VERSION 5.8 ;
BUSBITCHARS "[]" ;
DIVIDERCHAR "/" ;
UNITS
    DATABASE MICRONS 1000 ;
END UNITS

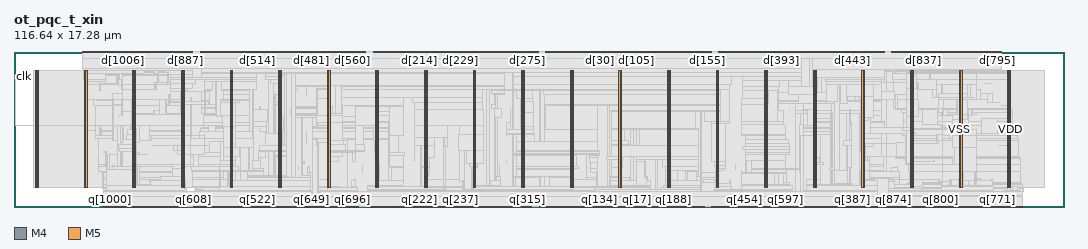
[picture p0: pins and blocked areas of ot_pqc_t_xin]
MACRO ot_pqc_t_xin
  FOREIGN ot_pqc_t_xin 0 0 ;
  CLASS BLOCK ;
  SIZE 116.64 BY 17.28 ;
  PIN clk
    DIRECTION INPUT ;
    USE SIGNAL ;
    PORT
      LAYER M4 ;
        RECT  0 14.448 0.084 14.472 ;
    END
    PORT
      LAYER M4 ;
        RECT  0.06 14.448 0.227 14.472 ;
    END
  END clk
  PIN d[0]
    DIRECTION INPUT ;
    USE SIGNAL ;
    PORT
      LAYER M5 ;
        RECT  62.16 17.196 62.184 17.28 ;
    END
  END d[0]
  PIN d[1000]
    DIRECTION INPUT ;
    USE SIGNAL ;
    PORT
      LAYER M5 ;
        RECT  11.472 17.196 11.496 17.28 ;
    END
  END d[1000]
  PIN d[1001]
    DIRECTION INPUT ;
    USE SIGNAL ;
    PORT
      LAYER M5 ;
        RECT  11.568 17.196 11.592 17.28 ;
    END
  END d[1001]
  PIN d[1002]
    DIRECTION INPUT ;
    USE SIGNAL ;
    PORT
      LAYER M5 ;
        RECT  11.664 17.196 11.688 17.28 ;
    END
  END d[1002]
  PIN d[1003]
    DIRECTION INPUT ;
    USE SIGNAL ;
    PORT
      LAYER M5 ;
        RECT  11.76 17.196 11.784 17.28 ;
    END
  END d[1003]
  PIN d[1004]
    DIRECTION INPUT ;
    USE SIGNAL ;
    PORT
      LAYER M5 ;
        RECT  11.856 17.196 11.88 17.28 ;
    END
  END d[1004]
  PIN d[1005]
    DIRECTION INPUT ;
    USE SIGNAL ;
    PORT
      LAYER M5 ;
        RECT  11.952 17.196 11.976 17.28 ;
    END
  END d[1005]
  PIN d[1006]
    DIRECTION INPUT ;
    USE SIGNAL ;
    PORT
      LAYER M5 ;
        RECT  12.048 17.196 12.072 17.28 ;
    END
  END d[1006]
  PIN d[1007]
    DIRECTION INPUT ;
    USE SIGNAL ;
    PORT
      LAYER M5 ;
        RECT  12.144 17.196 12.168 17.28 ;
    END
  END d[1007]
  PIN d[1008]
    DIRECTION INPUT ;
    USE SIGNAL ;
    PORT
      LAYER M5 ;
        RECT  12.24 17.196 12.264 17.28 ;
    END
  END d[1008]
  PIN d[1009]
    DIRECTION INPUT ;
    USE SIGNAL ;
    PORT
      LAYER M5 ;
        RECT  12.336 17.196 12.36 17.28 ;
    END
  END d[1009]
  PIN d[100]
    DIRECTION INPUT ;
    USE SIGNAL ;
    PORT
      LAYER M5 ;
        RECT  68.688 17.196 68.712 17.28 ;
    END
  END d[100]
  PIN d[1010]
    DIRECTION INPUT ;
    USE SIGNAL ;
    PORT
      LAYER M5 ;
        RECT  12.432 17.196 12.456 17.28 ;
    END
  END d[1010]
  PIN d[1011]
    DIRECTION INPUT ;
    USE SIGNAL ;
    PORT
      LAYER M5 ;
        RECT  12.528 17.196 12.552 17.28 ;
    END
  END d[1011]
  PIN d[1012]
    DIRECTION INPUT ;
    USE SIGNAL ;
    PORT
      LAYER M5 ;
        RECT  12.624 17.196 12.648 17.28 ;
    END
  END d[1012]
  PIN d[1013]
    DIRECTION INPUT ;
    USE SIGNAL ;
    PORT
      LAYER M5 ;
        RECT  12.72 17.196 12.744 17.28 ;
    END
  END d[1013]
  PIN d[1014]
    DIRECTION INPUT ;
    USE SIGNAL ;
    PORT
      LAYER M5 ;
        RECT  12.816 17.196 12.84 17.28 ;
    END
  END d[1014]
  PIN d[1015]
    DIRECTION INPUT ;
    USE SIGNAL ;
    PORT
      LAYER M5 ;
        RECT  12.912 17.196 12.936 17.28 ;
    END
  END d[1015]
  PIN d[1016]
    DIRECTION INPUT ;
    USE SIGNAL ;
    PORT
      LAYER M5 ;
        RECT  13.008 17.196 13.032 17.28 ;
    END
  END d[1016]
  PIN d[1017]
    DIRECTION INPUT ;
    USE SIGNAL ;
    PORT
      LAYER M5 ;
        RECT  13.104 17.196 13.128 17.28 ;
    END
  END d[1017]
  PIN d[1018]
    DIRECTION INPUT ;
    USE SIGNAL ;
    PORT
      LAYER M5 ;
        RECT  13.2 17.196 13.224 17.28 ;
    END
  END d[1018]
  PIN d[1019]
    DIRECTION INPUT ;
    USE SIGNAL ;
    PORT
      LAYER M5 ;
        RECT  13.296 17.196 13.32 17.28 ;
    END
  END d[1019]
  PIN d[101]
    DIRECTION INPUT ;
    USE SIGNAL ;
    PORT
      LAYER M5 ;
        RECT  68.784 17.196 68.808 17.28 ;
    END
  END d[101]
  PIN d[1020]
    DIRECTION INPUT ;
    USE SIGNAL ;
    PORT
      LAYER M5 ;
        RECT  13.392 17.196 13.416 17.28 ;
    END
  END d[1020]
  PIN d[1021]
    DIRECTION INPUT ;
    USE SIGNAL ;
    PORT
      LAYER M5 ;
        RECT  13.488 17.196 13.512 17.28 ;
    END
  END d[1021]
  PIN d[1022]
    DIRECTION INPUT ;
    USE SIGNAL ;
    PORT
      LAYER M5 ;
        RECT  13.584 17.196 13.608 17.28 ;
    END
  END d[1022]
  PIN d[1023]
    DIRECTION INPUT ;
    USE SIGNAL ;
    PORT
      LAYER M5 ;
        RECT  13.68 17.196 13.704 17.28 ;
    END
  END d[1023]
  PIN d[102]
    DIRECTION INPUT ;
    USE SIGNAL ;
    PORT
      LAYER M5 ;
        RECT  68.88 17.196 68.904 17.28 ;
    END
  END d[102]
  PIN d[103]
    DIRECTION INPUT ;
    USE SIGNAL ;
    PORT
      LAYER M5 ;
        RECT  68.976 17.196 69 17.28 ;
    END
  END d[103]
  PIN d[104]
    DIRECTION INPUT ;
    USE SIGNAL ;
    PORT
      LAYER M5 ;
        RECT  69.072 17.196 69.096 17.28 ;
    END
  END d[104]
  PIN d[105]
    DIRECTION INPUT ;
    USE SIGNAL ;
    PORT
      LAYER M5 ;
        RECT  69.168 17.196 69.192 17.28 ;
    END
  END d[105]
  PIN d[106]
    DIRECTION INPUT ;
    USE SIGNAL ;
    PORT
      LAYER M5 ;
        RECT  69.264 17.196 69.288 17.28 ;
    END
  END d[106]
  PIN d[107]
    DIRECTION INPUT ;
    USE SIGNAL ;
    PORT
      LAYER M5 ;
        RECT  69.36 17.196 69.384 17.28 ;
    END
  END d[107]
  PIN d[108]
    DIRECTION INPUT ;
    USE SIGNAL ;
    PORT
      LAYER M5 ;
        RECT  69.456 17.196 69.48 17.28 ;
    END
  END d[108]
  PIN d[109]
    DIRECTION INPUT ;
    USE SIGNAL ;
    PORT
      LAYER M5 ;
        RECT  69.552 17.196 69.576 17.28 ;
    END
  END d[109]
  PIN d[10]
    DIRECTION INPUT ;
    USE SIGNAL ;
    PORT
      LAYER M5 ;
        RECT  63.12 17.196 63.144 17.28 ;
    END
  END d[10]
  PIN d[110]
    DIRECTION INPUT ;
    USE SIGNAL ;
    PORT
      LAYER M5 ;
        RECT  69.648 17.196 69.672 17.28 ;
    END
  END d[110]
  PIN d[111]
    DIRECTION INPUT ;
    USE SIGNAL ;
    PORT
      LAYER M5 ;
        RECT  69.744 17.196 69.768 17.28 ;
    END
  END d[111]
  PIN d[112]
    DIRECTION INPUT ;
    USE SIGNAL ;
    PORT
      LAYER M5 ;
        RECT  69.84 17.196 69.864 17.28 ;
    END
  END d[112]
  PIN d[113]
    DIRECTION INPUT ;
    USE SIGNAL ;
    PORT
      LAYER M5 ;
        RECT  69.936 17.196 69.96 17.28 ;
    END
  END d[113]
  PIN d[114]
    DIRECTION INPUT ;
    USE SIGNAL ;
    PORT
      LAYER M5 ;
        RECT  70.032 17.196 70.056 17.28 ;
    END
  END d[114]
  PIN d[115]
    DIRECTION INPUT ;
    USE SIGNAL ;
    PORT
      LAYER M5 ;
        RECT  70.128 17.196 70.152 17.28 ;
    END
  END d[115]
  PIN d[116]
    DIRECTION INPUT ;
    USE SIGNAL ;
    PORT
      LAYER M5 ;
        RECT  70.224 17.196 70.248 17.28 ;
    END
  END d[116]
  PIN d[117]
    DIRECTION INPUT ;
    USE SIGNAL ;
    PORT
      LAYER M5 ;
        RECT  70.32 17.196 70.344 17.28 ;
    END
  END d[117]
  PIN d[118]
    DIRECTION INPUT ;
    USE SIGNAL ;
    PORT
      LAYER M5 ;
        RECT  70.416 17.196 70.44 17.28 ;
    END
  END d[118]
  PIN d[119]
    DIRECTION INPUT ;
    USE SIGNAL ;
    PORT
      LAYER M5 ;
        RECT  70.512 17.196 70.536 17.28 ;
    END
  END d[119]
  PIN d[11]
    DIRECTION INPUT ;
    USE SIGNAL ;
    PORT
      LAYER M5 ;
        RECT  63.216 17.196 63.24 17.28 ;
    END
  END d[11]
  PIN d[120]
    DIRECTION INPUT ;
    USE SIGNAL ;
    PORT
      LAYER M5 ;
        RECT  70.608 17.196 70.632 17.28 ;
    END
  END d[120]
  PIN d[121]
    DIRECTION INPUT ;
    USE SIGNAL ;
    PORT
      LAYER M5 ;
        RECT  70.704 17.196 70.728 17.28 ;
    END
  END d[121]
  PIN d[122]
    DIRECTION INPUT ;
    USE SIGNAL ;
    PORT
      LAYER M5 ;
        RECT  70.8 17.196 70.824 17.28 ;
    END
  END d[122]
  PIN d[123]
    DIRECTION INPUT ;
    USE SIGNAL ;
    PORT
      LAYER M5 ;
        RECT  70.896 17.196 70.92 17.28 ;
    END
  END d[123]
  PIN d[124]
    DIRECTION INPUT ;
    USE SIGNAL ;
    PORT
      LAYER M5 ;
        RECT  70.992 17.196 71.016 17.28 ;
    END
  END d[124]
  PIN d[125]
    DIRECTION INPUT ;
    USE SIGNAL ;
    PORT
      LAYER M5 ;
        RECT  71.088 17.196 71.112 17.28 ;
    END
  END d[125]
  PIN d[126]
    DIRECTION INPUT ;
    USE SIGNAL ;
    PORT
      LAYER M5 ;
        RECT  71.184 17.196 71.208 17.28 ;
    END
  END d[126]
  PIN d[127]
    DIRECTION INPUT ;
    USE SIGNAL ;
    PORT
      LAYER M5 ;
        RECT  71.28 17.196 71.304 17.28 ;
    END
  END d[127]
  PIN d[128]
    DIRECTION INPUT ;
    USE SIGNAL ;
    PORT
      LAYER M5 ;
        RECT  74.448 17.196 74.472 17.28 ;
    END
  END d[128]
  PIN d[129]
    DIRECTION INPUT ;
    USE SIGNAL ;
    PORT
      LAYER M5 ;
        RECT  74.544 17.196 74.568 17.28 ;
    END
  END d[129]
  PIN d[12]
    DIRECTION INPUT ;
    USE SIGNAL ;
    PORT
      LAYER M5 ;
        RECT  63.312 17.196 63.336 17.28 ;
    END
  END d[12]
  PIN d[130]
    DIRECTION INPUT ;
    USE SIGNAL ;
    PORT
      LAYER M5 ;
        RECT  74.64 17.196 74.664 17.28 ;
    END
  END d[130]
  PIN d[131]
    DIRECTION INPUT ;
    USE SIGNAL ;
    PORT
      LAYER M5 ;
        RECT  74.736 17.196 74.76 17.28 ;
    END
  END d[131]
  PIN d[132]
    DIRECTION INPUT ;
    USE SIGNAL ;
    PORT
      LAYER M5 ;
        RECT  74.832 17.196 74.856 17.28 ;
    END
  END d[132]
  PIN d[133]
    DIRECTION INPUT ;
    USE SIGNAL ;
    PORT
      LAYER M5 ;
        RECT  74.928 17.196 74.952 17.28 ;
    END
  END d[133]
  PIN d[134]
    DIRECTION INPUT ;
    USE SIGNAL ;
    PORT
      LAYER M5 ;
        RECT  75.024 17.196 75.048 17.28 ;
    END
  END d[134]
  PIN d[135]
    DIRECTION INPUT ;
    USE SIGNAL ;
    PORT
      LAYER M5 ;
        RECT  75.12 17.196 75.144 17.28 ;
    END
  END d[135]
  PIN d[136]
    DIRECTION INPUT ;
    USE SIGNAL ;
    PORT
      LAYER M5 ;
        RECT  75.216 17.196 75.24 17.28 ;
    END
  END d[136]
  PIN d[137]
    DIRECTION INPUT ;
    USE SIGNAL ;
    PORT
      LAYER M5 ;
        RECT  75.312 17.196 75.336 17.28 ;
    END
  END d[137]
  PIN d[138]
    DIRECTION INPUT ;
    USE SIGNAL ;
    PORT
      LAYER M5 ;
        RECT  75.408 17.196 75.432 17.28 ;
    END
  END d[138]
  PIN d[139]
    DIRECTION INPUT ;
    USE SIGNAL ;
    PORT
      LAYER M5 ;
        RECT  75.504 17.196 75.528 17.28 ;
    END
  END d[139]
  PIN d[13]
    DIRECTION INPUT ;
    USE SIGNAL ;
    PORT
      LAYER M5 ;
        RECT  63.408 17.196 63.432 17.28 ;
    END
  END d[13]
  PIN d[140]
    DIRECTION INPUT ;
    USE SIGNAL ;
    PORT
      LAYER M5 ;
        RECT  75.6 17.196 75.624 17.28 ;
    END
  END d[140]
  PIN d[141]
    DIRECTION INPUT ;
    USE SIGNAL ;
    PORT
      LAYER M5 ;
        RECT  75.696 17.196 75.72 17.28 ;
    END
  END d[141]
  PIN d[142]
    DIRECTION INPUT ;
    USE SIGNAL ;
    PORT
      LAYER M5 ;
        RECT  75.792 17.196 75.816 17.28 ;
    END
  END d[142]
  PIN d[143]
    DIRECTION INPUT ;
    USE SIGNAL ;
    PORT
      LAYER M5 ;
        RECT  75.888 17.196 75.912 17.28 ;
    END
  END d[143]
  PIN d[144]
    DIRECTION INPUT ;
    USE SIGNAL ;
    PORT
      LAYER M5 ;
        RECT  75.984 17.196 76.008 17.28 ;
    END
  END d[144]
  PIN d[145]
    DIRECTION INPUT ;
    USE SIGNAL ;
    PORT
      LAYER M5 ;
        RECT  76.08 17.196 76.104 17.28 ;
    END
  END d[145]
  PIN d[146]
    DIRECTION INPUT ;
    USE SIGNAL ;
    PORT
      LAYER M5 ;
        RECT  76.176 17.196 76.2 17.28 ;
    END
  END d[146]
  PIN d[147]
    DIRECTION INPUT ;
    USE SIGNAL ;
    PORT
      LAYER M5 ;
        RECT  76.272 17.196 76.296 17.28 ;
    END
  END d[147]
  PIN d[148]
    DIRECTION INPUT ;
    USE SIGNAL ;
    PORT
      LAYER M5 ;
        RECT  76.368 17.196 76.392 17.28 ;
    END
  END d[148]
  PIN d[149]
    DIRECTION INPUT ;
    USE SIGNAL ;
    PORT
      LAYER M5 ;
        RECT  76.464 17.196 76.488 17.28 ;
    END
  END d[149]
  PIN d[14]
    DIRECTION INPUT ;
    USE SIGNAL ;
    PORT
      LAYER M5 ;
        RECT  63.504 17.196 63.528 17.28 ;
    END
  END d[14]
  PIN d[150]
    DIRECTION INPUT ;
    USE SIGNAL ;
    PORT
      LAYER M5 ;
        RECT  76.56 17.196 76.584 17.28 ;
    END
  END d[150]
  PIN d[151]
    DIRECTION INPUT ;
    USE SIGNAL ;
    PORT
      LAYER M5 ;
        RECT  76.656 17.196 76.68 17.28 ;
    END
  END d[151]
  PIN d[152]
    DIRECTION INPUT ;
    USE SIGNAL ;
    PORT
      LAYER M5 ;
        RECT  76.752 17.196 76.776 17.28 ;
    END
  END d[152]
  PIN d[153]
    DIRECTION INPUT ;
    USE SIGNAL ;
    PORT
      LAYER M5 ;
        RECT  76.848 17.196 76.872 17.28 ;
    END
  END d[153]
  PIN d[154]
    DIRECTION INPUT ;
    USE SIGNAL ;
    PORT
      LAYER M5 ;
        RECT  76.944 17.196 76.968 17.28 ;
    END
  END d[154]
  PIN d[155]
    DIRECTION INPUT ;
    USE SIGNAL ;
    PORT
      LAYER M5 ;
        RECT  77.04 17.196 77.064 17.28 ;
    END
  END d[155]
  PIN d[156]
    DIRECTION INPUT ;
    USE SIGNAL ;
    PORT
      LAYER M5 ;
        RECT  77.136 17.196 77.16 17.28 ;
    END
  END d[156]
  PIN d[157]
    DIRECTION INPUT ;
    USE SIGNAL ;
    PORT
      LAYER M5 ;
        RECT  77.232 17.196 77.256 17.28 ;
    END
  END d[157]
  PIN d[158]
    DIRECTION INPUT ;
    USE SIGNAL ;
    PORT
      LAYER M5 ;
        RECT  77.328 17.196 77.352 17.28 ;
    END
  END d[158]
  PIN d[159]
    DIRECTION INPUT ;
    USE SIGNAL ;
    PORT
      LAYER M5 ;
        RECT  77.424 17.196 77.448 17.28 ;
    END
  END d[159]
  PIN d[15]
    DIRECTION INPUT ;
    USE SIGNAL ;
    PORT
      LAYER M5 ;
        RECT  63.6 17.196 63.624 17.28 ;
    END
  END d[15]
  PIN d[160]
    DIRECTION INPUT ;
    USE SIGNAL ;
    PORT
      LAYER M5 ;
        RECT  71.376 17.196 71.4 17.28 ;
    END
  END d[160]
  PIN d[161]
    DIRECTION INPUT ;
    USE SIGNAL ;
    PORT
      LAYER M5 ;
        RECT  71.472 17.196 71.496 17.28 ;
    END
  END d[161]
  PIN d[162]
    DIRECTION INPUT ;
    USE SIGNAL ;
    PORT
      LAYER M5 ;
        RECT  71.568 17.196 71.592 17.28 ;
    END
  END d[162]
  PIN d[163]
    DIRECTION INPUT ;
    USE SIGNAL ;
    PORT
      LAYER M5 ;
        RECT  71.664 17.196 71.688 17.28 ;
    END
  END d[163]
  PIN d[164]
    DIRECTION INPUT ;
    USE SIGNAL ;
    PORT
      LAYER M5 ;
        RECT  71.76 17.196 71.784 17.28 ;
    END
  END d[164]
  PIN d[165]
    DIRECTION INPUT ;
    USE SIGNAL ;
    PORT
      LAYER M5 ;
        RECT  71.856 17.196 71.88 17.28 ;
    END
  END d[165]
  PIN d[166]
    DIRECTION INPUT ;
    USE SIGNAL ;
    PORT
      LAYER M5 ;
        RECT  71.952 17.196 71.976 17.28 ;
    END
  END d[166]
  PIN d[167]
    DIRECTION INPUT ;
    USE SIGNAL ;
    PORT
      LAYER M5 ;
        RECT  72.048 17.196 72.072 17.28 ;
    END
  END d[167]
  PIN d[168]
    DIRECTION INPUT ;
    USE SIGNAL ;
    PORT
      LAYER M5 ;
        RECT  72.144 17.196 72.168 17.28 ;
    END
  END d[168]
  PIN d[169]
    DIRECTION INPUT ;
    USE SIGNAL ;
    PORT
      LAYER M5 ;
        RECT  72.24 17.196 72.264 17.28 ;
    END
  END d[169]
  PIN d[16]
    DIRECTION INPUT ;
    USE SIGNAL ;
    PORT
      LAYER M5 ;
        RECT  63.696 17.196 63.72 17.28 ;
    END
  END d[16]
  PIN d[170]
    DIRECTION INPUT ;
    USE SIGNAL ;
    PORT
      LAYER M5 ;
        RECT  72.336 17.196 72.36 17.28 ;
    END
  END d[170]
  PIN d[171]
    DIRECTION INPUT ;
    USE SIGNAL ;
    PORT
      LAYER M5 ;
        RECT  72.432 17.196 72.456 17.28 ;
    END
  END d[171]
  PIN d[172]
    DIRECTION INPUT ;
    USE SIGNAL ;
    PORT
      LAYER M5 ;
        RECT  72.528 17.196 72.552 17.28 ;
    END
  END d[172]
  PIN d[173]
    DIRECTION INPUT ;
    USE SIGNAL ;
    PORT
      LAYER M5 ;
        RECT  72.624 17.196 72.648 17.28 ;
    END
  END d[173]
  PIN d[174]
    DIRECTION INPUT ;
    USE SIGNAL ;
    PORT
      LAYER M5 ;
        RECT  72.72 17.196 72.744 17.28 ;
    END
  END d[174]
  PIN d[175]
    DIRECTION INPUT ;
    USE SIGNAL ;
    PORT
      LAYER M5 ;
        RECT  72.816 17.196 72.84 17.28 ;
    END
  END d[175]
  PIN d[176]
    DIRECTION INPUT ;
    USE SIGNAL ;
    PORT
      LAYER M5 ;
        RECT  72.912 17.196 72.936 17.28 ;
    END
  END d[176]
  PIN d[177]
    DIRECTION INPUT ;
    USE SIGNAL ;
    PORT
      LAYER M5 ;
        RECT  73.008 17.196 73.032 17.28 ;
    END
  END d[177]
  PIN d[178]
    DIRECTION INPUT ;
    USE SIGNAL ;
    PORT
      LAYER M5 ;
        RECT  73.104 17.196 73.128 17.28 ;
    END
  END d[178]
  PIN d[179]
    DIRECTION INPUT ;
    USE SIGNAL ;
    PORT
      LAYER M5 ;
        RECT  73.2 17.196 73.224 17.28 ;
    END
  END d[179]
  PIN d[17]
    DIRECTION INPUT ;
    USE SIGNAL ;
    PORT
      LAYER M5 ;
        RECT  63.792 17.196 63.816 17.28 ;
    END
  END d[17]
  PIN d[180]
    DIRECTION INPUT ;
    USE SIGNAL ;
    PORT
      LAYER M5 ;
        RECT  73.296 17.196 73.32 17.28 ;
    END
  END d[180]
  PIN d[181]
    DIRECTION INPUT ;
    USE SIGNAL ;
    PORT
      LAYER M5 ;
        RECT  73.392 17.196 73.416 17.28 ;
    END
  END d[181]
  PIN d[182]
    DIRECTION INPUT ;
    USE SIGNAL ;
    PORT
      LAYER M5 ;
        RECT  73.488 17.196 73.512 17.28 ;
    END
  END d[182]
  PIN d[183]
    DIRECTION INPUT ;
    USE SIGNAL ;
    PORT
      LAYER M5 ;
        RECT  73.584 17.196 73.608 17.28 ;
    END
  END d[183]
  PIN d[184]
    DIRECTION INPUT ;
    USE SIGNAL ;
    PORT
      LAYER M5 ;
        RECT  73.68 17.196 73.704 17.28 ;
    END
  END d[184]
  PIN d[185]
    DIRECTION INPUT ;
    USE SIGNAL ;
    PORT
      LAYER M5 ;
        RECT  73.776 17.196 73.8 17.28 ;
    END
  END d[185]
  PIN d[186]
    DIRECTION INPUT ;
    USE SIGNAL ;
    PORT
      LAYER M5 ;
        RECT  73.872 17.196 73.896 17.28 ;
    END
  END d[186]
  PIN d[187]
    DIRECTION INPUT ;
    USE SIGNAL ;
    PORT
      LAYER M5 ;
        RECT  73.968 17.196 73.992 17.28 ;
    END
  END d[187]
  PIN d[188]
    DIRECTION INPUT ;
    USE SIGNAL ;
    PORT
      LAYER M5 ;
        RECT  74.064 17.196 74.088 17.28 ;
    END
  END d[188]
  PIN d[189]
    DIRECTION INPUT ;
    USE SIGNAL ;
    PORT
      LAYER M5 ;
        RECT  74.16 17.196 74.184 17.28 ;
    END
  END d[189]
  PIN d[18]
    DIRECTION INPUT ;
    USE SIGNAL ;
    PORT
      LAYER M5 ;
        RECT  63.888 17.196 63.912 17.28 ;
    END
  END d[18]
  PIN d[190]
    DIRECTION INPUT ;
    USE SIGNAL ;
    PORT
      LAYER M5 ;
        RECT  74.256 17.196 74.28 17.28 ;
    END
  END d[190]
  PIN d[191]
    DIRECTION INPUT ;
    USE SIGNAL ;
    PORT
      LAYER M5 ;
        RECT  74.352 17.196 74.376 17.28 ;
    END
  END d[191]
  PIN d[192]
    DIRECTION INPUT ;
    USE SIGNAL ;
    PORT
      LAYER M5 ;
        RECT  42.96 17.196 42.984 17.28 ;
    END
  END d[192]
  PIN d[193]
    DIRECTION INPUT ;
    USE SIGNAL ;
    PORT
      LAYER M5 ;
        RECT  43.056 17.196 43.08 17.28 ;
    END
  END d[193]
  PIN d[194]
    DIRECTION INPUT ;
    USE SIGNAL ;
    PORT
      LAYER M5 ;
        RECT  43.152 17.196 43.176 17.28 ;
    END
  END d[194]
  PIN d[195]
    DIRECTION INPUT ;
    USE SIGNAL ;
    PORT
      LAYER M5 ;
        RECT  43.248 17.196 43.272 17.28 ;
    END
  END d[195]
  PIN d[196]
    DIRECTION INPUT ;
    USE SIGNAL ;
    PORT
      LAYER M5 ;
        RECT  43.344 17.196 43.368 17.28 ;
    END
  END d[196]
  PIN d[197]
    DIRECTION INPUT ;
    USE SIGNAL ;
    PORT
      LAYER M5 ;
        RECT  43.44 17.196 43.464 17.28 ;
    END
  END d[197]
  PIN d[198]
    DIRECTION INPUT ;
    USE SIGNAL ;
    PORT
      LAYER M5 ;
        RECT  43.536 17.196 43.56 17.28 ;
    END
  END d[198]
  PIN d[199]
    DIRECTION INPUT ;
    USE SIGNAL ;
    PORT
      LAYER M5 ;
        RECT  43.632 17.196 43.656 17.28 ;
    END
  END d[199]
  PIN d[19]
    DIRECTION INPUT ;
    USE SIGNAL ;
    PORT
      LAYER M5 ;
        RECT  63.984 17.196 64.008 17.28 ;
    END
  END d[19]
  PIN d[1]
    DIRECTION INPUT ;
    USE SIGNAL ;
    PORT
      LAYER M5 ;
        RECT  62.256 17.196 62.28 17.28 ;
    END
  END d[1]
  PIN d[200]
    DIRECTION INPUT ;
    USE SIGNAL ;
    PORT
      LAYER M5 ;
        RECT  43.728 17.196 43.752 17.28 ;
    END
  END d[200]
  PIN d[201]
    DIRECTION INPUT ;
    USE SIGNAL ;
    PORT
      LAYER M5 ;
        RECT  43.824 17.196 43.848 17.28 ;
    END
  END d[201]
  PIN d[202]
    DIRECTION INPUT ;
    USE SIGNAL ;
    PORT
      LAYER M5 ;
        RECT  43.92 17.196 43.944 17.28 ;
    END
  END d[202]
  PIN d[203]
    DIRECTION INPUT ;
    USE SIGNAL ;
    PORT
      LAYER M5 ;
        RECT  44.016 17.196 44.04 17.28 ;
    END
  END d[203]
  PIN d[204]
    DIRECTION INPUT ;
    USE SIGNAL ;
    PORT
      LAYER M5 ;
        RECT  44.112 17.196 44.136 17.28 ;
    END
  END d[204]
  PIN d[205]
    DIRECTION INPUT ;
    USE SIGNAL ;
    PORT
      LAYER M5 ;
        RECT  44.208 17.196 44.232 17.28 ;
    END
  END d[205]
  PIN d[206]
    DIRECTION INPUT ;
    USE SIGNAL ;
    PORT
      LAYER M5 ;
        RECT  44.304 17.196 44.328 17.28 ;
    END
  END d[206]
  PIN d[207]
    DIRECTION INPUT ;
    USE SIGNAL ;
    PORT
      LAYER M5 ;
        RECT  44.4 17.196 44.424 17.28 ;
    END
  END d[207]
  PIN d[208]
    DIRECTION INPUT ;
    USE SIGNAL ;
    PORT
      LAYER M5 ;
        RECT  44.496 17.196 44.52 17.28 ;
    END
  END d[208]
  PIN d[209]
    DIRECTION INPUT ;
    USE SIGNAL ;
    PORT
      LAYER M5 ;
        RECT  44.592 17.196 44.616 17.28 ;
    END
  END d[209]
  PIN d[20]
    DIRECTION INPUT ;
    USE SIGNAL ;
    PORT
      LAYER M5 ;
        RECT  64.08 17.196 64.104 17.28 ;
    END
  END d[20]
  PIN d[210]
    DIRECTION INPUT ;
    USE SIGNAL ;
    PORT
      LAYER M5 ;
        RECT  44.688 17.196 44.712 17.28 ;
    END
  END d[210]
  PIN d[211]
    DIRECTION INPUT ;
    USE SIGNAL ;
    PORT
      LAYER M5 ;
        RECT  44.784 17.196 44.808 17.28 ;
    END
  END d[211]
  PIN d[212]
    DIRECTION INPUT ;
    USE SIGNAL ;
    PORT
      LAYER M5 ;
        RECT  44.88 17.196 44.904 17.28 ;
    END
  END d[212]
  PIN d[213]
    DIRECTION INPUT ;
    USE SIGNAL ;
    PORT
      LAYER M5 ;
        RECT  44.976 17.196 45 17.28 ;
    END
  END d[213]
  PIN d[214]
    DIRECTION INPUT ;
    USE SIGNAL ;
    PORT
      LAYER M5 ;
        RECT  45.072 17.196 45.096 17.28 ;
    END
  END d[214]
  PIN d[215]
    DIRECTION INPUT ;
    USE SIGNAL ;
    PORT
      LAYER M5 ;
        RECT  45.168 17.196 45.192 17.28 ;
    END
  END d[215]
  PIN d[216]
    DIRECTION INPUT ;
    USE SIGNAL ;
    PORT
      LAYER M5 ;
        RECT  45.264 17.196 45.288 17.28 ;
    END
  END d[216]
  PIN d[217]
    DIRECTION INPUT ;
    USE SIGNAL ;
    PORT
      LAYER M5 ;
        RECT  45.36 17.196 45.384 17.28 ;
    END
  END d[217]
  PIN d[218]
    DIRECTION INPUT ;
    USE SIGNAL ;
    PORT
      LAYER M5 ;
        RECT  45.456 17.196 45.48 17.28 ;
    END
  END d[218]
  PIN d[219]
    DIRECTION INPUT ;
    USE SIGNAL ;
    PORT
      LAYER M5 ;
        RECT  45.552 17.196 45.576 17.28 ;
    END
  END d[219]
  PIN d[21]
    DIRECTION INPUT ;
    USE SIGNAL ;
    PORT
      LAYER M5 ;
        RECT  64.176 17.196 64.2 17.28 ;
    END
  END d[21]
  PIN d[220]
    DIRECTION INPUT ;
    USE SIGNAL ;
    PORT
      LAYER M5 ;
        RECT  45.648 17.196 45.672 17.28 ;
    END
  END d[220]
  PIN d[221]
    DIRECTION INPUT ;
    USE SIGNAL ;
    PORT
      LAYER M5 ;
        RECT  45.744 17.196 45.768 17.28 ;
    END
  END d[221]
  PIN d[222]
    DIRECTION INPUT ;
    USE SIGNAL ;
    PORT
      LAYER M5 ;
        RECT  45.84 17.196 45.864 17.28 ;
    END
  END d[222]
  PIN d[223]
    DIRECTION INPUT ;
    USE SIGNAL ;
    PORT
      LAYER M5 ;
        RECT  45.936 17.196 45.96 17.28 ;
    END
  END d[223]
  PIN d[224]
    DIRECTION INPUT ;
    USE SIGNAL ;
    PORT
      LAYER M5 ;
        RECT  49.104 17.196 49.128 17.28 ;
    END
  END d[224]
  PIN d[225]
    DIRECTION INPUT ;
    USE SIGNAL ;
    PORT
      LAYER M5 ;
        RECT  49.2 17.196 49.224 17.28 ;
    END
  END d[225]
  PIN d[226]
    DIRECTION INPUT ;
    USE SIGNAL ;
    PORT
      LAYER M5 ;
        RECT  49.296 17.196 49.32 17.28 ;
    END
  END d[226]
  PIN d[227]
    DIRECTION INPUT ;
    USE SIGNAL ;
    PORT
      LAYER M5 ;
        RECT  49.392 17.196 49.416 17.28 ;
    END
  END d[227]
  PIN d[228]
    DIRECTION INPUT ;
    USE SIGNAL ;
    PORT
      LAYER M5 ;
        RECT  49.488 17.196 49.512 17.28 ;
    END
  END d[228]
  PIN d[229]
    DIRECTION INPUT ;
    USE SIGNAL ;
    PORT
      LAYER M5 ;
        RECT  49.584 17.196 49.608 17.28 ;
    END
  END d[229]
  PIN d[22]
    DIRECTION INPUT ;
    USE SIGNAL ;
    PORT
      LAYER M5 ;
        RECT  64.272 17.196 64.296 17.28 ;
    END
  END d[22]
  PIN d[230]
    DIRECTION INPUT ;
    USE SIGNAL ;
    PORT
      LAYER M5 ;
        RECT  49.68 17.196 49.704 17.28 ;
    END
  END d[230]
  PIN d[231]
    DIRECTION INPUT ;
    USE SIGNAL ;
    PORT
      LAYER M5 ;
        RECT  49.776 17.196 49.8 17.28 ;
    END
  END d[231]
  PIN d[232]
    DIRECTION INPUT ;
    USE SIGNAL ;
    PORT
      LAYER M5 ;
        RECT  49.872 17.196 49.896 17.28 ;
    END
  END d[232]
  PIN d[233]
    DIRECTION INPUT ;
    USE SIGNAL ;
    PORT
      LAYER M5 ;
        RECT  49.968 17.196 49.992 17.28 ;
    END
  END d[233]
  PIN d[234]
    DIRECTION INPUT ;
    USE SIGNAL ;
    PORT
      LAYER M5 ;
        RECT  50.064 17.196 50.088 17.28 ;
    END
  END d[234]
  PIN d[235]
    DIRECTION INPUT ;
    USE SIGNAL ;
    PORT
      LAYER M5 ;
        RECT  50.16 17.196 50.184 17.28 ;
    END
  END d[235]
  PIN d[236]
    DIRECTION INPUT ;
    USE SIGNAL ;
    PORT
      LAYER M5 ;
        RECT  50.256 17.196 50.28 17.28 ;
    END
  END d[236]
  PIN d[237]
    DIRECTION INPUT ;
    USE SIGNAL ;
    PORT
      LAYER M5 ;
        RECT  50.352 17.196 50.376 17.28 ;
    END
  END d[237]
  PIN d[238]
    DIRECTION INPUT ;
    USE SIGNAL ;
    PORT
      LAYER M5 ;
        RECT  50.448 17.196 50.472 17.28 ;
    END
  END d[238]
  PIN d[239]
    DIRECTION INPUT ;
    USE SIGNAL ;
    PORT
      LAYER M5 ;
        RECT  50.544 17.196 50.568 17.28 ;
    END
  END d[239]
  PIN d[23]
    DIRECTION INPUT ;
    USE SIGNAL ;
    PORT
      LAYER M5 ;
        RECT  64.368 17.196 64.392 17.28 ;
    END
  END d[23]
  PIN d[240]
    DIRECTION INPUT ;
    USE SIGNAL ;
    PORT
      LAYER M5 ;
        RECT  50.64 17.196 50.664 17.28 ;
    END
  END d[240]
  PIN d[241]
    DIRECTION INPUT ;
    USE SIGNAL ;
    PORT
      LAYER M5 ;
        RECT  50.736 17.196 50.76 17.28 ;
    END
  END d[241]
  PIN d[242]
    DIRECTION INPUT ;
    USE SIGNAL ;
    PORT
      LAYER M5 ;
        RECT  50.832 17.196 50.856 17.28 ;
    END
  END d[242]
  PIN d[243]
    DIRECTION INPUT ;
    USE SIGNAL ;
    PORT
      LAYER M5 ;
        RECT  50.928 17.196 50.952 17.28 ;
    END
  END d[243]
  PIN d[244]
    DIRECTION INPUT ;
    USE SIGNAL ;
    PORT
      LAYER M5 ;
        RECT  51.024 17.196 51.048 17.28 ;
    END
  END d[244]
  PIN d[245]
    DIRECTION INPUT ;
    USE SIGNAL ;
    PORT
      LAYER M5 ;
        RECT  51.12 17.196 51.144 17.28 ;
    END
  END d[245]
  PIN d[246]
    DIRECTION INPUT ;
    USE SIGNAL ;
    PORT
      LAYER M5 ;
        RECT  51.216 17.196 51.24 17.28 ;
    END
  END d[246]
  PIN d[247]
    DIRECTION INPUT ;
    USE SIGNAL ;
    PORT
      LAYER M5 ;
        RECT  51.312 17.196 51.336 17.28 ;
    END
  END d[247]
  PIN d[248]
    DIRECTION INPUT ;
    USE SIGNAL ;
    PORT
      LAYER M5 ;
        RECT  51.408 17.196 51.432 17.28 ;
    END
  END d[248]
  PIN d[249]
    DIRECTION INPUT ;
    USE SIGNAL ;
    PORT
      LAYER M5 ;
        RECT  51.504 17.196 51.528 17.28 ;
    END
  END d[249]
  PIN d[24]
    DIRECTION INPUT ;
    USE SIGNAL ;
    PORT
      LAYER M5 ;
        RECT  64.464 17.196 64.488 17.28 ;
    END
  END d[24]
  PIN d[250]
    DIRECTION INPUT ;
    USE SIGNAL ;
    PORT
      LAYER M5 ;
        RECT  51.6 17.196 51.624 17.28 ;
    END
  END d[250]
  PIN d[251]
    DIRECTION INPUT ;
    USE SIGNAL ;
    PORT
      LAYER M5 ;
        RECT  51.696 17.196 51.72 17.28 ;
    END
  END d[251]
  PIN d[252]
    DIRECTION INPUT ;
    USE SIGNAL ;
    PORT
      LAYER M5 ;
        RECT  51.792 17.196 51.816 17.28 ;
    END
  END d[252]
  PIN d[253]
    DIRECTION INPUT ;
    USE SIGNAL ;
    PORT
      LAYER M5 ;
        RECT  51.888 17.196 51.912 17.28 ;
    END
  END d[253]
  PIN d[254]
    DIRECTION INPUT ;
    USE SIGNAL ;
    PORT
      LAYER M5 ;
        RECT  51.984 17.196 52.008 17.28 ;
    END
  END d[254]
  PIN d[255]
    DIRECTION INPUT ;
    USE SIGNAL ;
    PORT
      LAYER M5 ;
        RECT  52.08 17.196 52.104 17.28 ;
    END
  END d[255]
  PIN d[256]
    DIRECTION INPUT ;
    USE SIGNAL ;
    PORT
      LAYER M5 ;
        RECT  55.248 17.196 55.272 17.28 ;
    END
  END d[256]
  PIN d[257]
    DIRECTION INPUT ;
    USE SIGNAL ;
    PORT
      LAYER M5 ;
        RECT  55.344 17.196 55.368 17.28 ;
    END
  END d[257]
  PIN d[258]
    DIRECTION INPUT ;
    USE SIGNAL ;
    PORT
      LAYER M5 ;
        RECT  55.44 17.196 55.464 17.28 ;
    END
  END d[258]
  PIN d[259]
    DIRECTION INPUT ;
    USE SIGNAL ;
    PORT
      LAYER M5 ;
        RECT  55.536 17.196 55.56 17.28 ;
    END
  END d[259]
  PIN d[25]
    DIRECTION INPUT ;
    USE SIGNAL ;
    PORT
      LAYER M5 ;
        RECT  64.56 17.196 64.584 17.28 ;
    END
  END d[25]
  PIN d[260]
    DIRECTION INPUT ;
    USE SIGNAL ;
    PORT
      LAYER M5 ;
        RECT  55.632 17.196 55.656 17.28 ;
    END
  END d[260]
  PIN d[261]
    DIRECTION INPUT ;
    USE SIGNAL ;
    PORT
      LAYER M5 ;
        RECT  55.728 17.196 55.752 17.28 ;
    END
  END d[261]
  PIN d[262]
    DIRECTION INPUT ;
    USE SIGNAL ;
    PORT
      LAYER M5 ;
        RECT  55.824 17.196 55.848 17.28 ;
    END
  END d[262]
  PIN d[263]
    DIRECTION INPUT ;
    USE SIGNAL ;
    PORT
      LAYER M5 ;
        RECT  55.92 17.196 55.944 17.28 ;
    END
  END d[263]
  PIN d[264]
    DIRECTION INPUT ;
    USE SIGNAL ;
    PORT
      LAYER M5 ;
        RECT  56.016 17.196 56.04 17.28 ;
    END
  END d[264]
  PIN d[265]
    DIRECTION INPUT ;
    USE SIGNAL ;
    PORT
      LAYER M5 ;
        RECT  56.112 17.196 56.136 17.28 ;
    END
  END d[265]
  PIN d[266]
    DIRECTION INPUT ;
    USE SIGNAL ;
    PORT
      LAYER M5 ;
        RECT  56.208 17.196 56.232 17.28 ;
    END
  END d[266]
  PIN d[267]
    DIRECTION INPUT ;
    USE SIGNAL ;
    PORT
      LAYER M5 ;
        RECT  56.304 17.196 56.328 17.28 ;
    END
  END d[267]
  PIN d[268]
    DIRECTION INPUT ;
    USE SIGNAL ;
    PORT
      LAYER M5 ;
        RECT  56.4 17.196 56.424 17.28 ;
    END
  END d[268]
  PIN d[269]
    DIRECTION INPUT ;
    USE SIGNAL ;
    PORT
      LAYER M5 ;
        RECT  56.496 17.196 56.52 17.28 ;
    END
  END d[269]
  PIN d[26]
    DIRECTION INPUT ;
    USE SIGNAL ;
    PORT
      LAYER M5 ;
        RECT  64.656 17.196 64.68 17.28 ;
    END
  END d[26]
  PIN d[270]
    DIRECTION INPUT ;
    USE SIGNAL ;
    PORT
      LAYER M5 ;
        RECT  56.592 17.196 56.616 17.28 ;
    END
  END d[270]
  PIN d[271]
    DIRECTION INPUT ;
    USE SIGNAL ;
    PORT
      LAYER M5 ;
        RECT  56.688 17.196 56.712 17.28 ;
    END
  END d[271]
  PIN d[272]
    DIRECTION INPUT ;
    USE SIGNAL ;
    PORT
      LAYER M5 ;
        RECT  56.784 17.196 56.808 17.28 ;
    END
  END d[272]
  PIN d[273]
    DIRECTION INPUT ;
    USE SIGNAL ;
    PORT
      LAYER M5 ;
        RECT  56.88 17.196 56.904 17.28 ;
    END
  END d[273]
  PIN d[274]
    DIRECTION INPUT ;
    USE SIGNAL ;
    PORT
      LAYER M5 ;
        RECT  56.976 17.196 57 17.28 ;
    END
  END d[274]
  PIN d[275]
    DIRECTION INPUT ;
    USE SIGNAL ;
    PORT
      LAYER M5 ;
        RECT  57.072 17.196 57.096 17.28 ;
    END
  END d[275]
  PIN d[276]
    DIRECTION INPUT ;
    USE SIGNAL ;
    PORT
      LAYER M5 ;
        RECT  57.168 17.196 57.192 17.28 ;
    END
  END d[276]
  PIN d[277]
    DIRECTION INPUT ;
    USE SIGNAL ;
    PORT
      LAYER M5 ;
        RECT  57.264 17.196 57.288 17.28 ;
    END
  END d[277]
  PIN d[278]
    DIRECTION INPUT ;
    USE SIGNAL ;
    PORT
      LAYER M5 ;
        RECT  57.36 17.196 57.384 17.28 ;
    END
  END d[278]
  PIN d[279]
    DIRECTION INPUT ;
    USE SIGNAL ;
    PORT
      LAYER M5 ;
        RECT  57.456 17.196 57.48 17.28 ;
    END
  END d[279]
  PIN d[27]
    DIRECTION INPUT ;
    USE SIGNAL ;
    PORT
      LAYER M5 ;
        RECT  64.752 17.196 64.776 17.28 ;
    END
  END d[27]
  PIN d[280]
    DIRECTION INPUT ;
    USE SIGNAL ;
    PORT
      LAYER M5 ;
        RECT  57.552 17.196 57.576 17.28 ;
    END
  END d[280]
  PIN d[281]
    DIRECTION INPUT ;
    USE SIGNAL ;
    PORT
      LAYER M5 ;
        RECT  57.648 17.196 57.672 17.28 ;
    END
  END d[281]
  PIN d[282]
    DIRECTION INPUT ;
    USE SIGNAL ;
    PORT
      LAYER M5 ;
        RECT  57.744 17.196 57.768 17.28 ;
    END
  END d[282]
  PIN d[283]
    DIRECTION INPUT ;
    USE SIGNAL ;
    PORT
      LAYER M5 ;
        RECT  57.84 17.196 57.864 17.28 ;
    END
  END d[283]
  PIN d[284]
    DIRECTION INPUT ;
    USE SIGNAL ;
    PORT
      LAYER M5 ;
        RECT  57.936 17.196 57.96 17.28 ;
    END
  END d[284]
  PIN d[285]
    DIRECTION INPUT ;
    USE SIGNAL ;
    PORT
      LAYER M5 ;
        RECT  58.032 17.196 58.056 17.28 ;
    END
  END d[285]
  PIN d[286]
    DIRECTION INPUT ;
    USE SIGNAL ;
    PORT
      LAYER M5 ;
        RECT  58.128 17.196 58.152 17.28 ;
    END
  END d[286]
  PIN d[287]
    DIRECTION INPUT ;
    USE SIGNAL ;
    PORT
      LAYER M5 ;
        RECT  58.224 17.196 58.248 17.28 ;
    END
  END d[287]
  PIN d[288]
    DIRECTION INPUT ;
    USE SIGNAL ;
    PORT
      LAYER M5 ;
        RECT  59.088 17.196 59.112 17.28 ;
    END
  END d[288]
  PIN d[289]
    DIRECTION INPUT ;
    USE SIGNAL ;
    PORT
      LAYER M5 ;
        RECT  59.184 17.196 59.208 17.28 ;
    END
  END d[289]
  PIN d[28]
    DIRECTION INPUT ;
    USE SIGNAL ;
    PORT
      LAYER M5 ;
        RECT  64.848 17.196 64.872 17.28 ;
    END
  END d[28]
  PIN d[290]
    DIRECTION INPUT ;
    USE SIGNAL ;
    PORT
      LAYER M5 ;
        RECT  59.28 17.196 59.304 17.28 ;
    END
  END d[290]
  PIN d[291]
    DIRECTION INPUT ;
    USE SIGNAL ;
    PORT
      LAYER M5 ;
        RECT  59.376 17.196 59.4 17.28 ;
    END
  END d[291]
  PIN d[292]
    DIRECTION INPUT ;
    USE SIGNAL ;
    PORT
      LAYER M5 ;
        RECT  59.472 17.196 59.496 17.28 ;
    END
  END d[292]
  PIN d[293]
    DIRECTION INPUT ;
    USE SIGNAL ;
    PORT
      LAYER M5 ;
        RECT  59.568 17.196 59.592 17.28 ;
    END
  END d[293]
  PIN d[294]
    DIRECTION INPUT ;
    USE SIGNAL ;
    PORT
      LAYER M5 ;
        RECT  59.664 17.196 59.688 17.28 ;
    END
  END d[294]
  PIN d[295]
    DIRECTION INPUT ;
    USE SIGNAL ;
    PORT
      LAYER M5 ;
        RECT  59.76 17.196 59.784 17.28 ;
    END
  END d[295]
  PIN d[296]
    DIRECTION INPUT ;
    USE SIGNAL ;
    PORT
      LAYER M5 ;
        RECT  59.856 17.196 59.88 17.28 ;
    END
  END d[296]
  PIN d[297]
    DIRECTION INPUT ;
    USE SIGNAL ;
    PORT
      LAYER M5 ;
        RECT  59.952 17.196 59.976 17.28 ;
    END
  END d[297]
  PIN d[298]
    DIRECTION INPUT ;
    USE SIGNAL ;
    PORT
      LAYER M5 ;
        RECT  60.048 17.196 60.072 17.28 ;
    END
  END d[298]
  PIN d[299]
    DIRECTION INPUT ;
    USE SIGNAL ;
    PORT
      LAYER M5 ;
        RECT  60.144 17.196 60.168 17.28 ;
    END
  END d[299]
  PIN d[29]
    DIRECTION INPUT ;
    USE SIGNAL ;
    PORT
      LAYER M5 ;
        RECT  64.944 17.196 64.968 17.28 ;
    END
  END d[29]
  PIN d[2]
    DIRECTION INPUT ;
    USE SIGNAL ;
    PORT
      LAYER M5 ;
        RECT  62.352 17.196 62.376 17.28 ;
    END
  END d[2]
  PIN d[300]
    DIRECTION INPUT ;
    USE SIGNAL ;
    PORT
      LAYER M5 ;
        RECT  60.24 17.196 60.264 17.28 ;
    END
  END d[300]
  PIN d[301]
    DIRECTION INPUT ;
    USE SIGNAL ;
    PORT
      LAYER M5 ;
        RECT  60.336 17.196 60.36 17.28 ;
    END
  END d[301]
  PIN d[302]
    DIRECTION INPUT ;
    USE SIGNAL ;
    PORT
      LAYER M5 ;
        RECT  60.432 17.196 60.456 17.28 ;
    END
  END d[302]
  PIN d[303]
    DIRECTION INPUT ;
    USE SIGNAL ;
    PORT
      LAYER M5 ;
        RECT  60.528 17.196 60.552 17.28 ;
    END
  END d[303]
  PIN d[304]
    DIRECTION INPUT ;
    USE SIGNAL ;
    PORT
      LAYER M5 ;
        RECT  60.624 17.196 60.648 17.28 ;
    END
  END d[304]
  PIN d[305]
    DIRECTION INPUT ;
    USE SIGNAL ;
    PORT
      LAYER M5 ;
        RECT  60.72 17.196 60.744 17.28 ;
    END
  END d[305]
  PIN d[306]
    DIRECTION INPUT ;
    USE SIGNAL ;
    PORT
      LAYER M5 ;
        RECT  60.816 17.196 60.84 17.28 ;
    END
  END d[306]
  PIN d[307]
    DIRECTION INPUT ;
    USE SIGNAL ;
    PORT
      LAYER M5 ;
        RECT  60.912 17.196 60.936 17.28 ;
    END
  END d[307]
  PIN d[308]
    DIRECTION INPUT ;
    USE SIGNAL ;
    PORT
      LAYER M5 ;
        RECT  61.008 17.196 61.032 17.28 ;
    END
  END d[308]
  PIN d[309]
    DIRECTION INPUT ;
    USE SIGNAL ;
    PORT
      LAYER M5 ;
        RECT  61.104 17.196 61.128 17.28 ;
    END
  END d[309]
  PIN d[30]
    DIRECTION INPUT ;
    USE SIGNAL ;
    PORT
      LAYER M5 ;
        RECT  65.04 17.196 65.064 17.28 ;
    END
  END d[30]
  PIN d[310]
    DIRECTION INPUT ;
    USE SIGNAL ;
    PORT
      LAYER M5 ;
        RECT  61.2 17.196 61.224 17.28 ;
    END
  END d[310]
  PIN d[311]
    DIRECTION INPUT ;
    USE SIGNAL ;
    PORT
      LAYER M5 ;
        RECT  61.296 17.196 61.32 17.28 ;
    END
  END d[311]
  PIN d[312]
    DIRECTION INPUT ;
    USE SIGNAL ;
    PORT
      LAYER M5 ;
        RECT  61.392 17.196 61.416 17.28 ;
    END
  END d[312]
  PIN d[313]
    DIRECTION INPUT ;
    USE SIGNAL ;
    PORT
      LAYER M5 ;
        RECT  61.488 17.196 61.512 17.28 ;
    END
  END d[313]
  PIN d[314]
    DIRECTION INPUT ;
    USE SIGNAL ;
    PORT
      LAYER M5 ;
        RECT  61.584 17.196 61.608 17.28 ;
    END
  END d[314]
  PIN d[315]
    DIRECTION INPUT ;
    USE SIGNAL ;
    PORT
      LAYER M5 ;
        RECT  61.68 17.196 61.704 17.28 ;
    END
  END d[315]
  PIN d[316]
    DIRECTION INPUT ;
    USE SIGNAL ;
    PORT
      LAYER M5 ;
        RECT  61.776 17.196 61.8 17.28 ;
    END
  END d[316]
  PIN d[317]
    DIRECTION INPUT ;
    USE SIGNAL ;
    PORT
      LAYER M5 ;
        RECT  61.872 17.196 61.896 17.28 ;
    END
  END d[317]
  PIN d[318]
    DIRECTION INPUT ;
    USE SIGNAL ;
    PORT
      LAYER M5 ;
        RECT  61.968 17.196 61.992 17.28 ;
    END
  END d[318]
  PIN d[319]
    DIRECTION INPUT ;
    USE SIGNAL ;
    PORT
      LAYER M5 ;
        RECT  62.064 17.196 62.088 17.28 ;
    END
  END d[319]
  PIN d[31]
    DIRECTION INPUT ;
    USE SIGNAL ;
    PORT
      LAYER M5 ;
        RECT  65.136 17.196 65.16 17.28 ;
    END
  END d[31]
  PIN d[320]
    DIRECTION INPUT ;
    USE SIGNAL ;
    PORT
      LAYER M5 ;
        RECT  65.232 17.196 65.256 17.28 ;
    END
  END d[320]
  PIN d[321]
    DIRECTION INPUT ;
    USE SIGNAL ;
    PORT
      LAYER M5 ;
        RECT  65.328 17.196 65.352 17.28 ;
    END
  END d[321]
  PIN d[322]
    DIRECTION INPUT ;
    USE SIGNAL ;
    PORT
      LAYER M5 ;
        RECT  65.424 17.196 65.448 17.28 ;
    END
  END d[322]
  PIN d[323]
    DIRECTION INPUT ;
    USE SIGNAL ;
    PORT
      LAYER M5 ;
        RECT  65.52 17.196 65.544 17.28 ;
    END
  END d[323]
  PIN d[324]
    DIRECTION INPUT ;
    USE SIGNAL ;
    PORT
      LAYER M5 ;
        RECT  65.616 17.196 65.64 17.28 ;
    END
  END d[324]
  PIN d[325]
    DIRECTION INPUT ;
    USE SIGNAL ;
    PORT
      LAYER M5 ;
        RECT  65.712 17.196 65.736 17.28 ;
    END
  END d[325]
  PIN d[326]
    DIRECTION INPUT ;
    USE SIGNAL ;
    PORT
      LAYER M5 ;
        RECT  65.808 17.196 65.832 17.28 ;
    END
  END d[326]
  PIN d[327]
    DIRECTION INPUT ;
    USE SIGNAL ;
    PORT
      LAYER M5 ;
        RECT  65.904 17.196 65.928 17.28 ;
    END
  END d[327]
  PIN d[328]
    DIRECTION INPUT ;
    USE SIGNAL ;
    PORT
      LAYER M5 ;
        RECT  66 17.196 66.024 17.28 ;
    END
  END d[328]
  PIN d[329]
    DIRECTION INPUT ;
    USE SIGNAL ;
    PORT
      LAYER M5 ;
        RECT  66.096 17.196 66.12 17.28 ;
    END
  END d[329]
  PIN d[32]
    DIRECTION INPUT ;
    USE SIGNAL ;
    PORT
      LAYER M5 ;
        RECT  52.176 17.196 52.2 17.28 ;
    END
  END d[32]
  PIN d[330]
    DIRECTION INPUT ;
    USE SIGNAL ;
    PORT
      LAYER M5 ;
        RECT  66.192 17.196 66.216 17.28 ;
    END
  END d[330]
  PIN d[331]
    DIRECTION INPUT ;
    USE SIGNAL ;
    PORT
      LAYER M5 ;
        RECT  66.288 17.196 66.312 17.28 ;
    END
  END d[331]
  PIN d[332]
    DIRECTION INPUT ;
    USE SIGNAL ;
    PORT
      LAYER M5 ;
        RECT  66.384 17.196 66.408 17.28 ;
    END
  END d[332]
  PIN d[333]
    DIRECTION INPUT ;
    USE SIGNAL ;
    PORT
      LAYER M5 ;
        RECT  66.48 17.196 66.504 17.28 ;
    END
  END d[333]
  PIN d[334]
    DIRECTION INPUT ;
    USE SIGNAL ;
    PORT
      LAYER M5 ;
        RECT  66.576 17.196 66.6 17.28 ;
    END
  END d[334]
  PIN d[335]
    DIRECTION INPUT ;
    USE SIGNAL ;
    PORT
      LAYER M5 ;
        RECT  66.672 17.196 66.696 17.28 ;
    END
  END d[335]
  PIN d[336]
    DIRECTION INPUT ;
    USE SIGNAL ;
    PORT
      LAYER M5 ;
        RECT  66.768 17.196 66.792 17.28 ;
    END
  END d[336]
  PIN d[337]
    DIRECTION INPUT ;
    USE SIGNAL ;
    PORT
      LAYER M5 ;
        RECT  66.864 17.196 66.888 17.28 ;
    END
  END d[337]
  PIN d[338]
    DIRECTION INPUT ;
    USE SIGNAL ;
    PORT
      LAYER M5 ;
        RECT  66.96 17.196 66.984 17.28 ;
    END
  END d[338]
  PIN d[339]
    DIRECTION INPUT ;
    USE SIGNAL ;
    PORT
      LAYER M5 ;
        RECT  67.056 17.196 67.08 17.28 ;
    END
  END d[339]
  PIN d[33]
    DIRECTION INPUT ;
    USE SIGNAL ;
    PORT
      LAYER M5 ;
        RECT  52.272 17.196 52.296 17.28 ;
    END
  END d[33]
  PIN d[340]
    DIRECTION INPUT ;
    USE SIGNAL ;
    PORT
      LAYER M5 ;
        RECT  67.152 17.196 67.176 17.28 ;
    END
  END d[340]
  PIN d[341]
    DIRECTION INPUT ;
    USE SIGNAL ;
    PORT
      LAYER M5 ;
        RECT  67.248 17.196 67.272 17.28 ;
    END
  END d[341]
  PIN d[342]
    DIRECTION INPUT ;
    USE SIGNAL ;
    PORT
      LAYER M5 ;
        RECT  67.344 17.196 67.368 17.28 ;
    END
  END d[342]
  PIN d[343]
    DIRECTION INPUT ;
    USE SIGNAL ;
    PORT
      LAYER M5 ;
        RECT  67.44 17.196 67.464 17.28 ;
    END
  END d[343]
  PIN d[344]
    DIRECTION INPUT ;
    USE SIGNAL ;
    PORT
      LAYER M5 ;
        RECT  67.536 17.196 67.56 17.28 ;
    END
  END d[344]
  PIN d[345]
    DIRECTION INPUT ;
    USE SIGNAL ;
    PORT
      LAYER M5 ;
        RECT  67.632 17.196 67.656 17.28 ;
    END
  END d[345]
  PIN d[346]
    DIRECTION INPUT ;
    USE SIGNAL ;
    PORT
      LAYER M5 ;
        RECT  67.728 17.196 67.752 17.28 ;
    END
  END d[346]
  PIN d[347]
    DIRECTION INPUT ;
    USE SIGNAL ;
    PORT
      LAYER M5 ;
        RECT  67.824 17.196 67.848 17.28 ;
    END
  END d[347]
  PIN d[348]
    DIRECTION INPUT ;
    USE SIGNAL ;
    PORT
      LAYER M5 ;
        RECT  67.92 17.196 67.944 17.28 ;
    END
  END d[348]
  PIN d[349]
    DIRECTION INPUT ;
    USE SIGNAL ;
    PORT
      LAYER M5 ;
        RECT  68.016 17.196 68.04 17.28 ;
    END
  END d[349]
  PIN d[34]
    DIRECTION INPUT ;
    USE SIGNAL ;
    PORT
      LAYER M5 ;
        RECT  52.368 17.196 52.392 17.28 ;
    END
  END d[34]
  PIN d[350]
    DIRECTION INPUT ;
    USE SIGNAL ;
    PORT
      LAYER M5 ;
        RECT  68.112 17.196 68.136 17.28 ;
    END
  END d[350]
  PIN d[351]
    DIRECTION INPUT ;
    USE SIGNAL ;
    PORT
      LAYER M5 ;
        RECT  68.208 17.196 68.232 17.28 ;
    END
  END d[351]
  PIN d[352]
    DIRECTION INPUT ;
    USE SIGNAL ;
    PORT
      LAYER M5 ;
        RECT  39.888 17.196 39.912 17.28 ;
    END
  END d[352]
  PIN d[353]
    DIRECTION INPUT ;
    USE SIGNAL ;
    PORT
      LAYER M5 ;
        RECT  39.984 17.196 40.008 17.28 ;
    END
  END d[353]
  PIN d[354]
    DIRECTION INPUT ;
    USE SIGNAL ;
    PORT
      LAYER M5 ;
        RECT  40.08 17.196 40.104 17.28 ;
    END
  END d[354]
  PIN d[355]
    DIRECTION INPUT ;
    USE SIGNAL ;
    PORT
      LAYER M5 ;
        RECT  40.176 17.196 40.2 17.28 ;
    END
  END d[355]
  PIN d[356]
    DIRECTION INPUT ;
    USE SIGNAL ;
    PORT
      LAYER M5 ;
        RECT  40.272 17.196 40.296 17.28 ;
    END
  END d[356]
  PIN d[357]
    DIRECTION INPUT ;
    USE SIGNAL ;
    PORT
      LAYER M5 ;
        RECT  40.368 17.196 40.392 17.28 ;
    END
  END d[357]
  PIN d[358]
    DIRECTION INPUT ;
    USE SIGNAL ;
    PORT
      LAYER M5 ;
        RECT  40.464 17.196 40.488 17.28 ;
    END
  END d[358]
  PIN d[359]
    DIRECTION INPUT ;
    USE SIGNAL ;
    PORT
      LAYER M5 ;
        RECT  40.56 17.196 40.584 17.28 ;
    END
  END d[359]
  PIN d[35]
    DIRECTION INPUT ;
    USE SIGNAL ;
    PORT
      LAYER M5 ;
        RECT  52.464 17.196 52.488 17.28 ;
    END
  END d[35]
  PIN d[360]
    DIRECTION INPUT ;
    USE SIGNAL ;
    PORT
      LAYER M5 ;
        RECT  40.656 17.196 40.68 17.28 ;
    END
  END d[360]
  PIN d[361]
    DIRECTION INPUT ;
    USE SIGNAL ;
    PORT
      LAYER M5 ;
        RECT  40.752 17.196 40.776 17.28 ;
    END
  END d[361]
  PIN d[362]
    DIRECTION INPUT ;
    USE SIGNAL ;
    PORT
      LAYER M5 ;
        RECT  40.848 17.196 40.872 17.28 ;
    END
  END d[362]
  PIN d[363]
    DIRECTION INPUT ;
    USE SIGNAL ;
    PORT
      LAYER M5 ;
        RECT  40.944 17.196 40.968 17.28 ;
    END
  END d[363]
  PIN d[364]
    DIRECTION INPUT ;
    USE SIGNAL ;
    PORT
      LAYER M5 ;
        RECT  41.04 17.196 41.064 17.28 ;
    END
  END d[364]
  PIN d[365]
    DIRECTION INPUT ;
    USE SIGNAL ;
    PORT
      LAYER M5 ;
        RECT  41.136 17.196 41.16 17.28 ;
    END
  END d[365]
  PIN d[366]
    DIRECTION INPUT ;
    USE SIGNAL ;
    PORT
      LAYER M5 ;
        RECT  41.232 17.196 41.256 17.28 ;
    END
  END d[366]
  PIN d[367]
    DIRECTION INPUT ;
    USE SIGNAL ;
    PORT
      LAYER M5 ;
        RECT  41.328 17.196 41.352 17.28 ;
    END
  END d[367]
  PIN d[368]
    DIRECTION INPUT ;
    USE SIGNAL ;
    PORT
      LAYER M5 ;
        RECT  41.424 17.196 41.448 17.28 ;
    END
  END d[368]
  PIN d[369]
    DIRECTION INPUT ;
    USE SIGNAL ;
    PORT
      LAYER M5 ;
        RECT  41.52 17.196 41.544 17.28 ;
    END
  END d[369]
  PIN d[36]
    DIRECTION INPUT ;
    USE SIGNAL ;
    PORT
      LAYER M5 ;
        RECT  52.56 17.196 52.584 17.28 ;
    END
  END d[36]
  PIN d[370]
    DIRECTION INPUT ;
    USE SIGNAL ;
    PORT
      LAYER M5 ;
        RECT  41.616 17.196 41.64 17.28 ;
    END
  END d[370]
  PIN d[371]
    DIRECTION INPUT ;
    USE SIGNAL ;
    PORT
      LAYER M5 ;
        RECT  41.712 17.196 41.736 17.28 ;
    END
  END d[371]
  PIN d[372]
    DIRECTION INPUT ;
    USE SIGNAL ;
    PORT
      LAYER M5 ;
        RECT  41.808 17.196 41.832 17.28 ;
    END
  END d[372]
  PIN d[373]
    DIRECTION INPUT ;
    USE SIGNAL ;
    PORT
      LAYER M5 ;
        RECT  41.904 17.196 41.928 17.28 ;
    END
  END d[373]
  PIN d[374]
    DIRECTION INPUT ;
    USE SIGNAL ;
    PORT
      LAYER M5 ;
        RECT  42 17.196 42.024 17.28 ;
    END
  END d[374]
  PIN d[375]
    DIRECTION INPUT ;
    USE SIGNAL ;
    PORT
      LAYER M5 ;
        RECT  42.096 17.196 42.12 17.28 ;
    END
  END d[375]
  PIN d[376]
    DIRECTION INPUT ;
    USE SIGNAL ;
    PORT
      LAYER M5 ;
        RECT  42.192 17.196 42.216 17.28 ;
    END
  END d[376]
  PIN d[377]
    DIRECTION INPUT ;
    USE SIGNAL ;
    PORT
      LAYER M5 ;
        RECT  42.288 17.196 42.312 17.28 ;
    END
  END d[377]
  PIN d[378]
    DIRECTION INPUT ;
    USE SIGNAL ;
    PORT
      LAYER M5 ;
        RECT  42.384 17.196 42.408 17.28 ;
    END
  END d[378]
  PIN d[379]
    DIRECTION INPUT ;
    USE SIGNAL ;
    PORT
      LAYER M5 ;
        RECT  42.48 17.196 42.504 17.28 ;
    END
  END d[379]
  PIN d[37]
    DIRECTION INPUT ;
    USE SIGNAL ;
    PORT
      LAYER M5 ;
        RECT  52.656 17.196 52.68 17.28 ;
    END
  END d[37]
  PIN d[380]
    DIRECTION INPUT ;
    USE SIGNAL ;
    PORT
      LAYER M5 ;
        RECT  42.576 17.196 42.6 17.28 ;
    END
  END d[380]
  PIN d[381]
    DIRECTION INPUT ;
    USE SIGNAL ;
    PORT
      LAYER M5 ;
        RECT  42.672 17.196 42.696 17.28 ;
    END
  END d[381]
  PIN d[382]
    DIRECTION INPUT ;
    USE SIGNAL ;
    PORT
      LAYER M5 ;
        RECT  42.768 17.196 42.792 17.28 ;
    END
  END d[382]
  PIN d[383]
    DIRECTION INPUT ;
    USE SIGNAL ;
    PORT
      LAYER M5 ;
        RECT  42.864 17.196 42.888 17.28 ;
    END
  END d[383]
  PIN d[384]
    DIRECTION INPUT ;
    USE SIGNAL ;
    PORT
      LAYER M5 ;
        RECT  84.432 17.196 84.456 17.28 ;
    END
  END d[384]
  PIN d[385]
    DIRECTION INPUT ;
    USE SIGNAL ;
    PORT
      LAYER M5 ;
        RECT  84.528 17.196 84.552 17.28 ;
    END
  END d[385]
  PIN d[386]
    DIRECTION INPUT ;
    USE SIGNAL ;
    PORT
      LAYER M5 ;
        RECT  84.624 17.196 84.648 17.28 ;
    END
  END d[386]
  PIN d[387]
    DIRECTION INPUT ;
    USE SIGNAL ;
    PORT
      LAYER M5 ;
        RECT  84.72 17.196 84.744 17.28 ;
    END
  END d[387]
  PIN d[388]
    DIRECTION INPUT ;
    USE SIGNAL ;
    PORT
      LAYER M5 ;
        RECT  84.816 17.196 84.84 17.28 ;
    END
  END d[388]
  PIN d[389]
    DIRECTION INPUT ;
    USE SIGNAL ;
    PORT
      LAYER M5 ;
        RECT  84.912 17.196 84.936 17.28 ;
    END
  END d[389]
  PIN d[38]
    DIRECTION INPUT ;
    USE SIGNAL ;
    PORT
      LAYER M5 ;
        RECT  52.752 17.196 52.776 17.28 ;
    END
  END d[38]
  PIN d[390]
    DIRECTION INPUT ;
    USE SIGNAL ;
    PORT
      LAYER M5 ;
        RECT  85.008 17.196 85.032 17.28 ;
    END
  END d[390]
  PIN d[391]
    DIRECTION INPUT ;
    USE SIGNAL ;
    PORT
      LAYER M5 ;
        RECT  85.104 17.196 85.128 17.28 ;
    END
  END d[391]
  PIN d[392]
    DIRECTION INPUT ;
    USE SIGNAL ;
    PORT
      LAYER M5 ;
        RECT  85.2 17.196 85.224 17.28 ;
    END
  END d[392]
  PIN d[393]
    DIRECTION INPUT ;
    USE SIGNAL ;
    PORT
      LAYER M5 ;
        RECT  85.296 17.196 85.32 17.28 ;
    END
  END d[393]
  PIN d[394]
    DIRECTION INPUT ;
    USE SIGNAL ;
    PORT
      LAYER M5 ;
        RECT  85.392 17.196 85.416 17.28 ;
    END
  END d[394]
  PIN d[395]
    DIRECTION INPUT ;
    USE SIGNAL ;
    PORT
      LAYER M5 ;
        RECT  85.488 17.196 85.512 17.28 ;
    END
  END d[395]
  PIN d[396]
    DIRECTION INPUT ;
    USE SIGNAL ;
    PORT
      LAYER M5 ;
        RECT  85.584 17.196 85.608 17.28 ;
    END
  END d[396]
  PIN d[397]
    DIRECTION INPUT ;
    USE SIGNAL ;
    PORT
      LAYER M5 ;
        RECT  85.68 17.196 85.704 17.28 ;
    END
  END d[397]
  PIN d[398]
    DIRECTION INPUT ;
    USE SIGNAL ;
    PORT
      LAYER M5 ;
        RECT  85.776 17.196 85.8 17.28 ;
    END
  END d[398]
  PIN d[399]
    DIRECTION INPUT ;
    USE SIGNAL ;
    PORT
      LAYER M5 ;
        RECT  85.872 17.196 85.896 17.28 ;
    END
  END d[399]
  PIN d[39]
    DIRECTION INPUT ;
    USE SIGNAL ;
    PORT
      LAYER M5 ;
        RECT  52.848 17.196 52.872 17.28 ;
    END
  END d[39]
  PIN d[3]
    DIRECTION INPUT ;
    USE SIGNAL ;
    PORT
      LAYER M5 ;
        RECT  62.448 17.196 62.472 17.28 ;
    END
  END d[3]
  PIN d[400]
    DIRECTION INPUT ;
    USE SIGNAL ;
    PORT
      LAYER M5 ;
        RECT  85.968 17.196 85.992 17.28 ;
    END
  END d[400]
  PIN d[401]
    DIRECTION INPUT ;
    USE SIGNAL ;
    PORT
      LAYER M5 ;
        RECT  86.064 17.196 86.088 17.28 ;
    END
  END d[401]
  PIN d[402]
    DIRECTION INPUT ;
    USE SIGNAL ;
    PORT
      LAYER M5 ;
        RECT  86.16 17.196 86.184 17.28 ;
    END
  END d[402]
  PIN d[403]
    DIRECTION INPUT ;
    USE SIGNAL ;
    PORT
      LAYER M5 ;
        RECT  86.256 17.196 86.28 17.28 ;
    END
  END d[403]
  PIN d[404]
    DIRECTION INPUT ;
    USE SIGNAL ;
    PORT
      LAYER M5 ;
        RECT  86.352 17.196 86.376 17.28 ;
    END
  END d[404]
  PIN d[405]
    DIRECTION INPUT ;
    USE SIGNAL ;
    PORT
      LAYER M5 ;
        RECT  86.448 17.196 86.472 17.28 ;
    END
  END d[405]
  PIN d[406]
    DIRECTION INPUT ;
    USE SIGNAL ;
    PORT
      LAYER M5 ;
        RECT  86.544 17.196 86.568 17.28 ;
    END
  END d[406]
  PIN d[407]
    DIRECTION INPUT ;
    USE SIGNAL ;
    PORT
      LAYER M5 ;
        RECT  86.64 17.196 86.664 17.28 ;
    END
  END d[407]
  PIN d[408]
    DIRECTION INPUT ;
    USE SIGNAL ;
    PORT
      LAYER M5 ;
        RECT  86.736 17.196 86.76 17.28 ;
    END
  END d[408]
  PIN d[409]
    DIRECTION INPUT ;
    USE SIGNAL ;
    PORT
      LAYER M5 ;
        RECT  86.832 17.196 86.856 17.28 ;
    END
  END d[409]
  PIN d[40]
    DIRECTION INPUT ;
    USE SIGNAL ;
    PORT
      LAYER M5 ;
        RECT  52.944 17.196 52.968 17.28 ;
    END
  END d[40]
  PIN d[410]
    DIRECTION INPUT ;
    USE SIGNAL ;
    PORT
      LAYER M5 ;
        RECT  86.928 17.196 86.952 17.28 ;
    END
  END d[410]
  PIN d[411]
    DIRECTION INPUT ;
    USE SIGNAL ;
    PORT
      LAYER M5 ;
        RECT  87.024 17.196 87.048 17.28 ;
    END
  END d[411]
  PIN d[412]
    DIRECTION INPUT ;
    USE SIGNAL ;
    PORT
      LAYER M5 ;
        RECT  87.12 17.196 87.144 17.28 ;
    END
  END d[412]
  PIN d[413]
    DIRECTION INPUT ;
    USE SIGNAL ;
    PORT
      LAYER M5 ;
        RECT  87.216 17.196 87.24 17.28 ;
    END
  END d[413]
  PIN d[414]
    DIRECTION INPUT ;
    USE SIGNAL ;
    PORT
      LAYER M5 ;
        RECT  87.312 17.196 87.336 17.28 ;
    END
  END d[414]
  PIN d[415]
    DIRECTION INPUT ;
    USE SIGNAL ;
    PORT
      LAYER M5 ;
        RECT  87.408 17.196 87.432 17.28 ;
    END
  END d[415]
  PIN d[416]
    DIRECTION INPUT ;
    USE SIGNAL ;
    PORT
      LAYER M5 ;
        RECT  90.576 17.196 90.6 17.28 ;
    END
  END d[416]
  PIN d[417]
    DIRECTION INPUT ;
    USE SIGNAL ;
    PORT
      LAYER M5 ;
        RECT  90.672 17.196 90.696 17.28 ;
    END
  END d[417]
  PIN d[418]
    DIRECTION INPUT ;
    USE SIGNAL ;
    PORT
      LAYER M5 ;
        RECT  90.768 17.196 90.792 17.28 ;
    END
  END d[418]
  PIN d[419]
    DIRECTION INPUT ;
    USE SIGNAL ;
    PORT
      LAYER M5 ;
        RECT  90.864 17.196 90.888 17.28 ;
    END
  END d[419]
  PIN d[41]
    DIRECTION INPUT ;
    USE SIGNAL ;
    PORT
      LAYER M5 ;
        RECT  53.04 17.196 53.064 17.28 ;
    END
  END d[41]
  PIN d[420]
    DIRECTION INPUT ;
    USE SIGNAL ;
    PORT
      LAYER M5 ;
        RECT  90.96 17.196 90.984 17.28 ;
    END
  END d[420]
  PIN d[421]
    DIRECTION INPUT ;
    USE SIGNAL ;
    PORT
      LAYER M5 ;
        RECT  91.056 17.196 91.08 17.28 ;
    END
  END d[421]
  PIN d[422]
    DIRECTION INPUT ;
    USE SIGNAL ;
    PORT
      LAYER M5 ;
        RECT  91.152 17.196 91.176 17.28 ;
    END
  END d[422]
  PIN d[423]
    DIRECTION INPUT ;
    USE SIGNAL ;
    PORT
      LAYER M5 ;
        RECT  91.248 17.196 91.272 17.28 ;
    END
  END d[423]
  PIN d[424]
    DIRECTION INPUT ;
    USE SIGNAL ;
    PORT
      LAYER M5 ;
        RECT  91.344 17.196 91.368 17.28 ;
    END
  END d[424]
  PIN d[425]
    DIRECTION INPUT ;
    USE SIGNAL ;
    PORT
      LAYER M5 ;
        RECT  91.44 17.196 91.464 17.28 ;
    END
  END d[425]
  PIN d[426]
    DIRECTION INPUT ;
    USE SIGNAL ;
    PORT
      LAYER M5 ;
        RECT  91.536 17.196 91.56 17.28 ;
    END
  END d[426]
  PIN d[427]
    DIRECTION INPUT ;
    USE SIGNAL ;
    PORT
      LAYER M5 ;
        RECT  91.632 17.196 91.656 17.28 ;
    END
  END d[427]
  PIN d[428]
    DIRECTION INPUT ;
    USE SIGNAL ;
    PORT
      LAYER M5 ;
        RECT  91.728 17.196 91.752 17.28 ;
    END
  END d[428]
  PIN d[429]
    DIRECTION INPUT ;
    USE SIGNAL ;
    PORT
      LAYER M5 ;
        RECT  91.824 17.196 91.848 17.28 ;
    END
  END d[429]
  PIN d[42]
    DIRECTION INPUT ;
    USE SIGNAL ;
    PORT
      LAYER M5 ;
        RECT  53.136 17.196 53.16 17.28 ;
    END
  END d[42]
  PIN d[430]
    DIRECTION INPUT ;
    USE SIGNAL ;
    PORT
      LAYER M5 ;
        RECT  91.92 17.196 91.944 17.28 ;
    END
  END d[430]
  PIN d[431]
    DIRECTION INPUT ;
    USE SIGNAL ;
    PORT
      LAYER M5 ;
        RECT  92.016 17.196 92.04 17.28 ;
    END
  END d[431]
  PIN d[432]
    DIRECTION INPUT ;
    USE SIGNAL ;
    PORT
      LAYER M5 ;
        RECT  92.112 17.196 92.136 17.28 ;
    END
  END d[432]
  PIN d[433]
    DIRECTION INPUT ;
    USE SIGNAL ;
    PORT
      LAYER M5 ;
        RECT  92.208 17.196 92.232 17.28 ;
    END
  END d[433]
  PIN d[434]
    DIRECTION INPUT ;
    USE SIGNAL ;
    PORT
      LAYER M5 ;
        RECT  92.304 17.196 92.328 17.28 ;
    END
  END d[434]
  PIN d[435]
    DIRECTION INPUT ;
    USE SIGNAL ;
    PORT
      LAYER M5 ;
        RECT  92.4 17.196 92.424 17.28 ;
    END
  END d[435]
  PIN d[436]
    DIRECTION INPUT ;
    USE SIGNAL ;
    PORT
      LAYER M5 ;
        RECT  92.496 17.196 92.52 17.28 ;
    END
  END d[436]
  PIN d[437]
    DIRECTION INPUT ;
    USE SIGNAL ;
    PORT
      LAYER M5 ;
        RECT  92.592 17.196 92.616 17.28 ;
    END
  END d[437]
  PIN d[438]
    DIRECTION INPUT ;
    USE SIGNAL ;
    PORT
      LAYER M5 ;
        RECT  92.688 17.196 92.712 17.28 ;
    END
  END d[438]
  PIN d[439]
    DIRECTION INPUT ;
    USE SIGNAL ;
    PORT
      LAYER M5 ;
        RECT  92.784 17.196 92.808 17.28 ;
    END
  END d[439]
  PIN d[43]
    DIRECTION INPUT ;
    USE SIGNAL ;
    PORT
      LAYER M5 ;
        RECT  53.232 17.196 53.256 17.28 ;
    END
  END d[43]
  PIN d[440]
    DIRECTION INPUT ;
    USE SIGNAL ;
    PORT
      LAYER M5 ;
        RECT  92.88 17.196 92.904 17.28 ;
    END
  END d[440]
  PIN d[441]
    DIRECTION INPUT ;
    USE SIGNAL ;
    PORT
      LAYER M5 ;
        RECT  92.976 17.196 93 17.28 ;
    END
  END d[441]
  PIN d[442]
    DIRECTION INPUT ;
    USE SIGNAL ;
    PORT
      LAYER M5 ;
        RECT  93.072 17.196 93.096 17.28 ;
    END
  END d[442]
  PIN d[443]
    DIRECTION INPUT ;
    USE SIGNAL ;
    PORT
      LAYER M5 ;
        RECT  93.168 17.196 93.192 17.28 ;
    END
  END d[443]
  PIN d[444]
    DIRECTION INPUT ;
    USE SIGNAL ;
    PORT
      LAYER M5 ;
        RECT  93.264 17.196 93.288 17.28 ;
    END
  END d[444]
  PIN d[445]
    DIRECTION INPUT ;
    USE SIGNAL ;
    PORT
      LAYER M5 ;
        RECT  93.36 17.196 93.384 17.28 ;
    END
  END d[445]
  PIN d[446]
    DIRECTION INPUT ;
    USE SIGNAL ;
    PORT
      LAYER M5 ;
        RECT  93.456 17.196 93.48 17.28 ;
    END
  END d[446]
  PIN d[447]
    DIRECTION INPUT ;
    USE SIGNAL ;
    PORT
      LAYER M5 ;
        RECT  93.552 17.196 93.576 17.28 ;
    END
  END d[447]
  PIN d[448]
    DIRECTION INPUT ;
    USE SIGNAL ;
    PORT
      LAYER M5 ;
        RECT  81.36 17.196 81.384 17.28 ;
    END
  END d[448]
  PIN d[449]
    DIRECTION INPUT ;
    USE SIGNAL ;
    PORT
      LAYER M5 ;
        RECT  81.456 17.196 81.48 17.28 ;
    END
  END d[449]
  PIN d[44]
    DIRECTION INPUT ;
    USE SIGNAL ;
    PORT
      LAYER M5 ;
        RECT  53.328 17.196 53.352 17.28 ;
    END
  END d[44]
  PIN d[450]
    DIRECTION INPUT ;
    USE SIGNAL ;
    PORT
      LAYER M5 ;
        RECT  81.552 17.196 81.576 17.28 ;
    END
  END d[450]
  PIN d[451]
    DIRECTION INPUT ;
    USE SIGNAL ;
    PORT
      LAYER M5 ;
        RECT  81.648 17.196 81.672 17.28 ;
    END
  END d[451]
  PIN d[452]
    DIRECTION INPUT ;
    USE SIGNAL ;
    PORT
      LAYER M5 ;
        RECT  81.744 17.196 81.768 17.28 ;
    END
  END d[452]
  PIN d[453]
    DIRECTION INPUT ;
    USE SIGNAL ;
    PORT
      LAYER M5 ;
        RECT  81.84 17.196 81.864 17.28 ;
    END
  END d[453]
  PIN d[454]
    DIRECTION INPUT ;
    USE SIGNAL ;
    PORT
      LAYER M5 ;
        RECT  81.936 17.196 81.96 17.28 ;
    END
  END d[454]
  PIN d[455]
    DIRECTION INPUT ;
    USE SIGNAL ;
    PORT
      LAYER M5 ;
        RECT  82.032 17.196 82.056 17.28 ;
    END
  END d[455]
  PIN d[456]
    DIRECTION INPUT ;
    USE SIGNAL ;
    PORT
      LAYER M5 ;
        RECT  82.128 17.196 82.152 17.28 ;
    END
  END d[456]
  PIN d[457]
    DIRECTION INPUT ;
    USE SIGNAL ;
    PORT
      LAYER M5 ;
        RECT  82.224 17.196 82.248 17.28 ;
    END
  END d[457]
  PIN d[458]
    DIRECTION INPUT ;
    USE SIGNAL ;
    PORT
      LAYER M5 ;
        RECT  82.32 17.196 82.344 17.28 ;
    END
  END d[458]
  PIN d[459]
    DIRECTION INPUT ;
    USE SIGNAL ;
    PORT
      LAYER M5 ;
        RECT  82.416 17.196 82.44 17.28 ;
    END
  END d[459]
  PIN d[45]
    DIRECTION INPUT ;
    USE SIGNAL ;
    PORT
      LAYER M5 ;
        RECT  53.424 17.196 53.448 17.28 ;
    END
  END d[45]
  PIN d[460]
    DIRECTION INPUT ;
    USE SIGNAL ;
    PORT
      LAYER M5 ;
        RECT  82.512 17.196 82.536 17.28 ;
    END
  END d[460]
  PIN d[461]
    DIRECTION INPUT ;
    USE SIGNAL ;
    PORT
      LAYER M5 ;
        RECT  82.608 17.196 82.632 17.28 ;
    END
  END d[461]
  PIN d[462]
    DIRECTION INPUT ;
    USE SIGNAL ;
    PORT
      LAYER M5 ;
        RECT  82.704 17.196 82.728 17.28 ;
    END
  END d[462]
  PIN d[463]
    DIRECTION INPUT ;
    USE SIGNAL ;
    PORT
      LAYER M5 ;
        RECT  82.8 17.196 82.824 17.28 ;
    END
  END d[463]
  PIN d[464]
    DIRECTION INPUT ;
    USE SIGNAL ;
    PORT
      LAYER M5 ;
        RECT  82.896 17.196 82.92 17.28 ;
    END
  END d[464]
  PIN d[465]
    DIRECTION INPUT ;
    USE SIGNAL ;
    PORT
      LAYER M5 ;
        RECT  82.992 17.196 83.016 17.28 ;
    END
  END d[465]
  PIN d[466]
    DIRECTION INPUT ;
    USE SIGNAL ;
    PORT
      LAYER M5 ;
        RECT  83.088 17.196 83.112 17.28 ;
    END
  END d[466]
  PIN d[467]
    DIRECTION INPUT ;
    USE SIGNAL ;
    PORT
      LAYER M5 ;
        RECT  83.184 17.196 83.208 17.28 ;
    END
  END d[467]
  PIN d[468]
    DIRECTION INPUT ;
    USE SIGNAL ;
    PORT
      LAYER M5 ;
        RECT  83.28 17.196 83.304 17.28 ;
    END
  END d[468]
  PIN d[469]
    DIRECTION INPUT ;
    USE SIGNAL ;
    PORT
      LAYER M5 ;
        RECT  83.376 17.196 83.4 17.28 ;
    END
  END d[469]
  PIN d[46]
    DIRECTION INPUT ;
    USE SIGNAL ;
    PORT
      LAYER M5 ;
        RECT  53.52 17.196 53.544 17.28 ;
    END
  END d[46]
  PIN d[470]
    DIRECTION INPUT ;
    USE SIGNAL ;
    PORT
      LAYER M5 ;
        RECT  83.472 17.196 83.496 17.28 ;
    END
  END d[470]
  PIN d[471]
    DIRECTION INPUT ;
    USE SIGNAL ;
    PORT
      LAYER M5 ;
        RECT  83.568 17.196 83.592 17.28 ;
    END
  END d[471]
  PIN d[472]
    DIRECTION INPUT ;
    USE SIGNAL ;
    PORT
      LAYER M5 ;
        RECT  83.664 17.196 83.688 17.28 ;
    END
  END d[472]
  PIN d[473]
    DIRECTION INPUT ;
    USE SIGNAL ;
    PORT
      LAYER M5 ;
        RECT  83.76 17.196 83.784 17.28 ;
    END
  END d[473]
  PIN d[474]
    DIRECTION INPUT ;
    USE SIGNAL ;
    PORT
      LAYER M5 ;
        RECT  83.856 17.196 83.88 17.28 ;
    END
  END d[474]
  PIN d[475]
    DIRECTION INPUT ;
    USE SIGNAL ;
    PORT
      LAYER M5 ;
        RECT  83.952 17.196 83.976 17.28 ;
    END
  END d[475]
  PIN d[476]
    DIRECTION INPUT ;
    USE SIGNAL ;
    PORT
      LAYER M5 ;
        RECT  84.048 17.196 84.072 17.28 ;
    END
  END d[476]
  PIN d[477]
    DIRECTION INPUT ;
    USE SIGNAL ;
    PORT
      LAYER M5 ;
        RECT  84.144 17.196 84.168 17.28 ;
    END
  END d[477]
  PIN d[478]
    DIRECTION INPUT ;
    USE SIGNAL ;
    PORT
      LAYER M5 ;
        RECT  84.24 17.196 84.264 17.28 ;
    END
  END d[478]
  PIN d[479]
    DIRECTION INPUT ;
    USE SIGNAL ;
    PORT
      LAYER M5 ;
        RECT  84.336 17.196 84.36 17.28 ;
    END
  END d[479]
  PIN d[47]
    DIRECTION INPUT ;
    USE SIGNAL ;
    PORT
      LAYER M5 ;
        RECT  53.616 17.196 53.64 17.28 ;
    END
  END d[47]
  PIN d[480]
    DIRECTION INPUT ;
    USE SIGNAL ;
    PORT
      LAYER M5 ;
        RECT  32.976 17.196 33 17.28 ;
    END
  END d[480]
  PIN d[481]
    DIRECTION INPUT ;
    USE SIGNAL ;
    PORT
      LAYER M5 ;
        RECT  33.072 17.196 33.096 17.28 ;
    END
  END d[481]
  PIN d[482]
    DIRECTION INPUT ;
    USE SIGNAL ;
    PORT
      LAYER M5 ;
        RECT  33.168 17.196 33.192 17.28 ;
    END
  END d[482]
  PIN d[483]
    DIRECTION INPUT ;
    USE SIGNAL ;
    PORT
      LAYER M5 ;
        RECT  33.264 17.196 33.288 17.28 ;
    END
  END d[483]
  PIN d[484]
    DIRECTION INPUT ;
    USE SIGNAL ;
    PORT
      LAYER M5 ;
        RECT  33.36 17.196 33.384 17.28 ;
    END
  END d[484]
  PIN d[485]
    DIRECTION INPUT ;
    USE SIGNAL ;
    PORT
      LAYER M5 ;
        RECT  33.456 17.196 33.48 17.28 ;
    END
  END d[485]
  PIN d[486]
    DIRECTION INPUT ;
    USE SIGNAL ;
    PORT
      LAYER M5 ;
        RECT  33.552 17.196 33.576 17.28 ;
    END
  END d[486]
  PIN d[487]
    DIRECTION INPUT ;
    USE SIGNAL ;
    PORT
      LAYER M5 ;
        RECT  33.648 17.196 33.672 17.28 ;
    END
  END d[487]
  PIN d[488]
    DIRECTION INPUT ;
    USE SIGNAL ;
    PORT
      LAYER M5 ;
        RECT  33.744 17.196 33.768 17.28 ;
    END
  END d[488]
  PIN d[489]
    DIRECTION INPUT ;
    USE SIGNAL ;
    PORT
      LAYER M5 ;
        RECT  33.84 17.196 33.864 17.28 ;
    END
  END d[489]
  PIN d[48]
    DIRECTION INPUT ;
    USE SIGNAL ;
    PORT
      LAYER M5 ;
        RECT  53.712 17.196 53.736 17.28 ;
    END
  END d[48]
  PIN d[490]
    DIRECTION INPUT ;
    USE SIGNAL ;
    PORT
      LAYER M5 ;
        RECT  33.936 17.196 33.96 17.28 ;
    END
  END d[490]
  PIN d[491]
    DIRECTION INPUT ;
    USE SIGNAL ;
    PORT
      LAYER M5 ;
        RECT  34.032 17.196 34.056 17.28 ;
    END
  END d[491]
  PIN d[492]
    DIRECTION INPUT ;
    USE SIGNAL ;
    PORT
      LAYER M5 ;
        RECT  34.128 17.196 34.152 17.28 ;
    END
  END d[492]
  PIN d[493]
    DIRECTION INPUT ;
    USE SIGNAL ;
    PORT
      LAYER M5 ;
        RECT  34.224 17.196 34.248 17.28 ;
    END
  END d[493]
  PIN d[494]
    DIRECTION INPUT ;
    USE SIGNAL ;
    PORT
      LAYER M5 ;
        RECT  34.32 17.196 34.344 17.28 ;
    END
  END d[494]
  PIN d[495]
    DIRECTION INPUT ;
    USE SIGNAL ;
    PORT
      LAYER M5 ;
        RECT  34.416 17.196 34.44 17.28 ;
    END
  END d[495]
  PIN d[496]
    DIRECTION INPUT ;
    USE SIGNAL ;
    PORT
      LAYER M5 ;
        RECT  34.512 17.196 34.536 17.28 ;
    END
  END d[496]
  PIN d[497]
    DIRECTION INPUT ;
    USE SIGNAL ;
    PORT
      LAYER M5 ;
        RECT  34.608 17.196 34.632 17.28 ;
    END
  END d[497]
  PIN d[498]
    DIRECTION INPUT ;
    USE SIGNAL ;
    PORT
      LAYER M5 ;
        RECT  34.704 17.196 34.728 17.28 ;
    END
  END d[498]
  PIN d[499]
    DIRECTION INPUT ;
    USE SIGNAL ;
    PORT
      LAYER M5 ;
        RECT  34.8 17.196 34.824 17.28 ;
    END
  END d[499]
  PIN d[49]
    DIRECTION INPUT ;
    USE SIGNAL ;
    PORT
      LAYER M5 ;
        RECT  53.808 17.196 53.832 17.28 ;
    END
  END d[49]
  PIN d[4]
    DIRECTION INPUT ;
    USE SIGNAL ;
    PORT
      LAYER M5 ;
        RECT  62.544 17.196 62.568 17.28 ;
    END
  END d[4]
  PIN d[500]
    DIRECTION INPUT ;
    USE SIGNAL ;
    PORT
      LAYER M5 ;
        RECT  34.896 17.196 34.92 17.28 ;
    END
  END d[500]
  PIN d[501]
    DIRECTION INPUT ;
    USE SIGNAL ;
    PORT
      LAYER M5 ;
        RECT  34.992 17.196 35.016 17.28 ;
    END
  END d[501]
  PIN d[502]
    DIRECTION INPUT ;
    USE SIGNAL ;
    PORT
      LAYER M5 ;
        RECT  35.088 17.196 35.112 17.28 ;
    END
  END d[502]
  PIN d[503]
    DIRECTION INPUT ;
    USE SIGNAL ;
    PORT
      LAYER M5 ;
        RECT  35.184 17.196 35.208 17.28 ;
    END
  END d[503]
  PIN d[504]
    DIRECTION INPUT ;
    USE SIGNAL ;
    PORT
      LAYER M5 ;
        RECT  35.28 17.196 35.304 17.28 ;
    END
  END d[504]
  PIN d[505]
    DIRECTION INPUT ;
    USE SIGNAL ;
    PORT
      LAYER M5 ;
        RECT  35.376 17.196 35.4 17.28 ;
    END
  END d[505]
  PIN d[506]
    DIRECTION INPUT ;
    USE SIGNAL ;
    PORT
      LAYER M5 ;
        RECT  35.472 17.196 35.496 17.28 ;
    END
  END d[506]
  PIN d[507]
    DIRECTION INPUT ;
    USE SIGNAL ;
    PORT
      LAYER M5 ;
        RECT  35.568 17.196 35.592 17.28 ;
    END
  END d[507]
  PIN d[508]
    DIRECTION INPUT ;
    USE SIGNAL ;
    PORT
      LAYER M5 ;
        RECT  35.664 17.196 35.688 17.28 ;
    END
  END d[508]
  PIN d[509]
    DIRECTION INPUT ;
    USE SIGNAL ;
    PORT
      LAYER M5 ;
        RECT  35.76 17.196 35.784 17.28 ;
    END
  END d[509]
  PIN d[50]
    DIRECTION INPUT ;
    USE SIGNAL ;
    PORT
      LAYER M5 ;
        RECT  53.904 17.196 53.928 17.28 ;
    END
  END d[50]
  PIN d[510]
    DIRECTION INPUT ;
    USE SIGNAL ;
    PORT
      LAYER M5 ;
        RECT  35.856 17.196 35.88 17.28 ;
    END
  END d[510]
  PIN d[511]
    DIRECTION INPUT ;
    USE SIGNAL ;
    PORT
      LAYER M5 ;
        RECT  35.952 17.196 35.976 17.28 ;
    END
  END d[511]
  PIN d[512]
    DIRECTION INPUT ;
    USE SIGNAL ;
    PORT
      LAYER M5 ;
        RECT  26.832 17.196 26.856 17.28 ;
    END
  END d[512]
  PIN d[513]
    DIRECTION INPUT ;
    USE SIGNAL ;
    PORT
      LAYER M5 ;
        RECT  26.928 17.196 26.952 17.28 ;
    END
  END d[513]
  PIN d[514]
    DIRECTION INPUT ;
    USE SIGNAL ;
    PORT
      LAYER M5 ;
        RECT  27.024 17.196 27.048 17.28 ;
    END
  END d[514]
  PIN d[515]
    DIRECTION INPUT ;
    USE SIGNAL ;
    PORT
      LAYER M5 ;
        RECT  27.12 17.196 27.144 17.28 ;
    END
  END d[515]
  PIN d[516]
    DIRECTION INPUT ;
    USE SIGNAL ;
    PORT
      LAYER M5 ;
        RECT  27.216 17.196 27.24 17.28 ;
    END
  END d[516]
  PIN d[517]
    DIRECTION INPUT ;
    USE SIGNAL ;
    PORT
      LAYER M5 ;
        RECT  27.312 17.196 27.336 17.28 ;
    END
  END d[517]
  PIN d[518]
    DIRECTION INPUT ;
    USE SIGNAL ;
    PORT
      LAYER M5 ;
        RECT  27.408 17.196 27.432 17.28 ;
    END
  END d[518]
  PIN d[519]
    DIRECTION INPUT ;
    USE SIGNAL ;
    PORT
      LAYER M5 ;
        RECT  27.504 17.196 27.528 17.28 ;
    END
  END d[519]
  PIN d[51]
    DIRECTION INPUT ;
    USE SIGNAL ;
    PORT
      LAYER M5 ;
        RECT  54 17.196 54.024 17.28 ;
    END
  END d[51]
  PIN d[520]
    DIRECTION INPUT ;
    USE SIGNAL ;
    PORT
      LAYER M5 ;
        RECT  27.6 17.196 27.624 17.28 ;
    END
  END d[520]
  PIN d[521]
    DIRECTION INPUT ;
    USE SIGNAL ;
    PORT
      LAYER M5 ;
        RECT  27.696 17.196 27.72 17.28 ;
    END
  END d[521]
  PIN d[522]
    DIRECTION INPUT ;
    USE SIGNAL ;
    PORT
      LAYER M5 ;
        RECT  27.792 17.196 27.816 17.28 ;
    END
  END d[522]
  PIN d[523]
    DIRECTION INPUT ;
    USE SIGNAL ;
    PORT
      LAYER M5 ;
        RECT  27.888 17.196 27.912 17.28 ;
    END
  END d[523]
  PIN d[524]
    DIRECTION INPUT ;
    USE SIGNAL ;
    PORT
      LAYER M5 ;
        RECT  27.984 17.196 28.008 17.28 ;
    END
  END d[524]
  PIN d[525]
    DIRECTION INPUT ;
    USE SIGNAL ;
    PORT
      LAYER M5 ;
        RECT  28.08 17.196 28.104 17.28 ;
    END
  END d[525]
  PIN d[526]
    DIRECTION INPUT ;
    USE SIGNAL ;
    PORT
      LAYER M5 ;
        RECT  28.176 17.196 28.2 17.28 ;
    END
  END d[526]
  PIN d[527]
    DIRECTION INPUT ;
    USE SIGNAL ;
    PORT
      LAYER M5 ;
        RECT  28.272 17.196 28.296 17.28 ;
    END
  END d[527]
  PIN d[528]
    DIRECTION INPUT ;
    USE SIGNAL ;
    PORT
      LAYER M5 ;
        RECT  28.368 17.196 28.392 17.28 ;
    END
  END d[528]
  PIN d[529]
    DIRECTION INPUT ;
    USE SIGNAL ;
    PORT
      LAYER M5 ;
        RECT  28.464 17.196 28.488 17.28 ;
    END
  END d[529]
  PIN d[52]
    DIRECTION INPUT ;
    USE SIGNAL ;
    PORT
      LAYER M5 ;
        RECT  54.096 17.196 54.12 17.28 ;
    END
  END d[52]
  PIN d[530]
    DIRECTION INPUT ;
    USE SIGNAL ;
    PORT
      LAYER M5 ;
        RECT  28.56 17.196 28.584 17.28 ;
    END
  END d[530]
  PIN d[531]
    DIRECTION INPUT ;
    USE SIGNAL ;
    PORT
      LAYER M5 ;
        RECT  28.656 17.196 28.68 17.28 ;
    END
  END d[531]
  PIN d[532]
    DIRECTION INPUT ;
    USE SIGNAL ;
    PORT
      LAYER M5 ;
        RECT  28.752 17.196 28.776 17.28 ;
    END
  END d[532]
  PIN d[533]
    DIRECTION INPUT ;
    USE SIGNAL ;
    PORT
      LAYER M5 ;
        RECT  28.848 17.196 28.872 17.28 ;
    END
  END d[533]
  PIN d[534]
    DIRECTION INPUT ;
    USE SIGNAL ;
    PORT
      LAYER M5 ;
        RECT  28.944 17.196 28.968 17.28 ;
    END
  END d[534]
  PIN d[535]
    DIRECTION INPUT ;
    USE SIGNAL ;
    PORT
      LAYER M5 ;
        RECT  29.04 17.196 29.064 17.28 ;
    END
  END d[535]
  PIN d[536]
    DIRECTION INPUT ;
    USE SIGNAL ;
    PORT
      LAYER M5 ;
        RECT  29.136 17.196 29.16 17.28 ;
    END
  END d[536]
  PIN d[537]
    DIRECTION INPUT ;
    USE SIGNAL ;
    PORT
      LAYER M5 ;
        RECT  29.232 17.196 29.256 17.28 ;
    END
  END d[537]
  PIN d[538]
    DIRECTION INPUT ;
    USE SIGNAL ;
    PORT
      LAYER M5 ;
        RECT  29.328 17.196 29.352 17.28 ;
    END
  END d[538]
  PIN d[539]
    DIRECTION INPUT ;
    USE SIGNAL ;
    PORT
      LAYER M5 ;
        RECT  29.424 17.196 29.448 17.28 ;
    END
  END d[539]
  PIN d[53]
    DIRECTION INPUT ;
    USE SIGNAL ;
    PORT
      LAYER M5 ;
        RECT  54.192 17.196 54.216 17.28 ;
    END
  END d[53]
  PIN d[540]
    DIRECTION INPUT ;
    USE SIGNAL ;
    PORT
      LAYER M5 ;
        RECT  29.52 17.196 29.544 17.28 ;
    END
  END d[540]
  PIN d[541]
    DIRECTION INPUT ;
    USE SIGNAL ;
    PORT
      LAYER M5 ;
        RECT  29.616 17.196 29.64 17.28 ;
    END
  END d[541]
  PIN d[542]
    DIRECTION INPUT ;
    USE SIGNAL ;
    PORT
      LAYER M5 ;
        RECT  29.712 17.196 29.736 17.28 ;
    END
  END d[542]
  PIN d[543]
    DIRECTION INPUT ;
    USE SIGNAL ;
    PORT
      LAYER M5 ;
        RECT  29.808 17.196 29.832 17.28 ;
    END
  END d[543]
  PIN d[544]
    DIRECTION INPUT ;
    USE SIGNAL ;
    PORT
      LAYER M5 ;
        RECT  36.048 17.196 36.072 17.28 ;
    END
  END d[544]
  PIN d[545]
    DIRECTION INPUT ;
    USE SIGNAL ;
    PORT
      LAYER M5 ;
        RECT  36.144 17.196 36.168 17.28 ;
    END
  END d[545]
  PIN d[546]
    DIRECTION INPUT ;
    USE SIGNAL ;
    PORT
      LAYER M5 ;
        RECT  36.24 17.196 36.264 17.28 ;
    END
  END d[546]
  PIN d[547]
    DIRECTION INPUT ;
    USE SIGNAL ;
    PORT
      LAYER M5 ;
        RECT  36.336 17.196 36.36 17.28 ;
    END
  END d[547]
  PIN d[548]
    DIRECTION INPUT ;
    USE SIGNAL ;
    PORT
      LAYER M5 ;
        RECT  36.432 17.196 36.456 17.28 ;
    END
  END d[548]
  PIN d[549]
    DIRECTION INPUT ;
    USE SIGNAL ;
    PORT
      LAYER M5 ;
        RECT  36.528 17.196 36.552 17.28 ;
    END
  END d[549]
  PIN d[54]
    DIRECTION INPUT ;
    USE SIGNAL ;
    PORT
      LAYER M5 ;
        RECT  54.288 17.196 54.312 17.28 ;
    END
  END d[54]
  PIN d[550]
    DIRECTION INPUT ;
    USE SIGNAL ;
    PORT
      LAYER M5 ;
        RECT  36.624 17.196 36.648 17.28 ;
    END
  END d[550]
  PIN d[551]
    DIRECTION INPUT ;
    USE SIGNAL ;
    PORT
      LAYER M5 ;
        RECT  36.72 17.196 36.744 17.28 ;
    END
  END d[551]
  PIN d[552]
    DIRECTION INPUT ;
    USE SIGNAL ;
    PORT
      LAYER M5 ;
        RECT  36.816 17.196 36.84 17.28 ;
    END
  END d[552]
  PIN d[553]
    DIRECTION INPUT ;
    USE SIGNAL ;
    PORT
      LAYER M5 ;
        RECT  36.912 17.196 36.936 17.28 ;
    END
  END d[553]
  PIN d[554]
    DIRECTION INPUT ;
    USE SIGNAL ;
    PORT
      LAYER M5 ;
        RECT  37.008 17.196 37.032 17.28 ;
    END
  END d[554]
  PIN d[555]
    DIRECTION INPUT ;
    USE SIGNAL ;
    PORT
      LAYER M5 ;
        RECT  37.104 17.196 37.128 17.28 ;
    END
  END d[555]
  PIN d[556]
    DIRECTION INPUT ;
    USE SIGNAL ;
    PORT
      LAYER M5 ;
        RECT  37.2 17.196 37.224 17.28 ;
    END
  END d[556]
  PIN d[557]
    DIRECTION INPUT ;
    USE SIGNAL ;
    PORT
      LAYER M5 ;
        RECT  37.296 17.196 37.32 17.28 ;
    END
  END d[557]
  PIN d[558]
    DIRECTION INPUT ;
    USE SIGNAL ;
    PORT
      LAYER M5 ;
        RECT  37.392 17.196 37.416 17.28 ;
    END
  END d[558]
  PIN d[559]
    DIRECTION INPUT ;
    USE SIGNAL ;
    PORT
      LAYER M5 ;
        RECT  37.488 17.196 37.512 17.28 ;
    END
  END d[559]
  PIN d[55]
    DIRECTION INPUT ;
    USE SIGNAL ;
    PORT
      LAYER M5 ;
        RECT  54.384 17.196 54.408 17.28 ;
    END
  END d[55]
  PIN d[560]
    DIRECTION INPUT ;
    USE SIGNAL ;
    PORT
      LAYER M5 ;
        RECT  37.584 17.196 37.608 17.28 ;
    END
  END d[560]
  PIN d[561]
    DIRECTION INPUT ;
    USE SIGNAL ;
    PORT
      LAYER M5 ;
        RECT  37.68 17.196 37.704 17.28 ;
    END
  END d[561]
  PIN d[562]
    DIRECTION INPUT ;
    USE SIGNAL ;
    PORT
      LAYER M5 ;
        RECT  37.776 17.196 37.8 17.28 ;
    END
  END d[562]
  PIN d[563]
    DIRECTION INPUT ;
    USE SIGNAL ;
    PORT
      LAYER M5 ;
        RECT  37.872 17.196 37.896 17.28 ;
    END
  END d[563]
  PIN d[564]
    DIRECTION INPUT ;
    USE SIGNAL ;
    PORT
      LAYER M5 ;
        RECT  37.968 17.196 37.992 17.28 ;
    END
  END d[564]
  PIN d[565]
    DIRECTION INPUT ;
    USE SIGNAL ;
    PORT
      LAYER M5 ;
        RECT  38.064 17.196 38.088 17.28 ;
    END
  END d[565]
  PIN d[566]
    DIRECTION INPUT ;
    USE SIGNAL ;
    PORT
      LAYER M5 ;
        RECT  38.16 17.196 38.184 17.28 ;
    END
  END d[566]
  PIN d[567]
    DIRECTION INPUT ;
    USE SIGNAL ;
    PORT
      LAYER M5 ;
        RECT  38.256 17.196 38.28 17.28 ;
    END
  END d[567]
  PIN d[568]
    DIRECTION INPUT ;
    USE SIGNAL ;
    PORT
      LAYER M5 ;
        RECT  38.352 17.196 38.376 17.28 ;
    END
  END d[568]
  PIN d[569]
    DIRECTION INPUT ;
    USE SIGNAL ;
    PORT
      LAYER M5 ;
        RECT  38.448 17.196 38.472 17.28 ;
    END
  END d[569]
  PIN d[56]
    DIRECTION INPUT ;
    USE SIGNAL ;
    PORT
      LAYER M5 ;
        RECT  54.48 17.196 54.504 17.28 ;
    END
  END d[56]
  PIN d[570]
    DIRECTION INPUT ;
    USE SIGNAL ;
    PORT
      LAYER M5 ;
        RECT  38.544 17.196 38.568 17.28 ;
    END
  END d[570]
  PIN d[571]
    DIRECTION INPUT ;
    USE SIGNAL ;
    PORT
      LAYER M5 ;
        RECT  38.64 17.196 38.664 17.28 ;
    END
  END d[571]
  PIN d[572]
    DIRECTION INPUT ;
    USE SIGNAL ;
    PORT
      LAYER M5 ;
        RECT  38.736 17.196 38.76 17.28 ;
    END
  END d[572]
  PIN d[573]
    DIRECTION INPUT ;
    USE SIGNAL ;
    PORT
      LAYER M5 ;
        RECT  38.832 17.196 38.856 17.28 ;
    END
  END d[573]
  PIN d[574]
    DIRECTION INPUT ;
    USE SIGNAL ;
    PORT
      LAYER M5 ;
        RECT  38.928 17.196 38.952 17.28 ;
    END
  END d[574]
  PIN d[575]
    DIRECTION INPUT ;
    USE SIGNAL ;
    PORT
      LAYER M5 ;
        RECT  39.024 17.196 39.048 17.28 ;
    END
  END d[575]
  PIN d[576]
    DIRECTION INPUT ;
    USE SIGNAL ;
    PORT
      LAYER M5 ;
        RECT  23.76 17.196 23.784 17.28 ;
    END
  END d[576]
  PIN d[577]
    DIRECTION INPUT ;
    USE SIGNAL ;
    PORT
      LAYER M5 ;
        RECT  23.856 17.196 23.88 17.28 ;
    END
  END d[577]
  PIN d[578]
    DIRECTION INPUT ;
    USE SIGNAL ;
    PORT
      LAYER M5 ;
        RECT  23.952 17.196 23.976 17.28 ;
    END
  END d[578]
  PIN d[579]
    DIRECTION INPUT ;
    USE SIGNAL ;
    PORT
      LAYER M5 ;
        RECT  24.048 17.196 24.072 17.28 ;
    END
  END d[579]
  PIN d[57]
    DIRECTION INPUT ;
    USE SIGNAL ;
    PORT
      LAYER M5 ;
        RECT  54.576 17.196 54.6 17.28 ;
    END
  END d[57]
  PIN d[580]
    DIRECTION INPUT ;
    USE SIGNAL ;
    PORT
      LAYER M5 ;
        RECT  24.144 17.196 24.168 17.28 ;
    END
  END d[580]
  PIN d[581]
    DIRECTION INPUT ;
    USE SIGNAL ;
    PORT
      LAYER M5 ;
        RECT  24.24 17.196 24.264 17.28 ;
    END
  END d[581]
  PIN d[582]
    DIRECTION INPUT ;
    USE SIGNAL ;
    PORT
      LAYER M5 ;
        RECT  24.336 17.196 24.36 17.28 ;
    END
  END d[582]
  PIN d[583]
    DIRECTION INPUT ;
    USE SIGNAL ;
    PORT
      LAYER M5 ;
        RECT  24.432 17.196 24.456 17.28 ;
    END
  END d[583]
  PIN d[584]
    DIRECTION INPUT ;
    USE SIGNAL ;
    PORT
      LAYER M5 ;
        RECT  24.528 17.196 24.552 17.28 ;
    END
  END d[584]
  PIN d[585]
    DIRECTION INPUT ;
    USE SIGNAL ;
    PORT
      LAYER M5 ;
        RECT  24.624 17.196 24.648 17.28 ;
    END
  END d[585]
  PIN d[586]
    DIRECTION INPUT ;
    USE SIGNAL ;
    PORT
      LAYER M5 ;
        RECT  24.72 17.196 24.744 17.28 ;
    END
  END d[586]
  PIN d[587]
    DIRECTION INPUT ;
    USE SIGNAL ;
    PORT
      LAYER M5 ;
        RECT  24.816 17.196 24.84 17.28 ;
    END
  END d[587]
  PIN d[588]
    DIRECTION INPUT ;
    USE SIGNAL ;
    PORT
      LAYER M5 ;
        RECT  24.912 17.196 24.936 17.28 ;
    END
  END d[588]
  PIN d[589]
    DIRECTION INPUT ;
    USE SIGNAL ;
    PORT
      LAYER M5 ;
        RECT  25.008 17.196 25.032 17.28 ;
    END
  END d[589]
  PIN d[58]
    DIRECTION INPUT ;
    USE SIGNAL ;
    PORT
      LAYER M5 ;
        RECT  54.672 17.196 54.696 17.28 ;
    END
  END d[58]
  PIN d[590]
    DIRECTION INPUT ;
    USE SIGNAL ;
    PORT
      LAYER M5 ;
        RECT  25.104 17.196 25.128 17.28 ;
    END
  END d[590]
  PIN d[591]
    DIRECTION INPUT ;
    USE SIGNAL ;
    PORT
      LAYER M5 ;
        RECT  25.2 17.196 25.224 17.28 ;
    END
  END d[591]
  PIN d[592]
    DIRECTION INPUT ;
    USE SIGNAL ;
    PORT
      LAYER M5 ;
        RECT  25.296 17.196 25.32 17.28 ;
    END
  END d[592]
  PIN d[593]
    DIRECTION INPUT ;
    USE SIGNAL ;
    PORT
      LAYER M5 ;
        RECT  25.392 17.196 25.416 17.28 ;
    END
  END d[593]
  PIN d[594]
    DIRECTION INPUT ;
    USE SIGNAL ;
    PORT
      LAYER M5 ;
        RECT  25.488 17.196 25.512 17.28 ;
    END
  END d[594]
  PIN d[595]
    DIRECTION INPUT ;
    USE SIGNAL ;
    PORT
      LAYER M5 ;
        RECT  25.584 17.196 25.608 17.28 ;
    END
  END d[595]
  PIN d[596]
    DIRECTION INPUT ;
    USE SIGNAL ;
    PORT
      LAYER M5 ;
        RECT  25.68 17.196 25.704 17.28 ;
    END
  END d[596]
  PIN d[597]
    DIRECTION INPUT ;
    USE SIGNAL ;
    PORT
      LAYER M5 ;
        RECT  25.776 17.196 25.8 17.28 ;
    END
  END d[597]
  PIN d[598]
    DIRECTION INPUT ;
    USE SIGNAL ;
    PORT
      LAYER M5 ;
        RECT  25.872 17.196 25.896 17.28 ;
    END
  END d[598]
  PIN d[599]
    DIRECTION INPUT ;
    USE SIGNAL ;
    PORT
      LAYER M5 ;
        RECT  25.968 17.196 25.992 17.28 ;
    END
  END d[599]
  PIN d[59]
    DIRECTION INPUT ;
    USE SIGNAL ;
    PORT
      LAYER M5 ;
        RECT  54.768 17.196 54.792 17.28 ;
    END
  END d[59]
  PIN d[5]
    DIRECTION INPUT ;
    USE SIGNAL ;
    PORT
      LAYER M5 ;
        RECT  62.64 17.196 62.664 17.28 ;
    END
  END d[5]
  PIN d[600]
    DIRECTION INPUT ;
    USE SIGNAL ;
    PORT
      LAYER M5 ;
        RECT  26.064 17.196 26.088 17.28 ;
    END
  END d[600]
  PIN d[601]
    DIRECTION INPUT ;
    USE SIGNAL ;
    PORT
      LAYER M5 ;
        RECT  26.16 17.196 26.184 17.28 ;
    END
  END d[601]
  PIN d[602]
    DIRECTION INPUT ;
    USE SIGNAL ;
    PORT
      LAYER M5 ;
        RECT  26.256 17.196 26.28 17.28 ;
    END
  END d[602]
  PIN d[603]
    DIRECTION INPUT ;
    USE SIGNAL ;
    PORT
      LAYER M5 ;
        RECT  26.352 17.196 26.376 17.28 ;
    END
  END d[603]
  PIN d[604]
    DIRECTION INPUT ;
    USE SIGNAL ;
    PORT
      LAYER M5 ;
        RECT  26.448 17.196 26.472 17.28 ;
    END
  END d[604]
  PIN d[605]
    DIRECTION INPUT ;
    USE SIGNAL ;
    PORT
      LAYER M5 ;
        RECT  26.544 17.196 26.568 17.28 ;
    END
  END d[605]
  PIN d[606]
    DIRECTION INPUT ;
    USE SIGNAL ;
    PORT
      LAYER M5 ;
        RECT  26.64 17.196 26.664 17.28 ;
    END
  END d[606]
  PIN d[607]
    DIRECTION INPUT ;
    USE SIGNAL ;
    PORT
      LAYER M5 ;
        RECT  26.736 17.196 26.76 17.28 ;
    END
  END d[607]
  PIN d[608]
    DIRECTION INPUT ;
    USE SIGNAL ;
    PORT
      LAYER M5 ;
        RECT  29.904 17.196 29.928 17.28 ;
    END
  END d[608]
  PIN d[609]
    DIRECTION INPUT ;
    USE SIGNAL ;
    PORT
      LAYER M5 ;
        RECT  30 17.196 30.024 17.28 ;
    END
  END d[609]
  PIN d[60]
    DIRECTION INPUT ;
    USE SIGNAL ;
    PORT
      LAYER M5 ;
        RECT  54.864 17.196 54.888 17.28 ;
    END
  END d[60]
  PIN d[610]
    DIRECTION INPUT ;
    USE SIGNAL ;
    PORT
      LAYER M5 ;
        RECT  30.096 17.196 30.12 17.28 ;
    END
  END d[610]
  PIN d[611]
    DIRECTION INPUT ;
    USE SIGNAL ;
    PORT
      LAYER M5 ;
        RECT  30.192 17.196 30.216 17.28 ;
    END
  END d[611]
  PIN d[612]
    DIRECTION INPUT ;
    USE SIGNAL ;
    PORT
      LAYER M5 ;
        RECT  30.288 17.196 30.312 17.28 ;
    END
  END d[612]
  PIN d[613]
    DIRECTION INPUT ;
    USE SIGNAL ;
    PORT
      LAYER M5 ;
        RECT  30.384 17.196 30.408 17.28 ;
    END
  END d[613]
  PIN d[614]
    DIRECTION INPUT ;
    USE SIGNAL ;
    PORT
      LAYER M5 ;
        RECT  30.48 17.196 30.504 17.28 ;
    END
  END d[614]
  PIN d[615]
    DIRECTION INPUT ;
    USE SIGNAL ;
    PORT
      LAYER M5 ;
        RECT  30.576 17.196 30.6 17.28 ;
    END
  END d[615]
  PIN d[616]
    DIRECTION INPUT ;
    USE SIGNAL ;
    PORT
      LAYER M5 ;
        RECT  30.672 17.196 30.696 17.28 ;
    END
  END d[616]
  PIN d[617]
    DIRECTION INPUT ;
    USE SIGNAL ;
    PORT
      LAYER M5 ;
        RECT  30.768 17.196 30.792 17.28 ;
    END
  END d[617]
  PIN d[618]
    DIRECTION INPUT ;
    USE SIGNAL ;
    PORT
      LAYER M5 ;
        RECT  30.864 17.196 30.888 17.28 ;
    END
  END d[618]
  PIN d[619]
    DIRECTION INPUT ;
    USE SIGNAL ;
    PORT
      LAYER M5 ;
        RECT  30.96 17.196 30.984 17.28 ;
    END
  END d[619]
  PIN d[61]
    DIRECTION INPUT ;
    USE SIGNAL ;
    PORT
      LAYER M5 ;
        RECT  54.96 17.196 54.984 17.28 ;
    END
  END d[61]
  PIN d[620]
    DIRECTION INPUT ;
    USE SIGNAL ;
    PORT
      LAYER M5 ;
        RECT  31.056 17.196 31.08 17.28 ;
    END
  END d[620]
  PIN d[621]
    DIRECTION INPUT ;
    USE SIGNAL ;
    PORT
      LAYER M5 ;
        RECT  31.152 17.196 31.176 17.28 ;
    END
  END d[621]
  PIN d[622]
    DIRECTION INPUT ;
    USE SIGNAL ;
    PORT
      LAYER M5 ;
        RECT  31.248 17.196 31.272 17.28 ;
    END
  END d[622]
  PIN d[623]
    DIRECTION INPUT ;
    USE SIGNAL ;
    PORT
      LAYER M5 ;
        RECT  31.344 17.196 31.368 17.28 ;
    END
  END d[623]
  PIN d[624]
    DIRECTION INPUT ;
    USE SIGNAL ;
    PORT
      LAYER M5 ;
        RECT  31.44 17.196 31.464 17.28 ;
    END
  END d[624]
  PIN d[625]
    DIRECTION INPUT ;
    USE SIGNAL ;
    PORT
      LAYER M5 ;
        RECT  31.536 17.196 31.56 17.28 ;
    END
  END d[625]
  PIN d[626]
    DIRECTION INPUT ;
    USE SIGNAL ;
    PORT
      LAYER M5 ;
        RECT  31.632 17.196 31.656 17.28 ;
    END
  END d[626]
  PIN d[627]
    DIRECTION INPUT ;
    USE SIGNAL ;
    PORT
      LAYER M5 ;
        RECT  31.728 17.196 31.752 17.28 ;
    END
  END d[627]
  PIN d[628]
    DIRECTION INPUT ;
    USE SIGNAL ;
    PORT
      LAYER M5 ;
        RECT  31.824 17.196 31.848 17.28 ;
    END
  END d[628]
  PIN d[629]
    DIRECTION INPUT ;
    USE SIGNAL ;
    PORT
      LAYER M5 ;
        RECT  31.92 17.196 31.944 17.28 ;
    END
  END d[629]
  PIN d[62]
    DIRECTION INPUT ;
    USE SIGNAL ;
    PORT
      LAYER M5 ;
        RECT  55.056 17.196 55.08 17.28 ;
    END
  END d[62]
  PIN d[630]
    DIRECTION INPUT ;
    USE SIGNAL ;
    PORT
      LAYER M5 ;
        RECT  32.016 17.196 32.04 17.28 ;
    END
  END d[630]
  PIN d[631]
    DIRECTION INPUT ;
    USE SIGNAL ;
    PORT
      LAYER M5 ;
        RECT  32.112 17.196 32.136 17.28 ;
    END
  END d[631]
  PIN d[632]
    DIRECTION INPUT ;
    USE SIGNAL ;
    PORT
      LAYER M5 ;
        RECT  32.208 17.196 32.232 17.28 ;
    END
  END d[632]
  PIN d[633]
    DIRECTION INPUT ;
    USE SIGNAL ;
    PORT
      LAYER M5 ;
        RECT  32.304 17.196 32.328 17.28 ;
    END
  END d[633]
  PIN d[634]
    DIRECTION INPUT ;
    USE SIGNAL ;
    PORT
      LAYER M5 ;
        RECT  32.4 17.196 32.424 17.28 ;
    END
  END d[634]
  PIN d[635]
    DIRECTION INPUT ;
    USE SIGNAL ;
    PORT
      LAYER M5 ;
        RECT  32.496 17.196 32.52 17.28 ;
    END
  END d[635]
  PIN d[636]
    DIRECTION INPUT ;
    USE SIGNAL ;
    PORT
      LAYER M5 ;
        RECT  32.592 17.196 32.616 17.28 ;
    END
  END d[636]
  PIN d[637]
    DIRECTION INPUT ;
    USE SIGNAL ;
    PORT
      LAYER M5 ;
        RECT  32.688 17.196 32.712 17.28 ;
    END
  END d[637]
  PIN d[638]
    DIRECTION INPUT ;
    USE SIGNAL ;
    PORT
      LAYER M5 ;
        RECT  32.784 17.196 32.808 17.28 ;
    END
  END d[638]
  PIN d[639]
    DIRECTION INPUT ;
    USE SIGNAL ;
    PORT
      LAYER M5 ;
        RECT  32.88 17.196 32.904 17.28 ;
    END
  END d[639]
  PIN d[63]
    DIRECTION INPUT ;
    USE SIGNAL ;
    PORT
      LAYER M5 ;
        RECT  55.152 17.196 55.176 17.28 ;
    END
  END d[63]
  PIN d[640]
    DIRECTION INPUT ;
    USE SIGNAL ;
    PORT
      LAYER M5 ;
        RECT  20.688 17.196 20.712 17.28 ;
    END
  END d[640]
  PIN d[641]
    DIRECTION INPUT ;
    USE SIGNAL ;
    PORT
      LAYER M5 ;
        RECT  20.784 17.196 20.808 17.28 ;
    END
  END d[641]
  PIN d[642]
    DIRECTION INPUT ;
    USE SIGNAL ;
    PORT
      LAYER M5 ;
        RECT  20.88 17.196 20.904 17.28 ;
    END
  END d[642]
  PIN d[643]
    DIRECTION INPUT ;
    USE SIGNAL ;
    PORT
      LAYER M5 ;
        RECT  20.976 17.196 21 17.28 ;
    END
  END d[643]
  PIN d[644]
    DIRECTION INPUT ;
    USE SIGNAL ;
    PORT
      LAYER M5 ;
        RECT  21.072 17.196 21.096 17.28 ;
    END
  END d[644]
  PIN d[645]
    DIRECTION INPUT ;
    USE SIGNAL ;
    PORT
      LAYER M5 ;
        RECT  21.168 17.196 21.192 17.28 ;
    END
  END d[645]
  PIN d[646]
    DIRECTION INPUT ;
    USE SIGNAL ;
    PORT
      LAYER M5 ;
        RECT  21.264 17.196 21.288 17.28 ;
    END
  END d[646]
  PIN d[647]
    DIRECTION INPUT ;
    USE SIGNAL ;
    PORT
      LAYER M5 ;
        RECT  21.36 17.196 21.384 17.28 ;
    END
  END d[647]
  PIN d[648]
    DIRECTION INPUT ;
    USE SIGNAL ;
    PORT
      LAYER M5 ;
        RECT  21.456 17.196 21.48 17.28 ;
    END
  END d[648]
  PIN d[649]
    DIRECTION INPUT ;
    USE SIGNAL ;
    PORT
      LAYER M5 ;
        RECT  21.552 17.196 21.576 17.28 ;
    END
  END d[649]
  PIN d[64]
    DIRECTION INPUT ;
    USE SIGNAL ;
    PORT
      LAYER M5 ;
        RECT  46.032 17.196 46.056 17.28 ;
    END
  END d[64]
  PIN d[650]
    DIRECTION INPUT ;
    USE SIGNAL ;
    PORT
      LAYER M5 ;
        RECT  21.648 17.196 21.672 17.28 ;
    END
  END d[650]
  PIN d[651]
    DIRECTION INPUT ;
    USE SIGNAL ;
    PORT
      LAYER M5 ;
        RECT  21.744 17.196 21.768 17.28 ;
    END
  END d[651]
  PIN d[652]
    DIRECTION INPUT ;
    USE SIGNAL ;
    PORT
      LAYER M5 ;
        RECT  21.84 17.196 21.864 17.28 ;
    END
  END d[652]
  PIN d[653]
    DIRECTION INPUT ;
    USE SIGNAL ;
    PORT
      LAYER M5 ;
        RECT  21.936 17.196 21.96 17.28 ;
    END
  END d[653]
  PIN d[654]
    DIRECTION INPUT ;
    USE SIGNAL ;
    PORT
      LAYER M5 ;
        RECT  22.032 17.196 22.056 17.28 ;
    END
  END d[654]
  PIN d[655]
    DIRECTION INPUT ;
    USE SIGNAL ;
    PORT
      LAYER M5 ;
        RECT  22.128 17.196 22.152 17.28 ;
    END
  END d[655]
  PIN d[656]
    DIRECTION INPUT ;
    USE SIGNAL ;
    PORT
      LAYER M5 ;
        RECT  22.224 17.196 22.248 17.28 ;
    END
  END d[656]
  PIN d[657]
    DIRECTION INPUT ;
    USE SIGNAL ;
    PORT
      LAYER M5 ;
        RECT  22.32 17.196 22.344 17.28 ;
    END
  END d[657]
  PIN d[658]
    DIRECTION INPUT ;
    USE SIGNAL ;
    PORT
      LAYER M5 ;
        RECT  22.416 17.196 22.44 17.28 ;
    END
  END d[658]
  PIN d[659]
    DIRECTION INPUT ;
    USE SIGNAL ;
    PORT
      LAYER M5 ;
        RECT  22.512 17.196 22.536 17.28 ;
    END
  END d[659]
  PIN d[65]
    DIRECTION INPUT ;
    USE SIGNAL ;
    PORT
      LAYER M5 ;
        RECT  46.128 17.196 46.152 17.28 ;
    END
  END d[65]
  PIN d[660]
    DIRECTION INPUT ;
    USE SIGNAL ;
    PORT
      LAYER M5 ;
        RECT  22.608 17.196 22.632 17.28 ;
    END
  END d[660]
  PIN d[661]
    DIRECTION INPUT ;
    USE SIGNAL ;
    PORT
      LAYER M5 ;
        RECT  22.704 17.196 22.728 17.28 ;
    END
  END d[661]
  PIN d[662]
    DIRECTION INPUT ;
    USE SIGNAL ;
    PORT
      LAYER M5 ;
        RECT  22.8 17.196 22.824 17.28 ;
    END
  END d[662]
  PIN d[663]
    DIRECTION INPUT ;
    USE SIGNAL ;
    PORT
      LAYER M5 ;
        RECT  22.896 17.196 22.92 17.28 ;
    END
  END d[663]
  PIN d[664]
    DIRECTION INPUT ;
    USE SIGNAL ;
    PORT
      LAYER M5 ;
        RECT  22.992 17.196 23.016 17.28 ;
    END
  END d[664]
  PIN d[665]
    DIRECTION INPUT ;
    USE SIGNAL ;
    PORT
      LAYER M5 ;
        RECT  23.088 17.196 23.112 17.28 ;
    END
  END d[665]
  PIN d[666]
    DIRECTION INPUT ;
    USE SIGNAL ;
    PORT
      LAYER M5 ;
        RECT  23.184 17.196 23.208 17.28 ;
    END
  END d[666]
  PIN d[667]
    DIRECTION INPUT ;
    USE SIGNAL ;
    PORT
      LAYER M5 ;
        RECT  23.28 17.196 23.304 17.28 ;
    END
  END d[667]
  PIN d[668]
    DIRECTION INPUT ;
    USE SIGNAL ;
    PORT
      LAYER M5 ;
        RECT  23.376 17.196 23.4 17.28 ;
    END
  END d[668]
  PIN d[669]
    DIRECTION INPUT ;
    USE SIGNAL ;
    PORT
      LAYER M5 ;
        RECT  23.472 17.196 23.496 17.28 ;
    END
  END d[669]
  PIN d[66]
    DIRECTION INPUT ;
    USE SIGNAL ;
    PORT
      LAYER M5 ;
        RECT  46.224 17.196 46.248 17.28 ;
    END
  END d[66]
  PIN d[670]
    DIRECTION INPUT ;
    USE SIGNAL ;
    PORT
      LAYER M5 ;
        RECT  23.568 17.196 23.592 17.28 ;
    END
  END d[670]
  PIN d[671]
    DIRECTION INPUT ;
    USE SIGNAL ;
    PORT
      LAYER M5 ;
        RECT  23.664 17.196 23.688 17.28 ;
    END
  END d[671]
  PIN d[672]
    DIRECTION INPUT ;
    USE SIGNAL ;
    PORT
      LAYER M5 ;
        RECT  78.288 17.196 78.312 17.28 ;
    END
  END d[672]
  PIN d[673]
    DIRECTION INPUT ;
    USE SIGNAL ;
    PORT
      LAYER M5 ;
        RECT  78.384 17.196 78.408 17.28 ;
    END
  END d[673]
  PIN d[674]
    DIRECTION INPUT ;
    USE SIGNAL ;
    PORT
      LAYER M5 ;
        RECT  78.48 17.196 78.504 17.28 ;
    END
  END d[674]
  PIN d[675]
    DIRECTION INPUT ;
    USE SIGNAL ;
    PORT
      LAYER M5 ;
        RECT  78.576 17.196 78.6 17.28 ;
    END
  END d[675]
  PIN d[676]
    DIRECTION INPUT ;
    USE SIGNAL ;
    PORT
      LAYER M5 ;
        RECT  78.672 17.196 78.696 17.28 ;
    END
  END d[676]
  PIN d[677]
    DIRECTION INPUT ;
    USE SIGNAL ;
    PORT
      LAYER M5 ;
        RECT  78.768 17.196 78.792 17.28 ;
    END
  END d[677]
  PIN d[678]
    DIRECTION INPUT ;
    USE SIGNAL ;
    PORT
      LAYER M5 ;
        RECT  78.864 17.196 78.888 17.28 ;
    END
  END d[678]
  PIN d[679]
    DIRECTION INPUT ;
    USE SIGNAL ;
    PORT
      LAYER M5 ;
        RECT  78.96 17.196 78.984 17.28 ;
    END
  END d[679]
  PIN d[67]
    DIRECTION INPUT ;
    USE SIGNAL ;
    PORT
      LAYER M5 ;
        RECT  46.32 17.196 46.344 17.28 ;
    END
  END d[67]
  PIN d[680]
    DIRECTION INPUT ;
    USE SIGNAL ;
    PORT
      LAYER M5 ;
        RECT  79.056 17.196 79.08 17.28 ;
    END
  END d[680]
  PIN d[681]
    DIRECTION INPUT ;
    USE SIGNAL ;
    PORT
      LAYER M5 ;
        RECT  79.152 17.196 79.176 17.28 ;
    END
  END d[681]
  PIN d[682]
    DIRECTION INPUT ;
    USE SIGNAL ;
    PORT
      LAYER M5 ;
        RECT  79.248 17.196 79.272 17.28 ;
    END
  END d[682]
  PIN d[683]
    DIRECTION INPUT ;
    USE SIGNAL ;
    PORT
      LAYER M5 ;
        RECT  79.344 17.196 79.368 17.28 ;
    END
  END d[683]
  PIN d[684]
    DIRECTION INPUT ;
    USE SIGNAL ;
    PORT
      LAYER M5 ;
        RECT  79.44 17.196 79.464 17.28 ;
    END
  END d[684]
  PIN d[685]
    DIRECTION INPUT ;
    USE SIGNAL ;
    PORT
      LAYER M5 ;
        RECT  79.536 17.196 79.56 17.28 ;
    END
  END d[685]
  PIN d[686]
    DIRECTION INPUT ;
    USE SIGNAL ;
    PORT
      LAYER M5 ;
        RECT  79.632 17.196 79.656 17.28 ;
    END
  END d[686]
  PIN d[687]
    DIRECTION INPUT ;
    USE SIGNAL ;
    PORT
      LAYER M5 ;
        RECT  79.728 17.196 79.752 17.28 ;
    END
  END d[687]
  PIN d[688]
    DIRECTION INPUT ;
    USE SIGNAL ;
    PORT
      LAYER M5 ;
        RECT  79.824 17.196 79.848 17.28 ;
    END
  END d[688]
  PIN d[689]
    DIRECTION INPUT ;
    USE SIGNAL ;
    PORT
      LAYER M5 ;
        RECT  79.92 17.196 79.944 17.28 ;
    END
  END d[689]
  PIN d[68]
    DIRECTION INPUT ;
    USE SIGNAL ;
    PORT
      LAYER M5 ;
        RECT  46.416 17.196 46.44 17.28 ;
    END
  END d[68]
  PIN d[690]
    DIRECTION INPUT ;
    USE SIGNAL ;
    PORT
      LAYER M5 ;
        RECT  80.016 17.196 80.04 17.28 ;
    END
  END d[690]
  PIN d[691]
    DIRECTION INPUT ;
    USE SIGNAL ;
    PORT
      LAYER M5 ;
        RECT  80.112 17.196 80.136 17.28 ;
    END
  END d[691]
  PIN d[692]
    DIRECTION INPUT ;
    USE SIGNAL ;
    PORT
      LAYER M5 ;
        RECT  80.208 17.196 80.232 17.28 ;
    END
  END d[692]
  PIN d[693]
    DIRECTION INPUT ;
    USE SIGNAL ;
    PORT
      LAYER M5 ;
        RECT  80.304 17.196 80.328 17.28 ;
    END
  END d[693]
  PIN d[694]
    DIRECTION INPUT ;
    USE SIGNAL ;
    PORT
      LAYER M5 ;
        RECT  80.4 17.196 80.424 17.28 ;
    END
  END d[694]
  PIN d[695]
    DIRECTION INPUT ;
    USE SIGNAL ;
    PORT
      LAYER M5 ;
        RECT  80.496 17.196 80.52 17.28 ;
    END
  END d[695]
  PIN d[696]
    DIRECTION INPUT ;
    USE SIGNAL ;
    PORT
      LAYER M5 ;
        RECT  80.592 17.196 80.616 17.28 ;
    END
  END d[696]
  PIN d[697]
    DIRECTION INPUT ;
    USE SIGNAL ;
    PORT
      LAYER M5 ;
        RECT  80.688 17.196 80.712 17.28 ;
    END
  END d[697]
  PIN d[698]
    DIRECTION INPUT ;
    USE SIGNAL ;
    PORT
      LAYER M5 ;
        RECT  80.784 17.196 80.808 17.28 ;
    END
  END d[698]
  PIN d[699]
    DIRECTION INPUT ;
    USE SIGNAL ;
    PORT
      LAYER M5 ;
        RECT  80.88 17.196 80.904 17.28 ;
    END
  END d[699]
  PIN d[69]
    DIRECTION INPUT ;
    USE SIGNAL ;
    PORT
      LAYER M5 ;
        RECT  46.512 17.196 46.536 17.28 ;
    END
  END d[69]
  PIN d[6]
    DIRECTION INPUT ;
    USE SIGNAL ;
    PORT
      LAYER M5 ;
        RECT  62.736 17.196 62.76 17.28 ;
    END
  END d[6]
  PIN d[700]
    DIRECTION INPUT ;
    USE SIGNAL ;
    PORT
      LAYER M5 ;
        RECT  80.976 17.196 81 17.28 ;
    END
  END d[700]
  PIN d[701]
    DIRECTION INPUT ;
    USE SIGNAL ;
    PORT
      LAYER M5 ;
        RECT  81.072 17.196 81.096 17.28 ;
    END
  END d[701]
  PIN d[702]
    DIRECTION INPUT ;
    USE SIGNAL ;
    PORT
      LAYER M5 ;
        RECT  81.168 17.196 81.192 17.28 ;
    END
  END d[702]
  PIN d[703]
    DIRECTION INPUT ;
    USE SIGNAL ;
    PORT
      LAYER M5 ;
        RECT  81.264 17.196 81.288 17.28 ;
    END
  END d[703]
  PIN d[704]
    DIRECTION INPUT ;
    USE SIGNAL ;
    PORT
      LAYER M5 ;
        RECT  93.648 17.196 93.672 17.28 ;
    END
  END d[704]
  PIN d[705]
    DIRECTION INPUT ;
    USE SIGNAL ;
    PORT
      LAYER M5 ;
        RECT  93.744 17.196 93.768 17.28 ;
    END
  END d[705]
  PIN d[706]
    DIRECTION INPUT ;
    USE SIGNAL ;
    PORT
      LAYER M5 ;
        RECT  93.84 17.196 93.864 17.28 ;
    END
  END d[706]
  PIN d[707]
    DIRECTION INPUT ;
    USE SIGNAL ;
    PORT
      LAYER M5 ;
        RECT  93.936 17.196 93.96 17.28 ;
    END
  END d[707]
  PIN d[708]
    DIRECTION INPUT ;
    USE SIGNAL ;
    PORT
      LAYER M5 ;
        RECT  94.032 17.196 94.056 17.28 ;
    END
  END d[708]
  PIN d[709]
    DIRECTION INPUT ;
    USE SIGNAL ;
    PORT
      LAYER M5 ;
        RECT  94.128 17.196 94.152 17.28 ;
    END
  END d[709]
  PIN d[70]
    DIRECTION INPUT ;
    USE SIGNAL ;
    PORT
      LAYER M5 ;
        RECT  46.608 17.196 46.632 17.28 ;
    END
  END d[70]
  PIN d[710]
    DIRECTION INPUT ;
    USE SIGNAL ;
    PORT
      LAYER M5 ;
        RECT  94.224 17.196 94.248 17.28 ;
    END
  END d[710]
  PIN d[711]
    DIRECTION INPUT ;
    USE SIGNAL ;
    PORT
      LAYER M5 ;
        RECT  94.32 17.196 94.344 17.28 ;
    END
  END d[711]
  PIN d[712]
    DIRECTION INPUT ;
    USE SIGNAL ;
    PORT
      LAYER M5 ;
        RECT  94.416 17.196 94.44 17.28 ;
    END
  END d[712]
  PIN d[713]
    DIRECTION INPUT ;
    USE SIGNAL ;
    PORT
      LAYER M5 ;
        RECT  94.512 17.196 94.536 17.28 ;
    END
  END d[713]
  PIN d[714]
    DIRECTION INPUT ;
    USE SIGNAL ;
    PORT
      LAYER M5 ;
        RECT  94.608 17.196 94.632 17.28 ;
    END
  END d[714]
  PIN d[715]
    DIRECTION INPUT ;
    USE SIGNAL ;
    PORT
      LAYER M5 ;
        RECT  94.704 17.196 94.728 17.28 ;
    END
  END d[715]
  PIN d[716]
    DIRECTION INPUT ;
    USE SIGNAL ;
    PORT
      LAYER M5 ;
        RECT  94.8 17.196 94.824 17.28 ;
    END
  END d[716]
  PIN d[717]
    DIRECTION INPUT ;
    USE SIGNAL ;
    PORT
      LAYER M5 ;
        RECT  94.896 17.196 94.92 17.28 ;
    END
  END d[717]
  PIN d[718]
    DIRECTION INPUT ;
    USE SIGNAL ;
    PORT
      LAYER M5 ;
        RECT  94.992 17.196 95.016 17.28 ;
    END
  END d[718]
  PIN d[719]
    DIRECTION INPUT ;
    USE SIGNAL ;
    PORT
      LAYER M5 ;
        RECT  95.088 17.196 95.112 17.28 ;
    END
  END d[719]
  PIN d[71]
    DIRECTION INPUT ;
    USE SIGNAL ;
    PORT
      LAYER M5 ;
        RECT  46.704 17.196 46.728 17.28 ;
    END
  END d[71]
  PIN d[720]
    DIRECTION INPUT ;
    USE SIGNAL ;
    PORT
      LAYER M5 ;
        RECT  95.184 17.196 95.208 17.28 ;
    END
  END d[720]
  PIN d[721]
    DIRECTION INPUT ;
    USE SIGNAL ;
    PORT
      LAYER M5 ;
        RECT  95.28 17.196 95.304 17.28 ;
    END
  END d[721]
  PIN d[722]
    DIRECTION INPUT ;
    USE SIGNAL ;
    PORT
      LAYER M5 ;
        RECT  95.376 17.196 95.4 17.28 ;
    END
  END d[722]
  PIN d[723]
    DIRECTION INPUT ;
    USE SIGNAL ;
    PORT
      LAYER M5 ;
        RECT  95.472 17.196 95.496 17.28 ;
    END
  END d[723]
  PIN d[724]
    DIRECTION INPUT ;
    USE SIGNAL ;
    PORT
      LAYER M5 ;
        RECT  95.568 17.196 95.592 17.28 ;
    END
  END d[724]
  PIN d[725]
    DIRECTION INPUT ;
    USE SIGNAL ;
    PORT
      LAYER M5 ;
        RECT  95.664 17.196 95.688 17.28 ;
    END
  END d[725]
  PIN d[726]
    DIRECTION INPUT ;
    USE SIGNAL ;
    PORT
      LAYER M5 ;
        RECT  95.76 17.196 95.784 17.28 ;
    END
  END d[726]
  PIN d[727]
    DIRECTION INPUT ;
    USE SIGNAL ;
    PORT
      LAYER M5 ;
        RECT  95.856 17.196 95.88 17.28 ;
    END
  END d[727]
  PIN d[728]
    DIRECTION INPUT ;
    USE SIGNAL ;
    PORT
      LAYER M5 ;
        RECT  95.952 17.196 95.976 17.28 ;
    END
  END d[728]
  PIN d[729]
    DIRECTION INPUT ;
    USE SIGNAL ;
    PORT
      LAYER M5 ;
        RECT  96.048 17.196 96.072 17.28 ;
    END
  END d[729]
  PIN d[72]
    DIRECTION INPUT ;
    USE SIGNAL ;
    PORT
      LAYER M5 ;
        RECT  46.8 17.196 46.824 17.28 ;
    END
  END d[72]
  PIN d[730]
    DIRECTION INPUT ;
    USE SIGNAL ;
    PORT
      LAYER M5 ;
        RECT  96.144 17.196 96.168 17.28 ;
    END
  END d[730]
  PIN d[731]
    DIRECTION INPUT ;
    USE SIGNAL ;
    PORT
      LAYER M5 ;
        RECT  96.24 17.196 96.264 17.28 ;
    END
  END d[731]
  PIN d[732]
    DIRECTION INPUT ;
    USE SIGNAL ;
    PORT
      LAYER M5 ;
        RECT  96.336 17.196 96.36 17.28 ;
    END
  END d[732]
  PIN d[733]
    DIRECTION INPUT ;
    USE SIGNAL ;
    PORT
      LAYER M5 ;
        RECT  96.432 17.196 96.456 17.28 ;
    END
  END d[733]
  PIN d[734]
    DIRECTION INPUT ;
    USE SIGNAL ;
    PORT
      LAYER M5 ;
        RECT  96.528 17.196 96.552 17.28 ;
    END
  END d[734]
  PIN d[735]
    DIRECTION INPUT ;
    USE SIGNAL ;
    PORT
      LAYER M5 ;
        RECT  96.624 17.196 96.648 17.28 ;
    END
  END d[735]
  PIN d[736]
    DIRECTION INPUT ;
    USE SIGNAL ;
    PORT
      LAYER M5 ;
        RECT  87.504 17.196 87.528 17.28 ;
    END
  END d[736]
  PIN d[737]
    DIRECTION INPUT ;
    USE SIGNAL ;
    PORT
      LAYER M5 ;
        RECT  87.6 17.196 87.624 17.28 ;
    END
  END d[737]
  PIN d[738]
    DIRECTION INPUT ;
    USE SIGNAL ;
    PORT
      LAYER M5 ;
        RECT  87.696 17.196 87.72 17.28 ;
    END
  END d[738]
  PIN d[739]
    DIRECTION INPUT ;
    USE SIGNAL ;
    PORT
      LAYER M5 ;
        RECT  87.792 17.196 87.816 17.28 ;
    END
  END d[739]
  PIN d[73]
    DIRECTION INPUT ;
    USE SIGNAL ;
    PORT
      LAYER M5 ;
        RECT  46.896 17.196 46.92 17.28 ;
    END
  END d[73]
  PIN d[740]
    DIRECTION INPUT ;
    USE SIGNAL ;
    PORT
      LAYER M5 ;
        RECT  87.888 17.196 87.912 17.28 ;
    END
  END d[740]
  PIN d[741]
    DIRECTION INPUT ;
    USE SIGNAL ;
    PORT
      LAYER M5 ;
        RECT  87.984 17.196 88.008 17.28 ;
    END
  END d[741]
  PIN d[742]
    DIRECTION INPUT ;
    USE SIGNAL ;
    PORT
      LAYER M5 ;
        RECT  88.08 17.196 88.104 17.28 ;
    END
  END d[742]
  PIN d[743]
    DIRECTION INPUT ;
    USE SIGNAL ;
    PORT
      LAYER M5 ;
        RECT  88.176 17.196 88.2 17.28 ;
    END
  END d[743]
  PIN d[744]
    DIRECTION INPUT ;
    USE SIGNAL ;
    PORT
      LAYER M5 ;
        RECT  88.272 17.196 88.296 17.28 ;
    END
  END d[744]
  PIN d[745]
    DIRECTION INPUT ;
    USE SIGNAL ;
    PORT
      LAYER M5 ;
        RECT  88.368 17.196 88.392 17.28 ;
    END
  END d[745]
  PIN d[746]
    DIRECTION INPUT ;
    USE SIGNAL ;
    PORT
      LAYER M5 ;
        RECT  88.464 17.196 88.488 17.28 ;
    END
  END d[746]
  PIN d[747]
    DIRECTION INPUT ;
    USE SIGNAL ;
    PORT
      LAYER M5 ;
        RECT  88.56 17.196 88.584 17.28 ;
    END
  END d[747]
  PIN d[748]
    DIRECTION INPUT ;
    USE SIGNAL ;
    PORT
      LAYER M5 ;
        RECT  88.656 17.196 88.68 17.28 ;
    END
  END d[748]
  PIN d[749]
    DIRECTION INPUT ;
    USE SIGNAL ;
    PORT
      LAYER M5 ;
        RECT  88.752 17.196 88.776 17.28 ;
    END
  END d[749]
  PIN d[74]
    DIRECTION INPUT ;
    USE SIGNAL ;
    PORT
      LAYER M5 ;
        RECT  46.992 17.196 47.016 17.28 ;
    END
  END d[74]
  PIN d[750]
    DIRECTION INPUT ;
    USE SIGNAL ;
    PORT
      LAYER M5 ;
        RECT  88.848 17.196 88.872 17.28 ;
    END
  END d[750]
  PIN d[751]
    DIRECTION INPUT ;
    USE SIGNAL ;
    PORT
      LAYER M5 ;
        RECT  88.944 17.196 88.968 17.28 ;
    END
  END d[751]
  PIN d[752]
    DIRECTION INPUT ;
    USE SIGNAL ;
    PORT
      LAYER M5 ;
        RECT  89.04 17.196 89.064 17.28 ;
    END
  END d[752]
  PIN d[753]
    DIRECTION INPUT ;
    USE SIGNAL ;
    PORT
      LAYER M5 ;
        RECT  89.136 17.196 89.16 17.28 ;
    END
  END d[753]
  PIN d[754]
    DIRECTION INPUT ;
    USE SIGNAL ;
    PORT
      LAYER M5 ;
        RECT  89.232 17.196 89.256 17.28 ;
    END
  END d[754]
  PIN d[755]
    DIRECTION INPUT ;
    USE SIGNAL ;
    PORT
      LAYER M5 ;
        RECT  89.328 17.196 89.352 17.28 ;
    END
  END d[755]
  PIN d[756]
    DIRECTION INPUT ;
    USE SIGNAL ;
    PORT
      LAYER M5 ;
        RECT  89.424 17.196 89.448 17.28 ;
    END
  END d[756]
  PIN d[757]
    DIRECTION INPUT ;
    USE SIGNAL ;
    PORT
      LAYER M5 ;
        RECT  89.52 17.196 89.544 17.28 ;
    END
  END d[757]
  PIN d[758]
    DIRECTION INPUT ;
    USE SIGNAL ;
    PORT
      LAYER M5 ;
        RECT  89.616 17.196 89.64 17.28 ;
    END
  END d[758]
  PIN d[759]
    DIRECTION INPUT ;
    USE SIGNAL ;
    PORT
      LAYER M5 ;
        RECT  89.712 17.196 89.736 17.28 ;
    END
  END d[759]
  PIN d[75]
    DIRECTION INPUT ;
    USE SIGNAL ;
    PORT
      LAYER M5 ;
        RECT  47.088 17.196 47.112 17.28 ;
    END
  END d[75]
  PIN d[760]
    DIRECTION INPUT ;
    USE SIGNAL ;
    PORT
      LAYER M5 ;
        RECT  89.808 17.196 89.832 17.28 ;
    END
  END d[760]
  PIN d[761]
    DIRECTION INPUT ;
    USE SIGNAL ;
    PORT
      LAYER M5 ;
        RECT  89.904 17.196 89.928 17.28 ;
    END
  END d[761]
  PIN d[762]
    DIRECTION INPUT ;
    USE SIGNAL ;
    PORT
      LAYER M5 ;
        RECT  90 17.196 90.024 17.28 ;
    END
  END d[762]
  PIN d[763]
    DIRECTION INPUT ;
    USE SIGNAL ;
    PORT
      LAYER M5 ;
        RECT  90.096 17.196 90.12 17.28 ;
    END
  END d[763]
  PIN d[764]
    DIRECTION INPUT ;
    USE SIGNAL ;
    PORT
      LAYER M5 ;
        RECT  90.192 17.196 90.216 17.28 ;
    END
  END d[764]
  PIN d[765]
    DIRECTION INPUT ;
    USE SIGNAL ;
    PORT
      LAYER M5 ;
        RECT  90.288 17.196 90.312 17.28 ;
    END
  END d[765]
  PIN d[766]
    DIRECTION INPUT ;
    USE SIGNAL ;
    PORT
      LAYER M5 ;
        RECT  90.384 17.196 90.408 17.28 ;
    END
  END d[766]
  PIN d[767]
    DIRECTION INPUT ;
    USE SIGNAL ;
    PORT
      LAYER M5 ;
        RECT  90.48 17.196 90.504 17.28 ;
    END
  END d[767]
  PIN d[768]
    DIRECTION INPUT ;
    USE SIGNAL ;
    PORT
      LAYER M5 ;
        RECT  106.704 17.196 106.728 17.28 ;
    END
  END d[768]
  PIN d[769]
    DIRECTION INPUT ;
    USE SIGNAL ;
    PORT
      LAYER M5 ;
        RECT  106.8 17.196 106.824 17.28 ;
    END
  END d[769]
  PIN d[76]
    DIRECTION INPUT ;
    USE SIGNAL ;
    PORT
      LAYER M5 ;
        RECT  47.184 17.196 47.208 17.28 ;
    END
  END d[76]
  PIN d[770]
    DIRECTION INPUT ;
    USE SIGNAL ;
    PORT
      LAYER M5 ;
        RECT  106.896 17.196 106.92 17.28 ;
    END
  END d[770]
  PIN d[771]
    DIRECTION INPUT ;
    USE SIGNAL ;
    PORT
      LAYER M5 ;
        RECT  106.992 17.196 107.016 17.28 ;
    END
  END d[771]
  PIN d[772]
    DIRECTION INPUT ;
    USE SIGNAL ;
    PORT
      LAYER M5 ;
        RECT  107.088 17.196 107.112 17.28 ;
    END
  END d[772]
  PIN d[773]
    DIRECTION INPUT ;
    USE SIGNAL ;
    PORT
      LAYER M5 ;
        RECT  107.184 17.196 107.208 17.28 ;
    END
  END d[773]
  PIN d[774]
    DIRECTION INPUT ;
    USE SIGNAL ;
    PORT
      LAYER M5 ;
        RECT  107.28 17.196 107.304 17.28 ;
    END
  END d[774]
  PIN d[775]
    DIRECTION INPUT ;
    USE SIGNAL ;
    PORT
      LAYER M5 ;
        RECT  107.376 17.196 107.4 17.28 ;
    END
  END d[775]
  PIN d[776]
    DIRECTION INPUT ;
    USE SIGNAL ;
    PORT
      LAYER M5 ;
        RECT  107.472 17.196 107.496 17.28 ;
    END
  END d[776]
  PIN d[777]
    DIRECTION INPUT ;
    USE SIGNAL ;
    PORT
      LAYER M5 ;
        RECT  107.568 17.196 107.592 17.28 ;
    END
  END d[777]
  PIN d[778]
    DIRECTION INPUT ;
    USE SIGNAL ;
    PORT
      LAYER M5 ;
        RECT  107.664 17.196 107.688 17.28 ;
    END
  END d[778]
  PIN d[779]
    DIRECTION INPUT ;
    USE SIGNAL ;
    PORT
      LAYER M5 ;
        RECT  107.76 17.196 107.784 17.28 ;
    END
  END d[779]
  PIN d[77]
    DIRECTION INPUT ;
    USE SIGNAL ;
    PORT
      LAYER M5 ;
        RECT  47.28 17.196 47.304 17.28 ;
    END
  END d[77]
  PIN d[780]
    DIRECTION INPUT ;
    USE SIGNAL ;
    PORT
      LAYER M5 ;
        RECT  107.856 17.196 107.88 17.28 ;
    END
  END d[780]
  PIN d[781]
    DIRECTION INPUT ;
    USE SIGNAL ;
    PORT
      LAYER M5 ;
        RECT  107.952 17.196 107.976 17.28 ;
    END
  END d[781]
  PIN d[782]
    DIRECTION INPUT ;
    USE SIGNAL ;
    PORT
      LAYER M5 ;
        RECT  108.048 17.196 108.072 17.28 ;
    END
  END d[782]
  PIN d[783]
    DIRECTION INPUT ;
    USE SIGNAL ;
    PORT
      LAYER M5 ;
        RECT  108.144 17.196 108.168 17.28 ;
    END
  END d[783]
  PIN d[784]
    DIRECTION INPUT ;
    USE SIGNAL ;
    PORT
      LAYER M5 ;
        RECT  108.24 17.196 108.264 17.28 ;
    END
  END d[784]
  PIN d[785]
    DIRECTION INPUT ;
    USE SIGNAL ;
    PORT
      LAYER M5 ;
        RECT  108.336 17.196 108.36 17.28 ;
    END
  END d[785]
  PIN d[786]
    DIRECTION INPUT ;
    USE SIGNAL ;
    PORT
      LAYER M5 ;
        RECT  108.432 17.196 108.456 17.28 ;
    END
  END d[786]
  PIN d[787]
    DIRECTION INPUT ;
    USE SIGNAL ;
    PORT
      LAYER M5 ;
        RECT  108.528 17.196 108.552 17.28 ;
    END
  END d[787]
  PIN d[788]
    DIRECTION INPUT ;
    USE SIGNAL ;
    PORT
      LAYER M5 ;
        RECT  108.624 17.196 108.648 17.28 ;
    END
  END d[788]
  PIN d[789]
    DIRECTION INPUT ;
    USE SIGNAL ;
    PORT
      LAYER M5 ;
        RECT  108.72 17.196 108.744 17.28 ;
    END
  END d[789]
  PIN d[78]
    DIRECTION INPUT ;
    USE SIGNAL ;
    PORT
      LAYER M5 ;
        RECT  47.376 17.196 47.4 17.28 ;
    END
  END d[78]
  PIN d[790]
    DIRECTION INPUT ;
    USE SIGNAL ;
    PORT
      LAYER M5 ;
        RECT  108.816 17.196 108.84 17.28 ;
    END
  END d[790]
  PIN d[791]
    DIRECTION INPUT ;
    USE SIGNAL ;
    PORT
      LAYER M5 ;
        RECT  108.912 17.196 108.936 17.28 ;
    END
  END d[791]
  PIN d[792]
    DIRECTION INPUT ;
    USE SIGNAL ;
    PORT
      LAYER M5 ;
        RECT  109.008 17.196 109.032 17.28 ;
    END
  END d[792]
  PIN d[793]
    DIRECTION INPUT ;
    USE SIGNAL ;
    PORT
      LAYER M5 ;
        RECT  109.104 17.196 109.128 17.28 ;
    END
  END d[793]
  PIN d[794]
    DIRECTION INPUT ;
    USE SIGNAL ;
    PORT
      LAYER M5 ;
        RECT  109.2 17.196 109.224 17.28 ;
    END
  END d[794]
  PIN d[795]
    DIRECTION INPUT ;
    USE SIGNAL ;
    PORT
      LAYER M5 ;
        RECT  109.296 17.196 109.32 17.28 ;
    END
  END d[795]
  PIN d[796]
    DIRECTION INPUT ;
    USE SIGNAL ;
    PORT
      LAYER M5 ;
        RECT  109.392 17.196 109.416 17.28 ;
    END
  END d[796]
  PIN d[797]
    DIRECTION INPUT ;
    USE SIGNAL ;
    PORT
      LAYER M5 ;
        RECT  109.488 17.196 109.512 17.28 ;
    END
  END d[797]
  PIN d[798]
    DIRECTION INPUT ;
    USE SIGNAL ;
    PORT
      LAYER M5 ;
        RECT  109.584 17.196 109.608 17.28 ;
    END
  END d[798]
  PIN d[799]
    DIRECTION INPUT ;
    USE SIGNAL ;
    PORT
      LAYER M5 ;
        RECT  109.68 17.196 109.704 17.28 ;
    END
  END d[799]
  PIN d[79]
    DIRECTION INPUT ;
    USE SIGNAL ;
    PORT
      LAYER M5 ;
        RECT  47.472 17.196 47.496 17.28 ;
    END
  END d[79]
  PIN d[7]
    DIRECTION INPUT ;
    USE SIGNAL ;
    PORT
      LAYER M5 ;
        RECT  62.832 17.196 62.856 17.28 ;
    END
  END d[7]
  PIN d[800]
    DIRECTION INPUT ;
    USE SIGNAL ;
    PORT
      LAYER M5 ;
        RECT  103.632 17.196 103.656 17.28 ;
    END
  END d[800]
  PIN d[801]
    DIRECTION INPUT ;
    USE SIGNAL ;
    PORT
      LAYER M5 ;
        RECT  103.728 17.196 103.752 17.28 ;
    END
  END d[801]
  PIN d[802]
    DIRECTION INPUT ;
    USE SIGNAL ;
    PORT
      LAYER M5 ;
        RECT  103.824 17.196 103.848 17.28 ;
    END
  END d[802]
  PIN d[803]
    DIRECTION INPUT ;
    USE SIGNAL ;
    PORT
      LAYER M5 ;
        RECT  103.92 17.196 103.944 17.28 ;
    END
  END d[803]
  PIN d[804]
    DIRECTION INPUT ;
    USE SIGNAL ;
    PORT
      LAYER M5 ;
        RECT  104.016 17.196 104.04 17.28 ;
    END
  END d[804]
  PIN d[805]
    DIRECTION INPUT ;
    USE SIGNAL ;
    PORT
      LAYER M5 ;
        RECT  104.112 17.196 104.136 17.28 ;
    END
  END d[805]
  PIN d[806]
    DIRECTION INPUT ;
    USE SIGNAL ;
    PORT
      LAYER M5 ;
        RECT  104.208 17.196 104.232 17.28 ;
    END
  END d[806]
  PIN d[807]
    DIRECTION INPUT ;
    USE SIGNAL ;
    PORT
      LAYER M5 ;
        RECT  104.304 17.196 104.328 17.28 ;
    END
  END d[807]
  PIN d[808]
    DIRECTION INPUT ;
    USE SIGNAL ;
    PORT
      LAYER M5 ;
        RECT  104.4 17.196 104.424 17.28 ;
    END
  END d[808]
  PIN d[809]
    DIRECTION INPUT ;
    USE SIGNAL ;
    PORT
      LAYER M5 ;
        RECT  104.496 17.196 104.52 17.28 ;
    END
  END d[809]
  PIN d[80]
    DIRECTION INPUT ;
    USE SIGNAL ;
    PORT
      LAYER M5 ;
        RECT  47.568 17.196 47.592 17.28 ;
    END
  END d[80]
  PIN d[810]
    DIRECTION INPUT ;
    USE SIGNAL ;
    PORT
      LAYER M5 ;
        RECT  104.592 17.196 104.616 17.28 ;
    END
  END d[810]
  PIN d[811]
    DIRECTION INPUT ;
    USE SIGNAL ;
    PORT
      LAYER M5 ;
        RECT  104.688 17.196 104.712 17.28 ;
    END
  END d[811]
  PIN d[812]
    DIRECTION INPUT ;
    USE SIGNAL ;
    PORT
      LAYER M5 ;
        RECT  104.784 17.196 104.808 17.28 ;
    END
  END d[812]
  PIN d[813]
    DIRECTION INPUT ;
    USE SIGNAL ;
    PORT
      LAYER M5 ;
        RECT  104.88 17.196 104.904 17.28 ;
    END
  END d[813]
  PIN d[814]
    DIRECTION INPUT ;
    USE SIGNAL ;
    PORT
      LAYER M5 ;
        RECT  104.976 17.196 105 17.28 ;
    END
  END d[814]
  PIN d[815]
    DIRECTION INPUT ;
    USE SIGNAL ;
    PORT
      LAYER M5 ;
        RECT  105.072 17.196 105.096 17.28 ;
    END
  END d[815]
  PIN d[816]
    DIRECTION INPUT ;
    USE SIGNAL ;
    PORT
      LAYER M5 ;
        RECT  105.168 17.196 105.192 17.28 ;
    END
  END d[816]
  PIN d[817]
    DIRECTION INPUT ;
    USE SIGNAL ;
    PORT
      LAYER M5 ;
        RECT  105.264 17.196 105.288 17.28 ;
    END
  END d[817]
  PIN d[818]
    DIRECTION INPUT ;
    USE SIGNAL ;
    PORT
      LAYER M5 ;
        RECT  105.36 17.196 105.384 17.28 ;
    END
  END d[818]
  PIN d[819]
    DIRECTION INPUT ;
    USE SIGNAL ;
    PORT
      LAYER M5 ;
        RECT  105.456 17.196 105.48 17.28 ;
    END
  END d[819]
  PIN d[81]
    DIRECTION INPUT ;
    USE SIGNAL ;
    PORT
      LAYER M5 ;
        RECT  47.664 17.196 47.688 17.28 ;
    END
  END d[81]
  PIN d[820]
    DIRECTION INPUT ;
    USE SIGNAL ;
    PORT
      LAYER M5 ;
        RECT  105.552 17.196 105.576 17.28 ;
    END
  END d[820]
  PIN d[821]
    DIRECTION INPUT ;
    USE SIGNAL ;
    PORT
      LAYER M5 ;
        RECT  105.648 17.196 105.672 17.28 ;
    END
  END d[821]
  PIN d[822]
    DIRECTION INPUT ;
    USE SIGNAL ;
    PORT
      LAYER M5 ;
        RECT  105.744 17.196 105.768 17.28 ;
    END
  END d[822]
  PIN d[823]
    DIRECTION INPUT ;
    USE SIGNAL ;
    PORT
      LAYER M5 ;
        RECT  105.84 17.196 105.864 17.28 ;
    END
  END d[823]
  PIN d[824]
    DIRECTION INPUT ;
    USE SIGNAL ;
    PORT
      LAYER M5 ;
        RECT  105.936 17.196 105.96 17.28 ;
    END
  END d[824]
  PIN d[825]
    DIRECTION INPUT ;
    USE SIGNAL ;
    PORT
      LAYER M5 ;
        RECT  106.032 17.196 106.056 17.28 ;
    END
  END d[825]
  PIN d[826]
    DIRECTION INPUT ;
    USE SIGNAL ;
    PORT
      LAYER M5 ;
        RECT  106.128 17.196 106.152 17.28 ;
    END
  END d[826]
  PIN d[827]
    DIRECTION INPUT ;
    USE SIGNAL ;
    PORT
      LAYER M5 ;
        RECT  106.224 17.196 106.248 17.28 ;
    END
  END d[827]
  PIN d[828]
    DIRECTION INPUT ;
    USE SIGNAL ;
    PORT
      LAYER M5 ;
        RECT  106.32 17.196 106.344 17.28 ;
    END
  END d[828]
  PIN d[829]
    DIRECTION INPUT ;
    USE SIGNAL ;
    PORT
      LAYER M5 ;
        RECT  106.416 17.196 106.44 17.28 ;
    END
  END d[829]
  PIN d[82]
    DIRECTION INPUT ;
    USE SIGNAL ;
    PORT
      LAYER M5 ;
        RECT  47.76 17.196 47.784 17.28 ;
    END
  END d[82]
  PIN d[830]
    DIRECTION INPUT ;
    USE SIGNAL ;
    PORT
      LAYER M5 ;
        RECT  106.512 17.196 106.536 17.28 ;
    END
  END d[830]
  PIN d[831]
    DIRECTION INPUT ;
    USE SIGNAL ;
    PORT
      LAYER M5 ;
        RECT  106.608 17.196 106.632 17.28 ;
    END
  END d[831]
  PIN d[832]
    DIRECTION INPUT ;
    USE SIGNAL ;
    PORT
      LAYER M5 ;
        RECT  100.56 17.196 100.584 17.28 ;
    END
  END d[832]
  PIN d[833]
    DIRECTION INPUT ;
    USE SIGNAL ;
    PORT
      LAYER M5 ;
        RECT  100.656 17.196 100.68 17.28 ;
    END
  END d[833]
  PIN d[834]
    DIRECTION INPUT ;
    USE SIGNAL ;
    PORT
      LAYER M5 ;
        RECT  100.752 17.196 100.776 17.28 ;
    END
  END d[834]
  PIN d[835]
    DIRECTION INPUT ;
    USE SIGNAL ;
    PORT
      LAYER M5 ;
        RECT  100.848 17.196 100.872 17.28 ;
    END
  END d[835]
  PIN d[836]
    DIRECTION INPUT ;
    USE SIGNAL ;
    PORT
      LAYER M5 ;
        RECT  100.944 17.196 100.968 17.28 ;
    END
  END d[836]
  PIN d[837]
    DIRECTION INPUT ;
    USE SIGNAL ;
    PORT
      LAYER M5 ;
        RECT  101.04 17.196 101.064 17.28 ;
    END
  END d[837]
  PIN d[838]
    DIRECTION INPUT ;
    USE SIGNAL ;
    PORT
      LAYER M5 ;
        RECT  101.136 17.196 101.16 17.28 ;
    END
  END d[838]
  PIN d[839]
    DIRECTION INPUT ;
    USE SIGNAL ;
    PORT
      LAYER M5 ;
        RECT  101.232 17.196 101.256 17.28 ;
    END
  END d[839]
  PIN d[83]
    DIRECTION INPUT ;
    USE SIGNAL ;
    PORT
      LAYER M5 ;
        RECT  47.856 17.196 47.88 17.28 ;
    END
  END d[83]
  PIN d[840]
    DIRECTION INPUT ;
    USE SIGNAL ;
    PORT
      LAYER M5 ;
        RECT  101.328 17.196 101.352 17.28 ;
    END
  END d[840]
  PIN d[841]
    DIRECTION INPUT ;
    USE SIGNAL ;
    PORT
      LAYER M5 ;
        RECT  101.424 17.196 101.448 17.28 ;
    END
  END d[841]
  PIN d[842]
    DIRECTION INPUT ;
    USE SIGNAL ;
    PORT
      LAYER M5 ;
        RECT  101.52 17.196 101.544 17.28 ;
    END
  END d[842]
  PIN d[843]
    DIRECTION INPUT ;
    USE SIGNAL ;
    PORT
      LAYER M5 ;
        RECT  101.616 17.196 101.64 17.28 ;
    END
  END d[843]
  PIN d[844]
    DIRECTION INPUT ;
    USE SIGNAL ;
    PORT
      LAYER M5 ;
        RECT  101.712 17.196 101.736 17.28 ;
    END
  END d[844]
  PIN d[845]
    DIRECTION INPUT ;
    USE SIGNAL ;
    PORT
      LAYER M5 ;
        RECT  101.808 17.196 101.832 17.28 ;
    END
  END d[845]
  PIN d[846]
    DIRECTION INPUT ;
    USE SIGNAL ;
    PORT
      LAYER M5 ;
        RECT  101.904 17.196 101.928 17.28 ;
    END
  END d[846]
  PIN d[847]
    DIRECTION INPUT ;
    USE SIGNAL ;
    PORT
      LAYER M5 ;
        RECT  102 17.196 102.024 17.28 ;
    END
  END d[847]
  PIN d[848]
    DIRECTION INPUT ;
    USE SIGNAL ;
    PORT
      LAYER M5 ;
        RECT  102.096 17.196 102.12 17.28 ;
    END
  END d[848]
  PIN d[849]
    DIRECTION INPUT ;
    USE SIGNAL ;
    PORT
      LAYER M5 ;
        RECT  102.192 17.196 102.216 17.28 ;
    END
  END d[849]
  PIN d[84]
    DIRECTION INPUT ;
    USE SIGNAL ;
    PORT
      LAYER M5 ;
        RECT  47.952 17.196 47.976 17.28 ;
    END
  END d[84]
  PIN d[850]
    DIRECTION INPUT ;
    USE SIGNAL ;
    PORT
      LAYER M5 ;
        RECT  102.288 17.196 102.312 17.28 ;
    END
  END d[850]
  PIN d[851]
    DIRECTION INPUT ;
    USE SIGNAL ;
    PORT
      LAYER M5 ;
        RECT  102.384 17.196 102.408 17.28 ;
    END
  END d[851]
  PIN d[852]
    DIRECTION INPUT ;
    USE SIGNAL ;
    PORT
      LAYER M5 ;
        RECT  102.48 17.196 102.504 17.28 ;
    END
  END d[852]
  PIN d[853]
    DIRECTION INPUT ;
    USE SIGNAL ;
    PORT
      LAYER M5 ;
        RECT  102.576 17.196 102.6 17.28 ;
    END
  END d[853]
  PIN d[854]
    DIRECTION INPUT ;
    USE SIGNAL ;
    PORT
      LAYER M5 ;
        RECT  102.672 17.196 102.696 17.28 ;
    END
  END d[854]
  PIN d[855]
    DIRECTION INPUT ;
    USE SIGNAL ;
    PORT
      LAYER M5 ;
        RECT  102.768 17.196 102.792 17.28 ;
    END
  END d[855]
  PIN d[856]
    DIRECTION INPUT ;
    USE SIGNAL ;
    PORT
      LAYER M5 ;
        RECT  102.864 17.196 102.888 17.28 ;
    END
  END d[856]
  PIN d[857]
    DIRECTION INPUT ;
    USE SIGNAL ;
    PORT
      LAYER M5 ;
        RECT  102.96 17.196 102.984 17.28 ;
    END
  END d[857]
  PIN d[858]
    DIRECTION INPUT ;
    USE SIGNAL ;
    PORT
      LAYER M5 ;
        RECT  103.056 17.196 103.08 17.28 ;
    END
  END d[858]
  PIN d[859]
    DIRECTION INPUT ;
    USE SIGNAL ;
    PORT
      LAYER M5 ;
        RECT  103.152 17.196 103.176 17.28 ;
    END
  END d[859]
  PIN d[85]
    DIRECTION INPUT ;
    USE SIGNAL ;
    PORT
      LAYER M5 ;
        RECT  48.048 17.196 48.072 17.28 ;
    END
  END d[85]
  PIN d[860]
    DIRECTION INPUT ;
    USE SIGNAL ;
    PORT
      LAYER M5 ;
        RECT  103.248 17.196 103.272 17.28 ;
    END
  END d[860]
  PIN d[861]
    DIRECTION INPUT ;
    USE SIGNAL ;
    PORT
      LAYER M5 ;
        RECT  103.344 17.196 103.368 17.28 ;
    END
  END d[861]
  PIN d[862]
    DIRECTION INPUT ;
    USE SIGNAL ;
    PORT
      LAYER M5 ;
        RECT  103.44 17.196 103.464 17.28 ;
    END
  END d[862]
  PIN d[863]
    DIRECTION INPUT ;
    USE SIGNAL ;
    PORT
      LAYER M5 ;
        RECT  103.536 17.196 103.56 17.28 ;
    END
  END d[863]
  PIN d[864]
    DIRECTION INPUT ;
    USE SIGNAL ;
    PORT
      LAYER M5 ;
        RECT  16.848 17.196 16.872 17.28 ;
    END
  END d[864]
  PIN d[865]
    DIRECTION INPUT ;
    USE SIGNAL ;
    PORT
      LAYER M5 ;
        RECT  16.944 17.196 16.968 17.28 ;
    END
  END d[865]
  PIN d[866]
    DIRECTION INPUT ;
    USE SIGNAL ;
    PORT
      LAYER M5 ;
        RECT  17.04 17.196 17.064 17.28 ;
    END
  END d[866]
  PIN d[867]
    DIRECTION INPUT ;
    USE SIGNAL ;
    PORT
      LAYER M5 ;
        RECT  17.136 17.196 17.16 17.28 ;
    END
  END d[867]
  PIN d[868]
    DIRECTION INPUT ;
    USE SIGNAL ;
    PORT
      LAYER M5 ;
        RECT  17.232 17.196 17.256 17.28 ;
    END
  END d[868]
  PIN d[869]
    DIRECTION INPUT ;
    USE SIGNAL ;
    PORT
      LAYER M5 ;
        RECT  17.328 17.196 17.352 17.28 ;
    END
  END d[869]
  PIN d[86]
    DIRECTION INPUT ;
    USE SIGNAL ;
    PORT
      LAYER M5 ;
        RECT  48.144 17.196 48.168 17.28 ;
    END
  END d[86]
  PIN d[870]
    DIRECTION INPUT ;
    USE SIGNAL ;
    PORT
      LAYER M5 ;
        RECT  17.424 17.196 17.448 17.28 ;
    END
  END d[870]
  PIN d[871]
    DIRECTION INPUT ;
    USE SIGNAL ;
    PORT
      LAYER M5 ;
        RECT  17.52 17.196 17.544 17.28 ;
    END
  END d[871]
  PIN d[872]
    DIRECTION INPUT ;
    USE SIGNAL ;
    PORT
      LAYER M5 ;
        RECT  17.616 17.196 17.64 17.28 ;
    END
  END d[872]
  PIN d[873]
    DIRECTION INPUT ;
    USE SIGNAL ;
    PORT
      LAYER M5 ;
        RECT  17.712 17.196 17.736 17.28 ;
    END
  END d[873]
  PIN d[874]
    DIRECTION INPUT ;
    USE SIGNAL ;
    PORT
      LAYER M5 ;
        RECT  17.808 17.196 17.832 17.28 ;
    END
  END d[874]
  PIN d[875]
    DIRECTION INPUT ;
    USE SIGNAL ;
    PORT
      LAYER M5 ;
        RECT  17.904 17.196 17.928 17.28 ;
    END
  END d[875]
  PIN d[876]
    DIRECTION INPUT ;
    USE SIGNAL ;
    PORT
      LAYER M5 ;
        RECT  18 17.196 18.024 17.28 ;
    END
  END d[876]
  PIN d[877]
    DIRECTION INPUT ;
    USE SIGNAL ;
    PORT
      LAYER M5 ;
        RECT  18.096 17.196 18.12 17.28 ;
    END
  END d[877]
  PIN d[878]
    DIRECTION INPUT ;
    USE SIGNAL ;
    PORT
      LAYER M5 ;
        RECT  18.192 17.196 18.216 17.28 ;
    END
  END d[878]
  PIN d[879]
    DIRECTION INPUT ;
    USE SIGNAL ;
    PORT
      LAYER M5 ;
        RECT  18.288 17.196 18.312 17.28 ;
    END
  END d[879]
  PIN d[87]
    DIRECTION INPUT ;
    USE SIGNAL ;
    PORT
      LAYER M5 ;
        RECT  48.24 17.196 48.264 17.28 ;
    END
  END d[87]
  PIN d[880]
    DIRECTION INPUT ;
    USE SIGNAL ;
    PORT
      LAYER M5 ;
        RECT  18.384 17.196 18.408 17.28 ;
    END
  END d[880]
  PIN d[881]
    DIRECTION INPUT ;
    USE SIGNAL ;
    PORT
      LAYER M5 ;
        RECT  18.48 17.196 18.504 17.28 ;
    END
  END d[881]
  PIN d[882]
    DIRECTION INPUT ;
    USE SIGNAL ;
    PORT
      LAYER M5 ;
        RECT  18.576 17.196 18.6 17.28 ;
    END
  END d[882]
  PIN d[883]
    DIRECTION INPUT ;
    USE SIGNAL ;
    PORT
      LAYER M5 ;
        RECT  18.672 17.196 18.696 17.28 ;
    END
  END d[883]
  PIN d[884]
    DIRECTION INPUT ;
    USE SIGNAL ;
    PORT
      LAYER M5 ;
        RECT  18.768 17.196 18.792 17.28 ;
    END
  END d[884]
  PIN d[885]
    DIRECTION INPUT ;
    USE SIGNAL ;
    PORT
      LAYER M5 ;
        RECT  18.864 17.196 18.888 17.28 ;
    END
  END d[885]
  PIN d[886]
    DIRECTION INPUT ;
    USE SIGNAL ;
    PORT
      LAYER M5 ;
        RECT  18.96 17.196 18.984 17.28 ;
    END
  END d[886]
  PIN d[887]
    DIRECTION INPUT ;
    USE SIGNAL ;
    PORT
      LAYER M5 ;
        RECT  19.056 17.196 19.08 17.28 ;
    END
  END d[887]
  PIN d[888]
    DIRECTION INPUT ;
    USE SIGNAL ;
    PORT
      LAYER M5 ;
        RECT  19.152 17.196 19.176 17.28 ;
    END
  END d[888]
  PIN d[889]
    DIRECTION INPUT ;
    USE SIGNAL ;
    PORT
      LAYER M5 ;
        RECT  19.248 17.196 19.272 17.28 ;
    END
  END d[889]
  PIN d[88]
    DIRECTION INPUT ;
    USE SIGNAL ;
    PORT
      LAYER M5 ;
        RECT  48.336 17.196 48.36 17.28 ;
    END
  END d[88]
  PIN d[890]
    DIRECTION INPUT ;
    USE SIGNAL ;
    PORT
      LAYER M5 ;
        RECT  19.344 17.196 19.368 17.28 ;
    END
  END d[890]
  PIN d[891]
    DIRECTION INPUT ;
    USE SIGNAL ;
    PORT
      LAYER M5 ;
        RECT  19.44 17.196 19.464 17.28 ;
    END
  END d[891]
  PIN d[892]
    DIRECTION INPUT ;
    USE SIGNAL ;
    PORT
      LAYER M5 ;
        RECT  19.536 17.196 19.56 17.28 ;
    END
  END d[892]
  PIN d[893]
    DIRECTION INPUT ;
    USE SIGNAL ;
    PORT
      LAYER M5 ;
        RECT  19.632 17.196 19.656 17.28 ;
    END
  END d[893]
  PIN d[894]
    DIRECTION INPUT ;
    USE SIGNAL ;
    PORT
      LAYER M5 ;
        RECT  19.728 17.196 19.752 17.28 ;
    END
  END d[894]
  PIN d[895]
    DIRECTION INPUT ;
    USE SIGNAL ;
    PORT
      LAYER M5 ;
        RECT  19.824 17.196 19.848 17.28 ;
    END
  END d[895]
  PIN d[896]
    DIRECTION INPUT ;
    USE SIGNAL ;
    PORT
      LAYER M5 ;
        RECT  97.488 17.196 97.512 17.28 ;
    END
  END d[896]
  PIN d[897]
    DIRECTION INPUT ;
    USE SIGNAL ;
    PORT
      LAYER M5 ;
        RECT  97.584 17.196 97.608 17.28 ;
    END
  END d[897]
  PIN d[898]
    DIRECTION INPUT ;
    USE SIGNAL ;
    PORT
      LAYER M5 ;
        RECT  97.68 17.196 97.704 17.28 ;
    END
  END d[898]
  PIN d[899]
    DIRECTION INPUT ;
    USE SIGNAL ;
    PORT
      LAYER M5 ;
        RECT  97.776 17.196 97.8 17.28 ;
    END
  END d[899]
  PIN d[89]
    DIRECTION INPUT ;
    USE SIGNAL ;
    PORT
      LAYER M5 ;
        RECT  48.432 17.196 48.456 17.28 ;
    END
  END d[89]
  PIN d[8]
    DIRECTION INPUT ;
    USE SIGNAL ;
    PORT
      LAYER M5 ;
        RECT  62.928 17.196 62.952 17.28 ;
    END
  END d[8]
  PIN d[900]
    DIRECTION INPUT ;
    USE SIGNAL ;
    PORT
      LAYER M5 ;
        RECT  97.872 17.196 97.896 17.28 ;
    END
  END d[900]
  PIN d[901]
    DIRECTION INPUT ;
    USE SIGNAL ;
    PORT
      LAYER M5 ;
        RECT  97.968 17.196 97.992 17.28 ;
    END
  END d[901]
  PIN d[902]
    DIRECTION INPUT ;
    USE SIGNAL ;
    PORT
      LAYER M5 ;
        RECT  98.064 17.196 98.088 17.28 ;
    END
  END d[902]
  PIN d[903]
    DIRECTION INPUT ;
    USE SIGNAL ;
    PORT
      LAYER M5 ;
        RECT  98.16 17.196 98.184 17.28 ;
    END
  END d[903]
  PIN d[904]
    DIRECTION INPUT ;
    USE SIGNAL ;
    PORT
      LAYER M5 ;
        RECT  98.256 17.196 98.28 17.28 ;
    END
  END d[904]
  PIN d[905]
    DIRECTION INPUT ;
    USE SIGNAL ;
    PORT
      LAYER M5 ;
        RECT  98.352 17.196 98.376 17.28 ;
    END
  END d[905]
  PIN d[906]
    DIRECTION INPUT ;
    USE SIGNAL ;
    PORT
      LAYER M5 ;
        RECT  98.448 17.196 98.472 17.28 ;
    END
  END d[906]
  PIN d[907]
    DIRECTION INPUT ;
    USE SIGNAL ;
    PORT
      LAYER M5 ;
        RECT  98.544 17.196 98.568 17.28 ;
    END
  END d[907]
  PIN d[908]
    DIRECTION INPUT ;
    USE SIGNAL ;
    PORT
      LAYER M5 ;
        RECT  98.64 17.196 98.664 17.28 ;
    END
  END d[908]
  PIN d[909]
    DIRECTION INPUT ;
    USE SIGNAL ;
    PORT
      LAYER M5 ;
        RECT  98.736 17.196 98.76 17.28 ;
    END
  END d[909]
  PIN d[90]
    DIRECTION INPUT ;
    USE SIGNAL ;
    PORT
      LAYER M5 ;
        RECT  48.528 17.196 48.552 17.28 ;
    END
  END d[90]
  PIN d[910]
    DIRECTION INPUT ;
    USE SIGNAL ;
    PORT
      LAYER M5 ;
        RECT  98.832 17.196 98.856 17.28 ;
    END
  END d[910]
  PIN d[911]
    DIRECTION INPUT ;
    USE SIGNAL ;
    PORT
      LAYER M5 ;
        RECT  98.928 17.196 98.952 17.28 ;
    END
  END d[911]
  PIN d[912]
    DIRECTION INPUT ;
    USE SIGNAL ;
    PORT
      LAYER M5 ;
        RECT  99.024 17.196 99.048 17.28 ;
    END
  END d[912]
  PIN d[913]
    DIRECTION INPUT ;
    USE SIGNAL ;
    PORT
      LAYER M5 ;
        RECT  99.12 17.196 99.144 17.28 ;
    END
  END d[913]
  PIN d[914]
    DIRECTION INPUT ;
    USE SIGNAL ;
    PORT
      LAYER M5 ;
        RECT  99.216 17.196 99.24 17.28 ;
    END
  END d[914]
  PIN d[915]
    DIRECTION INPUT ;
    USE SIGNAL ;
    PORT
      LAYER M5 ;
        RECT  99.312 17.196 99.336 17.28 ;
    END
  END d[915]
  PIN d[916]
    DIRECTION INPUT ;
    USE SIGNAL ;
    PORT
      LAYER M5 ;
        RECT  99.408 17.196 99.432 17.28 ;
    END
  END d[916]
  PIN d[917]
    DIRECTION INPUT ;
    USE SIGNAL ;
    PORT
      LAYER M5 ;
        RECT  99.504 17.196 99.528 17.28 ;
    END
  END d[917]
  PIN d[918]
    DIRECTION INPUT ;
    USE SIGNAL ;
    PORT
      LAYER M5 ;
        RECT  99.6 17.196 99.624 17.28 ;
    END
  END d[918]
  PIN d[919]
    DIRECTION INPUT ;
    USE SIGNAL ;
    PORT
      LAYER M5 ;
        RECT  99.696 17.196 99.72 17.28 ;
    END
  END d[919]
  PIN d[91]
    DIRECTION INPUT ;
    USE SIGNAL ;
    PORT
      LAYER M5 ;
        RECT  48.624 17.196 48.648 17.28 ;
    END
  END d[91]
  PIN d[920]
    DIRECTION INPUT ;
    USE SIGNAL ;
    PORT
      LAYER M5 ;
        RECT  99.792 17.196 99.816 17.28 ;
    END
  END d[920]
  PIN d[921]
    DIRECTION INPUT ;
    USE SIGNAL ;
    PORT
      LAYER M5 ;
        RECT  99.888 17.196 99.912 17.28 ;
    END
  END d[921]
  PIN d[922]
    DIRECTION INPUT ;
    USE SIGNAL ;
    PORT
      LAYER M5 ;
        RECT  99.984 17.196 100.008 17.28 ;
    END
  END d[922]
  PIN d[923]
    DIRECTION INPUT ;
    USE SIGNAL ;
    PORT
      LAYER M5 ;
        RECT  100.08 17.196 100.104 17.28 ;
    END
  END d[923]
  PIN d[924]
    DIRECTION INPUT ;
    USE SIGNAL ;
    PORT
      LAYER M5 ;
        RECT  100.176 17.196 100.2 17.28 ;
    END
  END d[924]
  PIN d[925]
    DIRECTION INPUT ;
    USE SIGNAL ;
    PORT
      LAYER M5 ;
        RECT  100.272 17.196 100.296 17.28 ;
    END
  END d[925]
  PIN d[926]
    DIRECTION INPUT ;
    USE SIGNAL ;
    PORT
      LAYER M5 ;
        RECT  100.368 17.196 100.392 17.28 ;
    END
  END d[926]
  PIN d[927]
    DIRECTION INPUT ;
    USE SIGNAL ;
    PORT
      LAYER M5 ;
        RECT  100.464 17.196 100.488 17.28 ;
    END
  END d[927]
  PIN d[928]
    DIRECTION INPUT ;
    USE SIGNAL ;
    PORT
      LAYER M5 ;
        RECT  7.632 17.196 7.656 17.28 ;
    END
  END d[928]
  PIN d[929]
    DIRECTION INPUT ;
    USE SIGNAL ;
    PORT
      LAYER M5 ;
        RECT  7.728 17.196 7.752 17.28 ;
    END
  END d[929]
  PIN d[92]
    DIRECTION INPUT ;
    USE SIGNAL ;
    PORT
      LAYER M5 ;
        RECT  48.72 17.196 48.744 17.28 ;
    END
  END d[92]
  PIN d[930]
    DIRECTION INPUT ;
    USE SIGNAL ;
    PORT
      LAYER M5 ;
        RECT  7.824 17.196 7.848 17.28 ;
    END
  END d[930]
  PIN d[931]
    DIRECTION INPUT ;
    USE SIGNAL ;
    PORT
      LAYER M5 ;
        RECT  7.92 17.196 7.944 17.28 ;
    END
  END d[931]
  PIN d[932]
    DIRECTION INPUT ;
    USE SIGNAL ;
    PORT
      LAYER M5 ;
        RECT  8.016 17.196 8.04 17.28 ;
    END
  END d[932]
  PIN d[933]
    DIRECTION INPUT ;
    USE SIGNAL ;
    PORT
      LAYER M5 ;
        RECT  8.112 17.196 8.136 17.28 ;
    END
  END d[933]
  PIN d[934]
    DIRECTION INPUT ;
    USE SIGNAL ;
    PORT
      LAYER M5 ;
        RECT  8.208 17.196 8.232 17.28 ;
    END
  END d[934]
  PIN d[935]
    DIRECTION INPUT ;
    USE SIGNAL ;
    PORT
      LAYER M5 ;
        RECT  8.304 17.196 8.328 17.28 ;
    END
  END d[935]
  PIN d[936]
    DIRECTION INPUT ;
    USE SIGNAL ;
    PORT
      LAYER M5 ;
        RECT  8.4 17.196 8.424 17.28 ;
    END
  END d[936]
  PIN d[937]
    DIRECTION INPUT ;
    USE SIGNAL ;
    PORT
      LAYER M5 ;
        RECT  8.496 17.196 8.52 17.28 ;
    END
  END d[937]
  PIN d[938]
    DIRECTION INPUT ;
    USE SIGNAL ;
    PORT
      LAYER M5 ;
        RECT  8.592 17.196 8.616 17.28 ;
    END
  END d[938]
  PIN d[939]
    DIRECTION INPUT ;
    USE SIGNAL ;
    PORT
      LAYER M5 ;
        RECT  8.688 17.196 8.712 17.28 ;
    END
  END d[939]
  PIN d[93]
    DIRECTION INPUT ;
    USE SIGNAL ;
    PORT
      LAYER M5 ;
        RECT  48.816 17.196 48.84 17.28 ;
    END
  END d[93]
  PIN d[940]
    DIRECTION INPUT ;
    USE SIGNAL ;
    PORT
      LAYER M5 ;
        RECT  8.784 17.196 8.808 17.28 ;
    END
  END d[940]
  PIN d[941]
    DIRECTION INPUT ;
    USE SIGNAL ;
    PORT
      LAYER M5 ;
        RECT  8.88 17.196 8.904 17.28 ;
    END
  END d[941]
  PIN d[942]
    DIRECTION INPUT ;
    USE SIGNAL ;
    PORT
      LAYER M5 ;
        RECT  8.976 17.196 9 17.28 ;
    END
  END d[942]
  PIN d[943]
    DIRECTION INPUT ;
    USE SIGNAL ;
    PORT
      LAYER M5 ;
        RECT  9.072 17.196 9.096 17.28 ;
    END
  END d[943]
  PIN d[944]
    DIRECTION INPUT ;
    USE SIGNAL ;
    PORT
      LAYER M5 ;
        RECT  9.168 17.196 9.192 17.28 ;
    END
  END d[944]
  PIN d[945]
    DIRECTION INPUT ;
    USE SIGNAL ;
    PORT
      LAYER M5 ;
        RECT  9.264 17.196 9.288 17.28 ;
    END
  END d[945]
  PIN d[946]
    DIRECTION INPUT ;
    USE SIGNAL ;
    PORT
      LAYER M5 ;
        RECT  9.36 17.196 9.384 17.28 ;
    END
  END d[946]
  PIN d[947]
    DIRECTION INPUT ;
    USE SIGNAL ;
    PORT
      LAYER M5 ;
        RECT  9.456 17.196 9.48 17.28 ;
    END
  END d[947]
  PIN d[948]
    DIRECTION INPUT ;
    USE SIGNAL ;
    PORT
      LAYER M5 ;
        RECT  9.552 17.196 9.576 17.28 ;
    END
  END d[948]
  PIN d[949]
    DIRECTION INPUT ;
    USE SIGNAL ;
    PORT
      LAYER M5 ;
        RECT  9.648 17.196 9.672 17.28 ;
    END
  END d[949]
  PIN d[94]
    DIRECTION INPUT ;
    USE SIGNAL ;
    PORT
      LAYER M5 ;
        RECT  48.912 17.196 48.936 17.28 ;
    END
  END d[94]
  PIN d[950]
    DIRECTION INPUT ;
    USE SIGNAL ;
    PORT
      LAYER M5 ;
        RECT  9.744 17.196 9.768 17.28 ;
    END
  END d[950]
  PIN d[951]
    DIRECTION INPUT ;
    USE SIGNAL ;
    PORT
      LAYER M5 ;
        RECT  9.84 17.196 9.864 17.28 ;
    END
  END d[951]
  PIN d[952]
    DIRECTION INPUT ;
    USE SIGNAL ;
    PORT
      LAYER M5 ;
        RECT  9.936 17.196 9.96 17.28 ;
    END
  END d[952]
  PIN d[953]
    DIRECTION INPUT ;
    USE SIGNAL ;
    PORT
      LAYER M5 ;
        RECT  10.032 17.196 10.056 17.28 ;
    END
  END d[953]
  PIN d[954]
    DIRECTION INPUT ;
    USE SIGNAL ;
    PORT
      LAYER M5 ;
        RECT  10.128 17.196 10.152 17.28 ;
    END
  END d[954]
  PIN d[955]
    DIRECTION INPUT ;
    USE SIGNAL ;
    PORT
      LAYER M5 ;
        RECT  10.224 17.196 10.248 17.28 ;
    END
  END d[955]
  PIN d[956]
    DIRECTION INPUT ;
    USE SIGNAL ;
    PORT
      LAYER M5 ;
        RECT  10.32 17.196 10.344 17.28 ;
    END
  END d[956]
  PIN d[957]
    DIRECTION INPUT ;
    USE SIGNAL ;
    PORT
      LAYER M5 ;
        RECT  10.416 17.196 10.44 17.28 ;
    END
  END d[957]
  PIN d[958]
    DIRECTION INPUT ;
    USE SIGNAL ;
    PORT
      LAYER M5 ;
        RECT  10.512 17.196 10.536 17.28 ;
    END
  END d[958]
  PIN d[959]
    DIRECTION INPUT ;
    USE SIGNAL ;
    PORT
      LAYER M5 ;
        RECT  10.608 17.196 10.632 17.28 ;
    END
  END d[959]
  PIN d[95]
    DIRECTION INPUT ;
    USE SIGNAL ;
    PORT
      LAYER M5 ;
        RECT  49.008 17.196 49.032 17.28 ;
    END
  END d[95]
  PIN d[960]
    DIRECTION INPUT ;
    USE SIGNAL ;
    PORT
      LAYER M5 ;
        RECT  13.776 17.196 13.8 17.28 ;
    END
  END d[960]
  PIN d[961]
    DIRECTION INPUT ;
    USE SIGNAL ;
    PORT
      LAYER M5 ;
        RECT  13.872 17.196 13.896 17.28 ;
    END
  END d[961]
  PIN d[962]
    DIRECTION INPUT ;
    USE SIGNAL ;
    PORT
      LAYER M5 ;
        RECT  13.968 17.196 13.992 17.28 ;
    END
  END d[962]
  PIN d[963]
    DIRECTION INPUT ;
    USE SIGNAL ;
    PORT
      LAYER M5 ;
        RECT  14.064 17.196 14.088 17.28 ;
    END
  END d[963]
  PIN d[964]
    DIRECTION INPUT ;
    USE SIGNAL ;
    PORT
      LAYER M5 ;
        RECT  14.16 17.196 14.184 17.28 ;
    END
  END d[964]
  PIN d[965]
    DIRECTION INPUT ;
    USE SIGNAL ;
    PORT
      LAYER M5 ;
        RECT  14.256 17.196 14.28 17.28 ;
    END
  END d[965]
  PIN d[966]
    DIRECTION INPUT ;
    USE SIGNAL ;
    PORT
      LAYER M5 ;
        RECT  14.352 17.196 14.376 17.28 ;
    END
  END d[966]
  PIN d[967]
    DIRECTION INPUT ;
    USE SIGNAL ;
    PORT
      LAYER M5 ;
        RECT  14.448 17.196 14.472 17.28 ;
    END
  END d[967]
  PIN d[968]
    DIRECTION INPUT ;
    USE SIGNAL ;
    PORT
      LAYER M5 ;
        RECT  14.544 17.196 14.568 17.28 ;
    END
  END d[968]
  PIN d[969]
    DIRECTION INPUT ;
    USE SIGNAL ;
    PORT
      LAYER M5 ;
        RECT  14.64 17.196 14.664 17.28 ;
    END
  END d[969]
  PIN d[96]
    DIRECTION INPUT ;
    USE SIGNAL ;
    PORT
      LAYER M5 ;
        RECT  68.304 17.196 68.328 17.28 ;
    END
  END d[96]
  PIN d[970]
    DIRECTION INPUT ;
    USE SIGNAL ;
    PORT
      LAYER M5 ;
        RECT  14.736 17.196 14.76 17.28 ;
    END
  END d[970]
  PIN d[971]
    DIRECTION INPUT ;
    USE SIGNAL ;
    PORT
      LAYER M5 ;
        RECT  14.832 17.196 14.856 17.28 ;
    END
  END d[971]
  PIN d[972]
    DIRECTION INPUT ;
    USE SIGNAL ;
    PORT
      LAYER M5 ;
        RECT  14.928 17.196 14.952 17.28 ;
    END
  END d[972]
  PIN d[973]
    DIRECTION INPUT ;
    USE SIGNAL ;
    PORT
      LAYER M5 ;
        RECT  15.024 17.196 15.048 17.28 ;
    END
  END d[973]
  PIN d[974]
    DIRECTION INPUT ;
    USE SIGNAL ;
    PORT
      LAYER M5 ;
        RECT  15.12 17.196 15.144 17.28 ;
    END
  END d[974]
  PIN d[975]
    DIRECTION INPUT ;
    USE SIGNAL ;
    PORT
      LAYER M5 ;
        RECT  15.216 17.196 15.24 17.28 ;
    END
  END d[975]
  PIN d[976]
    DIRECTION INPUT ;
    USE SIGNAL ;
    PORT
      LAYER M5 ;
        RECT  15.312 17.196 15.336 17.28 ;
    END
  END d[976]
  PIN d[977]
    DIRECTION INPUT ;
    USE SIGNAL ;
    PORT
      LAYER M5 ;
        RECT  15.408 17.196 15.432 17.28 ;
    END
  END d[977]
  PIN d[978]
    DIRECTION INPUT ;
    USE SIGNAL ;
    PORT
      LAYER M5 ;
        RECT  15.504 17.196 15.528 17.28 ;
    END
  END d[978]
  PIN d[979]
    DIRECTION INPUT ;
    USE SIGNAL ;
    PORT
      LAYER M5 ;
        RECT  15.6 17.196 15.624 17.28 ;
    END
  END d[979]
  PIN d[97]
    DIRECTION INPUT ;
    USE SIGNAL ;
    PORT
      LAYER M5 ;
        RECT  68.4 17.196 68.424 17.28 ;
    END
  END d[97]
  PIN d[980]
    DIRECTION INPUT ;
    USE SIGNAL ;
    PORT
      LAYER M5 ;
        RECT  15.696 17.196 15.72 17.28 ;
    END
  END d[980]
  PIN d[981]
    DIRECTION INPUT ;
    USE SIGNAL ;
    PORT
      LAYER M5 ;
        RECT  15.792 17.196 15.816 17.28 ;
    END
  END d[981]
  PIN d[982]
    DIRECTION INPUT ;
    USE SIGNAL ;
    PORT
      LAYER M5 ;
        RECT  15.888 17.196 15.912 17.28 ;
    END
  END d[982]
  PIN d[983]
    DIRECTION INPUT ;
    USE SIGNAL ;
    PORT
      LAYER M5 ;
        RECT  15.984 17.196 16.008 17.28 ;
    END
  END d[983]
  PIN d[984]
    DIRECTION INPUT ;
    USE SIGNAL ;
    PORT
      LAYER M5 ;
        RECT  16.08 17.196 16.104 17.28 ;
    END
  END d[984]
  PIN d[985]
    DIRECTION INPUT ;
    USE SIGNAL ;
    PORT
      LAYER M5 ;
        RECT  16.176 17.196 16.2 17.28 ;
    END
  END d[985]
  PIN d[986]
    DIRECTION INPUT ;
    USE SIGNAL ;
    PORT
      LAYER M5 ;
        RECT  16.272 17.196 16.296 17.28 ;
    END
  END d[986]
  PIN d[987]
    DIRECTION INPUT ;
    USE SIGNAL ;
    PORT
      LAYER M5 ;
        RECT  16.368 17.196 16.392 17.28 ;
    END
  END d[987]
  PIN d[988]
    DIRECTION INPUT ;
    USE SIGNAL ;
    PORT
      LAYER M5 ;
        RECT  16.464 17.196 16.488 17.28 ;
    END
  END d[988]
  PIN d[989]
    DIRECTION INPUT ;
    USE SIGNAL ;
    PORT
      LAYER M5 ;
        RECT  16.56 17.196 16.584 17.28 ;
    END
  END d[989]
  PIN d[98]
    DIRECTION INPUT ;
    USE SIGNAL ;
    PORT
      LAYER M5 ;
        RECT  68.496 17.196 68.52 17.28 ;
    END
  END d[98]
  PIN d[990]
    DIRECTION INPUT ;
    USE SIGNAL ;
    PORT
      LAYER M5 ;
        RECT  16.656 17.196 16.68 17.28 ;
    END
  END d[990]
  PIN d[991]
    DIRECTION INPUT ;
    USE SIGNAL ;
    PORT
      LAYER M5 ;
        RECT  16.752 17.196 16.776 17.28 ;
    END
  END d[991]
  PIN d[992]
    DIRECTION INPUT ;
    USE SIGNAL ;
    PORT
      LAYER M5 ;
        RECT  10.704 17.196 10.728 17.28 ;
    END
  END d[992]
  PIN d[993]
    DIRECTION INPUT ;
    USE SIGNAL ;
    PORT
      LAYER M5 ;
        RECT  10.8 17.196 10.824 17.28 ;
    END
  END d[993]
  PIN d[994]
    DIRECTION INPUT ;
    USE SIGNAL ;
    PORT
      LAYER M5 ;
        RECT  10.896 17.196 10.92 17.28 ;
    END
  END d[994]
  PIN d[995]
    DIRECTION INPUT ;
    USE SIGNAL ;
    PORT
      LAYER M5 ;
        RECT  10.992 17.196 11.016 17.28 ;
    END
  END d[995]
  PIN d[996]
    DIRECTION INPUT ;
    USE SIGNAL ;
    PORT
      LAYER M5 ;
        RECT  11.088 17.196 11.112 17.28 ;
    END
  END d[996]
  PIN d[997]
    DIRECTION INPUT ;
    USE SIGNAL ;
    PORT
      LAYER M5 ;
        RECT  11.184 17.196 11.208 17.28 ;
    END
  END d[997]
  PIN d[998]
    DIRECTION INPUT ;
    USE SIGNAL ;
    PORT
      LAYER M5 ;
        RECT  11.28 17.196 11.304 17.28 ;
    END
  END d[998]
  PIN d[999]
    DIRECTION INPUT ;
    USE SIGNAL ;
    PORT
      LAYER M5 ;
        RECT  11.376 17.196 11.4 17.28 ;
    END
  END d[999]
  PIN d[99]
    DIRECTION INPUT ;
    USE SIGNAL ;
    PORT
      LAYER M5 ;
        RECT  68.592 17.196 68.616 17.28 ;
    END
  END d[99]
  PIN d[9]
    DIRECTION INPUT ;
    USE SIGNAL ;
    PORT
      LAYER M5 ;
        RECT  63.024 17.196 63.048 17.28 ;
    END
  END d[9]
  PIN q[0]
    DIRECTION OUTPUT ;
    USE SIGNAL ;
    PORT
      LAYER M5 ;
        RECT  67.536 0 67.56 0.084 ;
    END
  END q[0]
  PIN q[1000]
    DIRECTION OUTPUT ;
    USE SIGNAL ;
    PORT
      LAYER M5 ;
        RECT  10.704 0 10.728 0.084 ;
    END
  END q[1000]
  PIN q[1001]
    DIRECTION OUTPUT ;
    USE SIGNAL ;
    PORT
      LAYER M5 ;
        RECT  10.8 0 10.824 0.084 ;
    END
  END q[1001]
  PIN q[1002]
    DIRECTION OUTPUT ;
    USE SIGNAL ;
    PORT
      LAYER M5 ;
        RECT  10.896 0 10.92 0.084 ;
    END
  END q[1002]
  PIN q[1003]
    DIRECTION OUTPUT ;
    USE SIGNAL ;
    PORT
      LAYER M5 ;
        RECT  10.992 0 11.016 0.084 ;
    END
  END q[1003]
  PIN q[1004]
    DIRECTION OUTPUT ;
    USE SIGNAL ;
    PORT
      LAYER M5 ;
        RECT  11.088 0 11.112 0.084 ;
    END
  END q[1004]
  PIN q[1005]
    DIRECTION OUTPUT ;
    USE SIGNAL ;
    PORT
      LAYER M5 ;
        RECT  11.184 0 11.208 0.084 ;
    END
  END q[1005]
  PIN q[1006]
    DIRECTION OUTPUT ;
    USE SIGNAL ;
    PORT
      LAYER M5 ;
        RECT  11.28 0 11.304 0.084 ;
    END
  END q[1006]
  PIN q[1007]
    DIRECTION OUTPUT ;
    USE SIGNAL ;
    PORT
      LAYER M5 ;
        RECT  11.376 0 11.4 0.084 ;
    END
  END q[1007]
  PIN q[1008]
    DIRECTION OUTPUT ;
    USE SIGNAL ;
    PORT
      LAYER M5 ;
        RECT  11.472 0 11.496 0.084 ;
    END
  END q[1008]
  PIN q[1009]
    DIRECTION OUTPUT ;
    USE SIGNAL ;
    PORT
      LAYER M5 ;
        RECT  11.568 0 11.592 0.084 ;
    END
  END q[1009]
  PIN q[100]
    DIRECTION OUTPUT ;
    USE SIGNAL ;
    PORT
      LAYER M5 ;
        RECT  74.064 0 74.088 0.084 ;
    END
  END q[100]
  PIN q[1010]
    DIRECTION OUTPUT ;
    USE SIGNAL ;
    PORT
      LAYER M5 ;
        RECT  11.664 0 11.688 0.084 ;
    END
  END q[1010]
  PIN q[1011]
    DIRECTION OUTPUT ;
    USE SIGNAL ;
    PORT
      LAYER M5 ;
        RECT  11.76 0 11.784 0.084 ;
    END
  END q[1011]
  PIN q[1012]
    DIRECTION OUTPUT ;
    USE SIGNAL ;
    PORT
      LAYER M5 ;
        RECT  11.856 0 11.88 0.084 ;
    END
  END q[1012]
  PIN q[1013]
    DIRECTION OUTPUT ;
    USE SIGNAL ;
    PORT
      LAYER M5 ;
        RECT  11.952 0 11.976 0.084 ;
    END
  END q[1013]
  PIN q[1014]
    DIRECTION OUTPUT ;
    USE SIGNAL ;
    PORT
      LAYER M5 ;
        RECT  12.048 0 12.072 0.084 ;
    END
  END q[1014]
  PIN q[1015]
    DIRECTION OUTPUT ;
    USE SIGNAL ;
    PORT
      LAYER M5 ;
        RECT  12.144 0 12.168 0.084 ;
    END
  END q[1015]
  PIN q[1016]
    DIRECTION OUTPUT ;
    USE SIGNAL ;
    PORT
      LAYER M5 ;
        RECT  12.24 0 12.264 0.084 ;
    END
  END q[1016]
  PIN q[1017]
    DIRECTION OUTPUT ;
    USE SIGNAL ;
    PORT
      LAYER M5 ;
        RECT  12.336 0 12.36 0.084 ;
    END
  END q[1017]
  PIN q[1018]
    DIRECTION OUTPUT ;
    USE SIGNAL ;
    PORT
      LAYER M5 ;
        RECT  12.432 0 12.456 0.084 ;
    END
  END q[1018]
  PIN q[1019]
    DIRECTION OUTPUT ;
    USE SIGNAL ;
    PORT
      LAYER M5 ;
        RECT  12.528 0 12.552 0.084 ;
    END
  END q[1019]
  PIN q[101]
    DIRECTION OUTPUT ;
    USE SIGNAL ;
    PORT
      LAYER M5 ;
        RECT  74.16 0 74.184 0.084 ;
    END
  END q[101]
  PIN q[1020]
    DIRECTION OUTPUT ;
    USE SIGNAL ;
    PORT
      LAYER M5 ;
        RECT  12.624 0 12.648 0.084 ;
    END
  END q[1020]
  PIN q[1021]
    DIRECTION OUTPUT ;
    USE SIGNAL ;
    PORT
      LAYER M5 ;
        RECT  12.72 0 12.744 0.084 ;
    END
  END q[1021]
  PIN q[1022]
    DIRECTION OUTPUT ;
    USE SIGNAL ;
    PORT
      LAYER M5 ;
        RECT  12.816 0 12.84 0.084 ;
    END
  END q[1022]
  PIN q[1023]
    DIRECTION OUTPUT ;
    USE SIGNAL ;
    PORT
      LAYER M5 ;
        RECT  12.912 0 12.936 0.084 ;
    END
  END q[1023]
  PIN q[102]
    DIRECTION OUTPUT ;
    USE SIGNAL ;
    PORT
      LAYER M5 ;
        RECT  74.256 0 74.28 0.084 ;
    END
  END q[102]
  PIN q[103]
    DIRECTION OUTPUT ;
    USE SIGNAL ;
    PORT
      LAYER M5 ;
        RECT  74.352 0 74.376 0.084 ;
    END
  END q[103]
  PIN q[104]
    DIRECTION OUTPUT ;
    USE SIGNAL ;
    PORT
      LAYER M5 ;
        RECT  74.448 0 74.472 0.084 ;
    END
  END q[104]
  PIN q[105]
    DIRECTION OUTPUT ;
    USE SIGNAL ;
    PORT
      LAYER M5 ;
        RECT  74.544 0 74.568 0.084 ;
    END
  END q[105]
  PIN q[106]
    DIRECTION OUTPUT ;
    USE SIGNAL ;
    PORT
      LAYER M5 ;
        RECT  74.64 0 74.664 0.084 ;
    END
  END q[106]
  PIN q[107]
    DIRECTION OUTPUT ;
    USE SIGNAL ;
    PORT
      LAYER M5 ;
        RECT  74.736 0 74.76 0.084 ;
    END
  END q[107]
  PIN q[108]
    DIRECTION OUTPUT ;
    USE SIGNAL ;
    PORT
      LAYER M5 ;
        RECT  74.832 0 74.856 0.084 ;
    END
  END q[108]
  PIN q[109]
    DIRECTION OUTPUT ;
    USE SIGNAL ;
    PORT
      LAYER M5 ;
        RECT  74.928 0 74.952 0.084 ;
    END
  END q[109]
  PIN q[10]
    DIRECTION OUTPUT ;
    USE SIGNAL ;
    PORT
      LAYER M5 ;
        RECT  68.496 0 68.52 0.084 ;
    END
  END q[10]
  PIN q[110]
    DIRECTION OUTPUT ;
    USE SIGNAL ;
    PORT
      LAYER M5 ;
        RECT  75.024 0 75.048 0.084 ;
    END
  END q[110]
  PIN q[111]
    DIRECTION OUTPUT ;
    USE SIGNAL ;
    PORT
      LAYER M5 ;
        RECT  75.12 0 75.144 0.084 ;
    END
  END q[111]
  PIN q[112]
    DIRECTION OUTPUT ;
    USE SIGNAL ;
    PORT
      LAYER M5 ;
        RECT  75.216 0 75.24 0.084 ;
    END
  END q[112]
  PIN q[113]
    DIRECTION OUTPUT ;
    USE SIGNAL ;
    PORT
      LAYER M5 ;
        RECT  75.312 0 75.336 0.084 ;
    END
  END q[113]
  PIN q[114]
    DIRECTION OUTPUT ;
    USE SIGNAL ;
    PORT
      LAYER M5 ;
        RECT  75.408 0 75.432 0.084 ;
    END
  END q[114]
  PIN q[115]
    DIRECTION OUTPUT ;
    USE SIGNAL ;
    PORT
      LAYER M5 ;
        RECT  75.504 0 75.528 0.084 ;
    END
  END q[115]
  PIN q[116]
    DIRECTION OUTPUT ;
    USE SIGNAL ;
    PORT
      LAYER M5 ;
        RECT  75.6 0 75.624 0.084 ;
    END
  END q[116]
  PIN q[117]
    DIRECTION OUTPUT ;
    USE SIGNAL ;
    PORT
      LAYER M5 ;
        RECT  75.696 0 75.72 0.084 ;
    END
  END q[117]
  PIN q[118]
    DIRECTION OUTPUT ;
    USE SIGNAL ;
    PORT
      LAYER M5 ;
        RECT  75.792 0 75.816 0.084 ;
    END
  END q[118]
  PIN q[119]
    DIRECTION OUTPUT ;
    USE SIGNAL ;
    PORT
      LAYER M5 ;
        RECT  75.888 0 75.912 0.084 ;
    END
  END q[119]
  PIN q[11]
    DIRECTION OUTPUT ;
    USE SIGNAL ;
    PORT
      LAYER M5 ;
        RECT  68.592 0 68.616 0.084 ;
    END
  END q[11]
  PIN q[120]
    DIRECTION OUTPUT ;
    USE SIGNAL ;
    PORT
      LAYER M5 ;
        RECT  75.984 0 76.008 0.084 ;
    END
  END q[120]
  PIN q[121]
    DIRECTION OUTPUT ;
    USE SIGNAL ;
    PORT
      LAYER M5 ;
        RECT  76.08 0 76.104 0.084 ;
    END
  END q[121]
  PIN q[122]
    DIRECTION OUTPUT ;
    USE SIGNAL ;
    PORT
      LAYER M5 ;
        RECT  76.176 0 76.2 0.084 ;
    END
  END q[122]
  PIN q[123]
    DIRECTION OUTPUT ;
    USE SIGNAL ;
    PORT
      LAYER M5 ;
        RECT  76.272 0 76.296 0.084 ;
    END
  END q[123]
  PIN q[124]
    DIRECTION OUTPUT ;
    USE SIGNAL ;
    PORT
      LAYER M5 ;
        RECT  76.368 0 76.392 0.084 ;
    END
  END q[124]
  PIN q[125]
    DIRECTION OUTPUT ;
    USE SIGNAL ;
    PORT
      LAYER M5 ;
        RECT  76.464 0 76.488 0.084 ;
    END
  END q[125]
  PIN q[126]
    DIRECTION OUTPUT ;
    USE SIGNAL ;
    PORT
      LAYER M5 ;
        RECT  76.56 0 76.584 0.084 ;
    END
  END q[126]
  PIN q[127]
    DIRECTION OUTPUT ;
    USE SIGNAL ;
    PORT
      LAYER M5 ;
        RECT  76.656 0 76.68 0.084 ;
    END
  END q[127]
  PIN q[128]
    DIRECTION OUTPUT ;
    USE SIGNAL ;
    PORT
      LAYER M5 ;
        RECT  64.464 0 64.488 0.084 ;
    END
  END q[128]
  PIN q[129]
    DIRECTION OUTPUT ;
    USE SIGNAL ;
    PORT
      LAYER M5 ;
        RECT  64.56 0 64.584 0.084 ;
    END
  END q[129]
  PIN q[12]
    DIRECTION OUTPUT ;
    USE SIGNAL ;
    PORT
      LAYER M5 ;
        RECT  68.688 0 68.712 0.084 ;
    END
  END q[12]
  PIN q[130]
    DIRECTION OUTPUT ;
    USE SIGNAL ;
    PORT
      LAYER M5 ;
        RECT  64.656 0 64.68 0.084 ;
    END
  END q[130]
  PIN q[131]
    DIRECTION OUTPUT ;
    USE SIGNAL ;
    PORT
      LAYER M5 ;
        RECT  64.752 0 64.776 0.084 ;
    END
  END q[131]
  PIN q[132]
    DIRECTION OUTPUT ;
    USE SIGNAL ;
    PORT
      LAYER M5 ;
        RECT  64.848 0 64.872 0.084 ;
    END
  END q[132]
  PIN q[133]
    DIRECTION OUTPUT ;
    USE SIGNAL ;
    PORT
      LAYER M5 ;
        RECT  64.944 0 64.968 0.084 ;
    END
  END q[133]
  PIN q[134]
    DIRECTION OUTPUT ;
    USE SIGNAL ;
    PORT
      LAYER M5 ;
        RECT  65.04 0 65.064 0.084 ;
    END
  END q[134]
  PIN q[135]
    DIRECTION OUTPUT ;
    USE SIGNAL ;
    PORT
      LAYER M5 ;
        RECT  65.136 0 65.16 0.084 ;
    END
  END q[135]
  PIN q[136]
    DIRECTION OUTPUT ;
    USE SIGNAL ;
    PORT
      LAYER M5 ;
        RECT  65.232 0 65.256 0.084 ;
    END
  END q[136]
  PIN q[137]
    DIRECTION OUTPUT ;
    USE SIGNAL ;
    PORT
      LAYER M5 ;
        RECT  65.328 0 65.352 0.084 ;
    END
  END q[137]
  PIN q[138]
    DIRECTION OUTPUT ;
    USE SIGNAL ;
    PORT
      LAYER M5 ;
        RECT  65.424 0 65.448 0.084 ;
    END
  END q[138]
  PIN q[139]
    DIRECTION OUTPUT ;
    USE SIGNAL ;
    PORT
      LAYER M5 ;
        RECT  65.52 0 65.544 0.084 ;
    END
  END q[139]
  PIN q[13]
    DIRECTION OUTPUT ;
    USE SIGNAL ;
    PORT
      LAYER M5 ;
        RECT  68.784 0 68.808 0.084 ;
    END
  END q[13]
  PIN q[140]
    DIRECTION OUTPUT ;
    USE SIGNAL ;
    PORT
      LAYER M5 ;
        RECT  65.616 0 65.64 0.084 ;
    END
  END q[140]
  PIN q[141]
    DIRECTION OUTPUT ;
    USE SIGNAL ;
    PORT
      LAYER M5 ;
        RECT  65.712 0 65.736 0.084 ;
    END
  END q[141]
  PIN q[142]
    DIRECTION OUTPUT ;
    USE SIGNAL ;
    PORT
      LAYER M5 ;
        RECT  65.808 0 65.832 0.084 ;
    END
  END q[142]
  PIN q[143]
    DIRECTION OUTPUT ;
    USE SIGNAL ;
    PORT
      LAYER M5 ;
        RECT  65.904 0 65.928 0.084 ;
    END
  END q[143]
  PIN q[144]
    DIRECTION OUTPUT ;
    USE SIGNAL ;
    PORT
      LAYER M5 ;
        RECT  66 0 66.024 0.084 ;
    END
  END q[144]
  PIN q[145]
    DIRECTION OUTPUT ;
    USE SIGNAL ;
    PORT
      LAYER M5 ;
        RECT  66.096 0 66.12 0.084 ;
    END
  END q[145]
  PIN q[146]
    DIRECTION OUTPUT ;
    USE SIGNAL ;
    PORT
      LAYER M5 ;
        RECT  66.192 0 66.216 0.084 ;
    END
  END q[146]
  PIN q[147]
    DIRECTION OUTPUT ;
    USE SIGNAL ;
    PORT
      LAYER M5 ;
        RECT  66.288 0 66.312 0.084 ;
    END
  END q[147]
  PIN q[148]
    DIRECTION OUTPUT ;
    USE SIGNAL ;
    PORT
      LAYER M5 ;
        RECT  66.384 0 66.408 0.084 ;
    END
  END q[148]
  PIN q[149]
    DIRECTION OUTPUT ;
    USE SIGNAL ;
    PORT
      LAYER M5 ;
        RECT  66.48 0 66.504 0.084 ;
    END
  END q[149]
  PIN q[14]
    DIRECTION OUTPUT ;
    USE SIGNAL ;
    PORT
      LAYER M5 ;
        RECT  68.88 0 68.904 0.084 ;
    END
  END q[14]
  PIN q[150]
    DIRECTION OUTPUT ;
    USE SIGNAL ;
    PORT
      LAYER M5 ;
        RECT  66.576 0 66.6 0.084 ;
    END
  END q[150]
  PIN q[151]
    DIRECTION OUTPUT ;
    USE SIGNAL ;
    PORT
      LAYER M5 ;
        RECT  66.672 0 66.696 0.084 ;
    END
  END q[151]
  PIN q[152]
    DIRECTION OUTPUT ;
    USE SIGNAL ;
    PORT
      LAYER M5 ;
        RECT  66.768 0 66.792 0.084 ;
    END
  END q[152]
  PIN q[153]
    DIRECTION OUTPUT ;
    USE SIGNAL ;
    PORT
      LAYER M5 ;
        RECT  66.864 0 66.888 0.084 ;
    END
  END q[153]
  PIN q[154]
    DIRECTION OUTPUT ;
    USE SIGNAL ;
    PORT
      LAYER M5 ;
        RECT  66.96 0 66.984 0.084 ;
    END
  END q[154]
  PIN q[155]
    DIRECTION OUTPUT ;
    USE SIGNAL ;
    PORT
      LAYER M5 ;
        RECT  67.056 0 67.08 0.084 ;
    END
  END q[155]
  PIN q[156]
    DIRECTION OUTPUT ;
    USE SIGNAL ;
    PORT
      LAYER M5 ;
        RECT  67.152 0 67.176 0.084 ;
    END
  END q[156]
  PIN q[157]
    DIRECTION OUTPUT ;
    USE SIGNAL ;
    PORT
      LAYER M5 ;
        RECT  67.248 0 67.272 0.084 ;
    END
  END q[157]
  PIN q[158]
    DIRECTION OUTPUT ;
    USE SIGNAL ;
    PORT
      LAYER M5 ;
        RECT  67.344 0 67.368 0.084 ;
    END
  END q[158]
  PIN q[159]
    DIRECTION OUTPUT ;
    USE SIGNAL ;
    PORT
      LAYER M5 ;
        RECT  67.44 0 67.464 0.084 ;
    END
  END q[159]
  PIN q[15]
    DIRECTION OUTPUT ;
    USE SIGNAL ;
    PORT
      LAYER M5 ;
        RECT  68.976 0 69 0.084 ;
    END
  END q[15]
  PIN q[160]
    DIRECTION OUTPUT ;
    USE SIGNAL ;
    PORT
      LAYER M5 ;
        RECT  70.608 0 70.632 0.084 ;
    END
  END q[160]
  PIN q[161]
    DIRECTION OUTPUT ;
    USE SIGNAL ;
    PORT
      LAYER M5 ;
        RECT  70.704 0 70.728 0.084 ;
    END
  END q[161]
  PIN q[162]
    DIRECTION OUTPUT ;
    USE SIGNAL ;
    PORT
      LAYER M5 ;
        RECT  70.8 0 70.824 0.084 ;
    END
  END q[162]
  PIN q[163]
    DIRECTION OUTPUT ;
    USE SIGNAL ;
    PORT
      LAYER M5 ;
        RECT  70.896 0 70.92 0.084 ;
    END
  END q[163]
  PIN q[164]
    DIRECTION OUTPUT ;
    USE SIGNAL ;
    PORT
      LAYER M5 ;
        RECT  70.992 0 71.016 0.084 ;
    END
  END q[164]
  PIN q[165]
    DIRECTION OUTPUT ;
    USE SIGNAL ;
    PORT
      LAYER M5 ;
        RECT  71.088 0 71.112 0.084 ;
    END
  END q[165]
  PIN q[166]
    DIRECTION OUTPUT ;
    USE SIGNAL ;
    PORT
      LAYER M5 ;
        RECT  71.184 0 71.208 0.084 ;
    END
  END q[166]
  PIN q[167]
    DIRECTION OUTPUT ;
    USE SIGNAL ;
    PORT
      LAYER M5 ;
        RECT  71.28 0 71.304 0.084 ;
    END
  END q[167]
  PIN q[168]
    DIRECTION OUTPUT ;
    USE SIGNAL ;
    PORT
      LAYER M5 ;
        RECT  71.376 0 71.4 0.084 ;
    END
  END q[168]
  PIN q[169]
    DIRECTION OUTPUT ;
    USE SIGNAL ;
    PORT
      LAYER M5 ;
        RECT  71.472 0 71.496 0.084 ;
    END
  END q[169]
  PIN q[16]
    DIRECTION OUTPUT ;
    USE SIGNAL ;
    PORT
      LAYER M5 ;
        RECT  69.072 0 69.096 0.084 ;
    END
  END q[16]
  PIN q[170]
    DIRECTION OUTPUT ;
    USE SIGNAL ;
    PORT
      LAYER M5 ;
        RECT  71.568 0 71.592 0.084 ;
    END
  END q[170]
  PIN q[171]
    DIRECTION OUTPUT ;
    USE SIGNAL ;
    PORT
      LAYER M5 ;
        RECT  71.664 0 71.688 0.084 ;
    END
  END q[171]
  PIN q[172]
    DIRECTION OUTPUT ;
    USE SIGNAL ;
    PORT
      LAYER M5 ;
        RECT  71.76 0 71.784 0.084 ;
    END
  END q[172]
  PIN q[173]
    DIRECTION OUTPUT ;
    USE SIGNAL ;
    PORT
      LAYER M5 ;
        RECT  71.856 0 71.88 0.084 ;
    END
  END q[173]
  PIN q[174]
    DIRECTION OUTPUT ;
    USE SIGNAL ;
    PORT
      LAYER M5 ;
        RECT  71.952 0 71.976 0.084 ;
    END
  END q[174]
  PIN q[175]
    DIRECTION OUTPUT ;
    USE SIGNAL ;
    PORT
      LAYER M5 ;
        RECT  72.048 0 72.072 0.084 ;
    END
  END q[175]
  PIN q[176]
    DIRECTION OUTPUT ;
    USE SIGNAL ;
    PORT
      LAYER M5 ;
        RECT  72.144 0 72.168 0.084 ;
    END
  END q[176]
  PIN q[177]
    DIRECTION OUTPUT ;
    USE SIGNAL ;
    PORT
      LAYER M5 ;
        RECT  72.24 0 72.264 0.084 ;
    END
  END q[177]
  PIN q[178]
    DIRECTION OUTPUT ;
    USE SIGNAL ;
    PORT
      LAYER M5 ;
        RECT  72.336 0 72.36 0.084 ;
    END
  END q[178]
  PIN q[179]
    DIRECTION OUTPUT ;
    USE SIGNAL ;
    PORT
      LAYER M5 ;
        RECT  72.432 0 72.456 0.084 ;
    END
  END q[179]
  PIN q[17]
    DIRECTION OUTPUT ;
    USE SIGNAL ;
    PORT
      LAYER M5 ;
        RECT  69.168 0 69.192 0.084 ;
    END
  END q[17]
  PIN q[180]
    DIRECTION OUTPUT ;
    USE SIGNAL ;
    PORT
      LAYER M5 ;
        RECT  72.528 0 72.552 0.084 ;
    END
  END q[180]
  PIN q[181]
    DIRECTION OUTPUT ;
    USE SIGNAL ;
    PORT
      LAYER M5 ;
        RECT  72.624 0 72.648 0.084 ;
    END
  END q[181]
  PIN q[182]
    DIRECTION OUTPUT ;
    USE SIGNAL ;
    PORT
      LAYER M5 ;
        RECT  72.72 0 72.744 0.084 ;
    END
  END q[182]
  PIN q[183]
    DIRECTION OUTPUT ;
    USE SIGNAL ;
    PORT
      LAYER M5 ;
        RECT  72.816 0 72.84 0.084 ;
    END
  END q[183]
  PIN q[184]
    DIRECTION OUTPUT ;
    USE SIGNAL ;
    PORT
      LAYER M5 ;
        RECT  72.912 0 72.936 0.084 ;
    END
  END q[184]
  PIN q[185]
    DIRECTION OUTPUT ;
    USE SIGNAL ;
    PORT
      LAYER M5 ;
        RECT  73.008 0 73.032 0.084 ;
    END
  END q[185]
  PIN q[186]
    DIRECTION OUTPUT ;
    USE SIGNAL ;
    PORT
      LAYER M5 ;
        RECT  73.104 0 73.128 0.084 ;
    END
  END q[186]
  PIN q[187]
    DIRECTION OUTPUT ;
    USE SIGNAL ;
    PORT
      LAYER M5 ;
        RECT  73.2 0 73.224 0.084 ;
    END
  END q[187]
  PIN q[188]
    DIRECTION OUTPUT ;
    USE SIGNAL ;
    PORT
      LAYER M5 ;
        RECT  73.296 0 73.32 0.084 ;
    END
  END q[188]
  PIN q[189]
    DIRECTION OUTPUT ;
    USE SIGNAL ;
    PORT
      LAYER M5 ;
        RECT  73.392 0 73.416 0.084 ;
    END
  END q[189]
  PIN q[18]
    DIRECTION OUTPUT ;
    USE SIGNAL ;
    PORT
      LAYER M5 ;
        RECT  69.264 0 69.288 0.084 ;
    END
  END q[18]
  PIN q[190]
    DIRECTION OUTPUT ;
    USE SIGNAL ;
    PORT
      LAYER M5 ;
        RECT  73.488 0 73.512 0.084 ;
    END
  END q[190]
  PIN q[191]
    DIRECTION OUTPUT ;
    USE SIGNAL ;
    PORT
      LAYER M5 ;
        RECT  73.584 0 73.608 0.084 ;
    END
  END q[191]
  PIN q[192]
    DIRECTION OUTPUT ;
    USE SIGNAL ;
    PORT
      LAYER M5 ;
        RECT  42.192 0 42.216 0.084 ;
    END
  END q[192]
  PIN q[193]
    DIRECTION OUTPUT ;
    USE SIGNAL ;
    PORT
      LAYER M5 ;
        RECT  42.288 0 42.312 0.084 ;
    END
  END q[193]
  PIN q[194]
    DIRECTION OUTPUT ;
    USE SIGNAL ;
    PORT
      LAYER M5 ;
        RECT  42.384 0 42.408 0.084 ;
    END
  END q[194]
  PIN q[195]
    DIRECTION OUTPUT ;
    USE SIGNAL ;
    PORT
      LAYER M5 ;
        RECT  42.48 0 42.504 0.084 ;
    END
  END q[195]
  PIN q[196]
    DIRECTION OUTPUT ;
    USE SIGNAL ;
    PORT
      LAYER M5 ;
        RECT  42.576 0 42.6 0.084 ;
    END
  END q[196]
  PIN q[197]
    DIRECTION OUTPUT ;
    USE SIGNAL ;
    PORT
      LAYER M5 ;
        RECT  42.672 0 42.696 0.084 ;
    END
  END q[197]
  PIN q[198]
    DIRECTION OUTPUT ;
    USE SIGNAL ;
    PORT
      LAYER M5 ;
        RECT  42.768 0 42.792 0.084 ;
    END
  END q[198]
  PIN q[199]
    DIRECTION OUTPUT ;
    USE SIGNAL ;
    PORT
      LAYER M5 ;
        RECT  42.864 0 42.888 0.084 ;
    END
  END q[199]
  PIN q[19]
    DIRECTION OUTPUT ;
    USE SIGNAL ;
    PORT
      LAYER M5 ;
        RECT  69.36 0 69.384 0.084 ;
    END
  END q[19]
  PIN q[1]
    DIRECTION OUTPUT ;
    USE SIGNAL ;
    PORT
      LAYER M5 ;
        RECT  67.632 0 67.656 0.084 ;
    END
  END q[1]
  PIN q[200]
    DIRECTION OUTPUT ;
    USE SIGNAL ;
    PORT
      LAYER M5 ;
        RECT  42.96 0 42.984 0.084 ;
    END
  END q[200]
  PIN q[201]
    DIRECTION OUTPUT ;
    USE SIGNAL ;
    PORT
      LAYER M5 ;
        RECT  43.056 0 43.08 0.084 ;
    END
  END q[201]
  PIN q[202]
    DIRECTION OUTPUT ;
    USE SIGNAL ;
    PORT
      LAYER M5 ;
        RECT  43.152 0 43.176 0.084 ;
    END
  END q[202]
  PIN q[203]
    DIRECTION OUTPUT ;
    USE SIGNAL ;
    PORT
      LAYER M5 ;
        RECT  43.248 0 43.272 0.084 ;
    END
  END q[203]
  PIN q[204]
    DIRECTION OUTPUT ;
    USE SIGNAL ;
    PORT
      LAYER M5 ;
        RECT  43.344 0 43.368 0.084 ;
    END
  END q[204]
  PIN q[205]
    DIRECTION OUTPUT ;
    USE SIGNAL ;
    PORT
      LAYER M5 ;
        RECT  43.44 0 43.464 0.084 ;
    END
  END q[205]
  PIN q[206]
    DIRECTION OUTPUT ;
    USE SIGNAL ;
    PORT
      LAYER M5 ;
        RECT  43.536 0 43.56 0.084 ;
    END
  END q[206]
  PIN q[207]
    DIRECTION OUTPUT ;
    USE SIGNAL ;
    PORT
      LAYER M5 ;
        RECT  43.632 0 43.656 0.084 ;
    END
  END q[207]
  PIN q[208]
    DIRECTION OUTPUT ;
    USE SIGNAL ;
    PORT
      LAYER M5 ;
        RECT  43.728 0 43.752 0.084 ;
    END
  END q[208]
  PIN q[209]
    DIRECTION OUTPUT ;
    USE SIGNAL ;
    PORT
      LAYER M5 ;
        RECT  43.824 0 43.848 0.084 ;
    END
  END q[209]
  PIN q[20]
    DIRECTION OUTPUT ;
    USE SIGNAL ;
    PORT
      LAYER M5 ;
        RECT  69.456 0 69.48 0.084 ;
    END
  END q[20]
  PIN q[210]
    DIRECTION OUTPUT ;
    USE SIGNAL ;
    PORT
      LAYER M5 ;
        RECT  43.92 0 43.944 0.084 ;
    END
  END q[210]
  PIN q[211]
    DIRECTION OUTPUT ;
    USE SIGNAL ;
    PORT
      LAYER M5 ;
        RECT  44.016 0 44.04 0.084 ;
    END
  END q[211]
  PIN q[212]
    DIRECTION OUTPUT ;
    USE SIGNAL ;
    PORT
      LAYER M5 ;
        RECT  44.112 0 44.136 0.084 ;
    END
  END q[212]
  PIN q[213]
    DIRECTION OUTPUT ;
    USE SIGNAL ;
    PORT
      LAYER M5 ;
        RECT  44.208 0 44.232 0.084 ;
    END
  END q[213]
  PIN q[214]
    DIRECTION OUTPUT ;
    USE SIGNAL ;
    PORT
      LAYER M5 ;
        RECT  44.304 0 44.328 0.084 ;
    END
  END q[214]
  PIN q[215]
    DIRECTION OUTPUT ;
    USE SIGNAL ;
    PORT
      LAYER M5 ;
        RECT  44.4 0 44.424 0.084 ;
    END
  END q[215]
  PIN q[216]
    DIRECTION OUTPUT ;
    USE SIGNAL ;
    PORT
      LAYER M5 ;
        RECT  44.496 0 44.52 0.084 ;
    END
  END q[216]
  PIN q[217]
    DIRECTION OUTPUT ;
    USE SIGNAL ;
    PORT
      LAYER M5 ;
        RECT  44.592 0 44.616 0.084 ;
    END
  END q[217]
  PIN q[218]
    DIRECTION OUTPUT ;
    USE SIGNAL ;
    PORT
      LAYER M5 ;
        RECT  44.688 0 44.712 0.084 ;
    END
  END q[218]
  PIN q[219]
    DIRECTION OUTPUT ;
    USE SIGNAL ;
    PORT
      LAYER M5 ;
        RECT  44.784 0 44.808 0.084 ;
    END
  END q[219]
  PIN q[21]
    DIRECTION OUTPUT ;
    USE SIGNAL ;
    PORT
      LAYER M5 ;
        RECT  69.552 0 69.576 0.084 ;
    END
  END q[21]
  PIN q[220]
    DIRECTION OUTPUT ;
    USE SIGNAL ;
    PORT
      LAYER M5 ;
        RECT  44.88 0 44.904 0.084 ;
    END
  END q[220]
  PIN q[221]
    DIRECTION OUTPUT ;
    USE SIGNAL ;
    PORT
      LAYER M5 ;
        RECT  44.976 0 45 0.084 ;
    END
  END q[221]
  PIN q[222]
    DIRECTION OUTPUT ;
    USE SIGNAL ;
    PORT
      LAYER M5 ;
        RECT  45.072 0 45.096 0.084 ;
    END
  END q[222]
  PIN q[223]
    DIRECTION OUTPUT ;
    USE SIGNAL ;
    PORT
      LAYER M5 ;
        RECT  45.168 0 45.192 0.084 ;
    END
  END q[223]
  PIN q[224]
    DIRECTION OUTPUT ;
    USE SIGNAL ;
    PORT
      LAYER M5 ;
        RECT  48.336 0 48.36 0.084 ;
    END
  END q[224]
  PIN q[225]
    DIRECTION OUTPUT ;
    USE SIGNAL ;
    PORT
      LAYER M5 ;
        RECT  48.432 0 48.456 0.084 ;
    END
  END q[225]
  PIN q[226]
    DIRECTION OUTPUT ;
    USE SIGNAL ;
    PORT
      LAYER M5 ;
        RECT  48.528 0 48.552 0.084 ;
    END
  END q[226]
  PIN q[227]
    DIRECTION OUTPUT ;
    USE SIGNAL ;
    PORT
      LAYER M5 ;
        RECT  48.624 0 48.648 0.084 ;
    END
  END q[227]
  PIN q[228]
    DIRECTION OUTPUT ;
    USE SIGNAL ;
    PORT
      LAYER M5 ;
        RECT  48.72 0 48.744 0.084 ;
    END
  END q[228]
  PIN q[229]
    DIRECTION OUTPUT ;
    USE SIGNAL ;
    PORT
      LAYER M5 ;
        RECT  48.816 0 48.84 0.084 ;
    END
  END q[229]
  PIN q[22]
    DIRECTION OUTPUT ;
    USE SIGNAL ;
    PORT
      LAYER M5 ;
        RECT  69.648 0 69.672 0.084 ;
    END
  END q[22]
  PIN q[230]
    DIRECTION OUTPUT ;
    USE SIGNAL ;
    PORT
      LAYER M5 ;
        RECT  48.912 0 48.936 0.084 ;
    END
  END q[230]
  PIN q[231]
    DIRECTION OUTPUT ;
    USE SIGNAL ;
    PORT
      LAYER M5 ;
        RECT  49.008 0 49.032 0.084 ;
    END
  END q[231]
  PIN q[232]
    DIRECTION OUTPUT ;
    USE SIGNAL ;
    PORT
      LAYER M5 ;
        RECT  49.104 0 49.128 0.084 ;
    END
  END q[232]
  PIN q[233]
    DIRECTION OUTPUT ;
    USE SIGNAL ;
    PORT
      LAYER M5 ;
        RECT  49.2 0 49.224 0.084 ;
    END
  END q[233]
  PIN q[234]
    DIRECTION OUTPUT ;
    USE SIGNAL ;
    PORT
      LAYER M5 ;
        RECT  49.296 0 49.32 0.084 ;
    END
  END q[234]
  PIN q[235]
    DIRECTION OUTPUT ;
    USE SIGNAL ;
    PORT
      LAYER M5 ;
        RECT  49.392 0 49.416 0.084 ;
    END
  END q[235]
  PIN q[236]
    DIRECTION OUTPUT ;
    USE SIGNAL ;
    PORT
      LAYER M5 ;
        RECT  49.488 0 49.512 0.084 ;
    END
  END q[236]
  PIN q[237]
    DIRECTION OUTPUT ;
    USE SIGNAL ;
    PORT
      LAYER M5 ;
        RECT  49.584 0 49.608 0.084 ;
    END
  END q[237]
  PIN q[238]
    DIRECTION OUTPUT ;
    USE SIGNAL ;
    PORT
      LAYER M5 ;
        RECT  49.68 0 49.704 0.084 ;
    END
  END q[238]
  PIN q[239]
    DIRECTION OUTPUT ;
    USE SIGNAL ;
    PORT
      LAYER M5 ;
        RECT  49.776 0 49.8 0.084 ;
    END
  END q[239]
  PIN q[23]
    DIRECTION OUTPUT ;
    USE SIGNAL ;
    PORT
      LAYER M5 ;
        RECT  69.744 0 69.768 0.084 ;
    END
  END q[23]
  PIN q[240]
    DIRECTION OUTPUT ;
    USE SIGNAL ;
    PORT
      LAYER M5 ;
        RECT  49.872 0 49.896 0.084 ;
    END
  END q[240]
  PIN q[241]
    DIRECTION OUTPUT ;
    USE SIGNAL ;
    PORT
      LAYER M5 ;
        RECT  49.968 0 49.992 0.084 ;
    END
  END q[241]
  PIN q[242]
    DIRECTION OUTPUT ;
    USE SIGNAL ;
    PORT
      LAYER M5 ;
        RECT  50.064 0 50.088 0.084 ;
    END
  END q[242]
  PIN q[243]
    DIRECTION OUTPUT ;
    USE SIGNAL ;
    PORT
      LAYER M5 ;
        RECT  50.16 0 50.184 0.084 ;
    END
  END q[243]
  PIN q[244]
    DIRECTION OUTPUT ;
    USE SIGNAL ;
    PORT
      LAYER M5 ;
        RECT  50.256 0 50.28 0.084 ;
    END
  END q[244]
  PIN q[245]
    DIRECTION OUTPUT ;
    USE SIGNAL ;
    PORT
      LAYER M5 ;
        RECT  50.352 0 50.376 0.084 ;
    END
  END q[245]
  PIN q[246]
    DIRECTION OUTPUT ;
    USE SIGNAL ;
    PORT
      LAYER M5 ;
        RECT  50.448 0 50.472 0.084 ;
    END
  END q[246]
  PIN q[247]
    DIRECTION OUTPUT ;
    USE SIGNAL ;
    PORT
      LAYER M5 ;
        RECT  50.544 0 50.568 0.084 ;
    END
  END q[247]
  PIN q[248]
    DIRECTION OUTPUT ;
    USE SIGNAL ;
    PORT
      LAYER M5 ;
        RECT  50.64 0 50.664 0.084 ;
    END
  END q[248]
  PIN q[249]
    DIRECTION OUTPUT ;
    USE SIGNAL ;
    PORT
      LAYER M5 ;
        RECT  50.736 0 50.76 0.084 ;
    END
  END q[249]
  PIN q[24]
    DIRECTION OUTPUT ;
    USE SIGNAL ;
    PORT
      LAYER M5 ;
        RECT  69.84 0 69.864 0.084 ;
    END
  END q[24]
  PIN q[250]
    DIRECTION OUTPUT ;
    USE SIGNAL ;
    PORT
      LAYER M5 ;
        RECT  50.832 0 50.856 0.084 ;
    END
  END q[250]
  PIN q[251]
    DIRECTION OUTPUT ;
    USE SIGNAL ;
    PORT
      LAYER M5 ;
        RECT  50.928 0 50.952 0.084 ;
    END
  END q[251]
  PIN q[252]
    DIRECTION OUTPUT ;
    USE SIGNAL ;
    PORT
      LAYER M5 ;
        RECT  51.024 0 51.048 0.084 ;
    END
  END q[252]
  PIN q[253]
    DIRECTION OUTPUT ;
    USE SIGNAL ;
    PORT
      LAYER M5 ;
        RECT  51.12 0 51.144 0.084 ;
    END
  END q[253]
  PIN q[254]
    DIRECTION OUTPUT ;
    USE SIGNAL ;
    PORT
      LAYER M5 ;
        RECT  51.216 0 51.24 0.084 ;
    END
  END q[254]
  PIN q[255]
    DIRECTION OUTPUT ;
    USE SIGNAL ;
    PORT
      LAYER M5 ;
        RECT  51.312 0 51.336 0.084 ;
    END
  END q[255]
  PIN q[256]
    DIRECTION OUTPUT ;
    USE SIGNAL ;
    PORT
      LAYER M5 ;
        RECT  58.32 0 58.344 0.084 ;
    END
  END q[256]
  PIN q[257]
    DIRECTION OUTPUT ;
    USE SIGNAL ;
    PORT
      LAYER M5 ;
        RECT  58.416 0 58.44 0.084 ;
    END
  END q[257]
  PIN q[258]
    DIRECTION OUTPUT ;
    USE SIGNAL ;
    PORT
      LAYER M5 ;
        RECT  58.512 0 58.536 0.084 ;
    END
  END q[258]
  PIN q[259]
    DIRECTION OUTPUT ;
    USE SIGNAL ;
    PORT
      LAYER M5 ;
        RECT  58.608 0 58.632 0.084 ;
    END
  END q[259]
  PIN q[25]
    DIRECTION OUTPUT ;
    USE SIGNAL ;
    PORT
      LAYER M5 ;
        RECT  69.936 0 69.96 0.084 ;
    END
  END q[25]
  PIN q[260]
    DIRECTION OUTPUT ;
    USE SIGNAL ;
    PORT
      LAYER M5 ;
        RECT  58.704 0 58.728 0.084 ;
    END
  END q[260]
  PIN q[261]
    DIRECTION OUTPUT ;
    USE SIGNAL ;
    PORT
      LAYER M5 ;
        RECT  58.8 0 58.824 0.084 ;
    END
  END q[261]
  PIN q[262]
    DIRECTION OUTPUT ;
    USE SIGNAL ;
    PORT
      LAYER M5 ;
        RECT  58.896 0 58.92 0.084 ;
    END
  END q[262]
  PIN q[263]
    DIRECTION OUTPUT ;
    USE SIGNAL ;
    PORT
      LAYER M5 ;
        RECT  58.992 0 59.016 0.084 ;
    END
  END q[263]
  PIN q[264]
    DIRECTION OUTPUT ;
    USE SIGNAL ;
    PORT
      LAYER M5 ;
        RECT  59.088 0 59.112 0.084 ;
    END
  END q[264]
  PIN q[265]
    DIRECTION OUTPUT ;
    USE SIGNAL ;
    PORT
      LAYER M5 ;
        RECT  59.184 0 59.208 0.084 ;
    END
  END q[265]
  PIN q[266]
    DIRECTION OUTPUT ;
    USE SIGNAL ;
    PORT
      LAYER M5 ;
        RECT  59.28 0 59.304 0.084 ;
    END
  END q[266]
  PIN q[267]
    DIRECTION OUTPUT ;
    USE SIGNAL ;
    PORT
      LAYER M5 ;
        RECT  59.376 0 59.4 0.084 ;
    END
  END q[267]
  PIN q[268]
    DIRECTION OUTPUT ;
    USE SIGNAL ;
    PORT
      LAYER M5 ;
        RECT  59.472 0 59.496 0.084 ;
    END
  END q[268]
  PIN q[269]
    DIRECTION OUTPUT ;
    USE SIGNAL ;
    PORT
      LAYER M5 ;
        RECT  59.568 0 59.592 0.084 ;
    END
  END q[269]
  PIN q[26]
    DIRECTION OUTPUT ;
    USE SIGNAL ;
    PORT
      LAYER M5 ;
        RECT  70.032 0 70.056 0.084 ;
    END
  END q[26]
  PIN q[270]
    DIRECTION OUTPUT ;
    USE SIGNAL ;
    PORT
      LAYER M5 ;
        RECT  59.664 0 59.688 0.084 ;
    END
  END q[270]
  PIN q[271]
    DIRECTION OUTPUT ;
    USE SIGNAL ;
    PORT
      LAYER M5 ;
        RECT  59.76 0 59.784 0.084 ;
    END
  END q[271]
  PIN q[272]
    DIRECTION OUTPUT ;
    USE SIGNAL ;
    PORT
      LAYER M5 ;
        RECT  59.856 0 59.88 0.084 ;
    END
  END q[272]
  PIN q[273]
    DIRECTION OUTPUT ;
    USE SIGNAL ;
    PORT
      LAYER M5 ;
        RECT  59.952 0 59.976 0.084 ;
    END
  END q[273]
  PIN q[274]
    DIRECTION OUTPUT ;
    USE SIGNAL ;
    PORT
      LAYER M5 ;
        RECT  60.048 0 60.072 0.084 ;
    END
  END q[274]
  PIN q[275]
    DIRECTION OUTPUT ;
    USE SIGNAL ;
    PORT
      LAYER M5 ;
        RECT  60.144 0 60.168 0.084 ;
    END
  END q[275]
  PIN q[276]
    DIRECTION OUTPUT ;
    USE SIGNAL ;
    PORT
      LAYER M5 ;
        RECT  60.24 0 60.264 0.084 ;
    END
  END q[276]
  PIN q[277]
    DIRECTION OUTPUT ;
    USE SIGNAL ;
    PORT
      LAYER M5 ;
        RECT  60.336 0 60.36 0.084 ;
    END
  END q[277]
  PIN q[278]
    DIRECTION OUTPUT ;
    USE SIGNAL ;
    PORT
      LAYER M5 ;
        RECT  60.432 0 60.456 0.084 ;
    END
  END q[278]
  PIN q[279]
    DIRECTION OUTPUT ;
    USE SIGNAL ;
    PORT
      LAYER M5 ;
        RECT  60.528 0 60.552 0.084 ;
    END
  END q[279]
  PIN q[27]
    DIRECTION OUTPUT ;
    USE SIGNAL ;
    PORT
      LAYER M5 ;
        RECT  70.128 0 70.152 0.084 ;
    END
  END q[27]
  PIN q[280]
    DIRECTION OUTPUT ;
    USE SIGNAL ;
    PORT
      LAYER M5 ;
        RECT  60.624 0 60.648 0.084 ;
    END
  END q[280]
  PIN q[281]
    DIRECTION OUTPUT ;
    USE SIGNAL ;
    PORT
      LAYER M5 ;
        RECT  60.72 0 60.744 0.084 ;
    END
  END q[281]
  PIN q[282]
    DIRECTION OUTPUT ;
    USE SIGNAL ;
    PORT
      LAYER M5 ;
        RECT  60.816 0 60.84 0.084 ;
    END
  END q[282]
  PIN q[283]
    DIRECTION OUTPUT ;
    USE SIGNAL ;
    PORT
      LAYER M5 ;
        RECT  60.912 0 60.936 0.084 ;
    END
  END q[283]
  PIN q[284]
    DIRECTION OUTPUT ;
    USE SIGNAL ;
    PORT
      LAYER M5 ;
        RECT  61.008 0 61.032 0.084 ;
    END
  END q[284]
  PIN q[285]
    DIRECTION OUTPUT ;
    USE SIGNAL ;
    PORT
      LAYER M5 ;
        RECT  61.104 0 61.128 0.084 ;
    END
  END q[285]
  PIN q[286]
    DIRECTION OUTPUT ;
    USE SIGNAL ;
    PORT
      LAYER M5 ;
        RECT  61.2 0 61.224 0.084 ;
    END
  END q[286]
  PIN q[287]
    DIRECTION OUTPUT ;
    USE SIGNAL ;
    PORT
      LAYER M5 ;
        RECT  61.296 0 61.32 0.084 ;
    END
  END q[287]
  PIN q[288]
    DIRECTION OUTPUT ;
    USE SIGNAL ;
    PORT
      LAYER M5 ;
        RECT  54.48 0 54.504 0.084 ;
    END
  END q[288]
  PIN q[289]
    DIRECTION OUTPUT ;
    USE SIGNAL ;
    PORT
      LAYER M5 ;
        RECT  54.576 0 54.6 0.084 ;
    END
  END q[289]
  PIN q[28]
    DIRECTION OUTPUT ;
    USE SIGNAL ;
    PORT
      LAYER M5 ;
        RECT  70.224 0 70.248 0.084 ;
    END
  END q[28]
  PIN q[290]
    DIRECTION OUTPUT ;
    USE SIGNAL ;
    PORT
      LAYER M5 ;
        RECT  54.672 0 54.696 0.084 ;
    END
  END q[290]
  PIN q[291]
    DIRECTION OUTPUT ;
    USE SIGNAL ;
    PORT
      LAYER M5 ;
        RECT  54.768 0 54.792 0.084 ;
    END
  END q[291]
  PIN q[292]
    DIRECTION OUTPUT ;
    USE SIGNAL ;
    PORT
      LAYER M5 ;
        RECT  54.864 0 54.888 0.084 ;
    END
  END q[292]
  PIN q[293]
    DIRECTION OUTPUT ;
    USE SIGNAL ;
    PORT
      LAYER M5 ;
        RECT  54.96 0 54.984 0.084 ;
    END
  END q[293]
  PIN q[294]
    DIRECTION OUTPUT ;
    USE SIGNAL ;
    PORT
      LAYER M5 ;
        RECT  55.056 0 55.08 0.084 ;
    END
  END q[294]
  PIN q[295]
    DIRECTION OUTPUT ;
    USE SIGNAL ;
    PORT
      LAYER M5 ;
        RECT  55.152 0 55.176 0.084 ;
    END
  END q[295]
  PIN q[296]
    DIRECTION OUTPUT ;
    USE SIGNAL ;
    PORT
      LAYER M5 ;
        RECT  55.248 0 55.272 0.084 ;
    END
  END q[296]
  PIN q[297]
    DIRECTION OUTPUT ;
    USE SIGNAL ;
    PORT
      LAYER M5 ;
        RECT  55.344 0 55.368 0.084 ;
    END
  END q[297]
  PIN q[298]
    DIRECTION OUTPUT ;
    USE SIGNAL ;
    PORT
      LAYER M5 ;
        RECT  55.44 0 55.464 0.084 ;
    END
  END q[298]
  PIN q[299]
    DIRECTION OUTPUT ;
    USE SIGNAL ;
    PORT
      LAYER M5 ;
        RECT  55.536 0 55.56 0.084 ;
    END
  END q[299]
  PIN q[29]
    DIRECTION OUTPUT ;
    USE SIGNAL ;
    PORT
      LAYER M5 ;
        RECT  70.32 0 70.344 0.084 ;
    END
  END q[29]
  PIN q[2]
    DIRECTION OUTPUT ;
    USE SIGNAL ;
    PORT
      LAYER M5 ;
        RECT  67.728 0 67.752 0.084 ;
    END
  END q[2]
  PIN q[300]
    DIRECTION OUTPUT ;
    USE SIGNAL ;
    PORT
      LAYER M5 ;
        RECT  55.632 0 55.656 0.084 ;
    END
  END q[300]
  PIN q[301]
    DIRECTION OUTPUT ;
    USE SIGNAL ;
    PORT
      LAYER M5 ;
        RECT  55.728 0 55.752 0.084 ;
    END
  END q[301]
  PIN q[302]
    DIRECTION OUTPUT ;
    USE SIGNAL ;
    PORT
      LAYER M5 ;
        RECT  55.824 0 55.848 0.084 ;
    END
  END q[302]
  PIN q[303]
    DIRECTION OUTPUT ;
    USE SIGNAL ;
    PORT
      LAYER M5 ;
        RECT  55.92 0 55.944 0.084 ;
    END
  END q[303]
  PIN q[304]
    DIRECTION OUTPUT ;
    USE SIGNAL ;
    PORT
      LAYER M5 ;
        RECT  56.016 0 56.04 0.084 ;
    END
  END q[304]
  PIN q[305]
    DIRECTION OUTPUT ;
    USE SIGNAL ;
    PORT
      LAYER M5 ;
        RECT  56.112 0 56.136 0.084 ;
    END
  END q[305]
  PIN q[306]
    DIRECTION OUTPUT ;
    USE SIGNAL ;
    PORT
      LAYER M5 ;
        RECT  56.208 0 56.232 0.084 ;
    END
  END q[306]
  PIN q[307]
    DIRECTION OUTPUT ;
    USE SIGNAL ;
    PORT
      LAYER M5 ;
        RECT  56.304 0 56.328 0.084 ;
    END
  END q[307]
  PIN q[308]
    DIRECTION OUTPUT ;
    USE SIGNAL ;
    PORT
      LAYER M5 ;
        RECT  56.4 0 56.424 0.084 ;
    END
  END q[308]
  PIN q[309]
    DIRECTION OUTPUT ;
    USE SIGNAL ;
    PORT
      LAYER M5 ;
        RECT  56.496 0 56.52 0.084 ;
    END
  END q[309]
  PIN q[30]
    DIRECTION OUTPUT ;
    USE SIGNAL ;
    PORT
      LAYER M5 ;
        RECT  70.416 0 70.44 0.084 ;
    END
  END q[30]
  PIN q[310]
    DIRECTION OUTPUT ;
    USE SIGNAL ;
    PORT
      LAYER M5 ;
        RECT  56.592 0 56.616 0.084 ;
    END
  END q[310]
  PIN q[311]
    DIRECTION OUTPUT ;
    USE SIGNAL ;
    PORT
      LAYER M5 ;
        RECT  56.688 0 56.712 0.084 ;
    END
  END q[311]
  PIN q[312]
    DIRECTION OUTPUT ;
    USE SIGNAL ;
    PORT
      LAYER M5 ;
        RECT  56.784 0 56.808 0.084 ;
    END
  END q[312]
  PIN q[313]
    DIRECTION OUTPUT ;
    USE SIGNAL ;
    PORT
      LAYER M5 ;
        RECT  56.88 0 56.904 0.084 ;
    END
  END q[313]
  PIN q[314]
    DIRECTION OUTPUT ;
    USE SIGNAL ;
    PORT
      LAYER M5 ;
        RECT  56.976 0 57 0.084 ;
    END
  END q[314]
  PIN q[315]
    DIRECTION OUTPUT ;
    USE SIGNAL ;
    PORT
      LAYER M5 ;
        RECT  57.072 0 57.096 0.084 ;
    END
  END q[315]
  PIN q[316]
    DIRECTION OUTPUT ;
    USE SIGNAL ;
    PORT
      LAYER M5 ;
        RECT  57.168 0 57.192 0.084 ;
    END
  END q[316]
  PIN q[317]
    DIRECTION OUTPUT ;
    USE SIGNAL ;
    PORT
      LAYER M5 ;
        RECT  57.264 0 57.288 0.084 ;
    END
  END q[317]
  PIN q[318]
    DIRECTION OUTPUT ;
    USE SIGNAL ;
    PORT
      LAYER M5 ;
        RECT  57.36 0 57.384 0.084 ;
    END
  END q[318]
  PIN q[319]
    DIRECTION OUTPUT ;
    USE SIGNAL ;
    PORT
      LAYER M5 ;
        RECT  57.456 0 57.48 0.084 ;
    END
  END q[319]
  PIN q[31]
    DIRECTION OUTPUT ;
    USE SIGNAL ;
    PORT
      LAYER M5 ;
        RECT  70.512 0 70.536 0.084 ;
    END
  END q[31]
  PIN q[320]
    DIRECTION OUTPUT ;
    USE SIGNAL ;
    PORT
      LAYER M5 ;
        RECT  51.408 0 51.432 0.084 ;
    END
  END q[320]
  PIN q[321]
    DIRECTION OUTPUT ;
    USE SIGNAL ;
    PORT
      LAYER M5 ;
        RECT  51.504 0 51.528 0.084 ;
    END
  END q[321]
  PIN q[322]
    DIRECTION OUTPUT ;
    USE SIGNAL ;
    PORT
      LAYER M5 ;
        RECT  51.6 0 51.624 0.084 ;
    END
  END q[322]
  PIN q[323]
    DIRECTION OUTPUT ;
    USE SIGNAL ;
    PORT
      LAYER M5 ;
        RECT  51.696 0 51.72 0.084 ;
    END
  END q[323]
  PIN q[324]
    DIRECTION OUTPUT ;
    USE SIGNAL ;
    PORT
      LAYER M5 ;
        RECT  51.792 0 51.816 0.084 ;
    END
  END q[324]
  PIN q[325]
    DIRECTION OUTPUT ;
    USE SIGNAL ;
    PORT
      LAYER M5 ;
        RECT  51.888 0 51.912 0.084 ;
    END
  END q[325]
  PIN q[326]
    DIRECTION OUTPUT ;
    USE SIGNAL ;
    PORT
      LAYER M5 ;
        RECT  51.984 0 52.008 0.084 ;
    END
  END q[326]
  PIN q[327]
    DIRECTION OUTPUT ;
    USE SIGNAL ;
    PORT
      LAYER M5 ;
        RECT  52.08 0 52.104 0.084 ;
    END
  END q[327]
  PIN q[328]
    DIRECTION OUTPUT ;
    USE SIGNAL ;
    PORT
      LAYER M5 ;
        RECT  52.176 0 52.2 0.084 ;
    END
  END q[328]
  PIN q[329]
    DIRECTION OUTPUT ;
    USE SIGNAL ;
    PORT
      LAYER M5 ;
        RECT  52.272 0 52.296 0.084 ;
    END
  END q[329]
  PIN q[32]
    DIRECTION OUTPUT ;
    USE SIGNAL ;
    PORT
      LAYER M5 ;
        RECT  61.392 0 61.416 0.084 ;
    END
  END q[32]
  PIN q[330]
    DIRECTION OUTPUT ;
    USE SIGNAL ;
    PORT
      LAYER M5 ;
        RECT  52.368 0 52.392 0.084 ;
    END
  END q[330]
  PIN q[331]
    DIRECTION OUTPUT ;
    USE SIGNAL ;
    PORT
      LAYER M5 ;
        RECT  52.464 0 52.488 0.084 ;
    END
  END q[331]
  PIN q[332]
    DIRECTION OUTPUT ;
    USE SIGNAL ;
    PORT
      LAYER M5 ;
        RECT  52.56 0 52.584 0.084 ;
    END
  END q[332]
  PIN q[333]
    DIRECTION OUTPUT ;
    USE SIGNAL ;
    PORT
      LAYER M5 ;
        RECT  52.656 0 52.68 0.084 ;
    END
  END q[333]
  PIN q[334]
    DIRECTION OUTPUT ;
    USE SIGNAL ;
    PORT
      LAYER M5 ;
        RECT  52.752 0 52.776 0.084 ;
    END
  END q[334]
  PIN q[335]
    DIRECTION OUTPUT ;
    USE SIGNAL ;
    PORT
      LAYER M5 ;
        RECT  52.848 0 52.872 0.084 ;
    END
  END q[335]
  PIN q[336]
    DIRECTION OUTPUT ;
    USE SIGNAL ;
    PORT
      LAYER M5 ;
        RECT  52.944 0 52.968 0.084 ;
    END
  END q[336]
  PIN q[337]
    DIRECTION OUTPUT ;
    USE SIGNAL ;
    PORT
      LAYER M5 ;
        RECT  53.04 0 53.064 0.084 ;
    END
  END q[337]
  PIN q[338]
    DIRECTION OUTPUT ;
    USE SIGNAL ;
    PORT
      LAYER M5 ;
        RECT  53.136 0 53.16 0.084 ;
    END
  END q[338]
  PIN q[339]
    DIRECTION OUTPUT ;
    USE SIGNAL ;
    PORT
      LAYER M5 ;
        RECT  53.232 0 53.256 0.084 ;
    END
  END q[339]
  PIN q[33]
    DIRECTION OUTPUT ;
    USE SIGNAL ;
    PORT
      LAYER M5 ;
        RECT  61.488 0 61.512 0.084 ;
    END
  END q[33]
  PIN q[340]
    DIRECTION OUTPUT ;
    USE SIGNAL ;
    PORT
      LAYER M5 ;
        RECT  53.328 0 53.352 0.084 ;
    END
  END q[340]
  PIN q[341]
    DIRECTION OUTPUT ;
    USE SIGNAL ;
    PORT
      LAYER M5 ;
        RECT  53.424 0 53.448 0.084 ;
    END
  END q[341]
  PIN q[342]
    DIRECTION OUTPUT ;
    USE SIGNAL ;
    PORT
      LAYER M5 ;
        RECT  53.52 0 53.544 0.084 ;
    END
  END q[342]
  PIN q[343]
    DIRECTION OUTPUT ;
    USE SIGNAL ;
    PORT
      LAYER M5 ;
        RECT  53.616 0 53.64 0.084 ;
    END
  END q[343]
  PIN q[344]
    DIRECTION OUTPUT ;
    USE SIGNAL ;
    PORT
      LAYER M5 ;
        RECT  53.712 0 53.736 0.084 ;
    END
  END q[344]
  PIN q[345]
    DIRECTION OUTPUT ;
    USE SIGNAL ;
    PORT
      LAYER M5 ;
        RECT  53.808 0 53.832 0.084 ;
    END
  END q[345]
  PIN q[346]
    DIRECTION OUTPUT ;
    USE SIGNAL ;
    PORT
      LAYER M5 ;
        RECT  53.904 0 53.928 0.084 ;
    END
  END q[346]
  PIN q[347]
    DIRECTION OUTPUT ;
    USE SIGNAL ;
    PORT
      LAYER M5 ;
        RECT  54 0 54.024 0.084 ;
    END
  END q[347]
  PIN q[348]
    DIRECTION OUTPUT ;
    USE SIGNAL ;
    PORT
      LAYER M5 ;
        RECT  54.096 0 54.12 0.084 ;
    END
  END q[348]
  PIN q[349]
    DIRECTION OUTPUT ;
    USE SIGNAL ;
    PORT
      LAYER M5 ;
        RECT  54.192 0 54.216 0.084 ;
    END
  END q[349]
  PIN q[34]
    DIRECTION OUTPUT ;
    USE SIGNAL ;
    PORT
      LAYER M5 ;
        RECT  61.584 0 61.608 0.084 ;
    END
  END q[34]
  PIN q[350]
    DIRECTION OUTPUT ;
    USE SIGNAL ;
    PORT
      LAYER M5 ;
        RECT  54.288 0 54.312 0.084 ;
    END
  END q[350]
  PIN q[351]
    DIRECTION OUTPUT ;
    USE SIGNAL ;
    PORT
      LAYER M5 ;
        RECT  54.384 0 54.408 0.084 ;
    END
  END q[351]
  PIN q[352]
    DIRECTION OUTPUT ;
    USE SIGNAL ;
    PORT
      LAYER M5 ;
        RECT  39.12 0 39.144 0.084 ;
    END
  END q[352]
  PIN q[353]
    DIRECTION OUTPUT ;
    USE SIGNAL ;
    PORT
      LAYER M5 ;
        RECT  39.216 0 39.24 0.084 ;
    END
  END q[353]
  PIN q[354]
    DIRECTION OUTPUT ;
    USE SIGNAL ;
    PORT
      LAYER M5 ;
        RECT  39.312 0 39.336 0.084 ;
    END
  END q[354]
  PIN q[355]
    DIRECTION OUTPUT ;
    USE SIGNAL ;
    PORT
      LAYER M5 ;
        RECT  39.408 0 39.432 0.084 ;
    END
  END q[355]
  PIN q[356]
    DIRECTION OUTPUT ;
    USE SIGNAL ;
    PORT
      LAYER M5 ;
        RECT  39.504 0 39.528 0.084 ;
    END
  END q[356]
  PIN q[357]
    DIRECTION OUTPUT ;
    USE SIGNAL ;
    PORT
      LAYER M5 ;
        RECT  39.6 0 39.624 0.084 ;
    END
  END q[357]
  PIN q[358]
    DIRECTION OUTPUT ;
    USE SIGNAL ;
    PORT
      LAYER M5 ;
        RECT  39.696 0 39.72 0.084 ;
    END
  END q[358]
  PIN q[359]
    DIRECTION OUTPUT ;
    USE SIGNAL ;
    PORT
      LAYER M5 ;
        RECT  39.792 0 39.816 0.084 ;
    END
  END q[359]
  PIN q[35]
    DIRECTION OUTPUT ;
    USE SIGNAL ;
    PORT
      LAYER M5 ;
        RECT  61.68 0 61.704 0.084 ;
    END
  END q[35]
  PIN q[360]
    DIRECTION OUTPUT ;
    USE SIGNAL ;
    PORT
      LAYER M5 ;
        RECT  39.888 0 39.912 0.084 ;
    END
  END q[360]
  PIN q[361]
    DIRECTION OUTPUT ;
    USE SIGNAL ;
    PORT
      LAYER M5 ;
        RECT  39.984 0 40.008 0.084 ;
    END
  END q[361]
  PIN q[362]
    DIRECTION OUTPUT ;
    USE SIGNAL ;
    PORT
      LAYER M5 ;
        RECT  40.08 0 40.104 0.084 ;
    END
  END q[362]
  PIN q[363]
    DIRECTION OUTPUT ;
    USE SIGNAL ;
    PORT
      LAYER M5 ;
        RECT  40.176 0 40.2 0.084 ;
    END
  END q[363]
  PIN q[364]
    DIRECTION OUTPUT ;
    USE SIGNAL ;
    PORT
      LAYER M5 ;
        RECT  40.272 0 40.296 0.084 ;
    END
  END q[364]
  PIN q[365]
    DIRECTION OUTPUT ;
    USE SIGNAL ;
    PORT
      LAYER M5 ;
        RECT  40.368 0 40.392 0.084 ;
    END
  END q[365]
  PIN q[366]
    DIRECTION OUTPUT ;
    USE SIGNAL ;
    PORT
      LAYER M5 ;
        RECT  40.464 0 40.488 0.084 ;
    END
  END q[366]
  PIN q[367]
    DIRECTION OUTPUT ;
    USE SIGNAL ;
    PORT
      LAYER M5 ;
        RECT  40.56 0 40.584 0.084 ;
    END
  END q[367]
  PIN q[368]
    DIRECTION OUTPUT ;
    USE SIGNAL ;
    PORT
      LAYER M5 ;
        RECT  40.656 0 40.68 0.084 ;
    END
  END q[368]
  PIN q[369]
    DIRECTION OUTPUT ;
    USE SIGNAL ;
    PORT
      LAYER M5 ;
        RECT  40.752 0 40.776 0.084 ;
    END
  END q[369]
  PIN q[36]
    DIRECTION OUTPUT ;
    USE SIGNAL ;
    PORT
      LAYER M5 ;
        RECT  61.776 0 61.8 0.084 ;
    END
  END q[36]
  PIN q[370]
    DIRECTION OUTPUT ;
    USE SIGNAL ;
    PORT
      LAYER M5 ;
        RECT  40.848 0 40.872 0.084 ;
    END
  END q[370]
  PIN q[371]
    DIRECTION OUTPUT ;
    USE SIGNAL ;
    PORT
      LAYER M5 ;
        RECT  40.944 0 40.968 0.084 ;
    END
  END q[371]
  PIN q[372]
    DIRECTION OUTPUT ;
    USE SIGNAL ;
    PORT
      LAYER M5 ;
        RECT  41.04 0 41.064 0.084 ;
    END
  END q[372]
  PIN q[373]
    DIRECTION OUTPUT ;
    USE SIGNAL ;
    PORT
      LAYER M5 ;
        RECT  41.136 0 41.16 0.084 ;
    END
  END q[373]
  PIN q[374]
    DIRECTION OUTPUT ;
    USE SIGNAL ;
    PORT
      LAYER M5 ;
        RECT  41.232 0 41.256 0.084 ;
    END
  END q[374]
  PIN q[375]
    DIRECTION OUTPUT ;
    USE SIGNAL ;
    PORT
      LAYER M5 ;
        RECT  41.328 0 41.352 0.084 ;
    END
  END q[375]
  PIN q[376]
    DIRECTION OUTPUT ;
    USE SIGNAL ;
    PORT
      LAYER M5 ;
        RECT  41.424 0 41.448 0.084 ;
    END
  END q[376]
  PIN q[377]
    DIRECTION OUTPUT ;
    USE SIGNAL ;
    PORT
      LAYER M5 ;
        RECT  41.52 0 41.544 0.084 ;
    END
  END q[377]
  PIN q[378]
    DIRECTION OUTPUT ;
    USE SIGNAL ;
    PORT
      LAYER M5 ;
        RECT  41.616 0 41.64 0.084 ;
    END
  END q[378]
  PIN q[379]
    DIRECTION OUTPUT ;
    USE SIGNAL ;
    PORT
      LAYER M5 ;
        RECT  41.712 0 41.736 0.084 ;
    END
  END q[379]
  PIN q[37]
    DIRECTION OUTPUT ;
    USE SIGNAL ;
    PORT
      LAYER M5 ;
        RECT  61.872 0 61.896 0.084 ;
    END
  END q[37]
  PIN q[380]
    DIRECTION OUTPUT ;
    USE SIGNAL ;
    PORT
      LAYER M5 ;
        RECT  41.808 0 41.832 0.084 ;
    END
  END q[380]
  PIN q[381]
    DIRECTION OUTPUT ;
    USE SIGNAL ;
    PORT
      LAYER M5 ;
        RECT  41.904 0 41.928 0.084 ;
    END
  END q[381]
  PIN q[382]
    DIRECTION OUTPUT ;
    USE SIGNAL ;
    PORT
      LAYER M5 ;
        RECT  42 0 42.024 0.084 ;
    END
  END q[382]
  PIN q[383]
    DIRECTION OUTPUT ;
    USE SIGNAL ;
    PORT
      LAYER M5 ;
        RECT  42.096 0 42.12 0.084 ;
    END
  END q[383]
  PIN q[384]
    DIRECTION OUTPUT ;
    USE SIGNAL ;
    PORT
      LAYER M5 ;
        RECT  92.88 0 92.904 0.084 ;
    END
  END q[384]
  PIN q[385]
    DIRECTION OUTPUT ;
    USE SIGNAL ;
    PORT
      LAYER M5 ;
        RECT  92.976 0 93 0.084 ;
    END
  END q[385]
  PIN q[386]
    DIRECTION OUTPUT ;
    USE SIGNAL ;
    PORT
      LAYER M5 ;
        RECT  93.072 0 93.096 0.084 ;
    END
  END q[386]
  PIN q[387]
    DIRECTION OUTPUT ;
    USE SIGNAL ;
    PORT
      LAYER M5 ;
        RECT  93.168 0 93.192 0.084 ;
    END
  END q[387]
  PIN q[388]
    DIRECTION OUTPUT ;
    USE SIGNAL ;
    PORT
      LAYER M5 ;
        RECT  93.264 0 93.288 0.084 ;
    END
  END q[388]
  PIN q[389]
    DIRECTION OUTPUT ;
    USE SIGNAL ;
    PORT
      LAYER M5 ;
        RECT  93.36 0 93.384 0.084 ;
    END
  END q[389]
  PIN q[38]
    DIRECTION OUTPUT ;
    USE SIGNAL ;
    PORT
      LAYER M5 ;
        RECT  61.968 0 61.992 0.084 ;
    END
  END q[38]
  PIN q[390]
    DIRECTION OUTPUT ;
    USE SIGNAL ;
    PORT
      LAYER M5 ;
        RECT  93.456 0 93.48 0.084 ;
    END
  END q[390]
  PIN q[391]
    DIRECTION OUTPUT ;
    USE SIGNAL ;
    PORT
      LAYER M5 ;
        RECT  93.552 0 93.576 0.084 ;
    END
  END q[391]
  PIN q[392]
    DIRECTION OUTPUT ;
    USE SIGNAL ;
    PORT
      LAYER M5 ;
        RECT  93.648 0 93.672 0.084 ;
    END
  END q[392]
  PIN q[393]
    DIRECTION OUTPUT ;
    USE SIGNAL ;
    PORT
      LAYER M5 ;
        RECT  93.744 0 93.768 0.084 ;
    END
  END q[393]
  PIN q[394]
    DIRECTION OUTPUT ;
    USE SIGNAL ;
    PORT
      LAYER M5 ;
        RECT  93.84 0 93.864 0.084 ;
    END
  END q[394]
  PIN q[395]
    DIRECTION OUTPUT ;
    USE SIGNAL ;
    PORT
      LAYER M5 ;
        RECT  93.936 0 93.96 0.084 ;
    END
  END q[395]
  PIN q[396]
    DIRECTION OUTPUT ;
    USE SIGNAL ;
    PORT
      LAYER M5 ;
        RECT  94.032 0 94.056 0.084 ;
    END
  END q[396]
  PIN q[397]
    DIRECTION OUTPUT ;
    USE SIGNAL ;
    PORT
      LAYER M5 ;
        RECT  94.128 0 94.152 0.084 ;
    END
  END q[397]
  PIN q[398]
    DIRECTION OUTPUT ;
    USE SIGNAL ;
    PORT
      LAYER M5 ;
        RECT  94.224 0 94.248 0.084 ;
    END
  END q[398]
  PIN q[399]
    DIRECTION OUTPUT ;
    USE SIGNAL ;
    PORT
      LAYER M5 ;
        RECT  94.32 0 94.344 0.084 ;
    END
  END q[399]
  PIN q[39]
    DIRECTION OUTPUT ;
    USE SIGNAL ;
    PORT
      LAYER M5 ;
        RECT  62.064 0 62.088 0.084 ;
    END
  END q[39]
  PIN q[3]
    DIRECTION OUTPUT ;
    USE SIGNAL ;
    PORT
      LAYER M5 ;
        RECT  67.824 0 67.848 0.084 ;
    END
  END q[3]
  PIN q[400]
    DIRECTION OUTPUT ;
    USE SIGNAL ;
    PORT
      LAYER M5 ;
        RECT  94.416 0 94.44 0.084 ;
    END
  END q[400]
  PIN q[401]
    DIRECTION OUTPUT ;
    USE SIGNAL ;
    PORT
      LAYER M5 ;
        RECT  94.512 0 94.536 0.084 ;
    END
  END q[401]
  PIN q[402]
    DIRECTION OUTPUT ;
    USE SIGNAL ;
    PORT
      LAYER M5 ;
        RECT  94.608 0 94.632 0.084 ;
    END
  END q[402]
  PIN q[403]
    DIRECTION OUTPUT ;
    USE SIGNAL ;
    PORT
      LAYER M5 ;
        RECT  94.704 0 94.728 0.084 ;
    END
  END q[403]
  PIN q[404]
    DIRECTION OUTPUT ;
    USE SIGNAL ;
    PORT
      LAYER M5 ;
        RECT  94.8 0 94.824 0.084 ;
    END
  END q[404]
  PIN q[405]
    DIRECTION OUTPUT ;
    USE SIGNAL ;
    PORT
      LAYER M5 ;
        RECT  94.896 0 94.92 0.084 ;
    END
  END q[405]
  PIN q[406]
    DIRECTION OUTPUT ;
    USE SIGNAL ;
    PORT
      LAYER M5 ;
        RECT  94.992 0 95.016 0.084 ;
    END
  END q[406]
  PIN q[407]
    DIRECTION OUTPUT ;
    USE SIGNAL ;
    PORT
      LAYER M5 ;
        RECT  95.088 0 95.112 0.084 ;
    END
  END q[407]
  PIN q[408]
    DIRECTION OUTPUT ;
    USE SIGNAL ;
    PORT
      LAYER M5 ;
        RECT  95.184 0 95.208 0.084 ;
    END
  END q[408]
  PIN q[409]
    DIRECTION OUTPUT ;
    USE SIGNAL ;
    PORT
      LAYER M5 ;
        RECT  95.28 0 95.304 0.084 ;
    END
  END q[409]
  PIN q[40]
    DIRECTION OUTPUT ;
    USE SIGNAL ;
    PORT
      LAYER M5 ;
        RECT  62.16 0 62.184 0.084 ;
    END
  END q[40]
  PIN q[410]
    DIRECTION OUTPUT ;
    USE SIGNAL ;
    PORT
      LAYER M5 ;
        RECT  95.376 0 95.4 0.084 ;
    END
  END q[410]
  PIN q[411]
    DIRECTION OUTPUT ;
    USE SIGNAL ;
    PORT
      LAYER M5 ;
        RECT  95.472 0 95.496 0.084 ;
    END
  END q[411]
  PIN q[412]
    DIRECTION OUTPUT ;
    USE SIGNAL ;
    PORT
      LAYER M5 ;
        RECT  95.568 0 95.592 0.084 ;
    END
  END q[412]
  PIN q[413]
    DIRECTION OUTPUT ;
    USE SIGNAL ;
    PORT
      LAYER M5 ;
        RECT  95.664 0 95.688 0.084 ;
    END
  END q[413]
  PIN q[414]
    DIRECTION OUTPUT ;
    USE SIGNAL ;
    PORT
      LAYER M5 ;
        RECT  95.76 0 95.784 0.084 ;
    END
  END q[414]
  PIN q[415]
    DIRECTION OUTPUT ;
    USE SIGNAL ;
    PORT
      LAYER M5 ;
        RECT  95.856 0 95.88 0.084 ;
    END
  END q[415]
  PIN q[416]
    DIRECTION OUTPUT ;
    USE SIGNAL ;
    PORT
      LAYER M5 ;
        RECT  89.808 0 89.832 0.084 ;
    END
  END q[416]
  PIN q[417]
    DIRECTION OUTPUT ;
    USE SIGNAL ;
    PORT
      LAYER M5 ;
        RECT  89.904 0 89.928 0.084 ;
    END
  END q[417]
  PIN q[418]
    DIRECTION OUTPUT ;
    USE SIGNAL ;
    PORT
      LAYER M5 ;
        RECT  90 0 90.024 0.084 ;
    END
  END q[418]
  PIN q[419]
    DIRECTION OUTPUT ;
    USE SIGNAL ;
    PORT
      LAYER M5 ;
        RECT  90.096 0 90.12 0.084 ;
    END
  END q[419]
  PIN q[41]
    DIRECTION OUTPUT ;
    USE SIGNAL ;
    PORT
      LAYER M5 ;
        RECT  62.256 0 62.28 0.084 ;
    END
  END q[41]
  PIN q[420]
    DIRECTION OUTPUT ;
    USE SIGNAL ;
    PORT
      LAYER M5 ;
        RECT  90.192 0 90.216 0.084 ;
    END
  END q[420]
  PIN q[421]
    DIRECTION OUTPUT ;
    USE SIGNAL ;
    PORT
      LAYER M5 ;
        RECT  90.288 0 90.312 0.084 ;
    END
  END q[421]
  PIN q[422]
    DIRECTION OUTPUT ;
    USE SIGNAL ;
    PORT
      LAYER M5 ;
        RECT  90.384 0 90.408 0.084 ;
    END
  END q[422]
  PIN q[423]
    DIRECTION OUTPUT ;
    USE SIGNAL ;
    PORT
      LAYER M5 ;
        RECT  90.48 0 90.504 0.084 ;
    END
  END q[423]
  PIN q[424]
    DIRECTION OUTPUT ;
    USE SIGNAL ;
    PORT
      LAYER M5 ;
        RECT  90.576 0 90.6 0.084 ;
    END
  END q[424]
  PIN q[425]
    DIRECTION OUTPUT ;
    USE SIGNAL ;
    PORT
      LAYER M5 ;
        RECT  90.672 0 90.696 0.084 ;
    END
  END q[425]
  PIN q[426]
    DIRECTION OUTPUT ;
    USE SIGNAL ;
    PORT
      LAYER M5 ;
        RECT  90.768 0 90.792 0.084 ;
    END
  END q[426]
  PIN q[427]
    DIRECTION OUTPUT ;
    USE SIGNAL ;
    PORT
      LAYER M5 ;
        RECT  90.864 0 90.888 0.084 ;
    END
  END q[427]
  PIN q[428]
    DIRECTION OUTPUT ;
    USE SIGNAL ;
    PORT
      LAYER M5 ;
        RECT  90.96 0 90.984 0.084 ;
    END
  END q[428]
  PIN q[429]
    DIRECTION OUTPUT ;
    USE SIGNAL ;
    PORT
      LAYER M5 ;
        RECT  91.056 0 91.08 0.084 ;
    END
  END q[429]
  PIN q[42]
    DIRECTION OUTPUT ;
    USE SIGNAL ;
    PORT
      LAYER M5 ;
        RECT  62.352 0 62.376 0.084 ;
    END
  END q[42]
  PIN q[430]
    DIRECTION OUTPUT ;
    USE SIGNAL ;
    PORT
      LAYER M5 ;
        RECT  91.152 0 91.176 0.084 ;
    END
  END q[430]
  PIN q[431]
    DIRECTION OUTPUT ;
    USE SIGNAL ;
    PORT
      LAYER M5 ;
        RECT  91.248 0 91.272 0.084 ;
    END
  END q[431]
  PIN q[432]
    DIRECTION OUTPUT ;
    USE SIGNAL ;
    PORT
      LAYER M5 ;
        RECT  91.344 0 91.368 0.084 ;
    END
  END q[432]
  PIN q[433]
    DIRECTION OUTPUT ;
    USE SIGNAL ;
    PORT
      LAYER M5 ;
        RECT  91.44 0 91.464 0.084 ;
    END
  END q[433]
  PIN q[434]
    DIRECTION OUTPUT ;
    USE SIGNAL ;
    PORT
      LAYER M5 ;
        RECT  91.536 0 91.56 0.084 ;
    END
  END q[434]
  PIN q[435]
    DIRECTION OUTPUT ;
    USE SIGNAL ;
    PORT
      LAYER M5 ;
        RECT  91.632 0 91.656 0.084 ;
    END
  END q[435]
  PIN q[436]
    DIRECTION OUTPUT ;
    USE SIGNAL ;
    PORT
      LAYER M5 ;
        RECT  91.728 0 91.752 0.084 ;
    END
  END q[436]
  PIN q[437]
    DIRECTION OUTPUT ;
    USE SIGNAL ;
    PORT
      LAYER M5 ;
        RECT  91.824 0 91.848 0.084 ;
    END
  END q[437]
  PIN q[438]
    DIRECTION OUTPUT ;
    USE SIGNAL ;
    PORT
      LAYER M5 ;
        RECT  91.92 0 91.944 0.084 ;
    END
  END q[438]
  PIN q[439]
    DIRECTION OUTPUT ;
    USE SIGNAL ;
    PORT
      LAYER M5 ;
        RECT  92.016 0 92.04 0.084 ;
    END
  END q[439]
  PIN q[43]
    DIRECTION OUTPUT ;
    USE SIGNAL ;
    PORT
      LAYER M5 ;
        RECT  62.448 0 62.472 0.084 ;
    END
  END q[43]
  PIN q[440]
    DIRECTION OUTPUT ;
    USE SIGNAL ;
    PORT
      LAYER M5 ;
        RECT  92.112 0 92.136 0.084 ;
    END
  END q[440]
  PIN q[441]
    DIRECTION OUTPUT ;
    USE SIGNAL ;
    PORT
      LAYER M5 ;
        RECT  92.208 0 92.232 0.084 ;
    END
  END q[441]
  PIN q[442]
    DIRECTION OUTPUT ;
    USE SIGNAL ;
    PORT
      LAYER M5 ;
        RECT  92.304 0 92.328 0.084 ;
    END
  END q[442]
  PIN q[443]
    DIRECTION OUTPUT ;
    USE SIGNAL ;
    PORT
      LAYER M5 ;
        RECT  92.4 0 92.424 0.084 ;
    END
  END q[443]
  PIN q[444]
    DIRECTION OUTPUT ;
    USE SIGNAL ;
    PORT
      LAYER M5 ;
        RECT  92.496 0 92.52 0.084 ;
    END
  END q[444]
  PIN q[445]
    DIRECTION OUTPUT ;
    USE SIGNAL ;
    PORT
      LAYER M5 ;
        RECT  92.592 0 92.616 0.084 ;
    END
  END q[445]
  PIN q[446]
    DIRECTION OUTPUT ;
    USE SIGNAL ;
    PORT
      LAYER M5 ;
        RECT  92.688 0 92.712 0.084 ;
    END
  END q[446]
  PIN q[447]
    DIRECTION OUTPUT ;
    USE SIGNAL ;
    PORT
      LAYER M5 ;
        RECT  92.784 0 92.808 0.084 ;
    END
  END q[447]
  PIN q[448]
    DIRECTION OUTPUT ;
    USE SIGNAL ;
    PORT
      LAYER M5 ;
        RECT  80.592 0 80.616 0.084 ;
    END
  END q[448]
  PIN q[449]
    DIRECTION OUTPUT ;
    USE SIGNAL ;
    PORT
      LAYER M5 ;
        RECT  80.688 0 80.712 0.084 ;
    END
  END q[449]
  PIN q[44]
    DIRECTION OUTPUT ;
    USE SIGNAL ;
    PORT
      LAYER M5 ;
        RECT  62.544 0 62.568 0.084 ;
    END
  END q[44]
  PIN q[450]
    DIRECTION OUTPUT ;
    USE SIGNAL ;
    PORT
      LAYER M5 ;
        RECT  80.784 0 80.808 0.084 ;
    END
  END q[450]
  PIN q[451]
    DIRECTION OUTPUT ;
    USE SIGNAL ;
    PORT
      LAYER M5 ;
        RECT  80.88 0 80.904 0.084 ;
    END
  END q[451]
  PIN q[452]
    DIRECTION OUTPUT ;
    USE SIGNAL ;
    PORT
      LAYER M5 ;
        RECT  80.976 0 81 0.084 ;
    END
  END q[452]
  PIN q[453]
    DIRECTION OUTPUT ;
    USE SIGNAL ;
    PORT
      LAYER M5 ;
        RECT  81.072 0 81.096 0.084 ;
    END
  END q[453]
  PIN q[454]
    DIRECTION OUTPUT ;
    USE SIGNAL ;
    PORT
      LAYER M5 ;
        RECT  81.168 0 81.192 0.084 ;
    END
  END q[454]
  PIN q[455]
    DIRECTION OUTPUT ;
    USE SIGNAL ;
    PORT
      LAYER M5 ;
        RECT  81.264 0 81.288 0.084 ;
    END
  END q[455]
  PIN q[456]
    DIRECTION OUTPUT ;
    USE SIGNAL ;
    PORT
      LAYER M5 ;
        RECT  81.36 0 81.384 0.084 ;
    END
  END q[456]
  PIN q[457]
    DIRECTION OUTPUT ;
    USE SIGNAL ;
    PORT
      LAYER M5 ;
        RECT  81.456 0 81.48 0.084 ;
    END
  END q[457]
  PIN q[458]
    DIRECTION OUTPUT ;
    USE SIGNAL ;
    PORT
      LAYER M5 ;
        RECT  81.552 0 81.576 0.084 ;
    END
  END q[458]
  PIN q[459]
    DIRECTION OUTPUT ;
    USE SIGNAL ;
    PORT
      LAYER M5 ;
        RECT  81.648 0 81.672 0.084 ;
    END
  END q[459]
  PIN q[45]
    DIRECTION OUTPUT ;
    USE SIGNAL ;
    PORT
      LAYER M5 ;
        RECT  62.64 0 62.664 0.084 ;
    END
  END q[45]
  PIN q[460]
    DIRECTION OUTPUT ;
    USE SIGNAL ;
    PORT
      LAYER M5 ;
        RECT  81.744 0 81.768 0.084 ;
    END
  END q[460]
  PIN q[461]
    DIRECTION OUTPUT ;
    USE SIGNAL ;
    PORT
      LAYER M5 ;
        RECT  81.84 0 81.864 0.084 ;
    END
  END q[461]
  PIN q[462]
    DIRECTION OUTPUT ;
    USE SIGNAL ;
    PORT
      LAYER M5 ;
        RECT  81.936 0 81.96 0.084 ;
    END
  END q[462]
  PIN q[463]
    DIRECTION OUTPUT ;
    USE SIGNAL ;
    PORT
      LAYER M5 ;
        RECT  82.032 0 82.056 0.084 ;
    END
  END q[463]
  PIN q[464]
    DIRECTION OUTPUT ;
    USE SIGNAL ;
    PORT
      LAYER M5 ;
        RECT  82.128 0 82.152 0.084 ;
    END
  END q[464]
  PIN q[465]
    DIRECTION OUTPUT ;
    USE SIGNAL ;
    PORT
      LAYER M5 ;
        RECT  82.224 0 82.248 0.084 ;
    END
  END q[465]
  PIN q[466]
    DIRECTION OUTPUT ;
    USE SIGNAL ;
    PORT
      LAYER M5 ;
        RECT  82.32 0 82.344 0.084 ;
    END
  END q[466]
  PIN q[467]
    DIRECTION OUTPUT ;
    USE SIGNAL ;
    PORT
      LAYER M5 ;
        RECT  82.416 0 82.44 0.084 ;
    END
  END q[467]
  PIN q[468]
    DIRECTION OUTPUT ;
    USE SIGNAL ;
    PORT
      LAYER M5 ;
        RECT  82.512 0 82.536 0.084 ;
    END
  END q[468]
  PIN q[469]
    DIRECTION OUTPUT ;
    USE SIGNAL ;
    PORT
      LAYER M5 ;
        RECT  82.608 0 82.632 0.084 ;
    END
  END q[469]
  PIN q[46]
    DIRECTION OUTPUT ;
    USE SIGNAL ;
    PORT
      LAYER M5 ;
        RECT  62.736 0 62.76 0.084 ;
    END
  END q[46]
  PIN q[470]
    DIRECTION OUTPUT ;
    USE SIGNAL ;
    PORT
      LAYER M5 ;
        RECT  82.704 0 82.728 0.084 ;
    END
  END q[470]
  PIN q[471]
    DIRECTION OUTPUT ;
    USE SIGNAL ;
    PORT
      LAYER M5 ;
        RECT  82.8 0 82.824 0.084 ;
    END
  END q[471]
  PIN q[472]
    DIRECTION OUTPUT ;
    USE SIGNAL ;
    PORT
      LAYER M5 ;
        RECT  82.896 0 82.92 0.084 ;
    END
  END q[472]
  PIN q[473]
    DIRECTION OUTPUT ;
    USE SIGNAL ;
    PORT
      LAYER M5 ;
        RECT  82.992 0 83.016 0.084 ;
    END
  END q[473]
  PIN q[474]
    DIRECTION OUTPUT ;
    USE SIGNAL ;
    PORT
      LAYER M5 ;
        RECT  83.088 0 83.112 0.084 ;
    END
  END q[474]
  PIN q[475]
    DIRECTION OUTPUT ;
    USE SIGNAL ;
    PORT
      LAYER M5 ;
        RECT  83.184 0 83.208 0.084 ;
    END
  END q[475]
  PIN q[476]
    DIRECTION OUTPUT ;
    USE SIGNAL ;
    PORT
      LAYER M5 ;
        RECT  83.28 0 83.304 0.084 ;
    END
  END q[476]
  PIN q[477]
    DIRECTION OUTPUT ;
    USE SIGNAL ;
    PORT
      LAYER M5 ;
        RECT  83.376 0 83.4 0.084 ;
    END
  END q[477]
  PIN q[478]
    DIRECTION OUTPUT ;
    USE SIGNAL ;
    PORT
      LAYER M5 ;
        RECT  83.472 0 83.496 0.084 ;
    END
  END q[478]
  PIN q[479]
    DIRECTION OUTPUT ;
    USE SIGNAL ;
    PORT
      LAYER M5 ;
        RECT  83.568 0 83.592 0.084 ;
    END
  END q[479]
  PIN q[47]
    DIRECTION OUTPUT ;
    USE SIGNAL ;
    PORT
      LAYER M5 ;
        RECT  62.832 0 62.856 0.084 ;
    END
  END q[47]
  PIN q[480]
    DIRECTION OUTPUT ;
    USE SIGNAL ;
    PORT
      LAYER M5 ;
        RECT  86.736 0 86.76 0.084 ;
    END
  END q[480]
  PIN q[481]
    DIRECTION OUTPUT ;
    USE SIGNAL ;
    PORT
      LAYER M5 ;
        RECT  86.832 0 86.856 0.084 ;
    END
  END q[481]
  PIN q[482]
    DIRECTION OUTPUT ;
    USE SIGNAL ;
    PORT
      LAYER M5 ;
        RECT  86.928 0 86.952 0.084 ;
    END
  END q[482]
  PIN q[483]
    DIRECTION OUTPUT ;
    USE SIGNAL ;
    PORT
      LAYER M5 ;
        RECT  87.024 0 87.048 0.084 ;
    END
  END q[483]
  PIN q[484]
    DIRECTION OUTPUT ;
    USE SIGNAL ;
    PORT
      LAYER M5 ;
        RECT  87.12 0 87.144 0.084 ;
    END
  END q[484]
  PIN q[485]
    DIRECTION OUTPUT ;
    USE SIGNAL ;
    PORT
      LAYER M5 ;
        RECT  87.216 0 87.24 0.084 ;
    END
  END q[485]
  PIN q[486]
    DIRECTION OUTPUT ;
    USE SIGNAL ;
    PORT
      LAYER M5 ;
        RECT  87.312 0 87.336 0.084 ;
    END
  END q[486]
  PIN q[487]
    DIRECTION OUTPUT ;
    USE SIGNAL ;
    PORT
      LAYER M5 ;
        RECT  87.408 0 87.432 0.084 ;
    END
  END q[487]
  PIN q[488]
    DIRECTION OUTPUT ;
    USE SIGNAL ;
    PORT
      LAYER M5 ;
        RECT  87.504 0 87.528 0.084 ;
    END
  END q[488]
  PIN q[489]
    DIRECTION OUTPUT ;
    USE SIGNAL ;
    PORT
      LAYER M5 ;
        RECT  87.6 0 87.624 0.084 ;
    END
  END q[489]
  PIN q[48]
    DIRECTION OUTPUT ;
    USE SIGNAL ;
    PORT
      LAYER M5 ;
        RECT  62.928 0 62.952 0.084 ;
    END
  END q[48]
  PIN q[490]
    DIRECTION OUTPUT ;
    USE SIGNAL ;
    PORT
      LAYER M5 ;
        RECT  87.696 0 87.72 0.084 ;
    END
  END q[490]
  PIN q[491]
    DIRECTION OUTPUT ;
    USE SIGNAL ;
    PORT
      LAYER M5 ;
        RECT  87.792 0 87.816 0.084 ;
    END
  END q[491]
  PIN q[492]
    DIRECTION OUTPUT ;
    USE SIGNAL ;
    PORT
      LAYER M5 ;
        RECT  87.888 0 87.912 0.084 ;
    END
  END q[492]
  PIN q[493]
    DIRECTION OUTPUT ;
    USE SIGNAL ;
    PORT
      LAYER M5 ;
        RECT  87.984 0 88.008 0.084 ;
    END
  END q[493]
  PIN q[494]
    DIRECTION OUTPUT ;
    USE SIGNAL ;
    PORT
      LAYER M5 ;
        RECT  88.08 0 88.104 0.084 ;
    END
  END q[494]
  PIN q[495]
    DIRECTION OUTPUT ;
    USE SIGNAL ;
    PORT
      LAYER M5 ;
        RECT  88.176 0 88.2 0.084 ;
    END
  END q[495]
  PIN q[496]
    DIRECTION OUTPUT ;
    USE SIGNAL ;
    PORT
      LAYER M5 ;
        RECT  88.272 0 88.296 0.084 ;
    END
  END q[496]
  PIN q[497]
    DIRECTION OUTPUT ;
    USE SIGNAL ;
    PORT
      LAYER M5 ;
        RECT  88.368 0 88.392 0.084 ;
    END
  END q[497]
  PIN q[498]
    DIRECTION OUTPUT ;
    USE SIGNAL ;
    PORT
      LAYER M5 ;
        RECT  88.464 0 88.488 0.084 ;
    END
  END q[498]
  PIN q[499]
    DIRECTION OUTPUT ;
    USE SIGNAL ;
    PORT
      LAYER M5 ;
        RECT  88.56 0 88.584 0.084 ;
    END
  END q[499]
  PIN q[49]
    DIRECTION OUTPUT ;
    USE SIGNAL ;
    PORT
      LAYER M5 ;
        RECT  63.024 0 63.048 0.084 ;
    END
  END q[49]
  PIN q[4]
    DIRECTION OUTPUT ;
    USE SIGNAL ;
    PORT
      LAYER M5 ;
        RECT  67.92 0 67.944 0.084 ;
    END
  END q[4]
  PIN q[500]
    DIRECTION OUTPUT ;
    USE SIGNAL ;
    PORT
      LAYER M5 ;
        RECT  88.656 0 88.68 0.084 ;
    END
  END q[500]
  PIN q[501]
    DIRECTION OUTPUT ;
    USE SIGNAL ;
    PORT
      LAYER M5 ;
        RECT  88.752 0 88.776 0.084 ;
    END
  END q[501]
  PIN q[502]
    DIRECTION OUTPUT ;
    USE SIGNAL ;
    PORT
      LAYER M5 ;
        RECT  88.848 0 88.872 0.084 ;
    END
  END q[502]
  PIN q[503]
    DIRECTION OUTPUT ;
    USE SIGNAL ;
    PORT
      LAYER M5 ;
        RECT  88.944 0 88.968 0.084 ;
    END
  END q[503]
  PIN q[504]
    DIRECTION OUTPUT ;
    USE SIGNAL ;
    PORT
      LAYER M5 ;
        RECT  89.04 0 89.064 0.084 ;
    END
  END q[504]
  PIN q[505]
    DIRECTION OUTPUT ;
    USE SIGNAL ;
    PORT
      LAYER M5 ;
        RECT  89.136 0 89.16 0.084 ;
    END
  END q[505]
  PIN q[506]
    DIRECTION OUTPUT ;
    USE SIGNAL ;
    PORT
      LAYER M5 ;
        RECT  89.232 0 89.256 0.084 ;
    END
  END q[506]
  PIN q[507]
    DIRECTION OUTPUT ;
    USE SIGNAL ;
    PORT
      LAYER M5 ;
        RECT  89.328 0 89.352 0.084 ;
    END
  END q[507]
  PIN q[508]
    DIRECTION OUTPUT ;
    USE SIGNAL ;
    PORT
      LAYER M5 ;
        RECT  89.424 0 89.448 0.084 ;
    END
  END q[508]
  PIN q[509]
    DIRECTION OUTPUT ;
    USE SIGNAL ;
    PORT
      LAYER M5 ;
        RECT  89.52 0 89.544 0.084 ;
    END
  END q[509]
  PIN q[50]
    DIRECTION OUTPUT ;
    USE SIGNAL ;
    PORT
      LAYER M5 ;
        RECT  63.12 0 63.144 0.084 ;
    END
  END q[50]
  PIN q[510]
    DIRECTION OUTPUT ;
    USE SIGNAL ;
    PORT
      LAYER M5 ;
        RECT  89.616 0 89.64 0.084 ;
    END
  END q[510]
  PIN q[511]
    DIRECTION OUTPUT ;
    USE SIGNAL ;
    PORT
      LAYER M5 ;
        RECT  89.712 0 89.736 0.084 ;
    END
  END q[511]
  PIN q[512]
    DIRECTION OUTPUT ;
    USE SIGNAL ;
    PORT
      LAYER M5 ;
        RECT  26.064 0 26.088 0.084 ;
    END
  END q[512]
  PIN q[513]
    DIRECTION OUTPUT ;
    USE SIGNAL ;
    PORT
      LAYER M5 ;
        RECT  26.16 0 26.184 0.084 ;
    END
  END q[513]
  PIN q[514]
    DIRECTION OUTPUT ;
    USE SIGNAL ;
    PORT
      LAYER M5 ;
        RECT  26.256 0 26.28 0.084 ;
    END
  END q[514]
  PIN q[515]
    DIRECTION OUTPUT ;
    USE SIGNAL ;
    PORT
      LAYER M5 ;
        RECT  26.352 0 26.376 0.084 ;
    END
  END q[515]
  PIN q[516]
    DIRECTION OUTPUT ;
    USE SIGNAL ;
    PORT
      LAYER M5 ;
        RECT  26.448 0 26.472 0.084 ;
    END
  END q[516]
  PIN q[517]
    DIRECTION OUTPUT ;
    USE SIGNAL ;
    PORT
      LAYER M5 ;
        RECT  26.544 0 26.568 0.084 ;
    END
  END q[517]
  PIN q[518]
    DIRECTION OUTPUT ;
    USE SIGNAL ;
    PORT
      LAYER M5 ;
        RECT  26.64 0 26.664 0.084 ;
    END
  END q[518]
  PIN q[519]
    DIRECTION OUTPUT ;
    USE SIGNAL ;
    PORT
      LAYER M5 ;
        RECT  26.736 0 26.76 0.084 ;
    END
  END q[519]
  PIN q[51]
    DIRECTION OUTPUT ;
    USE SIGNAL ;
    PORT
      LAYER M5 ;
        RECT  63.216 0 63.24 0.084 ;
    END
  END q[51]
  PIN q[520]
    DIRECTION OUTPUT ;
    USE SIGNAL ;
    PORT
      LAYER M5 ;
        RECT  26.832 0 26.856 0.084 ;
    END
  END q[520]
  PIN q[521]
    DIRECTION OUTPUT ;
    USE SIGNAL ;
    PORT
      LAYER M5 ;
        RECT  26.928 0 26.952 0.084 ;
    END
  END q[521]
  PIN q[522]
    DIRECTION OUTPUT ;
    USE SIGNAL ;
    PORT
      LAYER M5 ;
        RECT  27.024 0 27.048 0.084 ;
    END
  END q[522]
  PIN q[523]
    DIRECTION OUTPUT ;
    USE SIGNAL ;
    PORT
      LAYER M5 ;
        RECT  27.12 0 27.144 0.084 ;
    END
  END q[523]
  PIN q[524]
    DIRECTION OUTPUT ;
    USE SIGNAL ;
    PORT
      LAYER M5 ;
        RECT  27.216 0 27.24 0.084 ;
    END
  END q[524]
  PIN q[525]
    DIRECTION OUTPUT ;
    USE SIGNAL ;
    PORT
      LAYER M5 ;
        RECT  27.312 0 27.336 0.084 ;
    END
  END q[525]
  PIN q[526]
    DIRECTION OUTPUT ;
    USE SIGNAL ;
    PORT
      LAYER M5 ;
        RECT  27.408 0 27.432 0.084 ;
    END
  END q[526]
  PIN q[527]
    DIRECTION OUTPUT ;
    USE SIGNAL ;
    PORT
      LAYER M5 ;
        RECT  27.504 0 27.528 0.084 ;
    END
  END q[527]
  PIN q[528]
    DIRECTION OUTPUT ;
    USE SIGNAL ;
    PORT
      LAYER M5 ;
        RECT  27.6 0 27.624 0.084 ;
    END
  END q[528]
  PIN q[529]
    DIRECTION OUTPUT ;
    USE SIGNAL ;
    PORT
      LAYER M5 ;
        RECT  27.696 0 27.72 0.084 ;
    END
  END q[529]
  PIN q[52]
    DIRECTION OUTPUT ;
    USE SIGNAL ;
    PORT
      LAYER M5 ;
        RECT  63.312 0 63.336 0.084 ;
    END
  END q[52]
  PIN q[530]
    DIRECTION OUTPUT ;
    USE SIGNAL ;
    PORT
      LAYER M5 ;
        RECT  27.792 0 27.816 0.084 ;
    END
  END q[530]
  PIN q[531]
    DIRECTION OUTPUT ;
    USE SIGNAL ;
    PORT
      LAYER M5 ;
        RECT  27.888 0 27.912 0.084 ;
    END
  END q[531]
  PIN q[532]
    DIRECTION OUTPUT ;
    USE SIGNAL ;
    PORT
      LAYER M5 ;
        RECT  27.984 0 28.008 0.084 ;
    END
  END q[532]
  PIN q[533]
    DIRECTION OUTPUT ;
    USE SIGNAL ;
    PORT
      LAYER M5 ;
        RECT  28.08 0 28.104 0.084 ;
    END
  END q[533]
  PIN q[534]
    DIRECTION OUTPUT ;
    USE SIGNAL ;
    PORT
      LAYER M5 ;
        RECT  28.176 0 28.2 0.084 ;
    END
  END q[534]
  PIN q[535]
    DIRECTION OUTPUT ;
    USE SIGNAL ;
    PORT
      LAYER M5 ;
        RECT  28.272 0 28.296 0.084 ;
    END
  END q[535]
  PIN q[536]
    DIRECTION OUTPUT ;
    USE SIGNAL ;
    PORT
      LAYER M5 ;
        RECT  28.368 0 28.392 0.084 ;
    END
  END q[536]
  PIN q[537]
    DIRECTION OUTPUT ;
    USE SIGNAL ;
    PORT
      LAYER M5 ;
        RECT  28.464 0 28.488 0.084 ;
    END
  END q[537]
  PIN q[538]
    DIRECTION OUTPUT ;
    USE SIGNAL ;
    PORT
      LAYER M5 ;
        RECT  28.56 0 28.584 0.084 ;
    END
  END q[538]
  PIN q[539]
    DIRECTION OUTPUT ;
    USE SIGNAL ;
    PORT
      LAYER M5 ;
        RECT  28.656 0 28.68 0.084 ;
    END
  END q[539]
  PIN q[53]
    DIRECTION OUTPUT ;
    USE SIGNAL ;
    PORT
      LAYER M5 ;
        RECT  63.408 0 63.432 0.084 ;
    END
  END q[53]
  PIN q[540]
    DIRECTION OUTPUT ;
    USE SIGNAL ;
    PORT
      LAYER M5 ;
        RECT  28.752 0 28.776 0.084 ;
    END
  END q[540]
  PIN q[541]
    DIRECTION OUTPUT ;
    USE SIGNAL ;
    PORT
      LAYER M5 ;
        RECT  28.848 0 28.872 0.084 ;
    END
  END q[541]
  PIN q[542]
    DIRECTION OUTPUT ;
    USE SIGNAL ;
    PORT
      LAYER M5 ;
        RECT  28.944 0 28.968 0.084 ;
    END
  END q[542]
  PIN q[543]
    DIRECTION OUTPUT ;
    USE SIGNAL ;
    PORT
      LAYER M5 ;
        RECT  29.04 0 29.064 0.084 ;
    END
  END q[543]
  PIN q[544]
    DIRECTION OUTPUT ;
    USE SIGNAL ;
    PORT
      LAYER M5 ;
        RECT  29.136 0 29.16 0.084 ;
    END
  END q[544]
  PIN q[545]
    DIRECTION OUTPUT ;
    USE SIGNAL ;
    PORT
      LAYER M5 ;
        RECT  29.232 0 29.256 0.084 ;
    END
  END q[545]
  PIN q[546]
    DIRECTION OUTPUT ;
    USE SIGNAL ;
    PORT
      LAYER M5 ;
        RECT  29.328 0 29.352 0.084 ;
    END
  END q[546]
  PIN q[547]
    DIRECTION OUTPUT ;
    USE SIGNAL ;
    PORT
      LAYER M5 ;
        RECT  29.424 0 29.448 0.084 ;
    END
  END q[547]
  PIN q[548]
    DIRECTION OUTPUT ;
    USE SIGNAL ;
    PORT
      LAYER M5 ;
        RECT  29.52 0 29.544 0.084 ;
    END
  END q[548]
  PIN q[549]
    DIRECTION OUTPUT ;
    USE SIGNAL ;
    PORT
      LAYER M5 ;
        RECT  29.616 0 29.64 0.084 ;
    END
  END q[549]
  PIN q[54]
    DIRECTION OUTPUT ;
    USE SIGNAL ;
    PORT
      LAYER M5 ;
        RECT  63.504 0 63.528 0.084 ;
    END
  END q[54]
  PIN q[550]
    DIRECTION OUTPUT ;
    USE SIGNAL ;
    PORT
      LAYER M5 ;
        RECT  29.712 0 29.736 0.084 ;
    END
  END q[550]
  PIN q[551]
    DIRECTION OUTPUT ;
    USE SIGNAL ;
    PORT
      LAYER M5 ;
        RECT  29.808 0 29.832 0.084 ;
    END
  END q[551]
  PIN q[552]
    DIRECTION OUTPUT ;
    USE SIGNAL ;
    PORT
      LAYER M5 ;
        RECT  29.904 0 29.928 0.084 ;
    END
  END q[552]
  PIN q[553]
    DIRECTION OUTPUT ;
    USE SIGNAL ;
    PORT
      LAYER M5 ;
        RECT  30 0 30.024 0.084 ;
    END
  END q[553]
  PIN q[554]
    DIRECTION OUTPUT ;
    USE SIGNAL ;
    PORT
      LAYER M5 ;
        RECT  30.096 0 30.12 0.084 ;
    END
  END q[554]
  PIN q[555]
    DIRECTION OUTPUT ;
    USE SIGNAL ;
    PORT
      LAYER M5 ;
        RECT  30.192 0 30.216 0.084 ;
    END
  END q[555]
  PIN q[556]
    DIRECTION OUTPUT ;
    USE SIGNAL ;
    PORT
      LAYER M5 ;
        RECT  30.288 0 30.312 0.084 ;
    END
  END q[556]
  PIN q[557]
    DIRECTION OUTPUT ;
    USE SIGNAL ;
    PORT
      LAYER M5 ;
        RECT  30.384 0 30.408 0.084 ;
    END
  END q[557]
  PIN q[558]
    DIRECTION OUTPUT ;
    USE SIGNAL ;
    PORT
      LAYER M5 ;
        RECT  30.48 0 30.504 0.084 ;
    END
  END q[558]
  PIN q[559]
    DIRECTION OUTPUT ;
    USE SIGNAL ;
    PORT
      LAYER M5 ;
        RECT  30.576 0 30.6 0.084 ;
    END
  END q[559]
  PIN q[55]
    DIRECTION OUTPUT ;
    USE SIGNAL ;
    PORT
      LAYER M5 ;
        RECT  63.6 0 63.624 0.084 ;
    END
  END q[55]
  PIN q[560]
    DIRECTION OUTPUT ;
    USE SIGNAL ;
    PORT
      LAYER M5 ;
        RECT  30.672 0 30.696 0.084 ;
    END
  END q[560]
  PIN q[561]
    DIRECTION OUTPUT ;
    USE SIGNAL ;
    PORT
      LAYER M5 ;
        RECT  30.768 0 30.792 0.084 ;
    END
  END q[561]
  PIN q[562]
    DIRECTION OUTPUT ;
    USE SIGNAL ;
    PORT
      LAYER M5 ;
        RECT  30.864 0 30.888 0.084 ;
    END
  END q[562]
  PIN q[563]
    DIRECTION OUTPUT ;
    USE SIGNAL ;
    PORT
      LAYER M5 ;
        RECT  30.96 0 30.984 0.084 ;
    END
  END q[563]
  PIN q[564]
    DIRECTION OUTPUT ;
    USE SIGNAL ;
    PORT
      LAYER M5 ;
        RECT  31.056 0 31.08 0.084 ;
    END
  END q[564]
  PIN q[565]
    DIRECTION OUTPUT ;
    USE SIGNAL ;
    PORT
      LAYER M5 ;
        RECT  31.152 0 31.176 0.084 ;
    END
  END q[565]
  PIN q[566]
    DIRECTION OUTPUT ;
    USE SIGNAL ;
    PORT
      LAYER M5 ;
        RECT  31.248 0 31.272 0.084 ;
    END
  END q[566]
  PIN q[567]
    DIRECTION OUTPUT ;
    USE SIGNAL ;
    PORT
      LAYER M5 ;
        RECT  31.344 0 31.368 0.084 ;
    END
  END q[567]
  PIN q[568]
    DIRECTION OUTPUT ;
    USE SIGNAL ;
    PORT
      LAYER M5 ;
        RECT  31.44 0 31.464 0.084 ;
    END
  END q[568]
  PIN q[569]
    DIRECTION OUTPUT ;
    USE SIGNAL ;
    PORT
      LAYER M5 ;
        RECT  31.536 0 31.56 0.084 ;
    END
  END q[569]
  PIN q[56]
    DIRECTION OUTPUT ;
    USE SIGNAL ;
    PORT
      LAYER M5 ;
        RECT  63.696 0 63.72 0.084 ;
    END
  END q[56]
  PIN q[570]
    DIRECTION OUTPUT ;
    USE SIGNAL ;
    PORT
      LAYER M5 ;
        RECT  31.632 0 31.656 0.084 ;
    END
  END q[570]
  PIN q[571]
    DIRECTION OUTPUT ;
    USE SIGNAL ;
    PORT
      LAYER M5 ;
        RECT  31.728 0 31.752 0.084 ;
    END
  END q[571]
  PIN q[572]
    DIRECTION OUTPUT ;
    USE SIGNAL ;
    PORT
      LAYER M5 ;
        RECT  31.824 0 31.848 0.084 ;
    END
  END q[572]
  PIN q[573]
    DIRECTION OUTPUT ;
    USE SIGNAL ;
    PORT
      LAYER M5 ;
        RECT  31.92 0 31.944 0.084 ;
    END
  END q[573]
  PIN q[574]
    DIRECTION OUTPUT ;
    USE SIGNAL ;
    PORT
      LAYER M5 ;
        RECT  32.016 0 32.04 0.084 ;
    END
  END q[574]
  PIN q[575]
    DIRECTION OUTPUT ;
    USE SIGNAL ;
    PORT
      LAYER M5 ;
        RECT  32.112 0 32.136 0.084 ;
    END
  END q[575]
  PIN q[576]
    DIRECTION OUTPUT ;
    USE SIGNAL ;
    PORT
      LAYER M5 ;
        RECT  83.664 0 83.688 0.084 ;
    END
  END q[576]
  PIN q[577]
    DIRECTION OUTPUT ;
    USE SIGNAL ;
    PORT
      LAYER M5 ;
        RECT  83.76 0 83.784 0.084 ;
    END
  END q[577]
  PIN q[578]
    DIRECTION OUTPUT ;
    USE SIGNAL ;
    PORT
      LAYER M5 ;
        RECT  83.856 0 83.88 0.084 ;
    END
  END q[578]
  PIN q[579]
    DIRECTION OUTPUT ;
    USE SIGNAL ;
    PORT
      LAYER M5 ;
        RECT  83.952 0 83.976 0.084 ;
    END
  END q[579]
  PIN q[57]
    DIRECTION OUTPUT ;
    USE SIGNAL ;
    PORT
      LAYER M5 ;
        RECT  63.792 0 63.816 0.084 ;
    END
  END q[57]
  PIN q[580]
    DIRECTION OUTPUT ;
    USE SIGNAL ;
    PORT
      LAYER M5 ;
        RECT  84.048 0 84.072 0.084 ;
    END
  END q[580]
  PIN q[581]
    DIRECTION OUTPUT ;
    USE SIGNAL ;
    PORT
      LAYER M5 ;
        RECT  84.144 0 84.168 0.084 ;
    END
  END q[581]
  PIN q[582]
    DIRECTION OUTPUT ;
    USE SIGNAL ;
    PORT
      LAYER M5 ;
        RECT  84.24 0 84.264 0.084 ;
    END
  END q[582]
  PIN q[583]
    DIRECTION OUTPUT ;
    USE SIGNAL ;
    PORT
      LAYER M5 ;
        RECT  84.336 0 84.36 0.084 ;
    END
  END q[583]
  PIN q[584]
    DIRECTION OUTPUT ;
    USE SIGNAL ;
    PORT
      LAYER M5 ;
        RECT  84.432 0 84.456 0.084 ;
    END
  END q[584]
  PIN q[585]
    DIRECTION OUTPUT ;
    USE SIGNAL ;
    PORT
      LAYER M5 ;
        RECT  84.528 0 84.552 0.084 ;
    END
  END q[585]
  PIN q[586]
    DIRECTION OUTPUT ;
    USE SIGNAL ;
    PORT
      LAYER M5 ;
        RECT  84.624 0 84.648 0.084 ;
    END
  END q[586]
  PIN q[587]
    DIRECTION OUTPUT ;
    USE SIGNAL ;
    PORT
      LAYER M5 ;
        RECT  84.72 0 84.744 0.084 ;
    END
  END q[587]
  PIN q[588]
    DIRECTION OUTPUT ;
    USE SIGNAL ;
    PORT
      LAYER M5 ;
        RECT  84.816 0 84.84 0.084 ;
    END
  END q[588]
  PIN q[589]
    DIRECTION OUTPUT ;
    USE SIGNAL ;
    PORT
      LAYER M5 ;
        RECT  84.912 0 84.936 0.084 ;
    END
  END q[589]
  PIN q[58]
    DIRECTION OUTPUT ;
    USE SIGNAL ;
    PORT
      LAYER M5 ;
        RECT  63.888 0 63.912 0.084 ;
    END
  END q[58]
  PIN q[590]
    DIRECTION OUTPUT ;
    USE SIGNAL ;
    PORT
      LAYER M5 ;
        RECT  85.008 0 85.032 0.084 ;
    END
  END q[590]
  PIN q[591]
    DIRECTION OUTPUT ;
    USE SIGNAL ;
    PORT
      LAYER M5 ;
        RECT  85.104 0 85.128 0.084 ;
    END
  END q[591]
  PIN q[592]
    DIRECTION OUTPUT ;
    USE SIGNAL ;
    PORT
      LAYER M5 ;
        RECT  85.2 0 85.224 0.084 ;
    END
  END q[592]
  PIN q[593]
    DIRECTION OUTPUT ;
    USE SIGNAL ;
    PORT
      LAYER M5 ;
        RECT  85.296 0 85.32 0.084 ;
    END
  END q[593]
  PIN q[594]
    DIRECTION OUTPUT ;
    USE SIGNAL ;
    PORT
      LAYER M5 ;
        RECT  85.392 0 85.416 0.084 ;
    END
  END q[594]
  PIN q[595]
    DIRECTION OUTPUT ;
    USE SIGNAL ;
    PORT
      LAYER M5 ;
        RECT  85.488 0 85.512 0.084 ;
    END
  END q[595]
  PIN q[596]
    DIRECTION OUTPUT ;
    USE SIGNAL ;
    PORT
      LAYER M5 ;
        RECT  85.584 0 85.608 0.084 ;
    END
  END q[596]
  PIN q[597]
    DIRECTION OUTPUT ;
    USE SIGNAL ;
    PORT
      LAYER M5 ;
        RECT  85.68 0 85.704 0.084 ;
    END
  END q[597]
  PIN q[598]
    DIRECTION OUTPUT ;
    USE SIGNAL ;
    PORT
      LAYER M5 ;
        RECT  85.776 0 85.8 0.084 ;
    END
  END q[598]
  PIN q[599]
    DIRECTION OUTPUT ;
    USE SIGNAL ;
    PORT
      LAYER M5 ;
        RECT  85.872 0 85.896 0.084 ;
    END
  END q[599]
  PIN q[59]
    DIRECTION OUTPUT ;
    USE SIGNAL ;
    PORT
      LAYER M5 ;
        RECT  63.984 0 64.008 0.084 ;
    END
  END q[59]
  PIN q[5]
    DIRECTION OUTPUT ;
    USE SIGNAL ;
    PORT
      LAYER M5 ;
        RECT  68.016 0 68.04 0.084 ;
    END
  END q[5]
  PIN q[600]
    DIRECTION OUTPUT ;
    USE SIGNAL ;
    PORT
      LAYER M5 ;
        RECT  85.968 0 85.992 0.084 ;
    END
  END q[600]
  PIN q[601]
    DIRECTION OUTPUT ;
    USE SIGNAL ;
    PORT
      LAYER M5 ;
        RECT  86.064 0 86.088 0.084 ;
    END
  END q[601]
  PIN q[602]
    DIRECTION OUTPUT ;
    USE SIGNAL ;
    PORT
      LAYER M5 ;
        RECT  86.16 0 86.184 0.084 ;
    END
  END q[602]
  PIN q[603]
    DIRECTION OUTPUT ;
    USE SIGNAL ;
    PORT
      LAYER M5 ;
        RECT  86.256 0 86.28 0.084 ;
    END
  END q[603]
  PIN q[604]
    DIRECTION OUTPUT ;
    USE SIGNAL ;
    PORT
      LAYER M5 ;
        RECT  86.352 0 86.376 0.084 ;
    END
  END q[604]
  PIN q[605]
    DIRECTION OUTPUT ;
    USE SIGNAL ;
    PORT
      LAYER M5 ;
        RECT  86.448 0 86.472 0.084 ;
    END
  END q[605]
  PIN q[606]
    DIRECTION OUTPUT ;
    USE SIGNAL ;
    PORT
      LAYER M5 ;
        RECT  86.544 0 86.568 0.084 ;
    END
  END q[606]
  PIN q[607]
    DIRECTION OUTPUT ;
    USE SIGNAL ;
    PORT
      LAYER M5 ;
        RECT  86.64 0 86.664 0.084 ;
    END
  END q[607]
  PIN q[608]
    DIRECTION OUTPUT ;
    USE SIGNAL ;
    PORT
      LAYER M5 ;
        RECT  19.92 0 19.944 0.084 ;
    END
  END q[608]
  PIN q[609]
    DIRECTION OUTPUT ;
    USE SIGNAL ;
    PORT
      LAYER M5 ;
        RECT  20.016 0 20.04 0.084 ;
    END
  END q[609]
  PIN q[60]
    DIRECTION OUTPUT ;
    USE SIGNAL ;
    PORT
      LAYER M5 ;
        RECT  64.08 0 64.104 0.084 ;
    END
  END q[60]
  PIN q[610]
    DIRECTION OUTPUT ;
    USE SIGNAL ;
    PORT
      LAYER M5 ;
        RECT  20.112 0 20.136 0.084 ;
    END
  END q[610]
  PIN q[611]
    DIRECTION OUTPUT ;
    USE SIGNAL ;
    PORT
      LAYER M5 ;
        RECT  20.208 0 20.232 0.084 ;
    END
  END q[611]
  PIN q[612]
    DIRECTION OUTPUT ;
    USE SIGNAL ;
    PORT
      LAYER M5 ;
        RECT  20.304 0 20.328 0.084 ;
    END
  END q[612]
  PIN q[613]
    DIRECTION OUTPUT ;
    USE SIGNAL ;
    PORT
      LAYER M5 ;
        RECT  20.4 0 20.424 0.084 ;
    END
  END q[613]
  PIN q[614]
    DIRECTION OUTPUT ;
    USE SIGNAL ;
    PORT
      LAYER M5 ;
        RECT  20.496 0 20.52 0.084 ;
    END
  END q[614]
  PIN q[615]
    DIRECTION OUTPUT ;
    USE SIGNAL ;
    PORT
      LAYER M5 ;
        RECT  20.592 0 20.616 0.084 ;
    END
  END q[615]
  PIN q[616]
    DIRECTION OUTPUT ;
    USE SIGNAL ;
    PORT
      LAYER M5 ;
        RECT  20.688 0 20.712 0.084 ;
    END
  END q[616]
  PIN q[617]
    DIRECTION OUTPUT ;
    USE SIGNAL ;
    PORT
      LAYER M5 ;
        RECT  20.784 0 20.808 0.084 ;
    END
  END q[617]
  PIN q[618]
    DIRECTION OUTPUT ;
    USE SIGNAL ;
    PORT
      LAYER M5 ;
        RECT  20.88 0 20.904 0.084 ;
    END
  END q[618]
  PIN q[619]
    DIRECTION OUTPUT ;
    USE SIGNAL ;
    PORT
      LAYER M5 ;
        RECT  20.976 0 21 0.084 ;
    END
  END q[619]
  PIN q[61]
    DIRECTION OUTPUT ;
    USE SIGNAL ;
    PORT
      LAYER M5 ;
        RECT  64.176 0 64.2 0.084 ;
    END
  END q[61]
  PIN q[620]
    DIRECTION OUTPUT ;
    USE SIGNAL ;
    PORT
      LAYER M5 ;
        RECT  21.072 0 21.096 0.084 ;
    END
  END q[620]
  PIN q[621]
    DIRECTION OUTPUT ;
    USE SIGNAL ;
    PORT
      LAYER M5 ;
        RECT  21.168 0 21.192 0.084 ;
    END
  END q[621]
  PIN q[622]
    DIRECTION OUTPUT ;
    USE SIGNAL ;
    PORT
      LAYER M5 ;
        RECT  21.264 0 21.288 0.084 ;
    END
  END q[622]
  PIN q[623]
    DIRECTION OUTPUT ;
    USE SIGNAL ;
    PORT
      LAYER M5 ;
        RECT  21.36 0 21.384 0.084 ;
    END
  END q[623]
  PIN q[624]
    DIRECTION OUTPUT ;
    USE SIGNAL ;
    PORT
      LAYER M5 ;
        RECT  21.456 0 21.48 0.084 ;
    END
  END q[624]
  PIN q[625]
    DIRECTION OUTPUT ;
    USE SIGNAL ;
    PORT
      LAYER M5 ;
        RECT  21.552 0 21.576 0.084 ;
    END
  END q[625]
  PIN q[626]
    DIRECTION OUTPUT ;
    USE SIGNAL ;
    PORT
      LAYER M5 ;
        RECT  21.648 0 21.672 0.084 ;
    END
  END q[626]
  PIN q[627]
    DIRECTION OUTPUT ;
    USE SIGNAL ;
    PORT
      LAYER M5 ;
        RECT  21.744 0 21.768 0.084 ;
    END
  END q[627]
  PIN q[628]
    DIRECTION OUTPUT ;
    USE SIGNAL ;
    PORT
      LAYER M5 ;
        RECT  21.84 0 21.864 0.084 ;
    END
  END q[628]
  PIN q[629]
    DIRECTION OUTPUT ;
    USE SIGNAL ;
    PORT
      LAYER M5 ;
        RECT  21.936 0 21.96 0.084 ;
    END
  END q[629]
  PIN q[62]
    DIRECTION OUTPUT ;
    USE SIGNAL ;
    PORT
      LAYER M5 ;
        RECT  64.272 0 64.296 0.084 ;
    END
  END q[62]
  PIN q[630]
    DIRECTION OUTPUT ;
    USE SIGNAL ;
    PORT
      LAYER M5 ;
        RECT  22.032 0 22.056 0.084 ;
    END
  END q[630]
  PIN q[631]
    DIRECTION OUTPUT ;
    USE SIGNAL ;
    PORT
      LAYER M5 ;
        RECT  22.128 0 22.152 0.084 ;
    END
  END q[631]
  PIN q[632]
    DIRECTION OUTPUT ;
    USE SIGNAL ;
    PORT
      LAYER M5 ;
        RECT  22.224 0 22.248 0.084 ;
    END
  END q[632]
  PIN q[633]
    DIRECTION OUTPUT ;
    USE SIGNAL ;
    PORT
      LAYER M5 ;
        RECT  22.32 0 22.344 0.084 ;
    END
  END q[633]
  PIN q[634]
    DIRECTION OUTPUT ;
    USE SIGNAL ;
    PORT
      LAYER M5 ;
        RECT  22.416 0 22.44 0.084 ;
    END
  END q[634]
  PIN q[635]
    DIRECTION OUTPUT ;
    USE SIGNAL ;
    PORT
      LAYER M5 ;
        RECT  22.512 0 22.536 0.084 ;
    END
  END q[635]
  PIN q[636]
    DIRECTION OUTPUT ;
    USE SIGNAL ;
    PORT
      LAYER M5 ;
        RECT  22.608 0 22.632 0.084 ;
    END
  END q[636]
  PIN q[637]
    DIRECTION OUTPUT ;
    USE SIGNAL ;
    PORT
      LAYER M5 ;
        RECT  22.704 0 22.728 0.084 ;
    END
  END q[637]
  PIN q[638]
    DIRECTION OUTPUT ;
    USE SIGNAL ;
    PORT
      LAYER M5 ;
        RECT  22.8 0 22.824 0.084 ;
    END
  END q[638]
  PIN q[639]
    DIRECTION OUTPUT ;
    USE SIGNAL ;
    PORT
      LAYER M5 ;
        RECT  22.896 0 22.92 0.084 ;
    END
  END q[639]
  PIN q[63]
    DIRECTION OUTPUT ;
    USE SIGNAL ;
    PORT
      LAYER M5 ;
        RECT  64.368 0 64.392 0.084 ;
    END
  END q[63]
  PIN q[640]
    DIRECTION OUTPUT ;
    USE SIGNAL ;
    PORT
      LAYER M5 ;
        RECT  32.208 0 32.232 0.084 ;
    END
  END q[640]
  PIN q[641]
    DIRECTION OUTPUT ;
    USE SIGNAL ;
    PORT
      LAYER M5 ;
        RECT  32.304 0 32.328 0.084 ;
    END
  END q[641]
  PIN q[642]
    DIRECTION OUTPUT ;
    USE SIGNAL ;
    PORT
      LAYER M5 ;
        RECT  32.4 0 32.424 0.084 ;
    END
  END q[642]
  PIN q[643]
    DIRECTION OUTPUT ;
    USE SIGNAL ;
    PORT
      LAYER M5 ;
        RECT  32.496 0 32.52 0.084 ;
    END
  END q[643]
  PIN q[644]
    DIRECTION OUTPUT ;
    USE SIGNAL ;
    PORT
      LAYER M5 ;
        RECT  32.592 0 32.616 0.084 ;
    END
  END q[644]
  PIN q[645]
    DIRECTION OUTPUT ;
    USE SIGNAL ;
    PORT
      LAYER M5 ;
        RECT  32.688 0 32.712 0.084 ;
    END
  END q[645]
  PIN q[646]
    DIRECTION OUTPUT ;
    USE SIGNAL ;
    PORT
      LAYER M5 ;
        RECT  32.784 0 32.808 0.084 ;
    END
  END q[646]
  PIN q[647]
    DIRECTION OUTPUT ;
    USE SIGNAL ;
    PORT
      LAYER M5 ;
        RECT  32.88 0 32.904 0.084 ;
    END
  END q[647]
  PIN q[648]
    DIRECTION OUTPUT ;
    USE SIGNAL ;
    PORT
      LAYER M5 ;
        RECT  32.976 0 33 0.084 ;
    END
  END q[648]
  PIN q[649]
    DIRECTION OUTPUT ;
    USE SIGNAL ;
    PORT
      LAYER M5 ;
        RECT  33.072 0 33.096 0.084 ;
    END
  END q[649]
  PIN q[64]
    DIRECTION OUTPUT ;
    USE SIGNAL ;
    PORT
      LAYER M5 ;
        RECT  45.264 0 45.288 0.084 ;
    END
  END q[64]
  PIN q[650]
    DIRECTION OUTPUT ;
    USE SIGNAL ;
    PORT
      LAYER M5 ;
        RECT  33.168 0 33.192 0.084 ;
    END
  END q[650]
  PIN q[651]
    DIRECTION OUTPUT ;
    USE SIGNAL ;
    PORT
      LAYER M5 ;
        RECT  33.264 0 33.288 0.084 ;
    END
  END q[651]
  PIN q[652]
    DIRECTION OUTPUT ;
    USE SIGNAL ;
    PORT
      LAYER M5 ;
        RECT  33.36 0 33.384 0.084 ;
    END
  END q[652]
  PIN q[653]
    DIRECTION OUTPUT ;
    USE SIGNAL ;
    PORT
      LAYER M5 ;
        RECT  33.456 0 33.48 0.084 ;
    END
  END q[653]
  PIN q[654]
    DIRECTION OUTPUT ;
    USE SIGNAL ;
    PORT
      LAYER M5 ;
        RECT  33.552 0 33.576 0.084 ;
    END
  END q[654]
  PIN q[655]
    DIRECTION OUTPUT ;
    USE SIGNAL ;
    PORT
      LAYER M5 ;
        RECT  33.648 0 33.672 0.084 ;
    END
  END q[655]
  PIN q[656]
    DIRECTION OUTPUT ;
    USE SIGNAL ;
    PORT
      LAYER M5 ;
        RECT  33.744 0 33.768 0.084 ;
    END
  END q[656]
  PIN q[657]
    DIRECTION OUTPUT ;
    USE SIGNAL ;
    PORT
      LAYER M5 ;
        RECT  33.84 0 33.864 0.084 ;
    END
  END q[657]
  PIN q[658]
    DIRECTION OUTPUT ;
    USE SIGNAL ;
    PORT
      LAYER M5 ;
        RECT  33.936 0 33.96 0.084 ;
    END
  END q[658]
  PIN q[659]
    DIRECTION OUTPUT ;
    USE SIGNAL ;
    PORT
      LAYER M5 ;
        RECT  34.032 0 34.056 0.084 ;
    END
  END q[659]
  PIN q[65]
    DIRECTION OUTPUT ;
    USE SIGNAL ;
    PORT
      LAYER M5 ;
        RECT  45.36 0 45.384 0.084 ;
    END
  END q[65]
  PIN q[660]
    DIRECTION OUTPUT ;
    USE SIGNAL ;
    PORT
      LAYER M5 ;
        RECT  34.128 0 34.152 0.084 ;
    END
  END q[660]
  PIN q[661]
    DIRECTION OUTPUT ;
    USE SIGNAL ;
    PORT
      LAYER M5 ;
        RECT  34.224 0 34.248 0.084 ;
    END
  END q[661]
  PIN q[662]
    DIRECTION OUTPUT ;
    USE SIGNAL ;
    PORT
      LAYER M5 ;
        RECT  34.32 0 34.344 0.084 ;
    END
  END q[662]
  PIN q[663]
    DIRECTION OUTPUT ;
    USE SIGNAL ;
    PORT
      LAYER M5 ;
        RECT  34.416 0 34.44 0.084 ;
    END
  END q[663]
  PIN q[664]
    DIRECTION OUTPUT ;
    USE SIGNAL ;
    PORT
      LAYER M5 ;
        RECT  34.512 0 34.536 0.084 ;
    END
  END q[664]
  PIN q[665]
    DIRECTION OUTPUT ;
    USE SIGNAL ;
    PORT
      LAYER M5 ;
        RECT  34.608 0 34.632 0.084 ;
    END
  END q[665]
  PIN q[666]
    DIRECTION OUTPUT ;
    USE SIGNAL ;
    PORT
      LAYER M5 ;
        RECT  34.704 0 34.728 0.084 ;
    END
  END q[666]
  PIN q[667]
    DIRECTION OUTPUT ;
    USE SIGNAL ;
    PORT
      LAYER M5 ;
        RECT  34.8 0 34.824 0.084 ;
    END
  END q[667]
  PIN q[668]
    DIRECTION OUTPUT ;
    USE SIGNAL ;
    PORT
      LAYER M5 ;
        RECT  34.896 0 34.92 0.084 ;
    END
  END q[668]
  PIN q[669]
    DIRECTION OUTPUT ;
    USE SIGNAL ;
    PORT
      LAYER M5 ;
        RECT  34.992 0 35.016 0.084 ;
    END
  END q[669]
  PIN q[66]
    DIRECTION OUTPUT ;
    USE SIGNAL ;
    PORT
      LAYER M5 ;
        RECT  45.456 0 45.48 0.084 ;
    END
  END q[66]
  PIN q[670]
    DIRECTION OUTPUT ;
    USE SIGNAL ;
    PORT
      LAYER M5 ;
        RECT  35.088 0 35.112 0.084 ;
    END
  END q[670]
  PIN q[671]
    DIRECTION OUTPUT ;
    USE SIGNAL ;
    PORT
      LAYER M5 ;
        RECT  35.184 0 35.208 0.084 ;
    END
  END q[671]
  PIN q[672]
    DIRECTION OUTPUT ;
    USE SIGNAL ;
    PORT
      LAYER M5 ;
        RECT  35.28 0 35.304 0.084 ;
    END
  END q[672]
  PIN q[673]
    DIRECTION OUTPUT ;
    USE SIGNAL ;
    PORT
      LAYER M5 ;
        RECT  35.376 0 35.4 0.084 ;
    END
  END q[673]
  PIN q[674]
    DIRECTION OUTPUT ;
    USE SIGNAL ;
    PORT
      LAYER M5 ;
        RECT  35.472 0 35.496 0.084 ;
    END
  END q[674]
  PIN q[675]
    DIRECTION OUTPUT ;
    USE SIGNAL ;
    PORT
      LAYER M5 ;
        RECT  35.568 0 35.592 0.084 ;
    END
  END q[675]
  PIN q[676]
    DIRECTION OUTPUT ;
    USE SIGNAL ;
    PORT
      LAYER M5 ;
        RECT  35.664 0 35.688 0.084 ;
    END
  END q[676]
  PIN q[677]
    DIRECTION OUTPUT ;
    USE SIGNAL ;
    PORT
      LAYER M5 ;
        RECT  35.76 0 35.784 0.084 ;
    END
  END q[677]
  PIN q[678]
    DIRECTION OUTPUT ;
    USE SIGNAL ;
    PORT
      LAYER M5 ;
        RECT  35.856 0 35.88 0.084 ;
    END
  END q[678]
  PIN q[679]
    DIRECTION OUTPUT ;
    USE SIGNAL ;
    PORT
      LAYER M5 ;
        RECT  35.952 0 35.976 0.084 ;
    END
  END q[679]
  PIN q[67]
    DIRECTION OUTPUT ;
    USE SIGNAL ;
    PORT
      LAYER M5 ;
        RECT  45.552 0 45.576 0.084 ;
    END
  END q[67]
  PIN q[680]
    DIRECTION OUTPUT ;
    USE SIGNAL ;
    PORT
      LAYER M5 ;
        RECT  36.048 0 36.072 0.084 ;
    END
  END q[680]
  PIN q[681]
    DIRECTION OUTPUT ;
    USE SIGNAL ;
    PORT
      LAYER M5 ;
        RECT  36.144 0 36.168 0.084 ;
    END
  END q[681]
  PIN q[682]
    DIRECTION OUTPUT ;
    USE SIGNAL ;
    PORT
      LAYER M5 ;
        RECT  36.24 0 36.264 0.084 ;
    END
  END q[682]
  PIN q[683]
    DIRECTION OUTPUT ;
    USE SIGNAL ;
    PORT
      LAYER M5 ;
        RECT  36.336 0 36.36 0.084 ;
    END
  END q[683]
  PIN q[684]
    DIRECTION OUTPUT ;
    USE SIGNAL ;
    PORT
      LAYER M5 ;
        RECT  36.432 0 36.456 0.084 ;
    END
  END q[684]
  PIN q[685]
    DIRECTION OUTPUT ;
    USE SIGNAL ;
    PORT
      LAYER M5 ;
        RECT  36.528 0 36.552 0.084 ;
    END
  END q[685]
  PIN q[686]
    DIRECTION OUTPUT ;
    USE SIGNAL ;
    PORT
      LAYER M5 ;
        RECT  36.624 0 36.648 0.084 ;
    END
  END q[686]
  PIN q[687]
    DIRECTION OUTPUT ;
    USE SIGNAL ;
    PORT
      LAYER M5 ;
        RECT  36.72 0 36.744 0.084 ;
    END
  END q[687]
  PIN q[688]
    DIRECTION OUTPUT ;
    USE SIGNAL ;
    PORT
      LAYER M5 ;
        RECT  36.816 0 36.84 0.084 ;
    END
  END q[688]
  PIN q[689]
    DIRECTION OUTPUT ;
    USE SIGNAL ;
    PORT
      LAYER M5 ;
        RECT  36.912 0 36.936 0.084 ;
    END
  END q[689]
  PIN q[68]
    DIRECTION OUTPUT ;
    USE SIGNAL ;
    PORT
      LAYER M5 ;
        RECT  45.648 0 45.672 0.084 ;
    END
  END q[68]
  PIN q[690]
    DIRECTION OUTPUT ;
    USE SIGNAL ;
    PORT
      LAYER M5 ;
        RECT  37.008 0 37.032 0.084 ;
    END
  END q[690]
  PIN q[691]
    DIRECTION OUTPUT ;
    USE SIGNAL ;
    PORT
      LAYER M5 ;
        RECT  37.104 0 37.128 0.084 ;
    END
  END q[691]
  PIN q[692]
    DIRECTION OUTPUT ;
    USE SIGNAL ;
    PORT
      LAYER M5 ;
        RECT  37.2 0 37.224 0.084 ;
    END
  END q[692]
  PIN q[693]
    DIRECTION OUTPUT ;
    USE SIGNAL ;
    PORT
      LAYER M5 ;
        RECT  37.296 0 37.32 0.084 ;
    END
  END q[693]
  PIN q[694]
    DIRECTION OUTPUT ;
    USE SIGNAL ;
    PORT
      LAYER M5 ;
        RECT  37.392 0 37.416 0.084 ;
    END
  END q[694]
  PIN q[695]
    DIRECTION OUTPUT ;
    USE SIGNAL ;
    PORT
      LAYER M5 ;
        RECT  37.488 0 37.512 0.084 ;
    END
  END q[695]
  PIN q[696]
    DIRECTION OUTPUT ;
    USE SIGNAL ;
    PORT
      LAYER M5 ;
        RECT  37.584 0 37.608 0.084 ;
    END
  END q[696]
  PIN q[697]
    DIRECTION OUTPUT ;
    USE SIGNAL ;
    PORT
      LAYER M5 ;
        RECT  37.68 0 37.704 0.084 ;
    END
  END q[697]
  PIN q[698]
    DIRECTION OUTPUT ;
    USE SIGNAL ;
    PORT
      LAYER M5 ;
        RECT  37.776 0 37.8 0.084 ;
    END
  END q[698]
  PIN q[699]
    DIRECTION OUTPUT ;
    USE SIGNAL ;
    PORT
      LAYER M5 ;
        RECT  37.872 0 37.896 0.084 ;
    END
  END q[699]
  PIN q[69]
    DIRECTION OUTPUT ;
    USE SIGNAL ;
    PORT
      LAYER M5 ;
        RECT  45.744 0 45.768 0.084 ;
    END
  END q[69]
  PIN q[6]
    DIRECTION OUTPUT ;
    USE SIGNAL ;
    PORT
      LAYER M5 ;
        RECT  68.112 0 68.136 0.084 ;
    END
  END q[6]
  PIN q[700]
    DIRECTION OUTPUT ;
    USE SIGNAL ;
    PORT
      LAYER M5 ;
        RECT  37.968 0 37.992 0.084 ;
    END
  END q[700]
  PIN q[701]
    DIRECTION OUTPUT ;
    USE SIGNAL ;
    PORT
      LAYER M5 ;
        RECT  38.064 0 38.088 0.084 ;
    END
  END q[701]
  PIN q[702]
    DIRECTION OUTPUT ;
    USE SIGNAL ;
    PORT
      LAYER M5 ;
        RECT  38.16 0 38.184 0.084 ;
    END
  END q[702]
  PIN q[703]
    DIRECTION OUTPUT ;
    USE SIGNAL ;
    PORT
      LAYER M5 ;
        RECT  38.256 0 38.28 0.084 ;
    END
  END q[703]
  PIN q[704]
    DIRECTION OUTPUT ;
    USE SIGNAL ;
    PORT
      LAYER M5 ;
        RECT  77.52 0 77.544 0.084 ;
    END
  END q[704]
  PIN q[705]
    DIRECTION OUTPUT ;
    USE SIGNAL ;
    PORT
      LAYER M5 ;
        RECT  77.616 0 77.64 0.084 ;
    END
  END q[705]
  PIN q[706]
    DIRECTION OUTPUT ;
    USE SIGNAL ;
    PORT
      LAYER M5 ;
        RECT  77.712 0 77.736 0.084 ;
    END
  END q[706]
  PIN q[707]
    DIRECTION OUTPUT ;
    USE SIGNAL ;
    PORT
      LAYER M5 ;
        RECT  77.808 0 77.832 0.084 ;
    END
  END q[707]
  PIN q[708]
    DIRECTION OUTPUT ;
    USE SIGNAL ;
    PORT
      LAYER M5 ;
        RECT  77.904 0 77.928 0.084 ;
    END
  END q[708]
  PIN q[709]
    DIRECTION OUTPUT ;
    USE SIGNAL ;
    PORT
      LAYER M5 ;
        RECT  78 0 78.024 0.084 ;
    END
  END q[709]
  PIN q[70]
    DIRECTION OUTPUT ;
    USE SIGNAL ;
    PORT
      LAYER M5 ;
        RECT  45.84 0 45.864 0.084 ;
    END
  END q[70]
  PIN q[710]
    DIRECTION OUTPUT ;
    USE SIGNAL ;
    PORT
      LAYER M5 ;
        RECT  78.096 0 78.12 0.084 ;
    END
  END q[710]
  PIN q[711]
    DIRECTION OUTPUT ;
    USE SIGNAL ;
    PORT
      LAYER M5 ;
        RECT  78.192 0 78.216 0.084 ;
    END
  END q[711]
  PIN q[712]
    DIRECTION OUTPUT ;
    USE SIGNAL ;
    PORT
      LAYER M5 ;
        RECT  78.288 0 78.312 0.084 ;
    END
  END q[712]
  PIN q[713]
    DIRECTION OUTPUT ;
    USE SIGNAL ;
    PORT
      LAYER M5 ;
        RECT  78.384 0 78.408 0.084 ;
    END
  END q[713]
  PIN q[714]
    DIRECTION OUTPUT ;
    USE SIGNAL ;
    PORT
      LAYER M5 ;
        RECT  78.48 0 78.504 0.084 ;
    END
  END q[714]
  PIN q[715]
    DIRECTION OUTPUT ;
    USE SIGNAL ;
    PORT
      LAYER M5 ;
        RECT  78.576 0 78.6 0.084 ;
    END
  END q[715]
  PIN q[716]
    DIRECTION OUTPUT ;
    USE SIGNAL ;
    PORT
      LAYER M5 ;
        RECT  78.672 0 78.696 0.084 ;
    END
  END q[716]
  PIN q[717]
    DIRECTION OUTPUT ;
    USE SIGNAL ;
    PORT
      LAYER M5 ;
        RECT  78.768 0 78.792 0.084 ;
    END
  END q[717]
  PIN q[718]
    DIRECTION OUTPUT ;
    USE SIGNAL ;
    PORT
      LAYER M5 ;
        RECT  78.864 0 78.888 0.084 ;
    END
  END q[718]
  PIN q[719]
    DIRECTION OUTPUT ;
    USE SIGNAL ;
    PORT
      LAYER M5 ;
        RECT  78.96 0 78.984 0.084 ;
    END
  END q[719]
  PIN q[71]
    DIRECTION OUTPUT ;
    USE SIGNAL ;
    PORT
      LAYER M5 ;
        RECT  45.936 0 45.96 0.084 ;
    END
  END q[71]
  PIN q[720]
    DIRECTION OUTPUT ;
    USE SIGNAL ;
    PORT
      LAYER M5 ;
        RECT  79.056 0 79.08 0.084 ;
    END
  END q[720]
  PIN q[721]
    DIRECTION OUTPUT ;
    USE SIGNAL ;
    PORT
      LAYER M5 ;
        RECT  79.152 0 79.176 0.084 ;
    END
  END q[721]
  PIN q[722]
    DIRECTION OUTPUT ;
    USE SIGNAL ;
    PORT
      LAYER M5 ;
        RECT  79.248 0 79.272 0.084 ;
    END
  END q[722]
  PIN q[723]
    DIRECTION OUTPUT ;
    USE SIGNAL ;
    PORT
      LAYER M5 ;
        RECT  79.344 0 79.368 0.084 ;
    END
  END q[723]
  PIN q[724]
    DIRECTION OUTPUT ;
    USE SIGNAL ;
    PORT
      LAYER M5 ;
        RECT  79.44 0 79.464 0.084 ;
    END
  END q[724]
  PIN q[725]
    DIRECTION OUTPUT ;
    USE SIGNAL ;
    PORT
      LAYER M5 ;
        RECT  79.536 0 79.56 0.084 ;
    END
  END q[725]
  PIN q[726]
    DIRECTION OUTPUT ;
    USE SIGNAL ;
    PORT
      LAYER M5 ;
        RECT  79.632 0 79.656 0.084 ;
    END
  END q[726]
  PIN q[727]
    DIRECTION OUTPUT ;
    USE SIGNAL ;
    PORT
      LAYER M5 ;
        RECT  79.728 0 79.752 0.084 ;
    END
  END q[727]
  PIN q[728]
    DIRECTION OUTPUT ;
    USE SIGNAL ;
    PORT
      LAYER M5 ;
        RECT  79.824 0 79.848 0.084 ;
    END
  END q[728]
  PIN q[729]
    DIRECTION OUTPUT ;
    USE SIGNAL ;
    PORT
      LAYER M5 ;
        RECT  79.92 0 79.944 0.084 ;
    END
  END q[729]
  PIN q[72]
    DIRECTION OUTPUT ;
    USE SIGNAL ;
    PORT
      LAYER M5 ;
        RECT  46.032 0 46.056 0.084 ;
    END
  END q[72]
  PIN q[730]
    DIRECTION OUTPUT ;
    USE SIGNAL ;
    PORT
      LAYER M5 ;
        RECT  80.016 0 80.04 0.084 ;
    END
  END q[730]
  PIN q[731]
    DIRECTION OUTPUT ;
    USE SIGNAL ;
    PORT
      LAYER M5 ;
        RECT  80.112 0 80.136 0.084 ;
    END
  END q[731]
  PIN q[732]
    DIRECTION OUTPUT ;
    USE SIGNAL ;
    PORT
      LAYER M5 ;
        RECT  80.208 0 80.232 0.084 ;
    END
  END q[732]
  PIN q[733]
    DIRECTION OUTPUT ;
    USE SIGNAL ;
    PORT
      LAYER M5 ;
        RECT  80.304 0 80.328 0.084 ;
    END
  END q[733]
  PIN q[734]
    DIRECTION OUTPUT ;
    USE SIGNAL ;
    PORT
      LAYER M5 ;
        RECT  80.4 0 80.424 0.084 ;
    END
  END q[734]
  PIN q[735]
    DIRECTION OUTPUT ;
    USE SIGNAL ;
    PORT
      LAYER M5 ;
        RECT  80.496 0 80.52 0.084 ;
    END
  END q[735]
  PIN q[736]
    DIRECTION OUTPUT ;
    USE SIGNAL ;
    PORT
      LAYER M5 ;
        RECT  22.992 0 23.016 0.084 ;
    END
  END q[736]
  PIN q[737]
    DIRECTION OUTPUT ;
    USE SIGNAL ;
    PORT
      LAYER M5 ;
        RECT  23.088 0 23.112 0.084 ;
    END
  END q[737]
  PIN q[738]
    DIRECTION OUTPUT ;
    USE SIGNAL ;
    PORT
      LAYER M5 ;
        RECT  23.184 0 23.208 0.084 ;
    END
  END q[738]
  PIN q[739]
    DIRECTION OUTPUT ;
    USE SIGNAL ;
    PORT
      LAYER M5 ;
        RECT  23.28 0 23.304 0.084 ;
    END
  END q[739]
  PIN q[73]
    DIRECTION OUTPUT ;
    USE SIGNAL ;
    PORT
      LAYER M5 ;
        RECT  46.128 0 46.152 0.084 ;
    END
  END q[73]
  PIN q[740]
    DIRECTION OUTPUT ;
    USE SIGNAL ;
    PORT
      LAYER M5 ;
        RECT  23.376 0 23.4 0.084 ;
    END
  END q[740]
  PIN q[741]
    DIRECTION OUTPUT ;
    USE SIGNAL ;
    PORT
      LAYER M5 ;
        RECT  23.472 0 23.496 0.084 ;
    END
  END q[741]
  PIN q[742]
    DIRECTION OUTPUT ;
    USE SIGNAL ;
    PORT
      LAYER M5 ;
        RECT  23.568 0 23.592 0.084 ;
    END
  END q[742]
  PIN q[743]
    DIRECTION OUTPUT ;
    USE SIGNAL ;
    PORT
      LAYER M5 ;
        RECT  23.664 0 23.688 0.084 ;
    END
  END q[743]
  PIN q[744]
    DIRECTION OUTPUT ;
    USE SIGNAL ;
    PORT
      LAYER M5 ;
        RECT  23.76 0 23.784 0.084 ;
    END
  END q[744]
  PIN q[745]
    DIRECTION OUTPUT ;
    USE SIGNAL ;
    PORT
      LAYER M5 ;
        RECT  23.856 0 23.88 0.084 ;
    END
  END q[745]
  PIN q[746]
    DIRECTION OUTPUT ;
    USE SIGNAL ;
    PORT
      LAYER M5 ;
        RECT  23.952 0 23.976 0.084 ;
    END
  END q[746]
  PIN q[747]
    DIRECTION OUTPUT ;
    USE SIGNAL ;
    PORT
      LAYER M5 ;
        RECT  24.048 0 24.072 0.084 ;
    END
  END q[747]
  PIN q[748]
    DIRECTION OUTPUT ;
    USE SIGNAL ;
    PORT
      LAYER M5 ;
        RECT  24.144 0 24.168 0.084 ;
    END
  END q[748]
  PIN q[749]
    DIRECTION OUTPUT ;
    USE SIGNAL ;
    PORT
      LAYER M5 ;
        RECT  24.24 0 24.264 0.084 ;
    END
  END q[749]
  PIN q[74]
    DIRECTION OUTPUT ;
    USE SIGNAL ;
    PORT
      LAYER M5 ;
        RECT  46.224 0 46.248 0.084 ;
    END
  END q[74]
  PIN q[750]
    DIRECTION OUTPUT ;
    USE SIGNAL ;
    PORT
      LAYER M5 ;
        RECT  24.336 0 24.36 0.084 ;
    END
  END q[750]
  PIN q[751]
    DIRECTION OUTPUT ;
    USE SIGNAL ;
    PORT
      LAYER M5 ;
        RECT  24.432 0 24.456 0.084 ;
    END
  END q[751]
  PIN q[752]
    DIRECTION OUTPUT ;
    USE SIGNAL ;
    PORT
      LAYER M5 ;
        RECT  24.528 0 24.552 0.084 ;
    END
  END q[752]
  PIN q[753]
    DIRECTION OUTPUT ;
    USE SIGNAL ;
    PORT
      LAYER M5 ;
        RECT  24.624 0 24.648 0.084 ;
    END
  END q[753]
  PIN q[754]
    DIRECTION OUTPUT ;
    USE SIGNAL ;
    PORT
      LAYER M5 ;
        RECT  24.72 0 24.744 0.084 ;
    END
  END q[754]
  PIN q[755]
    DIRECTION OUTPUT ;
    USE SIGNAL ;
    PORT
      LAYER M5 ;
        RECT  24.816 0 24.84 0.084 ;
    END
  END q[755]
  PIN q[756]
    DIRECTION OUTPUT ;
    USE SIGNAL ;
    PORT
      LAYER M5 ;
        RECT  24.912 0 24.936 0.084 ;
    END
  END q[756]
  PIN q[757]
    DIRECTION OUTPUT ;
    USE SIGNAL ;
    PORT
      LAYER M5 ;
        RECT  25.008 0 25.032 0.084 ;
    END
  END q[757]
  PIN q[758]
    DIRECTION OUTPUT ;
    USE SIGNAL ;
    PORT
      LAYER M5 ;
        RECT  25.104 0 25.128 0.084 ;
    END
  END q[758]
  PIN q[759]
    DIRECTION OUTPUT ;
    USE SIGNAL ;
    PORT
      LAYER M5 ;
        RECT  25.2 0 25.224 0.084 ;
    END
  END q[759]
  PIN q[75]
    DIRECTION OUTPUT ;
    USE SIGNAL ;
    PORT
      LAYER M5 ;
        RECT  46.32 0 46.344 0.084 ;
    END
  END q[75]
  PIN q[760]
    DIRECTION OUTPUT ;
    USE SIGNAL ;
    PORT
      LAYER M5 ;
        RECT  25.296 0 25.32 0.084 ;
    END
  END q[760]
  PIN q[761]
    DIRECTION OUTPUT ;
    USE SIGNAL ;
    PORT
      LAYER M5 ;
        RECT  25.392 0 25.416 0.084 ;
    END
  END q[761]
  PIN q[762]
    DIRECTION OUTPUT ;
    USE SIGNAL ;
    PORT
      LAYER M5 ;
        RECT  25.488 0 25.512 0.084 ;
    END
  END q[762]
  PIN q[763]
    DIRECTION OUTPUT ;
    USE SIGNAL ;
    PORT
      LAYER M5 ;
        RECT  25.584 0 25.608 0.084 ;
    END
  END q[763]
  PIN q[764]
    DIRECTION OUTPUT ;
    USE SIGNAL ;
    PORT
      LAYER M5 ;
        RECT  25.68 0 25.704 0.084 ;
    END
  END q[764]
  PIN q[765]
    DIRECTION OUTPUT ;
    USE SIGNAL ;
    PORT
      LAYER M5 ;
        RECT  25.776 0 25.8 0.084 ;
    END
  END q[765]
  PIN q[766]
    DIRECTION OUTPUT ;
    USE SIGNAL ;
    PORT
      LAYER M5 ;
        RECT  25.872 0 25.896 0.084 ;
    END
  END q[766]
  PIN q[767]
    DIRECTION OUTPUT ;
    USE SIGNAL ;
    PORT
      LAYER M5 ;
        RECT  25.968 0 25.992 0.084 ;
    END
  END q[767]
  PIN q[768]
    DIRECTION OUTPUT ;
    USE SIGNAL ;
    PORT
      LAYER M5 ;
        RECT  109.008 0 109.032 0.084 ;
    END
  END q[768]
  PIN q[769]
    DIRECTION OUTPUT ;
    USE SIGNAL ;
    PORT
      LAYER M5 ;
        RECT  109.104 0 109.128 0.084 ;
    END
  END q[769]
  PIN q[76]
    DIRECTION OUTPUT ;
    USE SIGNAL ;
    PORT
      LAYER M5 ;
        RECT  46.416 0 46.44 0.084 ;
    END
  END q[76]
  PIN q[770]
    DIRECTION OUTPUT ;
    USE SIGNAL ;
    PORT
      LAYER M5 ;
        RECT  109.2 0 109.224 0.084 ;
    END
  END q[770]
  PIN q[771]
    DIRECTION OUTPUT ;
    USE SIGNAL ;
    PORT
      LAYER M5 ;
        RECT  109.296 0 109.32 0.084 ;
    END
  END q[771]
  PIN q[772]
    DIRECTION OUTPUT ;
    USE SIGNAL ;
    PORT
      LAYER M5 ;
        RECT  109.392 0 109.416 0.084 ;
    END
  END q[772]
  PIN q[773]
    DIRECTION OUTPUT ;
    USE SIGNAL ;
    PORT
      LAYER M5 ;
        RECT  109.488 0 109.512 0.084 ;
    END
  END q[773]
  PIN q[774]
    DIRECTION OUTPUT ;
    USE SIGNAL ;
    PORT
      LAYER M5 ;
        RECT  109.584 0 109.608 0.084 ;
    END
  END q[774]
  PIN q[775]
    DIRECTION OUTPUT ;
    USE SIGNAL ;
    PORT
      LAYER M5 ;
        RECT  109.68 0 109.704 0.084 ;
    END
  END q[775]
  PIN q[776]
    DIRECTION OUTPUT ;
    USE SIGNAL ;
    PORT
      LAYER M5 ;
        RECT  109.776 0 109.8 0.084 ;
    END
  END q[776]
  PIN q[777]
    DIRECTION OUTPUT ;
    USE SIGNAL ;
    PORT
      LAYER M5 ;
        RECT  109.872 0 109.896 0.084 ;
    END
  END q[777]
  PIN q[778]
    DIRECTION OUTPUT ;
    USE SIGNAL ;
    PORT
      LAYER M5 ;
        RECT  109.968 0 109.992 0.084 ;
    END
  END q[778]
  PIN q[779]
    DIRECTION OUTPUT ;
    USE SIGNAL ;
    PORT
      LAYER M5 ;
        RECT  110.064 0 110.088 0.084 ;
    END
  END q[779]
  PIN q[77]
    DIRECTION OUTPUT ;
    USE SIGNAL ;
    PORT
      LAYER M5 ;
        RECT  46.512 0 46.536 0.084 ;
    END
  END q[77]
  PIN q[780]
    DIRECTION OUTPUT ;
    USE SIGNAL ;
    PORT
      LAYER M5 ;
        RECT  110.16 0 110.184 0.084 ;
    END
  END q[780]
  PIN q[781]
    DIRECTION OUTPUT ;
    USE SIGNAL ;
    PORT
      LAYER M5 ;
        RECT  110.256 0 110.28 0.084 ;
    END
  END q[781]
  PIN q[782]
    DIRECTION OUTPUT ;
    USE SIGNAL ;
    PORT
      LAYER M5 ;
        RECT  110.352 0 110.376 0.084 ;
    END
  END q[782]
  PIN q[783]
    DIRECTION OUTPUT ;
    USE SIGNAL ;
    PORT
      LAYER M5 ;
        RECT  110.448 0 110.472 0.084 ;
    END
  END q[783]
  PIN q[784]
    DIRECTION OUTPUT ;
    USE SIGNAL ;
    PORT
      LAYER M5 ;
        RECT  110.544 0 110.568 0.084 ;
    END
  END q[784]
  PIN q[785]
    DIRECTION OUTPUT ;
    USE SIGNAL ;
    PORT
      LAYER M5 ;
        RECT  110.64 0 110.664 0.084 ;
    END
  END q[785]
  PIN q[786]
    DIRECTION OUTPUT ;
    USE SIGNAL ;
    PORT
      LAYER M5 ;
        RECT  110.736 0 110.76 0.084 ;
    END
  END q[786]
  PIN q[787]
    DIRECTION OUTPUT ;
    USE SIGNAL ;
    PORT
      LAYER M5 ;
        RECT  110.832 0 110.856 0.084 ;
    END
  END q[787]
  PIN q[788]
    DIRECTION OUTPUT ;
    USE SIGNAL ;
    PORT
      LAYER M5 ;
        RECT  110.928 0 110.952 0.084 ;
    END
  END q[788]
  PIN q[789]
    DIRECTION OUTPUT ;
    USE SIGNAL ;
    PORT
      LAYER M5 ;
        RECT  111.024 0 111.048 0.084 ;
    END
  END q[789]
  PIN q[78]
    DIRECTION OUTPUT ;
    USE SIGNAL ;
    PORT
      LAYER M5 ;
        RECT  46.608 0 46.632 0.084 ;
    END
  END q[78]
  PIN q[790]
    DIRECTION OUTPUT ;
    USE SIGNAL ;
    PORT
      LAYER M5 ;
        RECT  111.12 0 111.144 0.084 ;
    END
  END q[790]
  PIN q[791]
    DIRECTION OUTPUT ;
    USE SIGNAL ;
    PORT
      LAYER M5 ;
        RECT  111.216 0 111.24 0.084 ;
    END
  END q[791]
  PIN q[792]
    DIRECTION OUTPUT ;
    USE SIGNAL ;
    PORT
      LAYER M5 ;
        RECT  111.312 0 111.336 0.084 ;
    END
  END q[792]
  PIN q[793]
    DIRECTION OUTPUT ;
    USE SIGNAL ;
    PORT
      LAYER M5 ;
        RECT  111.408 0 111.432 0.084 ;
    END
  END q[793]
  PIN q[794]
    DIRECTION OUTPUT ;
    USE SIGNAL ;
    PORT
      LAYER M5 ;
        RECT  111.504 0 111.528 0.084 ;
    END
  END q[794]
  PIN q[795]
    DIRECTION OUTPUT ;
    USE SIGNAL ;
    PORT
      LAYER M5 ;
        RECT  111.6 0 111.624 0.084 ;
    END
  END q[795]
  PIN q[796]
    DIRECTION OUTPUT ;
    USE SIGNAL ;
    PORT
      LAYER M5 ;
        RECT  111.696 0 111.72 0.084 ;
    END
  END q[796]
  PIN q[797]
    DIRECTION OUTPUT ;
    USE SIGNAL ;
    PORT
      LAYER M5 ;
        RECT  111.792 0 111.816 0.084 ;
    END
  END q[797]
  PIN q[798]
    DIRECTION OUTPUT ;
    USE SIGNAL ;
    PORT
      LAYER M5 ;
        RECT  111.888 0 111.912 0.084 ;
    END
  END q[798]
  PIN q[799]
    DIRECTION OUTPUT ;
    USE SIGNAL ;
    PORT
      LAYER M5 ;
        RECT  111.984 0 112.008 0.084 ;
    END
  END q[799]
  PIN q[79]
    DIRECTION OUTPUT ;
    USE SIGNAL ;
    PORT
      LAYER M5 ;
        RECT  46.704 0 46.728 0.084 ;
    END
  END q[79]
  PIN q[7]
    DIRECTION OUTPUT ;
    USE SIGNAL ;
    PORT
      LAYER M5 ;
        RECT  68.208 0 68.232 0.084 ;
    END
  END q[7]
  PIN q[800]
    DIRECTION OUTPUT ;
    USE SIGNAL ;
    PORT
      LAYER M5 ;
        RECT  102.864 0 102.888 0.084 ;
    END
  END q[800]
  PIN q[801]
    DIRECTION OUTPUT ;
    USE SIGNAL ;
    PORT
      LAYER M5 ;
        RECT  102.96 0 102.984 0.084 ;
    END
  END q[801]
  PIN q[802]
    DIRECTION OUTPUT ;
    USE SIGNAL ;
    PORT
      LAYER M5 ;
        RECT  103.056 0 103.08 0.084 ;
    END
  END q[802]
  PIN q[803]
    DIRECTION OUTPUT ;
    USE SIGNAL ;
    PORT
      LAYER M5 ;
        RECT  103.152 0 103.176 0.084 ;
    END
  END q[803]
  PIN q[804]
    DIRECTION OUTPUT ;
    USE SIGNAL ;
    PORT
      LAYER M5 ;
        RECT  103.248 0 103.272 0.084 ;
    END
  END q[804]
  PIN q[805]
    DIRECTION OUTPUT ;
    USE SIGNAL ;
    PORT
      LAYER M5 ;
        RECT  103.344 0 103.368 0.084 ;
    END
  END q[805]
  PIN q[806]
    DIRECTION OUTPUT ;
    USE SIGNAL ;
    PORT
      LAYER M5 ;
        RECT  103.44 0 103.464 0.084 ;
    END
  END q[806]
  PIN q[807]
    DIRECTION OUTPUT ;
    USE SIGNAL ;
    PORT
      LAYER M5 ;
        RECT  103.536 0 103.56 0.084 ;
    END
  END q[807]
  PIN q[808]
    DIRECTION OUTPUT ;
    USE SIGNAL ;
    PORT
      LAYER M5 ;
        RECT  103.632 0 103.656 0.084 ;
    END
  END q[808]
  PIN q[809]
    DIRECTION OUTPUT ;
    USE SIGNAL ;
    PORT
      LAYER M5 ;
        RECT  103.728 0 103.752 0.084 ;
    END
  END q[809]
  PIN q[80]
    DIRECTION OUTPUT ;
    USE SIGNAL ;
    PORT
      LAYER M5 ;
        RECT  46.8 0 46.824 0.084 ;
    END
  END q[80]
  PIN q[810]
    DIRECTION OUTPUT ;
    USE SIGNAL ;
    PORT
      LAYER M5 ;
        RECT  103.824 0 103.848 0.084 ;
    END
  END q[810]
  PIN q[811]
    DIRECTION OUTPUT ;
    USE SIGNAL ;
    PORT
      LAYER M5 ;
        RECT  103.92 0 103.944 0.084 ;
    END
  END q[811]
  PIN q[812]
    DIRECTION OUTPUT ;
    USE SIGNAL ;
    PORT
      LAYER M5 ;
        RECT  104.016 0 104.04 0.084 ;
    END
  END q[812]
  PIN q[813]
    DIRECTION OUTPUT ;
    USE SIGNAL ;
    PORT
      LAYER M5 ;
        RECT  104.112 0 104.136 0.084 ;
    END
  END q[813]
  PIN q[814]
    DIRECTION OUTPUT ;
    USE SIGNAL ;
    PORT
      LAYER M5 ;
        RECT  104.208 0 104.232 0.084 ;
    END
  END q[814]
  PIN q[815]
    DIRECTION OUTPUT ;
    USE SIGNAL ;
    PORT
      LAYER M5 ;
        RECT  104.304 0 104.328 0.084 ;
    END
  END q[815]
  PIN q[816]
    DIRECTION OUTPUT ;
    USE SIGNAL ;
    PORT
      LAYER M5 ;
        RECT  104.4 0 104.424 0.084 ;
    END
  END q[816]
  PIN q[817]
    DIRECTION OUTPUT ;
    USE SIGNAL ;
    PORT
      LAYER M5 ;
        RECT  104.496 0 104.52 0.084 ;
    END
  END q[817]
  PIN q[818]
    DIRECTION OUTPUT ;
    USE SIGNAL ;
    PORT
      LAYER M5 ;
        RECT  104.592 0 104.616 0.084 ;
    END
  END q[818]
  PIN q[819]
    DIRECTION OUTPUT ;
    USE SIGNAL ;
    PORT
      LAYER M5 ;
        RECT  104.688 0 104.712 0.084 ;
    END
  END q[819]
  PIN q[81]
    DIRECTION OUTPUT ;
    USE SIGNAL ;
    PORT
      LAYER M5 ;
        RECT  46.896 0 46.92 0.084 ;
    END
  END q[81]
  PIN q[820]
    DIRECTION OUTPUT ;
    USE SIGNAL ;
    PORT
      LAYER M5 ;
        RECT  104.784 0 104.808 0.084 ;
    END
  END q[820]
  PIN q[821]
    DIRECTION OUTPUT ;
    USE SIGNAL ;
    PORT
      LAYER M5 ;
        RECT  104.88 0 104.904 0.084 ;
    END
  END q[821]
  PIN q[822]
    DIRECTION OUTPUT ;
    USE SIGNAL ;
    PORT
      LAYER M5 ;
        RECT  104.976 0 105 0.084 ;
    END
  END q[822]
  PIN q[823]
    DIRECTION OUTPUT ;
    USE SIGNAL ;
    PORT
      LAYER M5 ;
        RECT  105.072 0 105.096 0.084 ;
    END
  END q[823]
  PIN q[824]
    DIRECTION OUTPUT ;
    USE SIGNAL ;
    PORT
      LAYER M5 ;
        RECT  105.168 0 105.192 0.084 ;
    END
  END q[824]
  PIN q[825]
    DIRECTION OUTPUT ;
    USE SIGNAL ;
    PORT
      LAYER M5 ;
        RECT  105.264 0 105.288 0.084 ;
    END
  END q[825]
  PIN q[826]
    DIRECTION OUTPUT ;
    USE SIGNAL ;
    PORT
      LAYER M5 ;
        RECT  105.36 0 105.384 0.084 ;
    END
  END q[826]
  PIN q[827]
    DIRECTION OUTPUT ;
    USE SIGNAL ;
    PORT
      LAYER M5 ;
        RECT  105.456 0 105.48 0.084 ;
    END
  END q[827]
  PIN q[828]
    DIRECTION OUTPUT ;
    USE SIGNAL ;
    PORT
      LAYER M5 ;
        RECT  105.552 0 105.576 0.084 ;
    END
  END q[828]
  PIN q[829]
    DIRECTION OUTPUT ;
    USE SIGNAL ;
    PORT
      LAYER M5 ;
        RECT  105.648 0 105.672 0.084 ;
    END
  END q[829]
  PIN q[82]
    DIRECTION OUTPUT ;
    USE SIGNAL ;
    PORT
      LAYER M5 ;
        RECT  46.992 0 47.016 0.084 ;
    END
  END q[82]
  PIN q[830]
    DIRECTION OUTPUT ;
    USE SIGNAL ;
    PORT
      LAYER M5 ;
        RECT  105.744 0 105.768 0.084 ;
    END
  END q[830]
  PIN q[831]
    DIRECTION OUTPUT ;
    USE SIGNAL ;
    PORT
      LAYER M5 ;
        RECT  105.84 0 105.864 0.084 ;
    END
  END q[831]
  PIN q[832]
    DIRECTION OUTPUT ;
    USE SIGNAL ;
    PORT
      LAYER M5 ;
        RECT  105.936 0 105.96 0.084 ;
    END
  END q[832]
  PIN q[833]
    DIRECTION OUTPUT ;
    USE SIGNAL ;
    PORT
      LAYER M5 ;
        RECT  106.032 0 106.056 0.084 ;
    END
  END q[833]
  PIN q[834]
    DIRECTION OUTPUT ;
    USE SIGNAL ;
    PORT
      LAYER M5 ;
        RECT  106.128 0 106.152 0.084 ;
    END
  END q[834]
  PIN q[835]
    DIRECTION OUTPUT ;
    USE SIGNAL ;
    PORT
      LAYER M5 ;
        RECT  106.224 0 106.248 0.084 ;
    END
  END q[835]
  PIN q[836]
    DIRECTION OUTPUT ;
    USE SIGNAL ;
    PORT
      LAYER M5 ;
        RECT  106.32 0 106.344 0.084 ;
    END
  END q[836]
  PIN q[837]
    DIRECTION OUTPUT ;
    USE SIGNAL ;
    PORT
      LAYER M5 ;
        RECT  106.416 0 106.44 0.084 ;
    END
  END q[837]
  PIN q[838]
    DIRECTION OUTPUT ;
    USE SIGNAL ;
    PORT
      LAYER M5 ;
        RECT  106.512 0 106.536 0.084 ;
    END
  END q[838]
  PIN q[839]
    DIRECTION OUTPUT ;
    USE SIGNAL ;
    PORT
      LAYER M5 ;
        RECT  106.608 0 106.632 0.084 ;
    END
  END q[839]
  PIN q[83]
    DIRECTION OUTPUT ;
    USE SIGNAL ;
    PORT
      LAYER M5 ;
        RECT  47.088 0 47.112 0.084 ;
    END
  END q[83]
  PIN q[840]
    DIRECTION OUTPUT ;
    USE SIGNAL ;
    PORT
      LAYER M5 ;
        RECT  106.704 0 106.728 0.084 ;
    END
  END q[840]
  PIN q[841]
    DIRECTION OUTPUT ;
    USE SIGNAL ;
    PORT
      LAYER M5 ;
        RECT  106.8 0 106.824 0.084 ;
    END
  END q[841]
  PIN q[842]
    DIRECTION OUTPUT ;
    USE SIGNAL ;
    PORT
      LAYER M5 ;
        RECT  106.896 0 106.92 0.084 ;
    END
  END q[842]
  PIN q[843]
    DIRECTION OUTPUT ;
    USE SIGNAL ;
    PORT
      LAYER M5 ;
        RECT  106.992 0 107.016 0.084 ;
    END
  END q[843]
  PIN q[844]
    DIRECTION OUTPUT ;
    USE SIGNAL ;
    PORT
      LAYER M5 ;
        RECT  107.088 0 107.112 0.084 ;
    END
  END q[844]
  PIN q[845]
    DIRECTION OUTPUT ;
    USE SIGNAL ;
    PORT
      LAYER M5 ;
        RECT  107.184 0 107.208 0.084 ;
    END
  END q[845]
  PIN q[846]
    DIRECTION OUTPUT ;
    USE SIGNAL ;
    PORT
      LAYER M5 ;
        RECT  107.28 0 107.304 0.084 ;
    END
  END q[846]
  PIN q[847]
    DIRECTION OUTPUT ;
    USE SIGNAL ;
    PORT
      LAYER M5 ;
        RECT  107.376 0 107.4 0.084 ;
    END
  END q[847]
  PIN q[848]
    DIRECTION OUTPUT ;
    USE SIGNAL ;
    PORT
      LAYER M5 ;
        RECT  107.472 0 107.496 0.084 ;
    END
  END q[848]
  PIN q[849]
    DIRECTION OUTPUT ;
    USE SIGNAL ;
    PORT
      LAYER M5 ;
        RECT  107.568 0 107.592 0.084 ;
    END
  END q[849]
  PIN q[84]
    DIRECTION OUTPUT ;
    USE SIGNAL ;
    PORT
      LAYER M5 ;
        RECT  47.184 0 47.208 0.084 ;
    END
  END q[84]
  PIN q[850]
    DIRECTION OUTPUT ;
    USE SIGNAL ;
    PORT
      LAYER M5 ;
        RECT  107.664 0 107.688 0.084 ;
    END
  END q[850]
  PIN q[851]
    DIRECTION OUTPUT ;
    USE SIGNAL ;
    PORT
      LAYER M5 ;
        RECT  107.76 0 107.784 0.084 ;
    END
  END q[851]
  PIN q[852]
    DIRECTION OUTPUT ;
    USE SIGNAL ;
    PORT
      LAYER M5 ;
        RECT  107.856 0 107.88 0.084 ;
    END
  END q[852]
  PIN q[853]
    DIRECTION OUTPUT ;
    USE SIGNAL ;
    PORT
      LAYER M5 ;
        RECT  107.952 0 107.976 0.084 ;
    END
  END q[853]
  PIN q[854]
    DIRECTION OUTPUT ;
    USE SIGNAL ;
    PORT
      LAYER M5 ;
        RECT  108.048 0 108.072 0.084 ;
    END
  END q[854]
  PIN q[855]
    DIRECTION OUTPUT ;
    USE SIGNAL ;
    PORT
      LAYER M5 ;
        RECT  108.144 0 108.168 0.084 ;
    END
  END q[855]
  PIN q[856]
    DIRECTION OUTPUT ;
    USE SIGNAL ;
    PORT
      LAYER M5 ;
        RECT  108.24 0 108.264 0.084 ;
    END
  END q[856]
  PIN q[857]
    DIRECTION OUTPUT ;
    USE SIGNAL ;
    PORT
      LAYER M5 ;
        RECT  108.336 0 108.36 0.084 ;
    END
  END q[857]
  PIN q[858]
    DIRECTION OUTPUT ;
    USE SIGNAL ;
    PORT
      LAYER M5 ;
        RECT  108.432 0 108.456 0.084 ;
    END
  END q[858]
  PIN q[859]
    DIRECTION OUTPUT ;
    USE SIGNAL ;
    PORT
      LAYER M5 ;
        RECT  108.528 0 108.552 0.084 ;
    END
  END q[859]
  PIN q[85]
    DIRECTION OUTPUT ;
    USE SIGNAL ;
    PORT
      LAYER M5 ;
        RECT  47.28 0 47.304 0.084 ;
    END
  END q[85]
  PIN q[860]
    DIRECTION OUTPUT ;
    USE SIGNAL ;
    PORT
      LAYER M5 ;
        RECT  108.624 0 108.648 0.084 ;
    END
  END q[860]
  PIN q[861]
    DIRECTION OUTPUT ;
    USE SIGNAL ;
    PORT
      LAYER M5 ;
        RECT  108.72 0 108.744 0.084 ;
    END
  END q[861]
  PIN q[862]
    DIRECTION OUTPUT ;
    USE SIGNAL ;
    PORT
      LAYER M5 ;
        RECT  108.816 0 108.84 0.084 ;
    END
  END q[862]
  PIN q[863]
    DIRECTION OUTPUT ;
    USE SIGNAL ;
    PORT
      LAYER M5 ;
        RECT  108.912 0 108.936 0.084 ;
    END
  END q[863]
  PIN q[864]
    DIRECTION OUTPUT ;
    USE SIGNAL ;
    PORT
      LAYER M5 ;
        RECT  96.72 0 96.744 0.084 ;
    END
  END q[864]
  PIN q[865]
    DIRECTION OUTPUT ;
    USE SIGNAL ;
    PORT
      LAYER M5 ;
        RECT  96.816 0 96.84 0.084 ;
    END
  END q[865]
  PIN q[866]
    DIRECTION OUTPUT ;
    USE SIGNAL ;
    PORT
      LAYER M5 ;
        RECT  96.912 0 96.936 0.084 ;
    END
  END q[866]
  PIN q[867]
    DIRECTION OUTPUT ;
    USE SIGNAL ;
    PORT
      LAYER M5 ;
        RECT  97.008 0 97.032 0.084 ;
    END
  END q[867]
  PIN q[868]
    DIRECTION OUTPUT ;
    USE SIGNAL ;
    PORT
      LAYER M5 ;
        RECT  97.104 0 97.128 0.084 ;
    END
  END q[868]
  PIN q[869]
    DIRECTION OUTPUT ;
    USE SIGNAL ;
    PORT
      LAYER M5 ;
        RECT  97.2 0 97.224 0.084 ;
    END
  END q[869]
  PIN q[86]
    DIRECTION OUTPUT ;
    USE SIGNAL ;
    PORT
      LAYER M5 ;
        RECT  47.376 0 47.4 0.084 ;
    END
  END q[86]
  PIN q[870]
    DIRECTION OUTPUT ;
    USE SIGNAL ;
    PORT
      LAYER M5 ;
        RECT  97.296 0 97.32 0.084 ;
    END
  END q[870]
  PIN q[871]
    DIRECTION OUTPUT ;
    USE SIGNAL ;
    PORT
      LAYER M5 ;
        RECT  97.392 0 97.416 0.084 ;
    END
  END q[871]
  PIN q[872]
    DIRECTION OUTPUT ;
    USE SIGNAL ;
    PORT
      LAYER M5 ;
        RECT  97.488 0 97.512 0.084 ;
    END
  END q[872]
  PIN q[873]
    DIRECTION OUTPUT ;
    USE SIGNAL ;
    PORT
      LAYER M5 ;
        RECT  97.584 0 97.608 0.084 ;
    END
  END q[873]
  PIN q[874]
    DIRECTION OUTPUT ;
    USE SIGNAL ;
    PORT
      LAYER M5 ;
        RECT  97.68 0 97.704 0.084 ;
    END
  END q[874]
  PIN q[875]
    DIRECTION OUTPUT ;
    USE SIGNAL ;
    PORT
      LAYER M5 ;
        RECT  97.776 0 97.8 0.084 ;
    END
  END q[875]
  PIN q[876]
    DIRECTION OUTPUT ;
    USE SIGNAL ;
    PORT
      LAYER M5 ;
        RECT  97.872 0 97.896 0.084 ;
    END
  END q[876]
  PIN q[877]
    DIRECTION OUTPUT ;
    USE SIGNAL ;
    PORT
      LAYER M5 ;
        RECT  97.968 0 97.992 0.084 ;
    END
  END q[877]
  PIN q[878]
    DIRECTION OUTPUT ;
    USE SIGNAL ;
    PORT
      LAYER M5 ;
        RECT  98.064 0 98.088 0.084 ;
    END
  END q[878]
  PIN q[879]
    DIRECTION OUTPUT ;
    USE SIGNAL ;
    PORT
      LAYER M5 ;
        RECT  98.16 0 98.184 0.084 ;
    END
  END q[879]
  PIN q[87]
    DIRECTION OUTPUT ;
    USE SIGNAL ;
    PORT
      LAYER M5 ;
        RECT  47.472 0 47.496 0.084 ;
    END
  END q[87]
  PIN q[880]
    DIRECTION OUTPUT ;
    USE SIGNAL ;
    PORT
      LAYER M5 ;
        RECT  98.256 0 98.28 0.084 ;
    END
  END q[880]
  PIN q[881]
    DIRECTION OUTPUT ;
    USE SIGNAL ;
    PORT
      LAYER M5 ;
        RECT  98.352 0 98.376 0.084 ;
    END
  END q[881]
  PIN q[882]
    DIRECTION OUTPUT ;
    USE SIGNAL ;
    PORT
      LAYER M5 ;
        RECT  98.448 0 98.472 0.084 ;
    END
  END q[882]
  PIN q[883]
    DIRECTION OUTPUT ;
    USE SIGNAL ;
    PORT
      LAYER M5 ;
        RECT  98.544 0 98.568 0.084 ;
    END
  END q[883]
  PIN q[884]
    DIRECTION OUTPUT ;
    USE SIGNAL ;
    PORT
      LAYER M5 ;
        RECT  98.64 0 98.664 0.084 ;
    END
  END q[884]
  PIN q[885]
    DIRECTION OUTPUT ;
    USE SIGNAL ;
    PORT
      LAYER M5 ;
        RECT  98.736 0 98.76 0.084 ;
    END
  END q[885]
  PIN q[886]
    DIRECTION OUTPUT ;
    USE SIGNAL ;
    PORT
      LAYER M5 ;
        RECT  98.832 0 98.856 0.084 ;
    END
  END q[886]
  PIN q[887]
    DIRECTION OUTPUT ;
    USE SIGNAL ;
    PORT
      LAYER M5 ;
        RECT  98.928 0 98.952 0.084 ;
    END
  END q[887]
  PIN q[888]
    DIRECTION OUTPUT ;
    USE SIGNAL ;
    PORT
      LAYER M5 ;
        RECT  99.024 0 99.048 0.084 ;
    END
  END q[888]
  PIN q[889]
    DIRECTION OUTPUT ;
    USE SIGNAL ;
    PORT
      LAYER M5 ;
        RECT  99.12 0 99.144 0.084 ;
    END
  END q[889]
  PIN q[88]
    DIRECTION OUTPUT ;
    USE SIGNAL ;
    PORT
      LAYER M5 ;
        RECT  47.568 0 47.592 0.084 ;
    END
  END q[88]
  PIN q[890]
    DIRECTION OUTPUT ;
    USE SIGNAL ;
    PORT
      LAYER M5 ;
        RECT  99.216 0 99.24 0.084 ;
    END
  END q[890]
  PIN q[891]
    DIRECTION OUTPUT ;
    USE SIGNAL ;
    PORT
      LAYER M5 ;
        RECT  99.312 0 99.336 0.084 ;
    END
  END q[891]
  PIN q[892]
    DIRECTION OUTPUT ;
    USE SIGNAL ;
    PORT
      LAYER M5 ;
        RECT  99.408 0 99.432 0.084 ;
    END
  END q[892]
  PIN q[893]
    DIRECTION OUTPUT ;
    USE SIGNAL ;
    PORT
      LAYER M5 ;
        RECT  99.504 0 99.528 0.084 ;
    END
  END q[893]
  PIN q[894]
    DIRECTION OUTPUT ;
    USE SIGNAL ;
    PORT
      LAYER M5 ;
        RECT  99.6 0 99.624 0.084 ;
    END
  END q[894]
  PIN q[895]
    DIRECTION OUTPUT ;
    USE SIGNAL ;
    PORT
      LAYER M5 ;
        RECT  99.696 0 99.72 0.084 ;
    END
  END q[895]
  PIN q[896]
    DIRECTION OUTPUT ;
    USE SIGNAL ;
    PORT
      LAYER M5 ;
        RECT  99.792 0 99.816 0.084 ;
    END
  END q[896]
  PIN q[897]
    DIRECTION OUTPUT ;
    USE SIGNAL ;
    PORT
      LAYER M5 ;
        RECT  99.888 0 99.912 0.084 ;
    END
  END q[897]
  PIN q[898]
    DIRECTION OUTPUT ;
    USE SIGNAL ;
    PORT
      LAYER M5 ;
        RECT  99.984 0 100.008 0.084 ;
    END
  END q[898]
  PIN q[899]
    DIRECTION OUTPUT ;
    USE SIGNAL ;
    PORT
      LAYER M5 ;
        RECT  100.08 0 100.104 0.084 ;
    END
  END q[899]
  PIN q[89]
    DIRECTION OUTPUT ;
    USE SIGNAL ;
    PORT
      LAYER M5 ;
        RECT  47.664 0 47.688 0.084 ;
    END
  END q[89]
  PIN q[8]
    DIRECTION OUTPUT ;
    USE SIGNAL ;
    PORT
      LAYER M5 ;
        RECT  68.304 0 68.328 0.084 ;
    END
  END q[8]
  PIN q[900]
    DIRECTION OUTPUT ;
    USE SIGNAL ;
    PORT
      LAYER M5 ;
        RECT  100.176 0 100.2 0.084 ;
    END
  END q[900]
  PIN q[901]
    DIRECTION OUTPUT ;
    USE SIGNAL ;
    PORT
      LAYER M5 ;
        RECT  100.272 0 100.296 0.084 ;
    END
  END q[901]
  PIN q[902]
    DIRECTION OUTPUT ;
    USE SIGNAL ;
    PORT
      LAYER M5 ;
        RECT  100.368 0 100.392 0.084 ;
    END
  END q[902]
  PIN q[903]
    DIRECTION OUTPUT ;
    USE SIGNAL ;
    PORT
      LAYER M5 ;
        RECT  100.464 0 100.488 0.084 ;
    END
  END q[903]
  PIN q[904]
    DIRECTION OUTPUT ;
    USE SIGNAL ;
    PORT
      LAYER M5 ;
        RECT  100.56 0 100.584 0.084 ;
    END
  END q[904]
  PIN q[905]
    DIRECTION OUTPUT ;
    USE SIGNAL ;
    PORT
      LAYER M5 ;
        RECT  100.656 0 100.68 0.084 ;
    END
  END q[905]
  PIN q[906]
    DIRECTION OUTPUT ;
    USE SIGNAL ;
    PORT
      LAYER M5 ;
        RECT  100.752 0 100.776 0.084 ;
    END
  END q[906]
  PIN q[907]
    DIRECTION OUTPUT ;
    USE SIGNAL ;
    PORT
      LAYER M5 ;
        RECT  100.848 0 100.872 0.084 ;
    END
  END q[907]
  PIN q[908]
    DIRECTION OUTPUT ;
    USE SIGNAL ;
    PORT
      LAYER M5 ;
        RECT  100.944 0 100.968 0.084 ;
    END
  END q[908]
  PIN q[909]
    DIRECTION OUTPUT ;
    USE SIGNAL ;
    PORT
      LAYER M5 ;
        RECT  101.04 0 101.064 0.084 ;
    END
  END q[909]
  PIN q[90]
    DIRECTION OUTPUT ;
    USE SIGNAL ;
    PORT
      LAYER M5 ;
        RECT  47.76 0 47.784 0.084 ;
    END
  END q[90]
  PIN q[910]
    DIRECTION OUTPUT ;
    USE SIGNAL ;
    PORT
      LAYER M5 ;
        RECT  101.136 0 101.16 0.084 ;
    END
  END q[910]
  PIN q[911]
    DIRECTION OUTPUT ;
    USE SIGNAL ;
    PORT
      LAYER M5 ;
        RECT  101.232 0 101.256 0.084 ;
    END
  END q[911]
  PIN q[912]
    DIRECTION OUTPUT ;
    USE SIGNAL ;
    PORT
      LAYER M5 ;
        RECT  101.328 0 101.352 0.084 ;
    END
  END q[912]
  PIN q[913]
    DIRECTION OUTPUT ;
    USE SIGNAL ;
    PORT
      LAYER M5 ;
        RECT  101.424 0 101.448 0.084 ;
    END
  END q[913]
  PIN q[914]
    DIRECTION OUTPUT ;
    USE SIGNAL ;
    PORT
      LAYER M5 ;
        RECT  101.52 0 101.544 0.084 ;
    END
  END q[914]
  PIN q[915]
    DIRECTION OUTPUT ;
    USE SIGNAL ;
    PORT
      LAYER M5 ;
        RECT  101.616 0 101.64 0.084 ;
    END
  END q[915]
  PIN q[916]
    DIRECTION OUTPUT ;
    USE SIGNAL ;
    PORT
      LAYER M5 ;
        RECT  101.712 0 101.736 0.084 ;
    END
  END q[916]
  PIN q[917]
    DIRECTION OUTPUT ;
    USE SIGNAL ;
    PORT
      LAYER M5 ;
        RECT  101.808 0 101.832 0.084 ;
    END
  END q[917]
  PIN q[918]
    DIRECTION OUTPUT ;
    USE SIGNAL ;
    PORT
      LAYER M5 ;
        RECT  101.904 0 101.928 0.084 ;
    END
  END q[918]
  PIN q[919]
    DIRECTION OUTPUT ;
    USE SIGNAL ;
    PORT
      LAYER M5 ;
        RECT  102 0 102.024 0.084 ;
    END
  END q[919]
  PIN q[91]
    DIRECTION OUTPUT ;
    USE SIGNAL ;
    PORT
      LAYER M5 ;
        RECT  47.856 0 47.88 0.084 ;
    END
  END q[91]
  PIN q[920]
    DIRECTION OUTPUT ;
    USE SIGNAL ;
    PORT
      LAYER M5 ;
        RECT  102.096 0 102.12 0.084 ;
    END
  END q[920]
  PIN q[921]
    DIRECTION OUTPUT ;
    USE SIGNAL ;
    PORT
      LAYER M5 ;
        RECT  102.192 0 102.216 0.084 ;
    END
  END q[921]
  PIN q[922]
    DIRECTION OUTPUT ;
    USE SIGNAL ;
    PORT
      LAYER M5 ;
        RECT  102.288 0 102.312 0.084 ;
    END
  END q[922]
  PIN q[923]
    DIRECTION OUTPUT ;
    USE SIGNAL ;
    PORT
      LAYER M5 ;
        RECT  102.384 0 102.408 0.084 ;
    END
  END q[923]
  PIN q[924]
    DIRECTION OUTPUT ;
    USE SIGNAL ;
    PORT
      LAYER M5 ;
        RECT  102.48 0 102.504 0.084 ;
    END
  END q[924]
  PIN q[925]
    DIRECTION OUTPUT ;
    USE SIGNAL ;
    PORT
      LAYER M5 ;
        RECT  102.576 0 102.6 0.084 ;
    END
  END q[925]
  PIN q[926]
    DIRECTION OUTPUT ;
    USE SIGNAL ;
    PORT
      LAYER M5 ;
        RECT  102.672 0 102.696 0.084 ;
    END
  END q[926]
  PIN q[927]
    DIRECTION OUTPUT ;
    USE SIGNAL ;
    PORT
      LAYER M5 ;
        RECT  102.768 0 102.792 0.084 ;
    END
  END q[927]
  PIN q[928]
    DIRECTION OUTPUT ;
    USE SIGNAL ;
    PORT
      LAYER M5 ;
        RECT  13.008 0 13.032 0.084 ;
    END
  END q[928]
  PIN q[929]
    DIRECTION OUTPUT ;
    USE SIGNAL ;
    PORT
      LAYER M5 ;
        RECT  13.104 0 13.128 0.084 ;
    END
  END q[929]
  PIN q[92]
    DIRECTION OUTPUT ;
    USE SIGNAL ;
    PORT
      LAYER M5 ;
        RECT  47.952 0 47.976 0.084 ;
    END
  END q[92]
  PIN q[930]
    DIRECTION OUTPUT ;
    USE SIGNAL ;
    PORT
      LAYER M5 ;
        RECT  13.2 0 13.224 0.084 ;
    END
  END q[930]
  PIN q[931]
    DIRECTION OUTPUT ;
    USE SIGNAL ;
    PORT
      LAYER M5 ;
        RECT  13.296 0 13.32 0.084 ;
    END
  END q[931]
  PIN q[932]
    DIRECTION OUTPUT ;
    USE SIGNAL ;
    PORT
      LAYER M5 ;
        RECT  13.392 0 13.416 0.084 ;
    END
  END q[932]
  PIN q[933]
    DIRECTION OUTPUT ;
    USE SIGNAL ;
    PORT
      LAYER M5 ;
        RECT  13.488 0 13.512 0.084 ;
    END
  END q[933]
  PIN q[934]
    DIRECTION OUTPUT ;
    USE SIGNAL ;
    PORT
      LAYER M5 ;
        RECT  13.584 0 13.608 0.084 ;
    END
  END q[934]
  PIN q[935]
    DIRECTION OUTPUT ;
    USE SIGNAL ;
    PORT
      LAYER M5 ;
        RECT  13.68 0 13.704 0.084 ;
    END
  END q[935]
  PIN q[936]
    DIRECTION OUTPUT ;
    USE SIGNAL ;
    PORT
      LAYER M5 ;
        RECT  13.776 0 13.8 0.084 ;
    END
  END q[936]
  PIN q[937]
    DIRECTION OUTPUT ;
    USE SIGNAL ;
    PORT
      LAYER M5 ;
        RECT  13.872 0 13.896 0.084 ;
    END
  END q[937]
  PIN q[938]
    DIRECTION OUTPUT ;
    USE SIGNAL ;
    PORT
      LAYER M5 ;
        RECT  13.968 0 13.992 0.084 ;
    END
  END q[938]
  PIN q[939]
    DIRECTION OUTPUT ;
    USE SIGNAL ;
    PORT
      LAYER M5 ;
        RECT  14.064 0 14.088 0.084 ;
    END
  END q[939]
  PIN q[93]
    DIRECTION OUTPUT ;
    USE SIGNAL ;
    PORT
      LAYER M5 ;
        RECT  48.048 0 48.072 0.084 ;
    END
  END q[93]
  PIN q[940]
    DIRECTION OUTPUT ;
    USE SIGNAL ;
    PORT
      LAYER M5 ;
        RECT  14.16 0 14.184 0.084 ;
    END
  END q[940]
  PIN q[941]
    DIRECTION OUTPUT ;
    USE SIGNAL ;
    PORT
      LAYER M5 ;
        RECT  14.256 0 14.28 0.084 ;
    END
  END q[941]
  PIN q[942]
    DIRECTION OUTPUT ;
    USE SIGNAL ;
    PORT
      LAYER M5 ;
        RECT  14.352 0 14.376 0.084 ;
    END
  END q[942]
  PIN q[943]
    DIRECTION OUTPUT ;
    USE SIGNAL ;
    PORT
      LAYER M5 ;
        RECT  14.448 0 14.472 0.084 ;
    END
  END q[943]
  PIN q[944]
    DIRECTION OUTPUT ;
    USE SIGNAL ;
    PORT
      LAYER M5 ;
        RECT  14.544 0 14.568 0.084 ;
    END
  END q[944]
  PIN q[945]
    DIRECTION OUTPUT ;
    USE SIGNAL ;
    PORT
      LAYER M5 ;
        RECT  14.64 0 14.664 0.084 ;
    END
  END q[945]
  PIN q[946]
    DIRECTION OUTPUT ;
    USE SIGNAL ;
    PORT
      LAYER M5 ;
        RECT  14.736 0 14.76 0.084 ;
    END
  END q[946]
  PIN q[947]
    DIRECTION OUTPUT ;
    USE SIGNAL ;
    PORT
      LAYER M5 ;
        RECT  14.832 0 14.856 0.084 ;
    END
  END q[947]
  PIN q[948]
    DIRECTION OUTPUT ;
    USE SIGNAL ;
    PORT
      LAYER M5 ;
        RECT  14.928 0 14.952 0.084 ;
    END
  END q[948]
  PIN q[949]
    DIRECTION OUTPUT ;
    USE SIGNAL ;
    PORT
      LAYER M5 ;
        RECT  15.024 0 15.048 0.084 ;
    END
  END q[949]
  PIN q[94]
    DIRECTION OUTPUT ;
    USE SIGNAL ;
    PORT
      LAYER M5 ;
        RECT  48.144 0 48.168 0.084 ;
    END
  END q[94]
  PIN q[950]
    DIRECTION OUTPUT ;
    USE SIGNAL ;
    PORT
      LAYER M5 ;
        RECT  15.12 0 15.144 0.084 ;
    END
  END q[950]
  PIN q[951]
    DIRECTION OUTPUT ;
    USE SIGNAL ;
    PORT
      LAYER M5 ;
        RECT  15.216 0 15.24 0.084 ;
    END
  END q[951]
  PIN q[952]
    DIRECTION OUTPUT ;
    USE SIGNAL ;
    PORT
      LAYER M5 ;
        RECT  15.312 0 15.336 0.084 ;
    END
  END q[952]
  PIN q[953]
    DIRECTION OUTPUT ;
    USE SIGNAL ;
    PORT
      LAYER M5 ;
        RECT  15.408 0 15.432 0.084 ;
    END
  END q[953]
  PIN q[954]
    DIRECTION OUTPUT ;
    USE SIGNAL ;
    PORT
      LAYER M5 ;
        RECT  15.504 0 15.528 0.084 ;
    END
  END q[954]
  PIN q[955]
    DIRECTION OUTPUT ;
    USE SIGNAL ;
    PORT
      LAYER M5 ;
        RECT  15.6 0 15.624 0.084 ;
    END
  END q[955]
  PIN q[956]
    DIRECTION OUTPUT ;
    USE SIGNAL ;
    PORT
      LAYER M5 ;
        RECT  15.696 0 15.72 0.084 ;
    END
  END q[956]
  PIN q[957]
    DIRECTION OUTPUT ;
    USE SIGNAL ;
    PORT
      LAYER M5 ;
        RECT  15.792 0 15.816 0.084 ;
    END
  END q[957]
  PIN q[958]
    DIRECTION OUTPUT ;
    USE SIGNAL ;
    PORT
      LAYER M5 ;
        RECT  15.888 0 15.912 0.084 ;
    END
  END q[958]
  PIN q[959]
    DIRECTION OUTPUT ;
    USE SIGNAL ;
    PORT
      LAYER M5 ;
        RECT  15.984 0 16.008 0.084 ;
    END
  END q[959]
  PIN q[95]
    DIRECTION OUTPUT ;
    USE SIGNAL ;
    PORT
      LAYER M5 ;
        RECT  48.24 0 48.264 0.084 ;
    END
  END q[95]
  PIN q[960]
    DIRECTION OUTPUT ;
    USE SIGNAL ;
    PORT
      LAYER M5 ;
        RECT  16.08 0 16.104 0.084 ;
    END
  END q[960]
  PIN q[961]
    DIRECTION OUTPUT ;
    USE SIGNAL ;
    PORT
      LAYER M5 ;
        RECT  16.176 0 16.2 0.084 ;
    END
  END q[961]
  PIN q[962]
    DIRECTION OUTPUT ;
    USE SIGNAL ;
    PORT
      LAYER M5 ;
        RECT  16.272 0 16.296 0.084 ;
    END
  END q[962]
  PIN q[963]
    DIRECTION OUTPUT ;
    USE SIGNAL ;
    PORT
      LAYER M5 ;
        RECT  16.368 0 16.392 0.084 ;
    END
  END q[963]
  PIN q[964]
    DIRECTION OUTPUT ;
    USE SIGNAL ;
    PORT
      LAYER M5 ;
        RECT  16.464 0 16.488 0.084 ;
    END
  END q[964]
  PIN q[965]
    DIRECTION OUTPUT ;
    USE SIGNAL ;
    PORT
      LAYER M5 ;
        RECT  16.56 0 16.584 0.084 ;
    END
  END q[965]
  PIN q[966]
    DIRECTION OUTPUT ;
    USE SIGNAL ;
    PORT
      LAYER M5 ;
        RECT  16.656 0 16.68 0.084 ;
    END
  END q[966]
  PIN q[967]
    DIRECTION OUTPUT ;
    USE SIGNAL ;
    PORT
      LAYER M5 ;
        RECT  16.752 0 16.776 0.084 ;
    END
  END q[967]
  PIN q[968]
    DIRECTION OUTPUT ;
    USE SIGNAL ;
    PORT
      LAYER M5 ;
        RECT  16.848 0 16.872 0.084 ;
    END
  END q[968]
  PIN q[969]
    DIRECTION OUTPUT ;
    USE SIGNAL ;
    PORT
      LAYER M5 ;
        RECT  16.944 0 16.968 0.084 ;
    END
  END q[969]
  PIN q[96]
    DIRECTION OUTPUT ;
    USE SIGNAL ;
    PORT
      LAYER M5 ;
        RECT  73.68 0 73.704 0.084 ;
    END
  END q[96]
  PIN q[970]
    DIRECTION OUTPUT ;
    USE SIGNAL ;
    PORT
      LAYER M5 ;
        RECT  17.04 0 17.064 0.084 ;
    END
  END q[970]
  PIN q[971]
    DIRECTION OUTPUT ;
    USE SIGNAL ;
    PORT
      LAYER M5 ;
        RECT  17.136 0 17.16 0.084 ;
    END
  END q[971]
  PIN q[972]
    DIRECTION OUTPUT ;
    USE SIGNAL ;
    PORT
      LAYER M5 ;
        RECT  17.232 0 17.256 0.084 ;
    END
  END q[972]
  PIN q[973]
    DIRECTION OUTPUT ;
    USE SIGNAL ;
    PORT
      LAYER M5 ;
        RECT  17.328 0 17.352 0.084 ;
    END
  END q[973]
  PIN q[974]
    DIRECTION OUTPUT ;
    USE SIGNAL ;
    PORT
      LAYER M5 ;
        RECT  17.424 0 17.448 0.084 ;
    END
  END q[974]
  PIN q[975]
    DIRECTION OUTPUT ;
    USE SIGNAL ;
    PORT
      LAYER M5 ;
        RECT  17.52 0 17.544 0.084 ;
    END
  END q[975]
  PIN q[976]
    DIRECTION OUTPUT ;
    USE SIGNAL ;
    PORT
      LAYER M5 ;
        RECT  17.616 0 17.64 0.084 ;
    END
  END q[976]
  PIN q[977]
    DIRECTION OUTPUT ;
    USE SIGNAL ;
    PORT
      LAYER M5 ;
        RECT  17.712 0 17.736 0.084 ;
    END
  END q[977]
  PIN q[978]
    DIRECTION OUTPUT ;
    USE SIGNAL ;
    PORT
      LAYER M5 ;
        RECT  17.808 0 17.832 0.084 ;
    END
  END q[978]
  PIN q[979]
    DIRECTION OUTPUT ;
    USE SIGNAL ;
    PORT
      LAYER M5 ;
        RECT  17.904 0 17.928 0.084 ;
    END
  END q[979]
  PIN q[97]
    DIRECTION OUTPUT ;
    USE SIGNAL ;
    PORT
      LAYER M5 ;
        RECT  73.776 0 73.8 0.084 ;
    END
  END q[97]
  PIN q[980]
    DIRECTION OUTPUT ;
    USE SIGNAL ;
    PORT
      LAYER M5 ;
        RECT  18 0 18.024 0.084 ;
    END
  END q[980]
  PIN q[981]
    DIRECTION OUTPUT ;
    USE SIGNAL ;
    PORT
      LAYER M5 ;
        RECT  18.096 0 18.12 0.084 ;
    END
  END q[981]
  PIN q[982]
    DIRECTION OUTPUT ;
    USE SIGNAL ;
    PORT
      LAYER M5 ;
        RECT  18.192 0 18.216 0.084 ;
    END
  END q[982]
  PIN q[983]
    DIRECTION OUTPUT ;
    USE SIGNAL ;
    PORT
      LAYER M5 ;
        RECT  18.288 0 18.312 0.084 ;
    END
  END q[983]
  PIN q[984]
    DIRECTION OUTPUT ;
    USE SIGNAL ;
    PORT
      LAYER M5 ;
        RECT  18.384 0 18.408 0.084 ;
    END
  END q[984]
  PIN q[985]
    DIRECTION OUTPUT ;
    USE SIGNAL ;
    PORT
      LAYER M5 ;
        RECT  18.48 0 18.504 0.084 ;
    END
  END q[985]
  PIN q[986]
    DIRECTION OUTPUT ;
    USE SIGNAL ;
    PORT
      LAYER M5 ;
        RECT  18.576 0 18.6 0.084 ;
    END
  END q[986]
  PIN q[987]
    DIRECTION OUTPUT ;
    USE SIGNAL ;
    PORT
      LAYER M5 ;
        RECT  18.672 0 18.696 0.084 ;
    END
  END q[987]
  PIN q[988]
    DIRECTION OUTPUT ;
    USE SIGNAL ;
    PORT
      LAYER M5 ;
        RECT  18.768 0 18.792 0.084 ;
    END
  END q[988]
  PIN q[989]
    DIRECTION OUTPUT ;
    USE SIGNAL ;
    PORT
      LAYER M5 ;
        RECT  18.864 0 18.888 0.084 ;
    END
  END q[989]
  PIN q[98]
    DIRECTION OUTPUT ;
    USE SIGNAL ;
    PORT
      LAYER M5 ;
        RECT  73.872 0 73.896 0.084 ;
    END
  END q[98]
  PIN q[990]
    DIRECTION OUTPUT ;
    USE SIGNAL ;
    PORT
      LAYER M5 ;
        RECT  18.96 0 18.984 0.084 ;
    END
  END q[990]
  PIN q[991]
    DIRECTION OUTPUT ;
    USE SIGNAL ;
    PORT
      LAYER M5 ;
        RECT  19.056 0 19.08 0.084 ;
    END
  END q[991]
  PIN q[992]
    DIRECTION OUTPUT ;
    USE SIGNAL ;
    PORT
      LAYER M5 ;
        RECT  9.936 0 9.96 0.084 ;
    END
  END q[992]
  PIN q[993]
    DIRECTION OUTPUT ;
    USE SIGNAL ;
    PORT
      LAYER M5 ;
        RECT  10.032 0 10.056 0.084 ;
    END
  END q[993]
  PIN q[994]
    DIRECTION OUTPUT ;
    USE SIGNAL ;
    PORT
      LAYER M5 ;
        RECT  10.128 0 10.152 0.084 ;
    END
  END q[994]
  PIN q[995]
    DIRECTION OUTPUT ;
    USE SIGNAL ;
    PORT
      LAYER M5 ;
        RECT  10.224 0 10.248 0.084 ;
    END
  END q[995]
  PIN q[996]
    DIRECTION OUTPUT ;
    USE SIGNAL ;
    PORT
      LAYER M5 ;
        RECT  10.32 0 10.344 0.084 ;
    END
  END q[996]
  PIN q[997]
    DIRECTION OUTPUT ;
    USE SIGNAL ;
    PORT
      LAYER M5 ;
        RECT  10.416 0 10.44 0.084 ;
    END
  END q[997]
  PIN q[998]
    DIRECTION OUTPUT ;
    USE SIGNAL ;
    PORT
      LAYER M5 ;
        RECT  10.512 0 10.536 0.084 ;
    END
  END q[998]
  PIN q[999]
    DIRECTION OUTPUT ;
    USE SIGNAL ;
    PORT
      LAYER M5 ;
        RECT  10.608 0 10.632 0.084 ;
    END
  END q[999]
  PIN q[99]
    DIRECTION OUTPUT ;
    USE SIGNAL ;
    PORT
      LAYER M5 ;
        RECT  73.968 0 73.992 0.084 ;
    END
  END q[99]
  PIN q[9]
    DIRECTION OUTPUT ;
    USE SIGNAL ;
    PORT
      LAYER M5 ;
        RECT  68.4 0 68.424 0.084 ;
    END
  END q[9]
  PIN VDD
    DIRECTION INOUT ;
    USE POWER ;
    PORT
      LAYER M5 ;
        RECT  110.592 2.151 110.712 15.129 ;
        RECT  105.192 2.151 105.312 15.129 ;
        RECT  99.792 2.151 99.912 15.129 ;
        RECT  94.392 2.151 94.512 15.129 ;
        RECT  88.992 2.151 89.112 15.129 ;
        RECT  83.592 2.151 83.712 15.129 ;
        RECT  78.192 2.151 78.312 15.129 ;
        RECT  72.792 2.151 72.912 15.129 ;
        RECT  67.392 2.151 67.512 15.129 ;
        RECT  61.992 2.151 62.112 15.129 ;
        RECT  56.592 2.151 56.712 15.129 ;
        RECT  51.192 2.151 51.312 15.129 ;
        RECT  45.792 2.151 45.912 15.129 ;
        RECT  40.392 2.151 40.512 15.129 ;
        RECT  34.992 2.151 35.112 15.129 ;
        RECT  29.592 2.151 29.712 15.129 ;
        RECT  24.192 2.151 24.312 15.129 ;
        RECT  18.792 2.151 18.912 15.129 ;
        RECT  13.392 2.151 13.512 15.129 ;
        RECT  7.992 2.151 8.112 15.129 ;
        RECT  2.592 2.151 2.712 15.129 ;
    END
  END VDD
  PIN VSS
    DIRECTION INOUT ;
    USE GROUND ;
    PORT
      LAYER M5 ;
        RECT  110.4 2.137 110.52 15.143 ;
        RECT  105 2.137 105.12 15.143 ;
        RECT  99.6 2.137 99.72 15.143 ;
        RECT  94.2 2.137 94.32 15.143 ;
        RECT  88.8 2.137 88.92 15.143 ;
        RECT  83.4 2.137 83.52 15.143 ;
        RECT  78 2.137 78.12 15.143 ;
        RECT  72.6 2.137 72.72 15.143 ;
        RECT  67.2 2.137 67.32 15.143 ;
        RECT  61.8 2.137 61.92 15.143 ;
        RECT  56.4 2.137 56.52 15.143 ;
        RECT  51 2.137 51.12 15.143 ;
        RECT  45.6 2.137 45.72 15.143 ;
        RECT  40.2 2.137 40.32 15.143 ;
        RECT  34.8 2.137 34.92 15.143 ;
        RECT  29.4 2.137 29.52 15.143 ;
        RECT  24 2.137 24.12 15.143 ;
        RECT  18.6 2.137 18.72 15.143 ;
        RECT  13.2 2.137 13.32 15.143 ;
        RECT  7.8 2.137 7.92 15.143 ;
        RECT  2.4 2.137 2.52 15.143 ;
    END
  END VSS
  OBS
    LAYER RVTN ;
     RECT  2.16 2.16 114.48 2.295 ;
     RECT  2.16 2.565 114.48 2.835 ;
     RECT  2.16 3.105 114.48 3.375 ;
     RECT  2.16 3.645 114.48 3.915 ;
     RECT  2.16 4.185 114.48 4.455 ;
     RECT  2.16 4.725 114.48 4.995 ;
     RECT  2.16 5.265 114.48 5.535 ;
     RECT  2.16 5.805 114.48 6.075 ;
     RECT  2.16 6.345 114.48 6.615 ;
     RECT  2.16 6.885 114.48 7.155 ;
     RECT  2.16 7.425 114.48 7.695 ;
     RECT  2.16 7.965 114.48 8.235 ;
     RECT  2.16 8.505 114.48 8.775 ;
     RECT  2.16 9.045 114.48 9.315 ;
     RECT  2.16 9.585 114.48 9.855 ;
     RECT  2.16 10.125 114.48 10.395 ;
     RECT  2.16 10.665 114.48 10.935 ;
     RECT  2.16 11.205 114.48 11.475 ;
     RECT  2.16 11.745 114.48 12.015 ;
     RECT  2.16 12.285 114.48 12.555 ;
     RECT  2.16 12.825 114.48 13.095 ;
     RECT  2.16 13.365 114.48 13.635 ;
     RECT  2.16 13.905 114.48 14.175 ;
     RECT  2.16 14.445 114.48 14.715 ;
     RECT  2.16 14.985 114.48 15.12 ;
    LAYER RVTP ;
     RECT  2.16 2.295 114.48 2.565 ;
     RECT  2.16 2.835 114.48 3.105 ;
     RECT  2.16 3.375 114.48 3.645 ;
     RECT  2.16 3.915 114.48 4.185 ;
     RECT  2.16 4.455 114.48 4.725 ;
     RECT  2.16 4.995 114.48 5.265 ;
     RECT  2.16 5.535 114.48 5.805 ;
     RECT  2.16 6.075 114.48 6.345 ;
     RECT  2.16 6.615 114.48 6.885 ;
     RECT  2.16 7.155 114.48 7.425 ;
     RECT  2.16 7.695 114.48 7.965 ;
     RECT  2.16 8.235 114.48 8.505 ;
     RECT  2.16 8.775 114.48 9.045 ;
     RECT  2.16 9.315 114.48 9.585 ;
     RECT  2.16 9.855 114.48 10.125 ;
     RECT  2.16 10.395 114.48 10.665 ;
     RECT  2.16 10.935 114.48 11.205 ;
     RECT  2.16 11.475 114.48 11.745 ;
     RECT  2.16 12.015 114.48 12.285 ;
     RECT  2.16 12.555 114.48 12.825 ;
     RECT  2.16 13.095 114.48 13.365 ;
     RECT  2.16 13.635 114.48 13.905 ;
     RECT  2.16 14.175 114.48 14.445 ;
     RECT  2.16 14.715 114.48 14.985 ;
    LAYER M1 ;
     RECT  2.16 2.151 114.48 15.129 ;
    LAYER M2 ;
     RECT  2.16 2.151 9.859 15.129 ;
     RECT  9.895 1.152 9.995 1.17 ;
     RECT  9.859 2.106 10.427 15.129 ;
     RECT  11.515 1.152 11.731 1.17 ;
     RECT  11.731 1.152 11.795 1.242 ;
     RECT  11.795 1.224 11.831 1.242 ;
     RECT  10.427 2.151 12.559 15.129 ;
     RECT  12.559 2.106 13.099 15.129 ;
     RECT  13.099 2.07 13.199 15.129 ;
     RECT  13.199 2.106 13.963 15.129 ;
     RECT  13.963 2.034 14.567 15.129 ;
     RECT  14.567 2.151 21.091 15.129 ;
     RECT  21.091 2.106 21.343 15.129 ;
     RECT  21.559 1.152 21.911 1.17 ;
     RECT  21.343 2.034 22.027 15.129 ;
     RECT  22.027 1.962 22.343 15.129 ;
     RECT  22.343 2.106 23.935 15.129 ;
     RECT  23.935 1.728 24.431 15.129 ;
     RECT  24.431 2.151 25.015 15.129 ;
     RECT  18.211 16.236 25.015 16.254 ;
     RECT  18.679 17.19 25.123 17.208 ;
     RECT  25.015 2.151 25.519 16.254 ;
     RECT  25.519 2.106 25.627 16.254 ;
     RECT  25.627 2.106 25.699 16.362 ;
     RECT  25.699 1.962 26.699 16.362 ;
     RECT  26.699 2.034 27.743 16.362 ;
     RECT  27.743 2.106 28.759 16.362 ;
     RECT  29.767 1.152 29.903 1.17 ;
     RECT  30.091 0.144 30.299 0.162 ;
     RECT  28.759 1.998 32.395 16.362 ;
     RECT  32.647 1.152 32.747 1.17 ;
     RECT  25.123 17.19 32.999 17.244 ;
     RECT  32.395 1.962 33.151 16.362 ;
     RECT  33.151 1.836 33.323 16.362 ;
     RECT  33.323 1.881 33.511 16.362 ;
     RECT  33.511 1.881 33.755 16.434 ;
     RECT  33.755 1.962 34.223 16.434 ;
     RECT  34.223 1.998 34.987 16.434 ;
     RECT  32.999 17.19 34.987 17.208 ;
     RECT  36.535 1.152 36.671 1.17 ;
     RECT  34.987 1.998 36.679 17.208 ;
     RECT  36.679 1.998 36.887 17.244 ;
     RECT  36.887 1.998 37.031 17.208 ;
     RECT  37.031 2.034 37.319 17.208 ;
     RECT  37.319 2.034 39.695 16.434 ;
     RECT  39.695 2.106 42.763 16.434 ;
     RECT  42.763 1.962 45.031 16.434 ;
     RECT  37.319 17.19 45.031 17.208 ;
     RECT  45.031 1.962 48.947 17.208 ;
     RECT  48.947 2.106 49.855 17.208 ;
     RECT  49.855 2.106 50.027 17.244 ;
     RECT  50.027 2.106 50.963 16.362 ;
     RECT  50.963 2.106 51.827 16.326 ;
     RECT  51.827 2.106 52.331 16.29 ;
     RECT  52.331 2.151 53.015 16.29 ;
     RECT  50.027 17.19 53.447 17.244 ;
     RECT  53.015 2.151 54.895 15.669 ;
     RECT  54.895 1.962 58.703 15.669 ;
     RECT  58.703 2.106 59.467 15.669 ;
     RECT  59.467 2.034 60.683 15.669 ;
     RECT  60.683 2.106 61.547 15.669 ;
     RECT  61.547 2.151 61.555 15.669 ;
     RECT  61.555 2.151 62.347 15.858 ;
     RECT  62.347 2.151 63.247 16.254 ;
     RECT  63.247 2.106 63.751 16.254 ;
     RECT  53.447 17.226 65.119 17.244 ;
     RECT  63.751 2.106 65.471 16.29 ;
     RECT  65.119 17.118 65.507 17.244 ;
     RECT  65.471 2.151 66.883 16.29 ;
     RECT  66.883 2.106 67.631 16.29 ;
     RECT  67.631 2.151 68.359 16.29 ;
     RECT  68.359 2.106 69.007 16.29 ;
     RECT  65.507 17.226 69.007 17.244 ;
     RECT  69.007 2.106 69.503 17.244 ;
     RECT  69.043 1.152 69.971 1.17 ;
     RECT  69.503 2.106 70.267 16.29 ;
     RECT  69.503 17.154 70.547 17.244 ;
     RECT  70.267 1.962 72.995 16.29 ;
     RECT  73.219 1.152 73.463 1.17 ;
     RECT  75.271 1.152 75.515 1.17 ;
     RECT  70.547 17.226 75.739 17.244 ;
     RECT  75.739 17.046 76.127 17.244 ;
     RECT  72.995 2.106 76.135 16.29 ;
     RECT  76.135 2.07 76.415 16.29 ;
     RECT  76.415 2.106 78.691 16.29 ;
     RECT  76.127 17.226 78.691 17.244 ;
     RECT  78.691 2.106 78.899 17.244 ;
     RECT  78.899 2.106 78.907 16.29 ;
     RECT  78.907 1.998 79.267 16.29 ;
     RECT  79.267 1.962 80.231 16.29 ;
     RECT  80.231 1.998 80.339 16.29 ;
     RECT  80.339 2.07 80.843 16.29 ;
     RECT  80.843 2.106 82.283 16.29 ;
     RECT  82.283 2.151 83.227 16.29 ;
     RECT  83.227 2.106 83.399 16.29 ;
     RECT  83.399 2.151 86.503 16.29 ;
     RECT  86.503 2.106 86.675 16.29 ;
     RECT  86.675 2.151 87.899 16.29 ;
     RECT  87.899 16.272 87.935 16.29 ;
     RECT  87.899 2.151 90.031 15.129 ;
     RECT  78.899 17.226 90.095 17.244 ;
     RECT  90.031 2.106 90.563 15.129 ;
     RECT  90.563 2.151 91.327 15.129 ;
     RECT  91.327 2.034 92.191 15.129 ;
     RECT  92.191 2.034 92.515 15.282 ;
     RECT  92.515 1.998 93.191 15.282 ;
     RECT  93.739 1.152 93.947 1.17 ;
     RECT  93.191 2.034 93.955 15.282 ;
     RECT  93.955 1.728 94.415 15.282 ;
     RECT  94.415 1.728 96.287 15.129 ;
     RECT  96.287 2.034 96.935 15.129 ;
     RECT  96.935 2.151 102.595 15.129 ;
     RECT  102.595 2.151 104.495 15.246 ;
     RECT  104.495 2.151 105.475 15.129 ;
     RECT  105.475 2.106 105.511 15.129 ;
     RECT  105.511 2.07 106.259 15.129 ;
     RECT  106.259 2.106 107.023 15.129 ;
     RECT  107.023 2.034 107.483 15.129 ;
     RECT  107.483 2.106 107.771 15.129 ;
     RECT  107.771 2.151 108.175 15.129 ;
     RECT  108.175 2.151 108.815 15.174 ;
     RECT  108.815 2.151 114.48 15.129 ;
    LAYER M3 ;
     RECT  89.316 0.043 89.334 0.091 ;
     RECT  93.924 0.043 93.942 0.091 ;
     RECT  99.108 0.043 99.126 0.091 ;
     RECT  21.384 0.091 21.402 0.139 ;
     RECT  22.5 0.091 22.518 0.139 ;
     RECT  23.544 0.091 23.562 0.139 ;
     RECT  29.304 0.091 29.322 0.139 ;
     RECT  30.168 0.091 31.482 0.139 ;
     RECT  33.336 0.091 33.354 0.139 ;
     RECT  52.74 0.043 52.758 0.139 ;
     RECT  53.568 0.091 53.586 0.139 ;
     RECT  58.536 0.091 58.554 0.139 ;
     RECT  78.84 0.091 78.858 0.139 ;
     RECT  79.704 0.091 79.722 0.139 ;
     RECT  98.1 0.091 99.126 0.139 ;
     RECT  100.548 0.091 100.998 0.139 ;
     RECT  106.956 0.091 106.974 0.139 ;
     RECT  52.056 0.139 53.586 0.173 ;
     RECT  97.416 0.139 99.126 0.173 ;
     RECT  13.932 0.091 15.066 0.187 ;
     RECT  15.804 0.091 16.218 0.187 ;
     RECT  23.472 0.139 23.562 0.187 ;
     RECT  33.192 0.139 33.354 0.187 ;
     RECT  34.164 0.091 34.182 0.187 ;
     RECT  35.568 0.091 35.586 0.187 ;
     RECT  48.744 0.091 48.762 0.187 ;
     RECT  49.5 0.091 50.058 0.187 ;
     RECT  52.056 0.173 52.434 0.187 ;
     RECT  60.336 0.091 60.642 0.187 ;
     RECT  61.56 0.091 64.314 0.187 ;
     RECT  109.188 0.091 111.906 0.187 ;
     RECT  29.232 0.139 29.322 0.235 ;
     RECT  30.096 0.139 31.482 0.235 ;
     RECT  82.548 0.091 83.25 0.235 ;
     RECT  84.168 0.091 84.726 0.235 ;
     RECT  93.924 0.091 94.77 0.235 ;
     RECT  40.716 0.091 40.734 0.269 ;
     RECT  82.548 0.235 84.726 0.269 ;
     RECT  29.232 0.235 32.094 0.283 ;
     RECT  33.192 0.187 34.182 0.283 ;
     RECT  69.768 0.091 70.866 0.427 ;
     RECT  96.264 0.187 96.282 0.427 ;
     RECT  100.548 0.139 101.286 0.475 ;
     RECT  17.604 0.091 17.622 0.523 ;
     RECT  18.576 0.091 19.062 0.523 ;
     RECT  35.568 0.187 35.622 0.523 ;
     RECT  65.376 0.091 65.394 0.523 ;
     RECT  67.968 0.139 67.986 0.523 ;
     RECT  68.724 0.091 68.742 0.523 ;
     RECT  69.732 0.427 70.866 0.523 ;
     RECT  86.724 0.091 89.334 0.523 ;
     RECT  9.972 0.523 9.99 0.571 ;
     RECT  10.764 0.523 10.782 0.571 ;
     RECT  13.932 0.187 16.218 0.571 ;
     RECT  16.956 0.523 17.622 0.571 ;
     RECT  18.504 0.523 19.062 0.571 ;
     RECT  29.232 0.283 34.182 0.571 ;
     RECT  35.208 0.523 35.622 0.571 ;
     RECT  42.516 0.091 43.686 0.571 ;
     RECT  44.712 0.091 44.73 0.571 ;
     RECT  45.576 0.043 45.594 0.571 ;
     RECT  47.088 0.091 47.106 0.571 ;
     RECT  48.744 0.187 50.058 0.571 ;
     RECT  50.976 0.091 50.994 0.571 ;
     RECT  51.984 0.187 52.434 0.571 ;
     RECT  67.788 0.523 68.742 0.571 ;
     RECT  69.696 0.523 70.866 0.571 ;
     RECT  76.572 0.091 76.59 0.571 ;
     RECT  78.84 0.139 79.722 0.571 ;
     RECT  81.18 0.091 81.198 0.571 ;
     RECT  85.824 0.043 85.842 0.571 ;
     RECT  86.724 0.523 89.73 0.571 ;
     RECT  90.9 0.091 91.242 0.571 ;
     RECT  92.448 0.091 92.466 0.571 ;
     RECT  93.924 0.235 94.878 0.571 ;
     RECT  96.264 0.427 96.642 0.571 ;
     RECT  97.416 0.173 98.838 0.571 ;
     RECT  100.224 0.475 101.286 0.571 ;
     RECT  102.78 0.091 102.798 0.571 ;
     RECT  103.932 0.091 103.95 0.571 ;
     RECT  106.056 0.139 106.974 0.571 ;
     RECT  109.044 0.187 111.906 0.571 ;
     RECT  36.54 0.571 36.558 0.619 ;
     RECT  37.404 0.091 37.422 0.619 ;
     RECT  40.356 0.571 40.374 0.619 ;
     RECT  67.536 0.571 71.262 0.619 ;
     RECT  90.468 0.571 91.314 0.811 ;
     RECT  11.772 0.091 11.79 1.099 ;
     RECT  53.208 0.173 53.586 1.099 ;
     RECT  72.756 0.091 73.746 1.099 ;
     RECT  76.392 0.571 76.59 1.099 ;
     RECT  100.044 0.571 101.286 1.099 ;
     RECT  102.312 0.571 104.238 1.099 ;
     RECT  9.972 0.571 10.782 1.147 ;
     RECT  11.736 1.099 11.79 1.147 ;
     RECT  13.176 0.571 16.218 1.147 ;
     RECT  29.232 0.571 35.622 1.147 ;
     RECT  58.464 0.139 58.554 1.147 ;
     RECT  65.34 0.523 65.394 1.147 ;
     RECT  72.756 1.099 74.034 1.147 ;
     RECT  75.132 0.091 75.402 1.147 ;
     RECT  76.176 1.099 76.59 1.147 ;
     RECT  92.448 0.571 94.878 1.147 ;
     RECT  96.264 0.571 98.838 1.147 ;
     RECT  100.044 1.099 104.238 1.147 ;
     RECT  20.124 1.147 20.142 1.195 ;
     RECT  9.9 1.147 11.79 1.219 ;
     RECT  12.816 1.147 16.218 1.243 ;
     RECT  58.392 1.147 58.554 1.387 ;
     RECT  90.468 0.811 91.638 1.387 ;
     RECT  92.448 1.147 104.238 1.387 ;
     RECT  23.4 0.187 23.562 1.579 ;
     RECT  60.336 0.187 64.314 1.675 ;
     RECT  9.9 1.219 11.826 1.723 ;
     RECT  12.636 1.243 16.218 1.723 ;
     RECT  16.956 0.571 19.062 1.723 ;
     RECT  20.124 1.195 20.43 1.723 ;
     RECT  21.384 0.139 22.518 1.723 ;
     RECT  23.4 1.579 23.958 1.723 ;
     RECT  25.164 1.099 25.182 1.723 ;
     RECT  26.712 0.091 27.27 1.723 ;
     RECT  28.476 1.147 35.622 1.723 ;
     RECT  36.54 0.619 37.422 1.723 ;
     RECT  40.14 0.619 40.374 1.723 ;
     RECT  42.048 0.571 52.434 1.723 ;
     RECT  53.208 1.099 53.694 1.723 ;
     RECT  55.512 0.571 55.53 1.723 ;
     RECT  58.32 1.387 58.554 1.723 ;
     RECT  59.724 1.675 64.314 1.723 ;
     RECT  65.34 1.147 65.97 1.723 ;
     RECT  67.464 0.619 71.442 1.723 ;
     RECT  72.756 1.147 76.59 1.723 ;
     RECT  77.868 0.571 77.886 1.723 ;
     RECT  78.84 0.571 80.334 1.723 ;
     RECT  81.18 0.571 81.414 1.723 ;
     RECT  83.232 0.269 84.726 1.723 ;
     RECT  85.824 0.571 89.73 1.723 ;
     RECT  90.468 1.387 104.238 1.723 ;
     RECT  105.84 0.571 111.906 1.723 ;
     RECT  20.124 1.723 24.426 1.771 ;
     RECT  25.164 1.723 56.826 1.771 ;
     RECT  58.032 1.723 76.698 1.771 ;
     RECT  77.868 1.723 81.486 1.771 ;
     RECT  20.124 1.771 56.826 1.819 ;
     RECT  57.636 1.771 76.698 1.819 ;
     RECT  9.9 1.723 19.134 2.101 ;
     RECT  82.728 1.723 112.122 2.101 ;
     RECT  77.76 1.771 81.486 2.155 ;
     RECT  82.26 2.101 112.122 2.155 ;
     RECT  9.864 2.101 19.134 2.219 ;
     RECT  20.124 1.819 76.698 2.219 ;
     RECT  77.76 2.155 112.122 2.219 ;
     RECT  20.124 2.219 76.59 2.227 ;
     RECT  2.415 2.143 2.505 2.413 ;
     RECT  7.815 2.143 7.905 2.413 ;
     RECT  9.9 2.219 19.062 2.489 ;
     RECT  77.76 2.219 111.978 2.489 ;
     RECT  99.144 2.489 111.906 2.597 ;
     RECT  99.396 2.597 111.906 2.669 ;
     RECT  99.468 2.669 111.906 2.759 ;
     RECT  19.8 2.227 76.59 3.001 ;
     RECT  77.76 2.489 98.37 3.001 ;
     RECT  9.9 2.489 19.026 3.029 ;
     RECT  9.9 3.029 18.99 3.299 ;
     RECT  19.8 3.001 98.37 3.299 ;
     RECT  9.9 3.299 18.954 3.883 ;
     RECT  19.8 3.299 98.334 3.911 ;
     RECT  97.452 3.911 98.334 3.947 ;
     RECT  19.8 3.911 96.642 3.955 ;
     RECT  99.468 2.759 111.834 3.955 ;
     RECT  9.684 3.883 18.954 3.991 ;
     RECT  19.728 3.955 96.642 4.109 ;
     RECT  97.452 3.947 98.118 4.379 ;
     RECT  98.1 4.379 98.118 4.487 ;
     RECT  9.432 3.991 18.954 4.531 ;
     RECT  19.728 4.109 96.606 4.531 ;
     RECT  9.432 4.531 96.606 4.733 ;
     RECT  99.396 3.955 111.834 4.765 ;
     RECT  99.072 4.765 111.834 5.341 ;
     RECT  97.992 5.341 111.834 5.369 ;
     RECT  97.992 5.369 111.762 5.459 ;
     RECT  97.992 5.459 111.582 5.597 ;
     RECT  19.656 4.733 96.606 5.639 ;
     RECT  97.992 5.597 98.01 5.639 ;
     RECT  99.072 5.597 111.582 7.393 ;
     RECT  19.656 5.639 96.39 7.619 ;
     RECT  99 7.393 111.582 7.619 ;
     RECT  9.432 4.733 18.897 7.627 ;
     RECT  99 7.619 111.51 7.889 ;
     RECT  99 7.889 111.438 7.933 ;
     RECT  20.592 7.619 96.39 8.429 ;
     RECT  9.036 7.627 18.897 8.437 ;
     RECT  9 8.437 18.897 8.477 ;
     RECT  98.712 7.933 111.438 8.609 ;
     RECT  20.7 8.429 96.39 8.699 ;
     RECT  98.784 8.609 111.438 8.699 ;
     RECT  20.88 8.699 96.39 8.779 ;
     RECT  20.88 8.779 96.678 8.879 ;
     RECT  21.096 8.879 96.678 9.437 ;
     RECT  34.632 9.437 96.678 9.509 ;
     RECT  98.784 8.699 110.97 9.509 ;
     RECT  21.096 9.437 33.858 10.165 ;
     RECT  34.632 9.509 96.39 10.165 ;
     RECT  21.096 10.165 96.39 10.205 ;
     RECT  21.096 10.205 33.678 10.319 ;
     RECT  21.096 10.319 33.642 10.435 ;
     RECT  98.82 9.509 110.97 10.471 ;
     RECT  34.416 10.205 96.39 10.733 ;
     RECT  98.604 10.471 110.97 10.843 ;
     RECT  97.956 10.843 110.97 10.859 ;
     RECT  20.844 10.435 33.642 10.895 ;
     RECT  97.956 10.859 110.697 10.975 ;
     RECT  20.844 10.895 33.534 11.003 ;
     RECT  9.036 8.477 18.897 11.245 ;
     RECT  19.656 7.619 19.71 11.471 ;
     RECT  34.776 10.733 96.39 11.677 ;
     RECT  34.596 11.677 96.39 11.741 ;
     RECT  20.844 11.003 25.434 11.785 ;
     RECT  26.28 11.003 33.534 11.785 ;
     RECT  34.704 11.741 96.39 11.849 ;
     RECT  8.856 11.245 18.897 11.911 ;
     RECT  7.815 2.413 8.097 11.947 ;
     RECT  8.82 11.911 18.897 11.947 ;
     RECT  19.656 11.471 19.674 12.119 ;
     RECT  34.776 11.849 96.39 12.991 ;
     RECT  20.844 11.785 33.534 13.243 ;
     RECT  34.704 12.991 96.39 13.289 ;
     RECT  20.844 13.243 33.57 13.333 ;
     RECT  34.704 13.289 80.298 13.333 ;
     RECT  7.815 11.947 18.897 13.559 ;
     RECT  17.892 13.559 18.897 13.675 ;
     RECT  17.892 13.675 18.954 13.771 ;
     RECT  20.844 13.333 80.298 13.829 ;
     RECT  17.892 13.771 18.99 13.901 ;
     RECT  17.892 13.901 18.897 14.099 ;
     RECT  97.668 10.975 110.697 14.215 ;
     RECT  20.88 13.829 80.298 14.299 ;
     RECT  81.072 13.289 96.39 14.299 ;
     RECT  20.88 14.299 96.39 14.369 ;
     RECT  20.124 14.347 20.142 14.405 ;
     RECT  81.036 14.369 96.39 14.485 ;
     RECT  20.88 14.369 79.866 14.513 ;
     RECT  7.815 13.559 17.046 14.639 ;
     RECT  81.036 14.485 96.678 14.639 ;
     RECT  20.88 14.513 79.002 14.711 ;
     RECT  7.815 14.639 17.01 14.755 ;
     RECT  2.415 2.413 2.697 14.867 ;
     RECT  17.928 14.099 18.897 14.867 ;
     RECT  81.036 14.639 96.57 14.867 ;
     RECT  97.56 14.215 110.697 14.867 ;
     RECT  7.776 14.755 17.01 14.909 ;
     RECT  20.88 14.711 78.678 14.909 ;
     RECT  89.784 14.867 96.57 14.909 ;
     RECT  89.784 14.909 96.426 14.981 ;
     RECT  7.776 14.909 16.83 15.019 ;
     RECT  97.56 14.867 110.505 15.025 ;
     RECT  81.036 14.867 88.905 15.053 ;
     RECT  20.88 14.909 24.678 15.089 ;
     RECT  79.848 14.513 79.866 15.101 ;
     RECT  90.36 14.981 96.426 15.101 ;
     RECT  97.488 15.025 110.505 15.101 ;
     RECT  2.415 14.867 2.505 15.137 ;
     RECT  17.928 14.867 18.705 15.137 ;
     RECT  20.88 15.089 24.105 15.137 ;
     RECT  81.252 15.053 88.905 15.137 ;
     RECT  97.56 15.101 110.505 15.137 ;
     RECT  25.488 14.909 78.678 15.215 ;
     RECT  7.704 15.019 16.83 15.293 ;
     RECT  67.248 15.215 77.562 15.293 ;
     RECT  90.432 15.101 95.418 15.293 ;
     RECT  7.776 15.293 16.794 15.341 ;
     RECT  20.88 15.137 23.922 15.341 ;
     RECT  67.356 15.293 77.562 15.341 ;
     RECT  97.56 15.137 109.71 15.341 ;
     RECT  67.356 15.341 77.202 15.359 ;
     RECT  7.956 15.341 16.794 15.389 ;
     RECT  20.88 15.341 20.898 15.389 ;
     RECT  21.744 15.341 23.598 15.389 ;
     RECT  25.488 15.215 66.51 15.389 ;
     RECT  67.5 15.359 77.202 15.389 ;
     RECT  81.252 15.137 88.794 15.389 ;
     RECT  90.432 15.293 94.158 15.389 ;
     RECT  95.004 15.293 95.418 15.389 ;
     RECT  97.56 15.341 109.602 15.389 ;
     RECT  12.492 15.389 12.906 15.437 ;
     RECT  33.264 15.389 42.318 15.437 ;
     RECT  67.5 15.389 68.202 15.437 ;
     RECT  71.028 15.389 73.026 15.437 ;
     RECT  74.88 15.389 77.202 15.437 ;
     RECT  78.48 15.215 78.678 15.437 ;
     RECT  48.348 15.389 53.55 15.449 ;
     RECT  64.8 15.389 66.51 15.449 ;
     RECT  69.84 15.389 69.858 15.449 ;
     RECT  43.236 15.389 47.394 15.485 ;
     RECT  48.348 15.449 51.894 15.485 ;
     RECT  55.008 15.389 57.402 15.485 ;
     RECT  58.176 15.389 63.81 15.485 ;
     RECT  64.8 15.449 64.818 15.485 ;
     RECT  93.492 15.389 93.906 15.485 ;
     RECT  43.236 15.485 46.962 15.533 ;
     RECT  38.556 15.437 42.318 15.557 ;
     RECT  56.052 15.485 57.402 15.557 ;
     RECT  33.264 15.437 37.746 15.581 ;
     RECT  68.112 15.437 68.202 15.581 ;
     RECT  78.66 15.437 78.678 15.581 ;
     RECT  56.124 15.557 57.402 15.593 ;
     RECT  58.176 15.485 60.786 15.629 ;
     RECT  25.488 15.389 27.918 15.646 ;
     RECT  55.008 15.485 55.17 15.677 ;
     RECT  56.196 15.593 57.402 15.677 ;
     RECT  48.996 15.485 51.894 15.719 ;
     RECT  62.352 15.485 63.81 15.719 ;
     RECT  56.736 15.677 57.402 15.725 ;
     RECT  38.556 15.557 40.446 15.773 ;
     RECT  59.04 15.629 60.678 15.773 ;
     RECT  34.164 15.581 37.746 15.821 ;
     RECT  59.04 15.773 60.39 15.821 ;
     RECT  22.824 15.389 22.95 15.869 ;
     RECT  71.784 15.437 73.026 15.869 ;
     RECT  61.524 15.485 61.578 15.872 ;
     RECT  22.824 15.869 22.842 15.917 ;
     RECT  43.344 15.533 46.962 15.917 ;
     RECT  25.02 15.646 27.918 15.965 ;
     RECT  41.184 15.557 42.174 15.965 ;
     RECT  43.344 15.917 43.938 15.965 ;
     RECT  48.996 15.719 51.822 15.965 ;
     RECT  57.024 15.725 57.078 15.965 ;
     RECT  59.04 15.821 59.382 15.965 ;
     RECT  71.784 15.869 72.558 15.965 ;
     RECT  10.008 15.389 11.286 16.013 ;
     RECT  12.492 15.437 12.87 16.013 ;
     RECT  15.336 15.389 15.354 16.013 ;
     RECT  29.016 15.389 32.418 16.013 ;
     RECT  38.772 15.773 40.446 16.013 ;
     RECT  45 15.917 46.962 16.013 ;
     RECT  61.524 15.872 61.542 16.013 ;
     RECT  63.108 15.719 63.81 16.013 ;
     RECT  75.168 15.437 76.734 16.013 ;
     RECT  106.884 15.389 106.902 16.013 ;
     RECT  10.008 16.013 10.71 16.061 ;
     RECT  10.008 16.061 10.602 16.109 ;
     RECT  29.088 16.013 32.418 16.171 ;
     RECT  33.264 15.581 33.426 16.171 ;
     RECT  65.628 15.449 66.51 16.171 ;
     RECT  63.288 16.013 63.81 16.214 ;
     RECT  17.928 15.137 17.946 16.231 ;
     RECT  58.176 15.629 58.194 16.253 ;
     RECT  52.668 15.449 53.442 16.259 ;
     RECT  62.352 15.719 62.37 16.259 ;
     RECT  52.992 16.259 53.442 16.295 ;
     RECT  63.756 16.214 63.81 16.295 ;
     RECT  36.54 15.821 37.746 16.301 ;
     RECT  50.94 15.965 51.822 16.331 ;
     RECT  34.164 15.821 35.478 16.349 ;
     RECT  39.132 16.013 40.446 16.349 ;
     RECT  45 16.013 45.558 16.349 ;
     RECT  50.94 16.331 51.606 16.367 ;
     RECT  29.088 16.171 33.426 16.375 ;
     RECT  45 16.349 45.162 16.397 ;
     RECT  59.04 15.965 59.274 16.397 ;
     RECT  46.44 16.013 46.962 16.439 ;
     RECT  36.936 16.301 37.746 16.445 ;
     RECT  29.088 16.375 33.606 16.493 ;
     RECT  41.184 15.965 41.886 16.493 ;
     RECT  29.088 16.493 30.942 16.541 ;
     RECT  39.636 16.349 40.446 16.541 ;
     RECT  41.184 16.493 41.454 16.541 ;
     RECT  43.92 15.965 43.938 16.541 ;
     RECT  104.22 15.389 104.922 16.541 ;
     RECT  10.008 16.109 10.026 16.589 ;
     RECT  12.492 16.013 12.51 16.589 ;
     RECT  17.928 16.231 18.234 16.589 ;
     RECT  31.896 16.493 33.606 16.589 ;
     RECT  39.708 16.541 40.446 16.589 ;
     RECT  46.44 16.439 46.782 16.589 ;
     RECT  48.996 15.965 50.094 16.589 ;
     RECT  51.336 16.367 51.606 16.589 ;
     RECT  55.152 15.677 55.17 16.589 ;
     RECT  60.12 15.821 60.39 16.589 ;
     RECT  71.784 15.965 71.802 16.589 ;
     RECT  85.176 15.389 85.194 16.589 ;
     RECT  95.004 15.389 95.022 16.589 ;
     RECT  104.22 16.541 104.238 16.589 ;
     RECT  34.452 16.349 35.478 16.603 ;
     RECT  68.184 15.581 68.202 16.603 ;
     RECT  25.02 15.965 26.874 16.637 ;
     RECT  29.088 16.541 30.762 16.637 ;
     RECT  31.896 16.589 33.534 16.637 ;
     RECT  63.792 16.295 63.81 16.637 ;
     RECT  64.98 16.171 66.51 16.637 ;
     RECT  86.94 15.389 88.794 16.637 ;
     RECT  83.196 15.389 83.214 16.651 ;
     RECT  34.452 16.603 35.55 16.681 ;
     RECT  25.02 16.637 25.614 16.685 ;
     RECT  26.676 16.637 26.874 16.685 ;
     RECT  46.44 16.589 46.746 16.685 ;
     RECT  86.94 16.637 86.958 16.685 ;
     RECT  83.124 16.651 83.214 16.699 ;
     RECT  26.676 16.685 26.694 16.733 ;
     RECT  36.936 16.445 37.314 16.733 ;
     RECT  60.372 16.589 60.39 16.747 ;
     RECT  70.416 16.699 70.434 16.747 ;
     RECT  83.124 16.699 83.79 16.747 ;
     RECT  78.732 16.699 78.894 16.753 ;
     RECT  68.184 16.603 68.454 16.795 ;
     RECT  69.372 16.726 69.498 16.795 ;
     RECT  75.492 16.013 76.734 16.795 ;
     RECT  77.472 16.651 77.49 16.795 ;
     RECT  78.696 16.753 78.894 16.795 ;
     RECT  34.452 16.681 35.91 16.829 ;
     RECT  68.184 16.795 69.498 16.829 ;
     RECT  75.492 16.795 77.49 16.829 ;
     RECT  78.696 16.795 78.93 16.829 ;
     RECT  22.86 16.747 22.878 16.843 ;
     RECT  40.428 16.589 40.446 16.843 ;
     RECT  83.124 16.747 84.474 16.843 ;
     RECT  34.452 16.829 35.658 16.877 ;
     RECT  64.98 16.637 66.222 16.891 ;
     RECT  82.908 16.843 84.474 16.891 ;
     RECT  30.168 16.637 30.474 16.925 ;
     RECT  31.896 16.637 33.318 16.925 ;
     RECT  34.992 16.877 35.658 16.925 ;
     RECT  78.912 16.829 78.93 16.925 ;
     RECT  25.02 16.685 25.146 16.939 ;
     RECT  70.344 16.747 70.434 16.939 ;
     RECT  72.972 16.699 72.99 16.939 ;
     RECT  40.428 16.843 41.058 16.973 ;
     RECT  72.972 16.939 73.098 16.973 ;
     RECT  82.584 16.891 84.474 16.973 ;
     RECT  27.9 15.965 27.918 16.987 ;
     RECT  22.824 16.843 22.878 17.021 ;
     RECT  32.4 16.925 33.318 17.021 ;
     RECT  34.992 16.925 35.442 17.021 ;
     RECT  44.208 16.843 44.226 17.021 ;
     RECT  60.372 16.747 61.074 17.021 ;
     RECT  68.184 16.829 69.426 17.021 ;
     RECT  75.492 16.829 77.382 17.021 ;
     RECT  22.86 17.021 22.878 17.035 ;
     RECT  68.184 17.021 69.21 17.035 ;
     RECT  99.576 16.939 99.594 17.035 ;
     RECT  24.372 16.939 25.146 17.069 ;
     RECT  64.944 16.891 66.222 17.069 ;
     RECT  67.752 17.035 69.21 17.069 ;
     RECT  75.492 17.021 77.274 17.075 ;
     RECT  36.936 16.733 37.242 17.083 ;
     RECT  29.088 16.637 29.25 17.117 ;
     RECT  48.996 16.589 49.878 17.117 ;
     RECT  82.584 16.973 84.33 17.117 ;
     RECT  18.972 16.939 18.99 17.131 ;
     RECT  73.08 16.973 73.098 17.131 ;
     RECT  79.128 17.083 79.146 17.131 ;
     RECT  79.92 16.939 79.938 17.131 ;
     RECT  90.432 15.389 91.746 17.131 ;
     RECT  65.124 17.069 66.222 17.141 ;
     RECT  36.828 17.083 37.242 17.149 ;
     RECT  70.2 16.939 70.434 17.149 ;
     RECT  17.928 16.589 17.946 17.165 ;
     RECT  27.9 16.987 28.314 17.165 ;
     RECT  30.204 16.925 30.474 17.165 ;
     RECT  35.28 17.021 35.442 17.165 ;
     RECT  40.428 16.973 40.446 17.165 ;
     RECT  46.44 16.685 46.458 17.165 ;
     RECT  49.392 17.117 49.878 17.165 ;
     RECT  51.336 16.589 51.354 17.165 ;
     RECT  57.024 15.965 57.042 17.165 ;
     RECT  59.256 16.397 59.274 17.165 ;
     RECT  60.372 17.021 61.002 17.165 ;
     RECT  65.124 17.141 65.25 17.165 ;
     RECT  67.752 17.069 67.77 17.165 ;
     RECT  68.58 17.069 69.21 17.165 ;
     RECT  70.2 17.149 70.542 17.165 ;
     RECT  75.492 17.075 75.51 17.165 ;
     RECT  76.716 17.075 77.274 17.165 ;
     RECT  83.016 17.117 84.33 17.165 ;
     RECT  86.292 17.035 86.31 17.165 ;
     RECT  87.804 16.637 88.794 17.165 ;
     RECT  90.072 17.131 91.746 17.165 ;
     RECT  93.888 15.485 93.906 17.165 ;
     RECT  94.68 16.939 94.698 17.165 ;
     RECT  99.396 17.035 99.594 17.165 ;
     RECT  18.684 17.131 19.278 17.213 ;
     RECT  24.84 17.069 25.146 17.213 ;
     RECT  30.204 17.165 30.222 17.213 ;
     RECT  32.976 17.021 33.318 17.213 ;
     RECT  43.056 16.939 43.074 17.213 ;
     RECT  53.424 16.295 53.442 17.213 ;
     RECT  79.128 17.131 79.938 17.213 ;
     RECT  81.432 15.389 81.45 17.213 ;
     RECT  87.876 17.165 88.362 17.213 ;
     RECT  36.756 17.149 37.242 17.221 ;
     RECT  25.128 17.213 25.146 17.249 ;
     RECT  32.976 17.213 33.246 17.249 ;
     RECT  49.86 17.165 49.878 17.249 ;
     RECT  90.072 17.165 90.09 17.249 ;
     RECT  19.26 17.213 19.278 17.261 ;
     RECT  22.86 17.035 22.986 17.261 ;
     RECT  29.124 17.117 29.25 17.261 ;
     RECT  33.228 17.249 33.246 17.261 ;
     RECT  36.684 17.221 37.242 17.261 ;
     RECT  45.036 16.397 45.162 17.261 ;
     RECT  60.984 17.165 61.002 17.261 ;
     RECT  66.204 17.141 66.222 17.261 ;
     RECT  69.012 17.165 69.138 17.261 ;
     RECT  70.416 17.165 70.542 17.261 ;
     RECT  73.08 17.131 73.206 17.261 ;
     RECT  77.148 17.165 77.274 17.261 ;
     RECT  79.812 17.213 79.938 17.261 ;
     RECT  88.344 17.213 88.362 17.261 ;
    LAYER M4 ;
     RECT  0.181 9.024 2.408 9.048 ;
     RECT  2.408 2.148 2.512 15.132 ;
     RECT  2.512 2.418 2.704 14.862 ;
     RECT  7.669 14.208 7.693 14.232 ;
     RECT  7.621 15.36 7.693 15.384 ;
     RECT  2.704 9.024 7.808 9.048 ;
     RECT  7.693 14.208 7.808 15.384 ;
     RECT  7.669 17.088 7.859 17.112 ;
     RECT  7.808 2.148 7.912 15.384 ;
     RECT  7.912 2.418 8.104 15.384 ;
     RECT  8.104 8.448 9.097 9.048 ;
     RECT  9.097 7.92 9.53 9.048 ;
     RECT  9.53 7.968 9.676 9.048 ;
     RECT  9.541 12.912 9.677 12.936 ;
     RECT  8.104 13.968 9.893 15.384 ;
     RECT  9.925 1.728 9.989 1.752 ;
     RECT  10.033 4.56 10.141 4.584 ;
     RECT  9.961 6.096 10.141 6.12 ;
     RECT  10.141 4.56 10.253 6.12 ;
     RECT  10.253 4.56 10.309 5.88 ;
     RECT  9.893 14.832 10.321 15.384 ;
     RECT  9.997 16.56 10.321 16.584 ;
     RECT  10.309 4.08 10.357 5.88 ;
     RECT  9.961 0.528 10.393 0.552 ;
     RECT  9.989 1.728 10.501 1.8 ;
     RECT  10.501 1.728 10.573 1.848 ;
     RECT  10.357 3.12 10.573 5.88 ;
     RECT  10.573 1.728 10.613 5.88 ;
     RECT  10.393 0.528 10.835 0.6 ;
     RECT  10.321 14.832 10.835 16.584 ;
     RECT  10.613 1.728 10.853 3.144 ;
     RECT  9.676 7.968 10.933 7.992 ;
     RECT  9.676 9.024 10.933 9.048 ;
     RECT  9.205 11.856 10.933 11.88 ;
     RECT  10.933 7.968 10.94 9.048 ;
     RECT  10.933 11.424 10.981 11.88 ;
     RECT  10.835 14.832 11.123 16.104 ;
     RECT  10.117 13.68 11.365 13.704 ;
     RECT  11.123 14.832 11.365 16.008 ;
     RECT  11.365 13.68 11.507 16.008 ;
     RECT  10.613 4.464 11.509 5.88 ;
     RECT  10.94 7.392 11.509 9.048 ;
     RECT  11.507 13.68 11.581 15.384 ;
     RECT  11.509 4.464 11.795 9.048 ;
     RECT  11.557 0.096 11.801 0.12 ;
     RECT  10.853 1.104 11.941 3.144 ;
     RECT  11.795 4.464 11.941 6.264 ;
     RECT  11.653 10.128 11.977 10.152 ;
     RECT  10.981 11.424 11.977 12.552 ;
     RECT  11.977 10.128 11.987 12.552 ;
     RECT  11.581 13.536 11.989 15.384 ;
     RECT  11.989 13.056 12.035 15.384 ;
     RECT  11.987 10.128 12.053 11.976 ;
     RECT  11.941 1.104 12.083 6.264 ;
     RECT  12.035 14.208 12.083 15.384 ;
     RECT  11.795 7.296 12.089 9.048 ;
     RECT  12.089 7.44 12.133 9.048 ;
     RECT  12.481 16.56 12.755 16.584 ;
     RECT  12.083 14.832 12.841 15.384 ;
     RECT  12.133 7.536 12.949 9.048 ;
     RECT  12.083 1.152 13.043 6.264 ;
     RECT  12.053 10.56 13.093 11.976 ;
     RECT  12.841 14.832 13.139 16.008 ;
     RECT  13.043 1.728 13.208 6.264 ;
     RECT  12.949 7.536 13.208 9.144 ;
     RECT  13.093 10.368 13.208 11.976 ;
     RECT  12.035 13.056 13.208 13.08 ;
     RECT  13.139 14.832 13.208 15.432 ;
     RECT  13.208 1.728 13.235 15.432 ;
     RECT  13.165 0.576 13.429 0.6 ;
     RECT  13.235 1.728 13.504 15.384 ;
     RECT  13.504 1.728 13.637 4.728 ;
     RECT  13.637 1.776 13.753 4.728 ;
     RECT  13.429 0.144 13.861 0.6 ;
     RECT  13.753 2.304 13.889 4.728 ;
     RECT  13.504 5.856 13.889 6.024 ;
     RECT  13.504 7.152 13.889 9.048 ;
     RECT  13.889 2.304 13.925 3 ;
     RECT  13.861 0.096 14.212 0.6 ;
     RECT  13.504 14.832 14.483 15.384 ;
     RECT  13.925 2.304 14.675 2.376 ;
     RECT  13.889 5.856 14.861 5.88 ;
     RECT  13.889 7.344 15.077 9.048 ;
     RECT  15.037 2.88 15.251 2.952 ;
     RECT  15.077 7.344 15.293 7.992 ;
     RECT  14.483 15.168 15.325 15.384 ;
     RECT  15.251 2.928 15.347 2.952 ;
     RECT  14.212 0.096 15.389 0.648 ;
     RECT  14.917 1.728 15.389 1.752 ;
     RECT  15.325 15.168 15.443 16.008 ;
     RECT  13.504 10.224 15.541 10.344 ;
     RECT  15.443 15.168 15.548 15.384 ;
     RECT  13.504 13.056 15.644 13.08 ;
     RECT  15.541 10.224 15.653 10.728 ;
     RECT  15.389 0.096 15.841 1.752 ;
     RECT  15.644 13.056 15.869 13.848 ;
     RECT  15.869 13.824 15.973 13.848 ;
     RECT  15.548 14.832 15.973 15.384 ;
     RECT  15.973 13.824 16.057 15.384 ;
     RECT  15.653 10.32 16.117 10.728 ;
     RECT  13.504 11.952 16.117 11.976 ;
     RECT  15.841 1.104 16.211 1.752 ;
     RECT  15.841 0.096 16.229 0.12 ;
     RECT  16.261 3.408 16.357 3.432 ;
     RECT  16.357 2.88 16.445 3.432 ;
     RECT  16.211 1.68 16.453 1.752 ;
     RECT  16.057 15.216 16.837 15.384 ;
     RECT  16.117 10.32 16.873 11.976 ;
     RECT  16.873 10.272 16.913 11.976 ;
     RECT  16.445 3.408 16.921 3.432 ;
     RECT  16.837 15.216 16.933 16.344 ;
     RECT  16.057 13.824 17.125 13.848 ;
     RECT  16.933 15.216 17.125 17.16 ;
     RECT  16.913 10.272 17.129 10.344 ;
     RECT  16.913 11.376 17.173 11.976 ;
     RECT  17.173 11.376 17.219 12.504 ;
     RECT  17.219 11.664 17.345 12.504 ;
     RECT  17.125 13.824 17.413 17.16 ;
     RECT  16.453 1.68 17.461 2.424 ;
     RECT  16.945 0.528 17.509 0.552 ;
     RECT  13.889 4.704 17.585 4.728 ;
     RECT  17.509 0.096 17.665 0.552 ;
     RECT  15.325 6.816 17.737 6.84 ;
     RECT  17.665 0.096 17.845 0.696 ;
     RECT  17.461 1.68 17.845 2.328 ;
     RECT  17.737 6.288 18.181 6.84 ;
     RECT  17.129 10.32 18.469 10.344 ;
     RECT  17.345 11.664 18.469 11.688 ;
     RECT  17.845 0.096 18.515 2.328 ;
     RECT  18.515 1.728 18.608 2.328 ;
     RECT  17.585 4.272 18.608 4.728 ;
     RECT  18.181 5.808 18.608 6.84 ;
     RECT  15.293 7.968 18.608 7.992 ;
     RECT  15.077 9.024 18.608 9.048 ;
     RECT  18.469 10.32 18.608 11.688 ;
     RECT  17.413 12.864 18.608 17.16 ;
     RECT  18.608 1.728 18.904 17.16 ;
     RECT  18.515 0.096 19.037 0.6 ;
     RECT  19.037 0.096 19.117 0.12 ;
     RECT  18.904 12.816 19.249 17.16 ;
     RECT  18.904 4.704 19.909 4.728 ;
     RECT  18.904 5.808 19.909 5.832 ;
     RECT  18.904 1.728 20.005 1.752 ;
     RECT  20.005 1.728 20.069 1.8 ;
     RECT  20.069 1.152 20.153 1.8 ;
     RECT  20.153 1.2 20.252 1.8 ;
     RECT  20.252 1.2 20.441 2.28 ;
     RECT  19.909 4.512 20.477 5.832 ;
     RECT  20.441 1.728 20.531 2.28 ;
     RECT  20.531 1.728 20.981 1.944 ;
     RECT  20.965 0.096 21.061 0.12 ;
     RECT  20.981 1.728 21.089 1.896 ;
     RECT  21.061 0.096 21.157 0.168 ;
     RECT  20.477 5.808 21.157 5.832 ;
     RECT  18.904 6.816 21.157 6.84 ;
     RECT  21.157 5.808 21.203 6.84 ;
     RECT  18.904 7.968 21.205 7.992 ;
     RECT  18.904 11.376 21.205 11.688 ;
     RECT  21.205 10.464 21.292 11.688 ;
     RECT  21.157 0.096 21.413 0.6 ;
     RECT  21.413 0.144 21.445 0.6 ;
     RECT  21.089 1.728 21.445 1.848 ;
     RECT  18.904 9.024 21.625 9.048 ;
     RECT  21.292 11.376 21.625 11.688 ;
     RECT  21.203 6.048 21.697 6.84 ;
     RECT  21.625 11.376 21.697 11.832 ;
     RECT  19.249 12.816 21.697 17.256 ;
     RECT  21.445 0.144 21.779 1.848 ;
     RECT  21.779 1.728 22.205 1.848 ;
     RECT  21.625 8.4 22.349 9.048 ;
     RECT  21.409 10.176 22.381 10.2 ;
     RECT  21.697 11.376 22.381 17.256 ;
     RECT  21.779 0.144 22.393 0.648 ;
     RECT  22.393 0.144 22.489 0.216 ;
     RECT  22.381 10.176 22.525 17.256 ;
     RECT  20.477 4.512 22.777 4.536 ;
     RECT  22.777 4.512 22.789 4.68 ;
     RECT  22.789 4.512 22.885 4.728 ;
     RECT  21.697 6.048 22.885 7.272 ;
     RECT  23.101 3.072 23.221 3.096 ;
     RECT  22.885 4.512 23.221 7.272 ;
     RECT  22.489 0.096 23.429 0.216 ;
     RECT  23.429 0.096 23.501 0.168 ;
     RECT  22.205 1.728 23.557 1.8 ;
     RECT  23.501 0.096 23.573 0.12 ;
     RECT  23.557 1.728 23.653 1.848 ;
     RECT  23.653 1.728 23.677 1.944 ;
     RECT  23.221 3.072 23.677 7.272 ;
     RECT  23.677 1.728 23.845 7.272 ;
     RECT  23.845 1.68 23.929 7.272 ;
     RECT  23.929 1.584 24.008 7.272 ;
     RECT  22.349 8.928 24.008 9.048 ;
     RECT  22.525 10.032 24.008 17.256 ;
     RECT  24.008 1.584 24.013 17.256 ;
     RECT  24.013 1.728 24.304 17.256 ;
     RECT  24.304 1.728 24.365 9.048 ;
     RECT  24.365 7.92 24.419 9.048 ;
     RECT  24.365 1.728 24.515 6.84 ;
     RECT  24.515 1.728 25.153 6.648 ;
     RECT  25.153 1.104 26.053 6.648 ;
     RECT  24.419 8.4 26.161 9.048 ;
     RECT  26.053 0.144 26.195 6.648 ;
     RECT  26.161 8.4 26.197 9.144 ;
     RECT  24.304 10.176 26.197 17.256 ;
     RECT  26.197 8.4 26.485 17.256 ;
     RECT  26.195 1.728 26.593 6.648 ;
     RECT  26.485 7.728 26.593 17.256 ;
     RECT  26.195 0.144 26.629 0.6 ;
     RECT  26.629 0.096 26.921 0.6 ;
     RECT  26.921 0.096 27.281 0.12 ;
     RECT  26.593 1.728 28.261 17.256 ;
     RECT  28.453 0.096 28.837 0.12 ;
     RECT  28.261 1.152 28.865 17.256 ;
     RECT  28.837 0.096 28.933 0.168 ;
     RECT  28.865 1.728 28.973 17.256 ;
     RECT  28.973 1.776 29.045 17.256 ;
     RECT  29.045 2.016 30.085 17.256 ;
     RECT  28.933 0.096 30.277 0.552 ;
     RECT  30.085 1.728 30.277 17.256 ;
     RECT  30.277 0.096 30.773 17.256 ;
     RECT  30.773 0.096 31.091 0.456 ;
     RECT  30.773 1.728 31.313 17.256 ;
     RECT  31.313 1.728 31.909 9.96 ;
     RECT  31.091 0.096 32.065 0.168 ;
     RECT  31.909 1.152 32.065 9.96 ;
     RECT  32.065 0.096 33.113 9.96 ;
     RECT  33.113 8.928 33.637 9.96 ;
     RECT  31.313 11.136 33.637 17.256 ;
     RECT  33.637 8.928 33.683 17.256 ;
     RECT  33.113 0.096 33.697 7.464 ;
     RECT  33.697 0.096 33.833 7.176 ;
     RECT  33.833 0.096 33.971 1.848 ;
     RECT  33.971 0.096 34.355 0.6 ;
     RECT  33.971 1.632 34.739 1.848 ;
     RECT  34.739 1.728 34.808 1.848 ;
     RECT  33.833 3.024 34.808 7.176 ;
     RECT  33.683 9.024 34.808 17.256 ;
     RECT  34.355 0.528 34.981 0.6 ;
     RECT  34.808 1.728 35.104 17.256 ;
     RECT  34.981 0.528 35.201 0.696 ;
     RECT  35.201 0.528 35.237 0.552 ;
     RECT  35.365 0.096 35.597 0.216 ;
     RECT  35.597 0.192 35.633 0.216 ;
     RECT  35.104 8.784 35.699 17.256 ;
     RECT  36.485 0.576 36.613 0.6 ;
     RECT  36.613 0.576 36.857 0.648 ;
     RECT  35.104 1.728 37.069 7.416 ;
     RECT  37.285 0.096 37.433 0.12 ;
     RECT  35.699 8.784 38.821 9.048 ;
     RECT  35.699 10.032 38.821 17.256 ;
     RECT  39.877 0.576 40.069 0.6 ;
     RECT  37.069 1.728 40.208 7.464 ;
     RECT  38.821 8.784 40.208 17.256 ;
     RECT  40.069 0.576 40.211 0.744 ;
     RECT  40.211 0.576 40.385 0.6 ;
     RECT  40.208 1.728 40.504 17.256 ;
     RECT  40.501 0.144 40.69 0.312 ;
     RECT  40.69 0.096 40.706 0.312 ;
     RECT  40.706 0.096 40.789 0.264 ;
     RECT  40.789 0.144 40.893 0.264 ;
     RECT  40.504 1.728 41.605 7.464 ;
     RECT  40.504 8.784 41.605 9.384 ;
     RECT  40.504 10.608 42.037 17.256 ;
     RECT  41.701 0.576 42.373 0.6 ;
     RECT  41.605 1.728 42.373 9.384 ;
     RECT  42.037 10.464 42.373 17.256 ;
     RECT  42.373 0.096 44.057 0.6 ;
     RECT  42.373 1.728 45.157 17.256 ;
     RECT  44.057 0.096 45.253 0.12 ;
     RECT  45.157 1.152 45.253 17.256 ;
     RECT  45.253 0.096 45.565 17.256 ;
     RECT  45.565 0.048 45.904 17.256 ;
     RECT  45.904 0.048 45.965 1.896 ;
     RECT  45.965 1.728 47.761 1.896 ;
     RECT  45.904 3.024 47.761 17.256 ;
     RECT  47.761 1.728 47.891 17.256 ;
     RECT  47.891 1.728 48.197 1.848 ;
     RECT  45.965 0.048 49.097 0.6 ;
     RECT  47.891 3.024 49.453 17.256 ;
     RECT  48.197 1.728 50.053 1.8 ;
     RECT  49.453 2.784 50.053 17.256 ;
     RECT  49.097 0.048 50.245 0.216 ;
     RECT  50.245 0.048 50.341 0.6 ;
     RECT  50.341 0.048 50.876 0.648 ;
     RECT  50.053 1.728 50.876 17.256 ;
     RECT  50.876 0.048 50.963 17.256 ;
     RECT  50.963 0.048 51.923 0.6 ;
     RECT  50.963 1.728 52.451 17.256 ;
     RECT  51.923 0.048 52.691 0.312 ;
     RECT  52.691 0.048 52.769 0.216 ;
     RECT  52.451 1.728 52.837 17.112 ;
     RECT  52.837 1.392 53.411 17.112 ;
     RECT  52.769 0.096 53.459 0.216 ;
     RECT  53.411 1.392 53.459 17.016 ;
     RECT  53.459 0.096 53.597 0.12 ;
     RECT  53.459 1.392 53.66 16.68 ;
     RECT  53.66 1.104 53.747 16.68 ;
     RECT  53.747 1.392 55.429 16.68 ;
     RECT  55.429 0.576 55.541 16.68 ;
     RECT  55.541 1.392 56.677 16.68 ;
     RECT  57.157 0.288 57.253 0.312 ;
     RECT  57.253 0.192 57.299 0.312 ;
     RECT  57.299 0.192 57.443 0.216 ;
     RECT  56.677 1.392 58.381 17.16 ;
     RECT  58.381 1.152 58.465 17.16 ;
     RECT  58.453 0.144 58.525 0.168 ;
     RECT  58.525 0.096 58.643 0.168 ;
     RECT  58.643 0.144 58.835 0.168 ;
     RECT  58.465 1.728 58.981 17.16 ;
     RECT  58.981 1.728 59.557 17.208 ;
     RECT  59.557 1.68 59.605 17.208 ;
     RECT  59.605 1.68 59.753 17.256 ;
     RECT  60.133 0.096 60.433 0.12 ;
     RECT  60.433 0.096 60.658 0.216 ;
     RECT  59.753 1.728 61.013 17.256 ;
     RECT  60.658 0.096 61.189 0.264 ;
     RECT  61.189 0.096 61.585 0.312 ;
     RECT  61.585 0.096 61.669 0.6 ;
     RECT  61.669 0.096 61.729 0.696 ;
     RECT  61.013 1.728 61.729 17.208 ;
     RECT  61.729 0.096 62.099 17.208 ;
     RECT  62.099 1.68 62.104 17.208 ;
     RECT  62.104 1.68 62.705 1.8 ;
     RECT  62.099 0.096 62.921 0.6 ;
     RECT  62.705 1.68 63.133 1.752 ;
     RECT  62.104 3.024 63.569 17.208 ;
     RECT  62.921 0.096 63.961 0.12 ;
     RECT  63.133 1.104 63.961 1.752 ;
     RECT  63.961 0.096 64.045 1.752 ;
     RECT  64.045 1.104 64.115 1.752 ;
     RECT  64.115 1.728 64.453 1.752 ;
     RECT  64.453 1.728 64.741 2.184 ;
     RECT  63.569 3.312 64.741 17.208 ;
     RECT  64.045 0.096 65.329 0.12 ;
     RECT  65.329 0.096 65.405 0.552 ;
     RECT  65.405 0.528 65.459 0.552 ;
     RECT  64.741 1.728 65.893 17.208 ;
     RECT  65.893 1.152 65.981 17.208 ;
     RECT  65.981 1.728 66.193 17.208 ;
     RECT  67.333 0.096 67.453 0.12 ;
     RECT  67.453 0.096 68.065 0.648 ;
     RECT  66.193 1.728 68.444 17.256 ;
     RECT  68.065 0.096 68.773 0.696 ;
     RECT  68.444 1.68 68.773 17.256 ;
     RECT  68.773 0.096 69.203 17.256 ;
     RECT  69.203 0.096 69.625 0.6 ;
     RECT  69.625 0.096 70.789 0.552 ;
     RECT  70.789 0.096 70.931 0.6 ;
     RECT  69.203 1.728 71.236 17.256 ;
     RECT  70.931 0.576 71.413 0.6 ;
     RECT  71.236 1.68 71.507 17.256 ;
     RECT  71.413 0.576 71.603 0.648 ;
     RECT  71.603 0.624 71.795 0.648 ;
     RECT  72.613 0.096 73.073 0.216 ;
     RECT  71.507 1.728 73.357 17.256 ;
     RECT  73.073 0.096 73.757 0.12 ;
     RECT  74.917 0.096 75.457 0.12 ;
     RECT  73.357 1.104 76.211 17.256 ;
     RECT  76.211 1.728 76.349 17.256 ;
     RECT  76.337 0.576 76.421 0.6 ;
     RECT  76.453 0.096 76.601 0.12 ;
     RECT  76.349 1.728 77.893 2.76 ;
     RECT  76.349 3.84 77.893 17.256 ;
     RECT  77.605 0.576 77.897 0.6 ;
     RECT  78.661 0.096 79.229 0.168 ;
     RECT  79.229 0.096 79.733 0.12 ;
     RECT  80.197 0.576 80.965 0.648 ;
     RECT  80.965 0.096 81.209 0.648 ;
     RECT  81.209 0.144 81.313 0.648 ;
     RECT  77.893 1.728 81.313 17.256 ;
     RECT  81.313 0.144 81.425 17.256 ;
     RECT  81.425 1.152 82.067 17.256 ;
     RECT  81.425 0.144 82.405 0.168 ;
     RECT  82.405 0.144 82.493 0.312 ;
     RECT  82.493 0.096 83.269 0.312 ;
     RECT  83.269 0.096 84.085 0.36 ;
     RECT  84.085 0.096 84.179 0.552 ;
     RECT  84.179 0.096 84.371 0.168 ;
     RECT  84.371 0.096 84.781 0.12 ;
     RECT  82.067 1.728 84.881 17.256 ;
     RECT  84.881 12.72 86.005 17.256 ;
     RECT  85.813 0.048 86.341 0.072 ;
     RECT  84.881 1.728 86.825 11.496 ;
     RECT  86.825 11.472 87.157 11.496 ;
     RECT  86.005 12.48 87.157 17.256 ;
     RECT  87.157 11.472 87.185 17.256 ;
     RECT  86.341 0.048 87.325 0.6 ;
     RECT  86.825 1.728 87.325 10.44 ;
     RECT  87.185 11.472 87.473 11.544 ;
     RECT  87.325 0.048 87.653 10.44 ;
     RECT  87.653 0.048 87.697 7.992 ;
     RECT  87.653 9.072 88.153 10.44 ;
     RECT  87.473 11.472 88.153 11.496 ;
     RECT  87.185 12.528 88.373 17.256 ;
     RECT  88.373 12.528 88.805 17.16 ;
     RECT  87.697 0.048 88.808 7.944 ;
     RECT  88.153 9.072 88.808 11.496 ;
     RECT  88.805 12.528 88.808 16.968 ;
     RECT  88.808 0.048 89.075 16.968 ;
     RECT  89.075 1.68 89.104 15.384 ;
     RECT  89.104 12.768 89.267 15.384 ;
     RECT  89.075 0.048 89.345 0.552 ;
     RECT  89.075 16.512 89.363 16.968 ;
     RECT  89.345 0.144 89.389 0.552 ;
     RECT  89.104 1.68 89.555 8.088 ;
     RECT  89.389 0.48 89.651 0.552 ;
     RECT  89.651 0.528 89.747 0.552 ;
     RECT  89.267 12.768 89.747 15.288 ;
     RECT  89.363 16.8 90.061 16.968 ;
     RECT  89.747 12.768 90.227 15.096 ;
     RECT  90.061 16.8 90.421 17.16 ;
     RECT  90.227 12.768 90.515 13.704 ;
     RECT  90.515 12.768 90.569 13.656 ;
     RECT  90.085 0.576 90.661 0.6 ;
     RECT  89.555 1.728 90.661 8.088 ;
     RECT  90.661 0.576 90.673 8.088 ;
     RECT  89.104 9.792 90.673 10.392 ;
     RECT  90.227 14.784 90.737 15.096 ;
     RECT  90.673 0.576 90.773 10.392 ;
     RECT  89.104 11.472 90.773 11.688 ;
     RECT  90.737 14.784 90.817 15.384 ;
     RECT  90.421 16.512 90.817 17.16 ;
     RECT  90.773 0.576 90.845 11.688 ;
     RECT  90.845 0.096 90.961 11.688 ;
     RECT  90.569 12.768 90.961 13.608 ;
     RECT  90.817 14.784 91.379 17.16 ;
     RECT  90.961 0.096 91.649 13.608 ;
     RECT  91.379 14.784 91.667 16.008 ;
     RECT  91.649 11.52 91.861 13.608 ;
     RECT  91.667 14.784 91.861 15.384 ;
     RECT  91.379 17.136 92.243 17.16 ;
     RECT  91.649 0.096 92.477 10.344 ;
     RECT  91.861 11.52 92.585 15.384 ;
     RECT  92.477 0.576 92.797 10.344 ;
     RECT  92.797 0.576 92.909 10.824 ;
     RECT  92.585 11.856 93.481 15.384 ;
     RECT  93.481 11.856 93.779 15.48 ;
     RECT  93.781 17.088 93.877 17.112 ;
     RECT  92.909 0.576 93.913 10.344 ;
     RECT  93.779 11.856 94.169 15.384 ;
     RECT  93.913 0.048 94.208 10.344 ;
     RECT  94.169 11.856 94.208 15.288 ;
     RECT  94.208 0.048 94.396 15.288 ;
     RECT  93.877 17.088 94.501 17.16 ;
     RECT  94.396 0.048 94.504 15.24 ;
     RECT  94.504 0.048 94.601 7.08 ;
     RECT  94.501 16.848 94.739 17.16 ;
     RECT  94.601 0.048 94.853 5.592 ;
     RECT  94.853 5.184 95.075 5.592 ;
     RECT  94.504 8.208 95.141 10.344 ;
     RECT  95.141 9.936 95.171 10.344 ;
     RECT  94.993 16.56 95.315 16.584 ;
     RECT  94.504 11.952 95.389 15.24 ;
     RECT  94.601 6.672 95.465 7.08 ;
     RECT  95.171 9.936 95.507 9.96 ;
     RECT  95.389 11.952 95.507 15.384 ;
     RECT  95.507 11.952 96.371 15.096 ;
     RECT  96.371 13.824 96.659 15.096 ;
     RECT  96.659 15.072 97.477 15.096 ;
     RECT  94.853 0.048 97.619 3.192 ;
     RECT  97.477 15.072 97.801 15.384 ;
     RECT  96.371 11.952 97.805 12.792 ;
     RECT  97.619 0.048 97.811 3.096 ;
     RECT  97.805 11.952 97.945 12.552 ;
     RECT  95.075 5.568 97.964 5.592 ;
     RECT  95.465 7.056 98.005 7.08 ;
     RECT  97.964 5.376 98.051 5.592 ;
     RECT  98.005 7.056 98.051 7.176 ;
     RECT  97.945 10.848 98.129 12.552 ;
     RECT  98.051 5.568 98.633 5.592 ;
     RECT  98.129 10.848 98.633 10.872 ;
     RECT  97.811 0.048 99.137 2.04 ;
     RECT  99.137 0.144 99.181 2.04 ;
     RECT  95.141 8.208 99.205 8.808 ;
     RECT  99.181 0.24 99.251 2.04 ;
     RECT  96.659 13.824 99.301 13.848 ;
     RECT  98.129 11.952 99.308 12.552 ;
     RECT  99.301 13.584 99.308 13.848 ;
     RECT  99.205 16.848 99.349 16.872 ;
     RECT  99.349 16.848 99.385 17.064 ;
     RECT  98.051 7.152 99.493 7.176 ;
     RECT  99.205 8.208 99.493 9.096 ;
     RECT  99.385 16.848 99.539 17.16 ;
     RECT  99.251 0.528 99.608 2.04 ;
     RECT  97.811 3.072 99.608 3.096 ;
     RECT  99.157 4.848 99.608 5.064 ;
     RECT  99.493 7.152 99.608 9.096 ;
     RECT  99.308 11.616 99.608 13.848 ;
     RECT  97.801 14.832 99.608 15.384 ;
     RECT  99.539 16.896 99.649 17.16 ;
     RECT  99.608 0.528 99.731 15.384 ;
     RECT  99.731 1.68 99.904 15.384 ;
     RECT  99.904 1.68 99.923 3.096 ;
     RECT  99.649 16.896 100.019 17.064 ;
     RECT  100.019 16.992 100.163 17.064 ;
     RECT  99.904 8.208 100.181 8.232 ;
     RECT  99.731 0.528 100.213 0.648 ;
     RECT  100.163 17.04 100.259 17.064 ;
     RECT  99.904 13.008 100.348 13.848 ;
     RECT  100.213 0.48 100.357 0.648 ;
     RECT  99.904 11.952 100.451 11.976 ;
     RECT  100.348 13.056 100.505 13.848 ;
     RECT  99.923 1.728 100.883 3.096 ;
     RECT  99.904 9.504 100.969 10.872 ;
     RECT  100.357 0.096 101.029 0.648 ;
     RECT  100.883 1.728 101.029 1.848 ;
     RECT  101.029 0.096 101.459 1.848 ;
     RECT  101.459 0.144 101.651 1.848 ;
     RECT  99.904 14.832 101.689 15.384 ;
     RECT  101.689 14.208 101.795 15.384 ;
     RECT  100.505 13.056 102.049 13.08 ;
     RECT  99.904 5.04 102.121 5.064 ;
     RECT  101.651 0.576 102.227 1.848 ;
     RECT  102.121 5.04 102.233 5.16 ;
     RECT  102.233 5.04 102.269 5.064 ;
     RECT  102.049 12.144 102.469 13.08 ;
     RECT  99.904 7.056 102.517 7.08 ;
     RECT  100.969 9.12 102.629 10.872 ;
     RECT  102.517 7.056 102.659 8.04 ;
     RECT  102.659 7.056 102.701 7.656 ;
     RECT  102.227 0.576 102.725 0.6 ;
     RECT  100.883 3.072 102.733 3.096 ;
     RECT  102.733 2.832 102.773 3.096 ;
     RECT  102.725 0.096 102.809 0.6 ;
     RECT  102.629 9.12 102.841 9.144 ;
     RECT  102.841 9.024 102.881 9.144 ;
     RECT  102.227 1.728 102.985 1.848 ;
     RECT  102.773 2.832 102.985 2.856 ;
     RECT  101.795 14.832 102.985 15.384 ;
     RECT  102.629 10.128 103.021 10.872 ;
     RECT  102.469 12.144 103.021 13.608 ;
     RECT  102.881 9.024 103.052 9.048 ;
     RECT  103.021 10.128 103.235 13.608 ;
     RECT  103.235 11.952 103.421 13.608 ;
     RECT  103.235 10.128 103.673 10.872 ;
     RECT  102.809 0.576 103.813 0.6 ;
     RECT  102.701 7.632 103.885 7.656 ;
     RECT  103.052 8.88 103.885 9.048 ;
     RECT  102.985 1.728 103.921 2.856 ;
     RECT  103.813 0.096 103.961 0.6 ;
     RECT  103.961 0.576 104.029 0.6 ;
     RECT  103.921 1.728 104.029 3.096 ;
     RECT  104.029 0.576 104.147 3.096 ;
     RECT  103.453 5.616 104.209 5.64 ;
     RECT  104.147 0.576 104.249 0.6 ;
     RECT  103.885 7.632 104.293 9.048 ;
     RECT  104.209 4.704 104.425 5.64 ;
     RECT  104.293 6.672 104.425 9.048 ;
     RECT  104.209 16.56 104.485 16.584 ;
     RECT  103.421 11.952 104.588 13.08 ;
     RECT  102.985 14.736 104.588 15.384 ;
     RECT  103.673 10.128 104.732 10.296 ;
     RECT  104.732 10.128 104.749 10.776 ;
     RECT  104.588 11.952 104.749 15.384 ;
     RECT  104.749 10.128 104.821 15.384 ;
     RECT  104.485 16.56 104.849 17.112 ;
     RECT  104.849 16.512 104.869 17.112 ;
     RECT  104.147 1.728 105.008 3.096 ;
     RECT  104.425 4.704 105.008 9.048 ;
     RECT  104.821 10.032 105.008 15.384 ;
     RECT  104.869 16.416 105.203 17.112 ;
     RECT  105.008 1.728 105.443 15.384 ;
     RECT  105.203 17.088 105.443 17.112 ;
     RECT  105.061 0.144 105.637 0.168 ;
     RECT  105.637 0.144 105.733 0.6 ;
     RECT  105.443 3.936 105.797 15.384 ;
     RECT  105.797 6 105.923 15.384 ;
     RECT  105.443 1.728 106.009 2.952 ;
     RECT  105.923 6 106.013 10.824 ;
     RECT  106.013 6.288 106.019 10.824 ;
     RECT  105.797 3.936 106.06 4.824 ;
     RECT  106.019 6.288 106.085 9.048 ;
     RECT  106.085 6.624 106.121 9.048 ;
     RECT  106.121 6.624 106.157 6.888 ;
     RECT  106.157 6.864 106.193 6.888 ;
     RECT  105.923 11.952 106.252 15.384 ;
     RECT  106.121 7.968 106.265 9.048 ;
     RECT  106.06 3.936 106.337 4.632 ;
     RECT  106.019 10.128 106.337 10.824 ;
     RECT  106.337 10.272 106.445 10.824 ;
     RECT  106.009 1.68 106.693 2.952 ;
     RECT  105.733 0.096 106.789 0.6 ;
     RECT  106.693 1.68 106.789 3.912 ;
     RECT  106.789 0.096 106.841 3.912 ;
     RECT  106.252 14.832 106.873 15.384 ;
     RECT  106.693 17.088 106.883 17.112 ;
     RECT  106.252 11.952 106.921 13.656 ;
     RECT  106.841 0.096 106.985 3.192 ;
     RECT  106.445 10.272 106.985 10.296 ;
     RECT  106.985 0.576 107.021 3.192 ;
     RECT  106.873 14.832 107.219 16.008 ;
     RECT  106.921 11.952 107.309 13.08 ;
     RECT  107.021 1.728 107.381 3.192 ;
     RECT  106.265 8.16 107.485 9.048 ;
     RECT  107.381 1.728 107.699 2.904 ;
     RECT  107.219 14.832 107.699 15.384 ;
     RECT  107.309 11.952 108.133 12.6 ;
     RECT  107.021 0.576 108.179 0.696 ;
     RECT  108.179 0.576 108.397 0.648 ;
     RECT  107.699 2.88 108.493 2.904 ;
     RECT  108.493 2.88 108.659 3.096 ;
     RECT  107.699 1.728 108.709 1.8 ;
     RECT  108.133 11.616 108.713 12.6 ;
     RECT  107.917 13.68 108.713 13.704 ;
     RECT  107.699 14.928 108.764 15.384 ;
     RECT  108.709 1.728 108.851 2.28 ;
     RECT  108.764 14.832 108.851 15.384 ;
     RECT  108.397 0.576 108.997 0.6 ;
     RECT  107.485 8.16 109.253 9.816 ;
     RECT  108.713 11.616 109.433 11.64 ;
     RECT  108.851 14.928 109.613 15.384 ;
     RECT  108.997 0.096 109.717 0.6 ;
     RECT  108.851 1.728 109.717 1.752 ;
     RECT  109.613 14.928 109.721 15.336 ;
     RECT  109.717 0.096 109.811 1.752 ;
     RECT  109.811 1.728 109.925 1.752 ;
     RECT  109.253 8.16 110.401 8.184 ;
     RECT  109.925 1.728 110.408 1.848 ;
     RECT  109.321 6.816 110.408 6.84 ;
     RECT  110.401 7.92 110.408 8.184 ;
     RECT  109.253 9.792 110.408 9.816 ;
     RECT  109.717 11.28 110.408 11.304 ;
     RECT  109.721 14.928 110.408 15.132 ;
     RECT  110.408 1.728 110.512 15.132 ;
     RECT  110.512 1.728 110.704 14.862 ;
     RECT  109.811 0.096 110.876 0.6 ;
     RECT  110.704 1.728 110.876 2.28 ;
     RECT  110.876 0.096 111.449 2.28 ;
     RECT  111.449 1.152 111.665 2.28 ;
     RECT  111.665 1.728 111.737 2.28 ;
     RECT  111.449 0.096 111.961 0.12 ;
     RECT  111.737 1.728 112.133 1.752 ;
    LAYER M5 ;
     RECT  9.936 0.016 112.008 1.187 ;
     RECT  96.912 1.187 112.008 1.235 ;
     RECT  9.936 1.187 33 1.763 ;
     RECT  34.032 1.187 95.88 1.763 ;
     RECT  97.104 1.235 112.008 1.763 ;
     RECT  10.032 1.763 18.912 1.811 ;
     RECT  20.016 1.763 33 1.811 ;
     RECT  39.216 1.763 62.664 1.811 ;
     RECT  77.712 1.763 86.472 1.811 ;
     RECT  87.696 1.763 95.88 1.811 ;
     RECT  109.968 1.763 111.72 1.811 ;
     RECT  20.304 1.811 32.904 1.859 ;
     RECT  34.032 1.763 38.184 1.859 ;
     RECT  39.216 1.811 48.168 1.859 ;
     RECT  97.104 1.763 108.84 1.859 ;
     RECT  109.968 1.811 110.712 1.859 ;
     RECT  20.304 1.859 20.904 1.907 ;
     RECT  39.216 1.859 47.88 1.907 ;
     RECT  49.872 1.811 62.112 1.907 ;
     RECT  20.304 1.907 20.808 1.955 ;
     RECT  64.464 1.763 76.296 1.955 ;
     RECT  77.808 1.811 86.472 1.955 ;
     RECT  97.104 1.859 100.872 2.051 ;
     RECT  2.4 2.137 2.52 2.151 ;
     RECT  7.8 2.137 7.92 2.151 ;
     RECT  34.8 1.859 38.184 2.195 ;
     RECT  64.464 1.955 70.728 2.195 ;
     RECT  71.856 1.955 76.296 2.195 ;
     RECT  34.8 2.195 36.264 2.243 ;
     RECT  37.488 2.195 38.088 2.243 ;
     RECT  77.808 1.955 79.656 2.243 ;
     RECT  20.304 1.955 20.52 2.291 ;
     RECT  22.8 1.859 32.904 2.291 ;
     RECT  34.8 2.243 35.976 2.291 ;
     RECT  37.488 2.243 37.992 2.291 ;
     RECT  39.216 1.907 45.912 2.291 ;
     RECT  47.856 1.907 47.88 2.291 ;
     RECT  51 1.907 62.112 2.291 ;
     RECT  64.752 2.195 70.728 2.291 ;
     RECT  77.808 2.243 79.56 2.291 ;
     RECT  99.6 2.051 100.872 2.291 ;
     RECT  103.056 1.859 108.84 2.291 ;
     RECT  111.696 1.811 111.72 2.291 ;
     RECT  10.32 1.811 18.912 2.339 ;
     RECT  39.216 2.291 43.224 2.339 ;
     RECT  51 2.291 54.024 2.339 ;
     RECT  66.288 2.291 70.728 2.339 ;
     RECT  72.144 2.195 76.296 2.339 ;
     RECT  80.784 1.955 86.472 2.339 ;
     RECT  103.152 2.291 108.648 2.339 ;
     RECT  14.64 2.339 18.912 2.387 ;
     RECT  52.368 2.339 54.024 2.387 ;
     RECT  72.336 2.339 76.296 2.387 ;
     RECT  104.304 2.339 105.432 2.387 ;
     RECT  88.08 1.811 95.88 2.435 ;
     RECT  80.784 2.339 86.184 2.483 ;
     RECT  88.08 2.435 93.096 2.483 ;
     RECT  77.904 2.291 79.56 2.579 ;
     RECT  91.104 2.483 93.096 2.627 ;
     RECT  85.44 2.483 86.184 2.771 ;
     RECT  97.104 2.051 97.8 2.819 ;
     RECT  15.216 2.387 18.912 2.915 ;
     RECT  24 2.291 32.904 2.915 ;
     RECT  37.488 2.291 37.896 2.915 ;
     RECT  40.2 2.339 43.224 2.915 ;
     RECT  49.872 1.907 49.896 2.915 ;
     RECT  52.944 2.387 54.024 2.915 ;
     RECT  66.288 2.339 69.096 2.915 ;
     RECT  70.224 2.339 70.728 2.915 ;
     RECT  72.384 2.387 76.296 2.915 ;
     RECT  77.904 2.579 78.312 2.915 ;
     RECT  79.536 2.579 79.56 2.915 ;
     RECT  94.08 2.435 95.88 2.915 ;
     RECT  106.896 2.339 108.648 2.915 ;
     RECT  15.312 2.915 18.912 2.963 ;
     RECT  37.584 2.915 37.896 2.963 ;
     RECT  37.872 2.963 37.896 3.011 ;
     RECT  88.08 2.483 89.544 3.011 ;
     RECT  94.08 2.915 95.592 3.011 ;
     RECT  97.104 2.819 97.608 3.059 ;
     RECT  104.88 2.387 105.432 3.059 ;
     RECT  106.896 2.915 107.112 3.107 ;
     RECT  108.624 2.915 108.648 3.107 ;
     RECT  97.584 3.059 97.608 3.203 ;
     RECT  25.92 2.915 32.904 3.251 ;
     RECT  66.288 2.915 68.424 3.299 ;
     RECT  55.728 2.291 58.344 3.301 ;
     RECT  59.472 2.291 62.112 3.301 ;
     RECT  70.224 2.915 70.344 3.301 ;
     RECT  55.344 3.301 58.344 3.349 ;
     RECT  59.328 3.301 62.112 3.349 ;
     RECT  45.6 2.291 45.912 3.397 ;
     RECT  16.272 2.963 18.912 3.443 ;
     RECT  25.92 3.251 30.504 3.443 ;
     RECT  53.616 2.915 54.024 3.443 ;
     RECT  55.344 3.349 62.112 3.443 ;
     RECT  66.288 3.299 67.512 3.443 ;
     RECT  70.08 3.301 70.344 3.443 ;
     RECT  75.792 2.915 76.296 3.443 ;
     RECT  31.92 3.251 32.904 3.491 ;
     RECT  25.92 3.443 30.264 3.539 ;
     RECT  80.784 2.483 84.456 3.685 ;
     RECT  85.44 2.771 85.8 3.685 ;
     RECT  45.6 3.397 46.008 3.733 ;
     RECT  80.784 3.685 85.8 3.779 ;
     RECT  32.64 3.491 32.904 3.827 ;
     RECT  64.752 2.291 64.776 3.829 ;
     RECT  22.8 2.291 22.92 3.925 ;
     RECT  24 2.915 24.648 3.925 ;
     RECT  74.64 2.915 74.808 3.925 ;
     RECT  75.792 3.443 76.056 3.925 ;
     RECT  105 3.059 105.432 3.925 ;
     RECT  106.896 3.107 106.92 3.925 ;
     RECT  22.8 3.925 24.648 3.973 ;
     RECT  25.92 3.539 27.768 3.973 ;
     RECT  22.8 3.973 27.768 4.019 ;
     RECT  91.104 2.627 92.616 4.019 ;
     RECT  94.08 3.011 95.064 4.019 ;
     RECT  72.384 2.915 73.656 4.021 ;
     RECT  74.64 3.925 76.056 4.021 ;
     RECT  80.784 3.779 80.808 4.067 ;
     RECT  78 2.915 78.312 4.069 ;
     RECT  10.32 2.339 13.608 4.115 ;
     RECT  51 2.339 51.312 4.117 ;
     RECT  81.936 3.779 85.8 4.117 ;
     RECT  87.264 3.877 87.288 4.117 ;
     RECT  55.824 3.443 62.112 4.211 ;
     RECT  91.104 4.019 91.128 4.213 ;
     RECT  78 4.069 78.792 4.261 ;
     RECT  17.616 3.443 18.912 4.307 ;
     RECT  26.496 4.019 27.768 4.307 ;
     RECT  81.936 4.117 87.288 4.307 ;
     RECT  55.872 4.211 62.112 4.309 ;
     RECT  64.08 3.829 64.776 4.309 ;
     RECT  50.832 4.117 51.312 4.357 ;
     RECT  66.336 3.443 67.512 4.357 ;
     RECT  90.624 4.213 91.128 4.403 ;
     RECT  41.904 2.915 43.224 4.405 ;
     RECT  45.6 3.733 46.104 4.405 ;
     RECT  92.592 4.019 92.616 4.405 ;
     RECT  31.632 4.213 31.656 4.451 ;
     RECT  55.872 4.309 62.76 4.451 ;
     RECT  10.992 4.115 13.608 4.499 ;
     RECT  41.856 4.405 43.224 4.501 ;
     RECT  50.832 4.357 51.48 4.501 ;
     RECT  72.384 4.021 76.056 4.501 ;
     RECT  22.8 4.019 24.984 4.547 ;
     RECT  32.64 3.827 32.808 4.547 ;
     RECT  45.168 4.405 46.104 4.547 ;
     RECT  10.992 4.499 11.112 4.595 ;
     RECT  38.736 3.877 38.76 4.643 ;
     RECT  78 4.261 79.032 4.645 ;
     RECT  53.952 3.443 53.976 4.691 ;
     RECT  80.16 4.117 80.184 4.691 ;
     RECT  22.8 4.547 24.648 4.739 ;
     RECT  88.8 3.011 89.544 4.741 ;
     RECT  50.592 4.501 51.48 4.789 ;
     RECT  40.2 2.915 40.632 4.835 ;
     RECT  99.6 2.291 99.912 4.837 ;
     RECT  50.592 4.789 52.152 4.885 ;
     RECT  64.032 4.309 64.776 4.933 ;
     RECT  88.8 4.741 89.976 4.979 ;
     RECT  34.8 2.291 35.112 5.029 ;
     RECT  32.208 4.789 32.232 5.075 ;
     RECT  37.92 4.981 37.944 5.077 ;
     RECT  70.08 3.443 70.104 5.077 ;
     RECT  77.76 4.645 79.032 5.077 ;
     RECT  81.936 4.307 85.752 5.125 ;
     RECT  19.92 4.501 19.944 5.171 ;
     RECT  54.672 4.933 54.696 5.171 ;
     RECT  22.896 4.739 24.648 5.219 ;
     RECT  26.496 4.307 27.432 5.219 ;
     RECT  94.2 4.019 95.064 5.219 ;
     RECT  66.336 4.357 67.608 5.269 ;
     RECT  69.12 5.077 70.104 5.269 ;
     RECT  72 4.501 76.056 5.269 ;
     RECT  45.6 4.547 46.104 5.461 ;
     RECT  88.8 4.979 89.496 5.507 ;
     RECT  27.168 5.219 27.432 5.509 ;
     RECT  63.888 4.933 64.776 5.509 ;
     RECT  65.808 5.269 67.608 5.557 ;
     RECT  69.12 5.269 76.056 5.557 ;
     RECT  23.232 5.219 24.648 5.605 ;
     RECT  34.8 5.029 36.072 5.605 ;
     RECT  44.496 5.077 44.52 5.605 ;
     RECT  65.808 5.557 76.056 5.651 ;
     RECT  29.088 3.539 30.264 5.653 ;
     RECT  41.76 4.501 43.224 5.701 ;
     RECT  55.872 4.451 62.472 5.701 ;
     RECT  63.888 5.509 64.824 5.701 ;
     RECT  29.04 5.653 30.264 5.749 ;
     RECT  18.6 4.307 18.912 5.797 ;
     RECT  55.344 5.701 62.472 5.797 ;
     RECT  63.888 5.701 65.064 5.797 ;
     RECT  81.312 5.125 85.752 5.845 ;
     RECT  55.344 5.797 65.064 5.987 ;
     RECT  34.8 5.605 36.456 6.037 ;
     RECT  37.584 5.077 37.944 6.037 ;
     RECT  81.312 5.845 86.136 6.037 ;
     RECT  41.76 5.701 43.368 6.083 ;
     RECT  40.2 4.835 40.512 6.085 ;
     RECT  55.872 5.987 65.064 6.179 ;
     RECT  12.096 4.499 13.608 6.181 ;
     RECT  27.168 5.509 27.912 6.181 ;
     RECT  28.944 5.749 30.264 6.181 ;
     RECT  34.8 6.037 37.944 6.181 ;
     RECT  38.928 6.133 38.952 6.181 ;
     RECT  91.104 4.403 91.128 6.181 ;
     RECT  94.2 5.219 94.512 6.181 ;
     RECT  27.168 6.181 30.264 6.227 ;
     RECT  50.304 4.885 52.152 6.229 ;
     RECT  55.872 6.179 65.016 6.275 ;
     RECT  18.192 5.797 18.912 6.323 ;
     RECT  34.8 6.181 38.952 6.323 ;
     RECT  81.216 6.037 86.136 6.373 ;
     RECT  11.76 6.181 13.608 6.517 ;
     RECT  23.232 5.605 25.08 6.563 ;
     RECT  105 3.925 106.92 6.661 ;
     RECT  80.928 6.373 86.136 6.707 ;
     RECT  48.144 6.709 48.168 6.757 ;
     RECT  27.312 6.227 30.264 6.803 ;
     RECT  92.592 4.405 93 6.805 ;
     RECT  27.312 6.803 29.88 6.851 ;
     RECT  66.336 5.651 76.056 6.851 ;
     RECT  44.448 5.605 44.52 6.853 ;
     RECT  45.6 5.461 46.68 6.853 ;
     RECT  11.664 6.517 13.608 6.899 ;
     RECT  34.8 6.323 36.792 6.899 ;
     RECT  37.92 6.323 38.952 6.899 ;
     RECT  66.336 6.851 68.376 6.899 ;
     RECT  81.216 6.707 86.136 7.043 ;
     RECT  98.016 5.365 98.04 7.187 ;
     RECT  55.872 6.275 64.824 7.235 ;
     RECT  66.336 6.899 68.28 7.379 ;
     RECT  40.08 6.085 40.512 7.381 ;
     RECT  103.152 2.339 103.176 7.381 ;
     RECT  34.8 6.899 36.648 7.427 ;
     RECT  92.16 6.805 93 7.427 ;
     RECT  12.096 6.899 13.608 7.475 ;
     RECT  33.648 6.805 33.672 7.475 ;
     RECT  81.216 7.043 86.04 7.475 ;
     RECT  44.448 6.853 46.68 7.669 ;
     RECT  47.856 6.757 48.168 7.669 ;
     RECT  81.216 7.475 85.752 7.909 ;
     RECT  41.76 6.083 42.744 7.957 ;
     RECT  87.264 4.307 87.288 7.957 ;
     RECT  104.304 6.661 106.92 7.957 ;
     RECT  12.48 7.475 13.608 8.003 ;
     RECT  21.168 5.797 21.192 8.003 ;
     RECT  49.344 6.229 52.152 8.003 ;
     RECT  54.672 7.909 54.696 8.005 ;
     RECT  55.872 7.235 57.768 8.005 ;
     RECT  80.832 7.909 85.752 8.051 ;
     RECT  102.624 7.381 103.176 8.051 ;
     RECT  54.672 8.005 57.768 8.147 ;
     RECT  27.888 6.851 29.88 8.195 ;
     RECT  27.888 8.195 28.104 8.341 ;
     RECT  32.496 7.045 32.52 8.435 ;
     RECT  29.4 8.195 29.88 8.485 ;
     RECT  99.168 4.837 99.912 8.485 ;
     RECT  12.624 8.003 13.608 8.579 ;
     RECT  54.672 8.147 57.72 8.579 ;
     RECT  58.896 7.235 64.824 8.579 ;
     RECT  104.208 7.957 106.92 8.579 ;
     RECT  66.336 7.379 67.8 8.581 ;
     RECT  69.504 6.851 76.056 8.581 ;
     RECT  9.6 7.957 9.624 8.675 ;
     RECT  66.336 8.581 76.056 8.675 ;
     RECT  98.736 8.485 99.912 8.819 ;
     RECT  23.232 6.563 24.648 8.917 ;
     RECT  27.312 8.341 28.104 8.917 ;
     RECT  56.256 8.579 57.72 8.963 ;
     RECT  44.448 7.669 48.168 9.061 ;
     RECT  49.44 8.003 52.152 9.061 ;
     RECT  37.92 6.899 38.856 9.109 ;
     RECT  39.936 7.381 40.512 9.109 ;
     RECT  80.832 8.051 85.656 9.155 ;
     RECT  87.264 7.957 87.672 9.155 ;
     RECT  92.832 7.427 93 9.155 ;
     RECT  77.472 5.077 79.032 9.301 ;
     RECT  92.928 9.155 93 9.347 ;
     RECT  54.672 8.579 55.176 9.395 ;
     RECT  33.648 8.917 33.672 9.397 ;
     RECT  34.8 7.427 36.456 9.397 ;
     RECT  80.832 9.155 85.464 9.491 ;
     RECT  26.64 8.917 28.104 9.493 ;
     RECT  77.472 9.301 79.512 9.539 ;
     RECT  77.472 9.539 78.504 9.541 ;
     RECT  94.032 6.181 94.512 9.637 ;
     RECT  104.256 8.579 106.008 9.731 ;
     RECT  92.928 9.347 92.952 9.923 ;
     RECT  53.424 5.893 53.448 9.925 ;
     RECT  94.032 9.637 94.968 9.925 ;
     RECT  29.4 8.485 29.976 10.019 ;
     RECT  99.168 8.819 99.912 10.021 ;
     RECT  103.104 8.051 103.176 10.165 ;
     RECT  33.648 9.397 36.456 10.211 ;
     RECT  23.136 8.917 24.648 10.213 ;
     RECT  104.256 9.731 105.96 10.307 ;
     RECT  18.6 6.323 18.912 10.309 ;
     RECT  34.8 10.211 36.456 10.355 ;
     RECT  90.912 6.181 91.128 10.357 ;
     RECT  13.104 8.579 13.512 10.403 ;
     RECT  56.256 8.963 57.672 10.453 ;
     RECT  103.056 10.165 103.176 10.501 ;
     RECT  66.336 8.675 75.672 10.597 ;
     RECT  76.752 9.541 78.504 10.597 ;
     RECT  30.768 10.405 30.792 10.691 ;
     RECT  84.864 9.491 85.464 10.691 ;
     RECT  66.336 10.597 78.504 10.693 ;
     RECT  87.648 9.155 87.672 10.789 ;
     RECT  88.8 5.507 89.112 10.789 ;
     RECT  86.112 10.693 86.136 10.835 ;
     RECT  26.64 9.493 28.2 10.883 ;
     RECT  44.448 9.061 52.152 10.883 ;
     RECT  33.648 10.211 33.672 10.931 ;
     RECT  53.424 9.925 54.168 10.931 ;
     RECT  55.152 9.395 55.176 10.931 ;
     RECT  53.424 10.931 53.448 10.933 ;
     RECT  102.672 10.501 103.176 10.981 ;
     RECT  27.312 10.883 27.336 11.123 ;
     RECT  37.92 9.109 40.512 11.125 ;
     RECT  41.76 7.957 43.32 11.125 ;
     RECT  34.8 10.355 35.352 11.171 ;
     RECT  36.432 10.355 36.456 11.269 ;
     RECT  37.92 11.125 43.32 11.269 ;
     RECT  59.04 8.579 64.824 11.269 ;
     RECT  66.096 10.693 78.504 11.269 ;
     RECT  59.04 11.269 78.504 11.365 ;
     RECT  80.832 9.491 83.712 11.365 ;
     RECT  53.04 10.933 53.448 11.411 ;
     RECT  29.4 10.019 29.712 11.413 ;
     RECT  90.816 10.357 91.128 11.461 ;
     RECT  87.648 10.789 89.112 11.509 ;
     RECT  28.896 11.413 29.712 11.555 ;
     RECT  22.896 10.213 24.648 11.557 ;
     RECT  44.448 10.883 52.056 11.557 ;
     RECT  56.256 10.453 57.72 11.699 ;
     RECT  90.288 11.461 91.128 11.749 ;
     RECT  22.896 11.557 25.08 11.797 ;
     RECT  26.112 11.125 26.136 11.797 ;
     RECT  22.896 11.797 26.136 11.939 ;
     RECT  10.992 7.381 11.016 11.941 ;
     RECT  12 11.845 12.024 11.941 ;
     RECT  102.672 10.981 103.224 11.941 ;
     RECT  104.784 10.307 105.96 11.941 ;
     RECT  99.168 10.021 100.44 11.987 ;
     RECT  80.832 11.365 83.832 12.035 ;
     RECT  33.744 11.461 33.768 12.037 ;
     RECT  34.8 11.171 35.112 12.037 ;
     RECT  56.256 11.699 57.576 12.085 ;
     RECT  102.672 11.941 106.632 12.179 ;
     RECT  36.432 11.269 43.32 12.181 ;
     RECT  44.304 11.557 52.056 12.181 ;
     RECT  92.496 11.797 92.52 12.229 ;
     RECT  92.496 12.229 92.904 12.325 ;
     RECT  94.032 9.925 95.496 12.325 ;
     RECT  53.424 11.411 53.448 12.421 ;
     RECT  17.184 11.365 17.208 12.515 ;
     RECT  23.232 11.939 26.136 12.517 ;
     RECT  29.4 11.555 29.712 12.517 ;
     RECT  53.328 12.421 53.448 12.517 ;
     RECT  58.944 11.365 78.504 12.517 ;
     RECT  86.016 12.469 86.04 12.517 ;
     RECT  87.168 11.509 89.112 12.517 ;
     RECT  10.992 11.941 12.024 12.563 ;
     RECT  102.672 12.179 105.96 12.563 ;
     RECT  103.104 12.563 105.96 12.611 ;
     RECT  53.28 12.517 54.504 12.661 ;
     RECT  18.48 10.309 18.912 12.805 ;
     RECT  18.48 12.805 19.08 12.853 ;
     RECT  53.088 12.661 54.504 12.901 ;
     RECT  55.872 12.085 57.576 12.901 ;
     RECT  80.976 12.035 83.832 12.901 ;
     RECT  84.864 10.691 84.888 12.901 ;
     RECT  21.216 10.453 21.24 12.949 ;
     RECT  31.296 12.901 31.32 12.949 ;
     RECT  53.088 12.901 57.576 12.949 ;
     RECT  58.8 12.517 78.504 12.949 ;
     RECT  23.232 12.517 26.184 12.997 ;
     RECT  53.088 12.949 78.504 13.043 ;
     RECT  21.216 12.949 21.96 13.045 ;
     RECT  23.04 12.997 26.184 13.045 ;
     RECT  33.744 12.037 35.112 13.045 ;
     RECT  36.432 12.181 52.056 13.045 ;
     RECT  53.088 13.043 54.504 13.045 ;
     RECT  55.536 13.043 78.504 13.093 ;
     RECT  79.488 9.539 79.512 13.093 ;
     RECT  99.168 11.987 100.344 13.139 ;
     RECT  17.424 12.853 19.08 13.141 ;
     RECT  33.744 13.045 35.208 13.189 ;
     RECT  36.432 13.045 54.504 13.333 ;
     RECT  86.016 12.517 89.112 13.379 ;
     RECT  32.496 12.373 32.52 13.381 ;
     RECT  33.552 13.189 35.208 13.381 ;
     RECT  31.296 12.949 31.464 13.429 ;
     RECT  32.496 13.381 35.208 13.429 ;
     RECT  80.976 12.901 84.888 13.429 ;
     RECT  31.296 13.429 35.208 13.525 ;
     RECT  36.24 13.333 54.504 13.525 ;
     RECT  92.496 12.325 95.496 13.573 ;
     RECT  103.152 12.611 105.96 13.573 ;
     RECT  55.536 13.093 79.512 13.621 ;
     RECT  90.288 11.749 91.512 13.621 ;
     RECT  92.496 13.573 96.072 13.621 ;
     RECT  102.48 13.573 105.96 13.621 ;
     RECT  9.552 12.901 9.576 13.669 ;
     RECT  17.424 13.141 19.848 13.669 ;
     RECT  28.8 12.517 29.712 13.765 ;
     RECT  15.696 13.045 15.72 13.859 ;
     RECT  90.288 13.621 96.36 13.909 ;
     RECT  7.8 2.151 8.112 13.957 ;
     RECT  9.552 13.669 10.152 13.957 ;
     RECT  21.216 13.045 22.008 13.957 ;
     RECT  23.04 13.045 26.904 13.957 ;
     RECT  80.976 13.429 85.032 14.005 ;
     RECT  86.016 13.379 87.528 14.005 ;
     RECT  7.8 13.957 10.152 14.197 ;
     RECT  12 12.563 12.024 14.197 ;
     RECT  17.424 13.669 20.136 14.197 ;
     RECT  21.216 13.957 26.904 14.197 ;
     RECT  28.512 13.765 29.712 14.197 ;
     RECT  90.192 13.909 96.36 14.197 ;
     RECT  102.48 13.621 106.872 14.197 ;
     RECT  17.424 14.197 26.904 14.387 ;
     RECT  88.656 13.379 89.112 14.437 ;
     RECT  90.192 14.197 96.648 14.437 ;
     RECT  0.192 9.013 0.216 14.483 ;
     RECT  55.536 13.621 79.704 14.485 ;
     RECT  80.976 14.005 87.528 14.485 ;
     RECT  27.888 14.197 29.712 14.533 ;
     RECT  17.424 14.387 19.848 14.677 ;
     RECT  7.68 14.197 10.152 14.821 ;
     RECT  11.76 14.197 12.072 14.821 ;
     RECT  13.2 10.403 13.512 14.821 ;
     RECT  15.984 14.773 16.008 14.821 ;
     RECT  20.88 14.387 26.904 14.821 ;
     RECT  27.888 14.533 29.88 14.821 ;
     RECT  31.296 13.525 54.504 14.821 ;
     RECT  99.168 13.139 100.296 14.821 ;
     RECT  101.76 14.197 106.872 14.821 ;
     RECT  20.88 14.821 54.504 14.917 ;
     RECT  55.536 14.485 87.528 14.917 ;
     RECT  97.872 14.821 97.896 14.917 ;
     RECT  99.12 14.821 107.688 14.917 ;
     RECT  108.816 14.821 108.84 14.917 ;
     RECT  110.4 1.859 110.712 14.917 ;
     RECT  97.872 14.917 97.992 15.061 ;
     RECT  99.12 14.917 110.712 15.061 ;
     RECT  2.4 2.151 2.712 15.129 ;
     RECT  97.776 15.061 110.712 15.129 ;
     RECT  2.4 15.129 2.52 15.143 ;
     RECT  97.776 15.129 110.52 15.143 ;
     RECT  7.68 14.821 14.472 15.157 ;
     RECT  15.6 14.821 16.008 15.157 ;
     RECT  7.68 15.157 16.008 15.205 ;
     RECT  17.136 14.677 19.848 15.205 ;
     RECT  88.656 14.437 96.648 15.301 ;
     RECT  97.776 15.143 109.704 15.301 ;
     RECT  7.68 15.205 19.848 15.349 ;
     RECT  20.88 14.917 87.528 15.349 ;
     RECT  7.632 15.349 87.528 16.549 ;
     RECT  88.656 15.301 109.704 16.549 ;
     RECT  7.632 16.549 109.704 17.232 ;
     RECT  33.12 17.232 33.144 17.267 ;
     RECT  37.056 17.232 37.08 17.267 ;
     RECT  52.416 17.232 52.44 17.267 ;
     RECT  59.616 17.232 59.64 17.267 ;
  END
END ot_pqc_t_xin
END LIBRARY
